VERSION 5.8 ;
BUSBITCHARS "[]" ;
DIVIDERCHAR "/" ;
UNITS
    DATABASE MICRONS 1000 ;
END UNITS

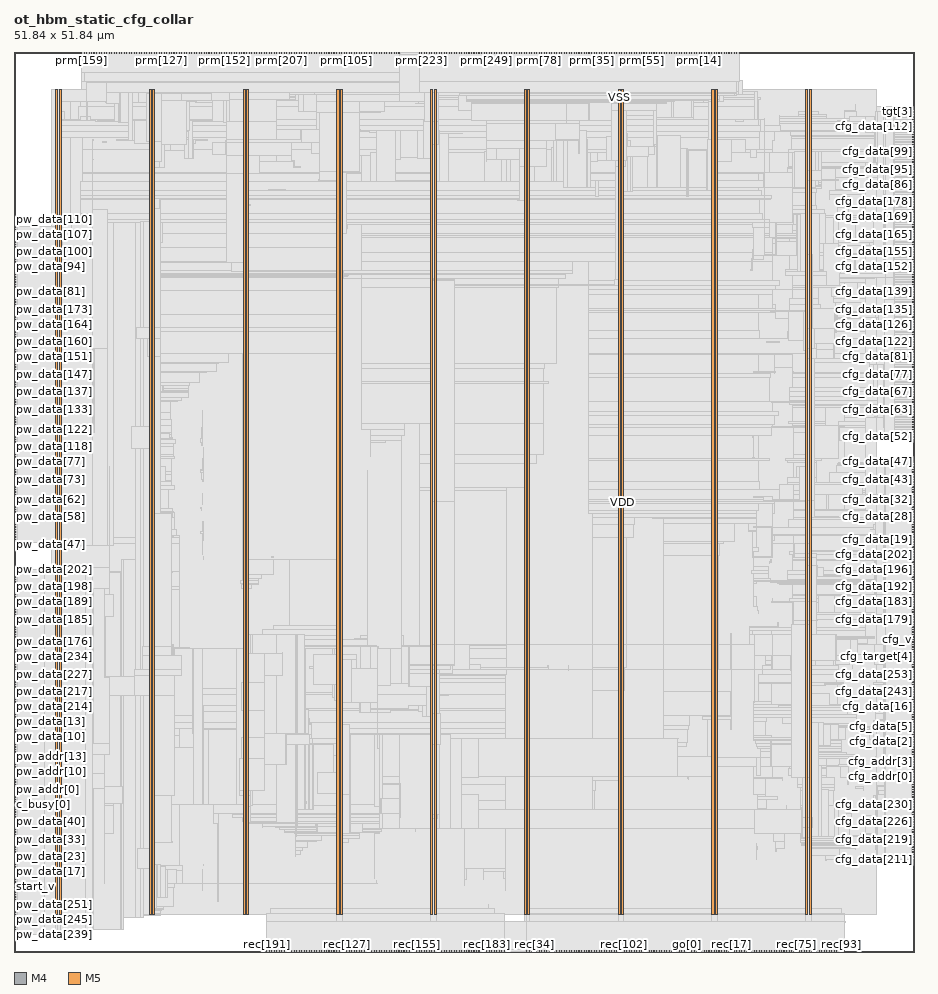
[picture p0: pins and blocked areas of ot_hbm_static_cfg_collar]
MACRO ot_hbm_static_cfg_collar
  FOREIGN ot_hbm_static_cfg_collar 0 0 ;
  CLASS BLOCK ;
  SIZE 51.84 BY 51.84 ;
  PIN active
    DIRECTION OUTPUT ;
    USE SIGNAL ;
    PORT
      LAYER M4 ;
        RECT  51.756 9.936 51.84 9.96 ;
    END
  END active
  PIN c_busy[0]
    DIRECTION INPUT ;
    USE SIGNAL ;
    PORT
      LAYER M4 ;
        RECT  0 8.496 0.084 8.52 ;
    END
  END c_busy[0]
  PIN c_busy[1]
    DIRECTION INPUT ;
    USE SIGNAL ;
    PORT
      LAYER M4 ;
        RECT  0 8.64 0.084 8.664 ;
    END
  END c_busy[1]
  PIN c_done
    DIRECTION INPUT ;
    USE SIGNAL ;
    PORT
      LAYER M4 ;
        RECT  0 8.784 0.084 8.808 ;
    END
  END c_done
  PIN c_fault[0]
    DIRECTION INPUT ;
    USE SIGNAL ;
    PORT
      LAYER M5 ;
        RECT  37.296 51.756 37.32 51.84 ;
    END
  END c_fault[0]
  PIN cfg_addr[0]
    DIRECTION INPUT ;
    USE SIGNAL ;
    PORT
      LAYER M4 ;
        RECT  51.756 10.08 51.84 10.104 ;
    END
  END cfg_addr[0]
  PIN cfg_addr[10]
    DIRECTION INPUT ;
    USE SIGNAL ;
    PORT
      LAYER M4 ;
        RECT  51.756 11.52 51.84 11.544 ;
    END
  END cfg_addr[10]
  PIN cfg_addr[11]
    DIRECTION INPUT ;
    USE SIGNAL ;
    PORT
      LAYER M4 ;
        RECT  51.756 11.664 51.84 11.688 ;
    END
  END cfg_addr[11]
  PIN cfg_addr[1]
    DIRECTION INPUT ;
    USE SIGNAL ;
    PORT
      LAYER M4 ;
        RECT  51.756 10.224 51.84 10.248 ;
    END
  END cfg_addr[1]
  PIN cfg_addr[2]
    DIRECTION INPUT ;
    USE SIGNAL ;
    PORT
      LAYER M4 ;
        RECT  51.756 10.368 51.84 10.392 ;
    END
  END cfg_addr[2]
  PIN cfg_addr[3]
    DIRECTION INPUT ;
    USE SIGNAL ;
    PORT
      LAYER M4 ;
        RECT  51.756 10.512 51.84 10.536 ;
    END
  END cfg_addr[3]
  PIN cfg_addr[4]
    DIRECTION INPUT ;
    USE SIGNAL ;
    PORT
      LAYER M4 ;
        RECT  51.756 10.656 51.84 10.68 ;
    END
  END cfg_addr[4]
  PIN cfg_addr[5]
    DIRECTION INPUT ;
    USE SIGNAL ;
    PORT
      LAYER M4 ;
        RECT  51.756 10.8 51.84 10.824 ;
    END
  END cfg_addr[5]
  PIN cfg_addr[6]
    DIRECTION INPUT ;
    USE SIGNAL ;
    PORT
      LAYER M4 ;
        RECT  51.756 10.944 51.84 10.968 ;
    END
  END cfg_addr[6]
  PIN cfg_addr[7]
    DIRECTION INPUT ;
    USE SIGNAL ;
    PORT
      LAYER M4 ;
        RECT  51.756 11.088 51.84 11.112 ;
    END
  END cfg_addr[7]
  PIN cfg_addr[8]
    DIRECTION INPUT ;
    USE SIGNAL ;
    PORT
      LAYER M4 ;
        RECT  51.756 11.232 51.84 11.256 ;
    END
  END cfg_addr[8]
  PIN cfg_addr[9]
    DIRECTION INPUT ;
    USE SIGNAL ;
    PORT
      LAYER M4 ;
        RECT  51.756 11.376 51.84 11.4 ;
    END
  END cfg_addr[9]
  PIN cfg_data[0]
    DIRECTION INPUT ;
    USE SIGNAL ;
    PORT
      LAYER M4 ;
        RECT  51.756 11.808 51.84 11.832 ;
    END
  END cfg_data[0]
  PIN cfg_data[100]
    DIRECTION INPUT ;
    USE SIGNAL ;
    PORT
      LAYER M4 ;
        RECT  51.756 45.792 51.84 45.816 ;
    END
  END cfg_data[100]
  PIN cfg_data[101]
    DIRECTION INPUT ;
    USE SIGNAL ;
    PORT
      LAYER M4 ;
        RECT  51.756 45.936 51.84 45.96 ;
    END
  END cfg_data[101]
  PIN cfg_data[102]
    DIRECTION INPUT ;
    USE SIGNAL ;
    PORT
      LAYER M4 ;
        RECT  51.756 46.08 51.84 46.104 ;
    END
  END cfg_data[102]
  PIN cfg_data[103]
    DIRECTION INPUT ;
    USE SIGNAL ;
    PORT
      LAYER M4 ;
        RECT  51.756 46.224 51.84 46.248 ;
    END
  END cfg_data[103]
  PIN cfg_data[104]
    DIRECTION INPUT ;
    USE SIGNAL ;
    PORT
      LAYER M4 ;
        RECT  51.756 46.368 51.84 46.392 ;
    END
  END cfg_data[104]
  PIN cfg_data[105]
    DIRECTION INPUT ;
    USE SIGNAL ;
    PORT
      LAYER M4 ;
        RECT  51.756 46.512 51.84 46.536 ;
    END
  END cfg_data[105]
  PIN cfg_data[106]
    DIRECTION INPUT ;
    USE SIGNAL ;
    PORT
      LAYER M4 ;
        RECT  51.756 46.656 51.84 46.68 ;
    END
  END cfg_data[106]
  PIN cfg_data[107]
    DIRECTION INPUT ;
    USE SIGNAL ;
    PORT
      LAYER M4 ;
        RECT  51.756 46.8 51.84 46.824 ;
    END
  END cfg_data[107]
  PIN cfg_data[108]
    DIRECTION INPUT ;
    USE SIGNAL ;
    PORT
      LAYER M4 ;
        RECT  51.756 46.944 51.84 46.968 ;
    END
  END cfg_data[108]
  PIN cfg_data[109]
    DIRECTION INPUT ;
    USE SIGNAL ;
    PORT
      LAYER M4 ;
        RECT  51.756 47.088 51.84 47.112 ;
    END
  END cfg_data[109]
  PIN cfg_data[10]
    DIRECTION INPUT ;
    USE SIGNAL ;
    PORT
      LAYER M4 ;
        RECT  51.756 13.248 51.84 13.272 ;
    END
  END cfg_data[10]
  PIN cfg_data[110]
    DIRECTION INPUT ;
    USE SIGNAL ;
    PORT
      LAYER M4 ;
        RECT  51.756 47.232 51.84 47.256 ;
    END
  END cfg_data[110]
  PIN cfg_data[111]
    DIRECTION INPUT ;
    USE SIGNAL ;
    PORT
      LAYER M4 ;
        RECT  51.756 47.376 51.84 47.4 ;
    END
  END cfg_data[111]
  PIN cfg_data[112]
    DIRECTION INPUT ;
    USE SIGNAL ;
    PORT
      LAYER M4 ;
        RECT  51.756 47.52 51.84 47.544 ;
    END
  END cfg_data[112]
  PIN cfg_data[113]
    DIRECTION INPUT ;
    USE SIGNAL ;
    PORT
      LAYER M4 ;
        RECT  51.756 47.664 51.84 47.688 ;
    END
  END cfg_data[113]
  PIN cfg_data[114]
    DIRECTION INPUT ;
    USE SIGNAL ;
    PORT
      LAYER M4 ;
        RECT  51.756 47.808 51.84 47.832 ;
    END
  END cfg_data[114]
  PIN cfg_data[115]
    DIRECTION INPUT ;
    USE SIGNAL ;
    PORT
      LAYER M4 ;
        RECT  51.756 34.128 51.84 34.152 ;
    END
  END cfg_data[115]
  PIN cfg_data[116]
    DIRECTION INPUT ;
    USE SIGNAL ;
    PORT
      LAYER M4 ;
        RECT  51.756 34.272 51.84 34.296 ;
    END
  END cfg_data[116]
  PIN cfg_data[117]
    DIRECTION INPUT ;
    USE SIGNAL ;
    PORT
      LAYER M4 ;
        RECT  51.756 34.416 51.84 34.44 ;
    END
  END cfg_data[117]
  PIN cfg_data[118]
    DIRECTION INPUT ;
    USE SIGNAL ;
    PORT
      LAYER M4 ;
        RECT  51.756 34.56 51.84 34.584 ;
    END
  END cfg_data[118]
  PIN cfg_data[119]
    DIRECTION INPUT ;
    USE SIGNAL ;
    PORT
      LAYER M4 ;
        RECT  51.756 34.704 51.84 34.728 ;
    END
  END cfg_data[119]
  PIN cfg_data[11]
    DIRECTION INPUT ;
    USE SIGNAL ;
    PORT
      LAYER M4 ;
        RECT  51.756 13.392 51.84 13.416 ;
    END
  END cfg_data[11]
  PIN cfg_data[120]
    DIRECTION INPUT ;
    USE SIGNAL ;
    PORT
      LAYER M4 ;
        RECT  51.756 34.848 51.84 34.872 ;
    END
  END cfg_data[120]
  PIN cfg_data[121]
    DIRECTION INPUT ;
    USE SIGNAL ;
    PORT
      LAYER M4 ;
        RECT  51.756 34.992 51.84 35.016 ;
    END
  END cfg_data[121]
  PIN cfg_data[122]
    DIRECTION INPUT ;
    USE SIGNAL ;
    PORT
      LAYER M4 ;
        RECT  51.756 35.136 51.84 35.16 ;
    END
  END cfg_data[122]
  PIN cfg_data[123]
    DIRECTION INPUT ;
    USE SIGNAL ;
    PORT
      LAYER M4 ;
        RECT  51.756 35.28 51.84 35.304 ;
    END
  END cfg_data[123]
  PIN cfg_data[124]
    DIRECTION INPUT ;
    USE SIGNAL ;
    PORT
      LAYER M4 ;
        RECT  51.756 35.424 51.84 35.448 ;
    END
  END cfg_data[124]
  PIN cfg_data[125]
    DIRECTION INPUT ;
    USE SIGNAL ;
    PORT
      LAYER M4 ;
        RECT  51.756 35.568 51.84 35.592 ;
    END
  END cfg_data[125]
  PIN cfg_data[126]
    DIRECTION INPUT ;
    USE SIGNAL ;
    PORT
      LAYER M4 ;
        RECT  51.756 35.712 51.84 35.736 ;
    END
  END cfg_data[126]
  PIN cfg_data[127]
    DIRECTION INPUT ;
    USE SIGNAL ;
    PORT
      LAYER M4 ;
        RECT  51.756 35.856 51.84 35.88 ;
    END
  END cfg_data[127]
  PIN cfg_data[128]
    DIRECTION INPUT ;
    USE SIGNAL ;
    PORT
      LAYER M4 ;
        RECT  51.756 36 51.84 36.024 ;
    END
  END cfg_data[128]
  PIN cfg_data[129]
    DIRECTION INPUT ;
    USE SIGNAL ;
    PORT
      LAYER M4 ;
        RECT  51.756 36.144 51.84 36.168 ;
    END
  END cfg_data[129]
  PIN cfg_data[12]
    DIRECTION INPUT ;
    USE SIGNAL ;
    PORT
      LAYER M4 ;
        RECT  51.756 13.536 51.84 13.56 ;
    END
  END cfg_data[12]
  PIN cfg_data[130]
    DIRECTION INPUT ;
    USE SIGNAL ;
    PORT
      LAYER M4 ;
        RECT  51.756 36.288 51.84 36.312 ;
    END
  END cfg_data[130]
  PIN cfg_data[131]
    DIRECTION INPUT ;
    USE SIGNAL ;
    PORT
      LAYER M4 ;
        RECT  51.756 36.432 51.84 36.456 ;
    END
  END cfg_data[131]
  PIN cfg_data[132]
    DIRECTION INPUT ;
    USE SIGNAL ;
    PORT
      LAYER M4 ;
        RECT  51.756 36.576 51.84 36.6 ;
    END
  END cfg_data[132]
  PIN cfg_data[133]
    DIRECTION INPUT ;
    USE SIGNAL ;
    PORT
      LAYER M4 ;
        RECT  51.756 36.72 51.84 36.744 ;
    END
  END cfg_data[133]
  PIN cfg_data[134]
    DIRECTION INPUT ;
    USE SIGNAL ;
    PORT
      LAYER M4 ;
        RECT  51.756 36.864 51.84 36.888 ;
    END
  END cfg_data[134]
  PIN cfg_data[135]
    DIRECTION INPUT ;
    USE SIGNAL ;
    PORT
      LAYER M4 ;
        RECT  51.756 37.008 51.84 37.032 ;
    END
  END cfg_data[135]
  PIN cfg_data[136]
    DIRECTION INPUT ;
    USE SIGNAL ;
    PORT
      LAYER M4 ;
        RECT  51.756 37.152 51.84 37.176 ;
    END
  END cfg_data[136]
  PIN cfg_data[137]
    DIRECTION INPUT ;
    USE SIGNAL ;
    PORT
      LAYER M4 ;
        RECT  51.756 37.296 51.84 37.32 ;
    END
  END cfg_data[137]
  PIN cfg_data[138]
    DIRECTION INPUT ;
    USE SIGNAL ;
    PORT
      LAYER M4 ;
        RECT  51.756 37.44 51.84 37.464 ;
    END
  END cfg_data[138]
  PIN cfg_data[139]
    DIRECTION INPUT ;
    USE SIGNAL ;
    PORT
      LAYER M4 ;
        RECT  51.756 37.584 51.84 37.608 ;
    END
  END cfg_data[139]
  PIN cfg_data[13]
    DIRECTION INPUT ;
    USE SIGNAL ;
    PORT
      LAYER M4 ;
        RECT  51.756 13.68 51.84 13.704 ;
    END
  END cfg_data[13]
  PIN cfg_data[140]
    DIRECTION INPUT ;
    USE SIGNAL ;
    PORT
      LAYER M4 ;
        RECT  51.756 37.728 51.84 37.752 ;
    END
  END cfg_data[140]
  PIN cfg_data[141]
    DIRECTION INPUT ;
    USE SIGNAL ;
    PORT
      LAYER M4 ;
        RECT  51.756 37.872 51.84 37.896 ;
    END
  END cfg_data[141]
  PIN cfg_data[142]
    DIRECTION INPUT ;
    USE SIGNAL ;
    PORT
      LAYER M4 ;
        RECT  51.756 38.016 51.84 38.04 ;
    END
  END cfg_data[142]
  PIN cfg_data[143]
    DIRECTION INPUT ;
    USE SIGNAL ;
    PORT
      LAYER M4 ;
        RECT  51.756 38.16 51.84 38.184 ;
    END
  END cfg_data[143]
  PIN cfg_data[144]
    DIRECTION INPUT ;
    USE SIGNAL ;
    PORT
      LAYER M4 ;
        RECT  51.756 38.304 51.84 38.328 ;
    END
  END cfg_data[144]
  PIN cfg_data[145]
    DIRECTION INPUT ;
    USE SIGNAL ;
    PORT
      LAYER M4 ;
        RECT  51.756 38.448 51.84 38.472 ;
    END
  END cfg_data[145]
  PIN cfg_data[146]
    DIRECTION INPUT ;
    USE SIGNAL ;
    PORT
      LAYER M4 ;
        RECT  51.756 38.592 51.84 38.616 ;
    END
  END cfg_data[146]
  PIN cfg_data[147]
    DIRECTION INPUT ;
    USE SIGNAL ;
    PORT
      LAYER M4 ;
        RECT  51.756 38.736 51.84 38.76 ;
    END
  END cfg_data[147]
  PIN cfg_data[148]
    DIRECTION INPUT ;
    USE SIGNAL ;
    PORT
      LAYER M4 ;
        RECT  51.756 38.88 51.84 38.904 ;
    END
  END cfg_data[148]
  PIN cfg_data[149]
    DIRECTION INPUT ;
    USE SIGNAL ;
    PORT
      LAYER M4 ;
        RECT  51.756 39.024 51.84 39.048 ;
    END
  END cfg_data[149]
  PIN cfg_data[14]
    DIRECTION INPUT ;
    USE SIGNAL ;
    PORT
      LAYER M4 ;
        RECT  51.756 13.824 51.84 13.848 ;
    END
  END cfg_data[14]
  PIN cfg_data[150]
    DIRECTION INPUT ;
    USE SIGNAL ;
    PORT
      LAYER M4 ;
        RECT  51.756 39.168 51.84 39.192 ;
    END
  END cfg_data[150]
  PIN cfg_data[151]
    DIRECTION INPUT ;
    USE SIGNAL ;
    PORT
      LAYER M4 ;
        RECT  51.756 39.312 51.84 39.336 ;
    END
  END cfg_data[151]
  PIN cfg_data[152]
    DIRECTION INPUT ;
    USE SIGNAL ;
    PORT
      LAYER M4 ;
        RECT  51.756 39.456 51.84 39.48 ;
    END
  END cfg_data[152]
  PIN cfg_data[153]
    DIRECTION INPUT ;
    USE SIGNAL ;
    PORT
      LAYER M4 ;
        RECT  51.756 39.6 51.84 39.624 ;
    END
  END cfg_data[153]
  PIN cfg_data[154]
    DIRECTION INPUT ;
    USE SIGNAL ;
    PORT
      LAYER M4 ;
        RECT  51.756 39.744 51.84 39.768 ;
    END
  END cfg_data[154]
  PIN cfg_data[155]
    DIRECTION INPUT ;
    USE SIGNAL ;
    PORT
      LAYER M4 ;
        RECT  51.756 39.888 51.84 39.912 ;
    END
  END cfg_data[155]
  PIN cfg_data[156]
    DIRECTION INPUT ;
    USE SIGNAL ;
    PORT
      LAYER M4 ;
        RECT  51.756 40.032 51.84 40.056 ;
    END
  END cfg_data[156]
  PIN cfg_data[157]
    DIRECTION INPUT ;
    USE SIGNAL ;
    PORT
      LAYER M4 ;
        RECT  51.756 40.176 51.84 40.2 ;
    END
  END cfg_data[157]
  PIN cfg_data[158]
    DIRECTION INPUT ;
    USE SIGNAL ;
    PORT
      LAYER M4 ;
        RECT  51.756 40.32 51.84 40.344 ;
    END
  END cfg_data[158]
  PIN cfg_data[159]
    DIRECTION INPUT ;
    USE SIGNAL ;
    PORT
      LAYER M4 ;
        RECT  51.756 40.464 51.84 40.488 ;
    END
  END cfg_data[159]
  PIN cfg_data[15]
    DIRECTION INPUT ;
    USE SIGNAL ;
    PORT
      LAYER M4 ;
        RECT  51.756 13.968 51.84 13.992 ;
    END
  END cfg_data[15]
  PIN cfg_data[160]
    DIRECTION INPUT ;
    USE SIGNAL ;
    PORT
      LAYER M4 ;
        RECT  51.756 40.608 51.84 40.632 ;
    END
  END cfg_data[160]
  PIN cfg_data[161]
    DIRECTION INPUT ;
    USE SIGNAL ;
    PORT
      LAYER M4 ;
        RECT  51.756 40.752 51.84 40.776 ;
    END
  END cfg_data[161]
  PIN cfg_data[162]
    DIRECTION INPUT ;
    USE SIGNAL ;
    PORT
      LAYER M4 ;
        RECT  51.756 40.896 51.84 40.92 ;
    END
  END cfg_data[162]
  PIN cfg_data[163]
    DIRECTION INPUT ;
    USE SIGNAL ;
    PORT
      LAYER M4 ;
        RECT  51.756 41.04 51.84 41.064 ;
    END
  END cfg_data[163]
  PIN cfg_data[164]
    DIRECTION INPUT ;
    USE SIGNAL ;
    PORT
      LAYER M4 ;
        RECT  51.756 41.184 51.84 41.208 ;
    END
  END cfg_data[164]
  PIN cfg_data[165]
    DIRECTION INPUT ;
    USE SIGNAL ;
    PORT
      LAYER M4 ;
        RECT  51.756 41.328 51.84 41.352 ;
    END
  END cfg_data[165]
  PIN cfg_data[166]
    DIRECTION INPUT ;
    USE SIGNAL ;
    PORT
      LAYER M4 ;
        RECT  51.756 41.472 51.84 41.496 ;
    END
  END cfg_data[166]
  PIN cfg_data[167]
    DIRECTION INPUT ;
    USE SIGNAL ;
    PORT
      LAYER M4 ;
        RECT  51.756 41.616 51.84 41.64 ;
    END
  END cfg_data[167]
  PIN cfg_data[168]
    DIRECTION INPUT ;
    USE SIGNAL ;
    PORT
      LAYER M4 ;
        RECT  51.756 41.76 51.84 41.784 ;
    END
  END cfg_data[168]
  PIN cfg_data[169]
    DIRECTION INPUT ;
    USE SIGNAL ;
    PORT
      LAYER M4 ;
        RECT  51.756 41.904 51.84 41.928 ;
    END
  END cfg_data[169]
  PIN cfg_data[16]
    DIRECTION INPUT ;
    USE SIGNAL ;
    PORT
      LAYER M4 ;
        RECT  51.756 14.112 51.84 14.136 ;
    END
  END cfg_data[16]
  PIN cfg_data[170]
    DIRECTION INPUT ;
    USE SIGNAL ;
    PORT
      LAYER M4 ;
        RECT  51.756 42.048 51.84 42.072 ;
    END
  END cfg_data[170]
  PIN cfg_data[171]
    DIRECTION INPUT ;
    USE SIGNAL ;
    PORT
      LAYER M4 ;
        RECT  51.756 42.192 51.84 42.216 ;
    END
  END cfg_data[171]
  PIN cfg_data[172]
    DIRECTION INPUT ;
    USE SIGNAL ;
    PORT
      LAYER M4 ;
        RECT  51.756 42.336 51.84 42.36 ;
    END
  END cfg_data[172]
  PIN cfg_data[173]
    DIRECTION INPUT ;
    USE SIGNAL ;
    PORT
      LAYER M4 ;
        RECT  51.756 42.48 51.84 42.504 ;
    END
  END cfg_data[173]
  PIN cfg_data[174]
    DIRECTION INPUT ;
    USE SIGNAL ;
    PORT
      LAYER M4 ;
        RECT  51.756 42.624 51.84 42.648 ;
    END
  END cfg_data[174]
  PIN cfg_data[175]
    DIRECTION INPUT ;
    USE SIGNAL ;
    PORT
      LAYER M4 ;
        RECT  51.756 42.768 51.84 42.792 ;
    END
  END cfg_data[175]
  PIN cfg_data[176]
    DIRECTION INPUT ;
    USE SIGNAL ;
    PORT
      LAYER M4 ;
        RECT  51.756 42.912 51.84 42.936 ;
    END
  END cfg_data[176]
  PIN cfg_data[177]
    DIRECTION INPUT ;
    USE SIGNAL ;
    PORT
      LAYER M4 ;
        RECT  51.756 43.056 51.84 43.08 ;
    END
  END cfg_data[177]
  PIN cfg_data[178]
    DIRECTION INPUT ;
    USE SIGNAL ;
    PORT
      LAYER M4 ;
        RECT  51.756 43.2 51.84 43.224 ;
    END
  END cfg_data[178]
  PIN cfg_data[179]
    DIRECTION INPUT ;
    USE SIGNAL ;
    PORT
      LAYER M4 ;
        RECT  51.756 19.152 51.84 19.176 ;
    END
  END cfg_data[179]
  PIN cfg_data[17]
    DIRECTION INPUT ;
    USE SIGNAL ;
    PORT
      LAYER M4 ;
        RECT  51.756 14.256 51.84 14.28 ;
    END
  END cfg_data[17]
  PIN cfg_data[180]
    DIRECTION INPUT ;
    USE SIGNAL ;
    PORT
      LAYER M4 ;
        RECT  51.756 19.296 51.84 19.32 ;
    END
  END cfg_data[180]
  PIN cfg_data[181]
    DIRECTION INPUT ;
    USE SIGNAL ;
    PORT
      LAYER M4 ;
        RECT  51.756 19.44 51.84 19.464 ;
    END
  END cfg_data[181]
  PIN cfg_data[182]
    DIRECTION INPUT ;
    USE SIGNAL ;
    PORT
      LAYER M4 ;
        RECT  51.756 19.584 51.84 19.608 ;
    END
  END cfg_data[182]
  PIN cfg_data[183]
    DIRECTION INPUT ;
    USE SIGNAL ;
    PORT
      LAYER M4 ;
        RECT  51.756 19.728 51.84 19.752 ;
    END
  END cfg_data[183]
  PIN cfg_data[184]
    DIRECTION INPUT ;
    USE SIGNAL ;
    PORT
      LAYER M4 ;
        RECT  51.756 19.872 51.84 19.896 ;
    END
  END cfg_data[184]
  PIN cfg_data[185]
    DIRECTION INPUT ;
    USE SIGNAL ;
    PORT
      LAYER M4 ;
        RECT  51.756 20.016 51.84 20.04 ;
    END
  END cfg_data[185]
  PIN cfg_data[186]
    DIRECTION INPUT ;
    USE SIGNAL ;
    PORT
      LAYER M4 ;
        RECT  51.756 20.16 51.84 20.184 ;
    END
  END cfg_data[186]
  PIN cfg_data[187]
    DIRECTION INPUT ;
    USE SIGNAL ;
    PORT
      LAYER M4 ;
        RECT  51.756 20.304 51.84 20.328 ;
    END
  END cfg_data[187]
  PIN cfg_data[188]
    DIRECTION INPUT ;
    USE SIGNAL ;
    PORT
      LAYER M4 ;
        RECT  51.756 20.448 51.84 20.472 ;
    END
  END cfg_data[188]
  PIN cfg_data[189]
    DIRECTION INPUT ;
    USE SIGNAL ;
    PORT
      LAYER M4 ;
        RECT  51.756 20.592 51.84 20.616 ;
    END
  END cfg_data[189]
  PIN cfg_data[18]
    DIRECTION INPUT ;
    USE SIGNAL ;
    PORT
      LAYER M4 ;
        RECT  51.756 14.4 51.84 14.424 ;
    END
  END cfg_data[18]
  PIN cfg_data[190]
    DIRECTION INPUT ;
    USE SIGNAL ;
    PORT
      LAYER M4 ;
        RECT  51.756 20.736 51.84 20.76 ;
    END
  END cfg_data[190]
  PIN cfg_data[191]
    DIRECTION INPUT ;
    USE SIGNAL ;
    PORT
      LAYER M4 ;
        RECT  51.756 20.88 51.84 20.904 ;
    END
  END cfg_data[191]
  PIN cfg_data[192]
    DIRECTION INPUT ;
    USE SIGNAL ;
    PORT
      LAYER M4 ;
        RECT  51.756 21.024 51.84 21.048 ;
    END
  END cfg_data[192]
  PIN cfg_data[193]
    DIRECTION INPUT ;
    USE SIGNAL ;
    PORT
      LAYER M4 ;
        RECT  51.756 21.168 51.84 21.192 ;
    END
  END cfg_data[193]
  PIN cfg_data[194]
    DIRECTION INPUT ;
    USE SIGNAL ;
    PORT
      LAYER M4 ;
        RECT  51.756 21.312 51.84 21.336 ;
    END
  END cfg_data[194]
  PIN cfg_data[195]
    DIRECTION INPUT ;
    USE SIGNAL ;
    PORT
      LAYER M4 ;
        RECT  51.756 21.456 51.84 21.48 ;
    END
  END cfg_data[195]
  PIN cfg_data[196]
    DIRECTION INPUT ;
    USE SIGNAL ;
    PORT
      LAYER M4 ;
        RECT  51.756 21.6 51.84 21.624 ;
    END
  END cfg_data[196]
  PIN cfg_data[197]
    DIRECTION INPUT ;
    USE SIGNAL ;
    PORT
      LAYER M4 ;
        RECT  51.756 21.744 51.84 21.768 ;
    END
  END cfg_data[197]
  PIN cfg_data[198]
    DIRECTION INPUT ;
    USE SIGNAL ;
    PORT
      LAYER M4 ;
        RECT  51.756 21.888 51.84 21.912 ;
    END
  END cfg_data[198]
  PIN cfg_data[199]
    DIRECTION INPUT ;
    USE SIGNAL ;
    PORT
      LAYER M4 ;
        RECT  51.756 22.032 51.84 22.056 ;
    END
  END cfg_data[199]
  PIN cfg_data[19]
    DIRECTION INPUT ;
    USE SIGNAL ;
    PORT
      LAYER M4 ;
        RECT  51.756 23.76 51.84 23.784 ;
    END
  END cfg_data[19]
  PIN cfg_data[1]
    DIRECTION INPUT ;
    USE SIGNAL ;
    PORT
      LAYER M4 ;
        RECT  51.756 11.952 51.84 11.976 ;
    END
  END cfg_data[1]
  PIN cfg_data[200]
    DIRECTION INPUT ;
    USE SIGNAL ;
    PORT
      LAYER M4 ;
        RECT  51.756 22.176 51.84 22.2 ;
    END
  END cfg_data[200]
  PIN cfg_data[201]
    DIRECTION INPUT ;
    USE SIGNAL ;
    PORT
      LAYER M4 ;
        RECT  51.756 22.32 51.84 22.344 ;
    END
  END cfg_data[201]
  PIN cfg_data[202]
    DIRECTION INPUT ;
    USE SIGNAL ;
    PORT
      LAYER M4 ;
        RECT  51.756 22.464 51.84 22.488 ;
    END
  END cfg_data[202]
  PIN cfg_data[203]
    DIRECTION INPUT ;
    USE SIGNAL ;
    PORT
      LAYER M4 ;
        RECT  51.756 22.608 51.84 22.632 ;
    END
  END cfg_data[203]
  PIN cfg_data[204]
    DIRECTION INPUT ;
    USE SIGNAL ;
    PORT
      LAYER M4 ;
        RECT  51.756 22.752 51.84 22.776 ;
    END
  END cfg_data[204]
  PIN cfg_data[205]
    DIRECTION INPUT ;
    USE SIGNAL ;
    PORT
      LAYER M4 ;
        RECT  51.756 22.896 51.84 22.92 ;
    END
  END cfg_data[205]
  PIN cfg_data[206]
    DIRECTION INPUT ;
    USE SIGNAL ;
    PORT
      LAYER M4 ;
        RECT  51.756 23.04 51.84 23.064 ;
    END
  END cfg_data[206]
  PIN cfg_data[207]
    DIRECTION INPUT ;
    USE SIGNAL ;
    PORT
      LAYER M4 ;
        RECT  51.756 23.184 51.84 23.208 ;
    END
  END cfg_data[207]
  PIN cfg_data[208]
    DIRECTION INPUT ;
    USE SIGNAL ;
    PORT
      LAYER M4 ;
        RECT  51.756 23.328 51.84 23.352 ;
    END
  END cfg_data[208]
  PIN cfg_data[209]
    DIRECTION INPUT ;
    USE SIGNAL ;
    PORT
      LAYER M4 ;
        RECT  51.756 23.472 51.84 23.496 ;
    END
  END cfg_data[209]
  PIN cfg_data[20]
    DIRECTION INPUT ;
    USE SIGNAL ;
    PORT
      LAYER M4 ;
        RECT  51.756 23.904 51.84 23.928 ;
    END
  END cfg_data[20]
  PIN cfg_data[210]
    DIRECTION INPUT ;
    USE SIGNAL ;
    PORT
      LAYER M4 ;
        RECT  51.756 23.616 51.84 23.64 ;
    END
  END cfg_data[210]
  PIN cfg_data[211]
    DIRECTION INPUT ;
    USE SIGNAL ;
    PORT
      LAYER M4 ;
        RECT  51.756 5.328 51.84 5.352 ;
    END
  END cfg_data[211]
  PIN cfg_data[212]
    DIRECTION INPUT ;
    USE SIGNAL ;
    PORT
      LAYER M4 ;
        RECT  51.756 5.472 51.84 5.496 ;
    END
  END cfg_data[212]
  PIN cfg_data[213]
    DIRECTION INPUT ;
    USE SIGNAL ;
    PORT
      LAYER M4 ;
        RECT  51.756 5.616 51.84 5.64 ;
    END
  END cfg_data[213]
  PIN cfg_data[214]
    DIRECTION INPUT ;
    USE SIGNAL ;
    PORT
      LAYER M4 ;
        RECT  51.756 5.76 51.84 5.784 ;
    END
  END cfg_data[214]
  PIN cfg_data[215]
    DIRECTION INPUT ;
    USE SIGNAL ;
    PORT
      LAYER M4 ;
        RECT  51.756 5.904 51.84 5.928 ;
    END
  END cfg_data[215]
  PIN cfg_data[216]
    DIRECTION INPUT ;
    USE SIGNAL ;
    PORT
      LAYER M4 ;
        RECT  51.756 6.048 51.84 6.072 ;
    END
  END cfg_data[216]
  PIN cfg_data[217]
    DIRECTION INPUT ;
    USE SIGNAL ;
    PORT
      LAYER M4 ;
        RECT  51.756 6.192 51.84 6.216 ;
    END
  END cfg_data[217]
  PIN cfg_data[218]
    DIRECTION INPUT ;
    USE SIGNAL ;
    PORT
      LAYER M4 ;
        RECT  51.756 6.336 51.84 6.36 ;
    END
  END cfg_data[218]
  PIN cfg_data[219]
    DIRECTION INPUT ;
    USE SIGNAL ;
    PORT
      LAYER M4 ;
        RECT  51.756 6.48 51.84 6.504 ;
    END
  END cfg_data[219]
  PIN cfg_data[21]
    DIRECTION INPUT ;
    USE SIGNAL ;
    PORT
      LAYER M4 ;
        RECT  51.756 24.048 51.84 24.072 ;
    END
  END cfg_data[21]
  PIN cfg_data[220]
    DIRECTION INPUT ;
    USE SIGNAL ;
    PORT
      LAYER M4 ;
        RECT  51.756 6.624 51.84 6.648 ;
    END
  END cfg_data[220]
  PIN cfg_data[221]
    DIRECTION INPUT ;
    USE SIGNAL ;
    PORT
      LAYER M4 ;
        RECT  51.756 6.768 51.84 6.792 ;
    END
  END cfg_data[221]
  PIN cfg_data[222]
    DIRECTION INPUT ;
    USE SIGNAL ;
    PORT
      LAYER M4 ;
        RECT  51.756 6.912 51.84 6.936 ;
    END
  END cfg_data[222]
  PIN cfg_data[223]
    DIRECTION INPUT ;
    USE SIGNAL ;
    PORT
      LAYER M4 ;
        RECT  51.756 7.056 51.84 7.08 ;
    END
  END cfg_data[223]
  PIN cfg_data[224]
    DIRECTION INPUT ;
    USE SIGNAL ;
    PORT
      LAYER M4 ;
        RECT  51.756 7.2 51.84 7.224 ;
    END
  END cfg_data[224]
  PIN cfg_data[225]
    DIRECTION INPUT ;
    USE SIGNAL ;
    PORT
      LAYER M4 ;
        RECT  51.756 7.344 51.84 7.368 ;
    END
  END cfg_data[225]
  PIN cfg_data[226]
    DIRECTION INPUT ;
    USE SIGNAL ;
    PORT
      LAYER M4 ;
        RECT  51.756 7.488 51.84 7.512 ;
    END
  END cfg_data[226]
  PIN cfg_data[227]
    DIRECTION INPUT ;
    USE SIGNAL ;
    PORT
      LAYER M4 ;
        RECT  51.756 7.632 51.84 7.656 ;
    END
  END cfg_data[227]
  PIN cfg_data[228]
    DIRECTION INPUT ;
    USE SIGNAL ;
    PORT
      LAYER M4 ;
        RECT  51.756 7.776 51.84 7.8 ;
    END
  END cfg_data[228]
  PIN cfg_data[229]
    DIRECTION INPUT ;
    USE SIGNAL ;
    PORT
      LAYER M4 ;
        RECT  51.756 7.92 51.84 7.944 ;
    END
  END cfg_data[229]
  PIN cfg_data[22]
    DIRECTION INPUT ;
    USE SIGNAL ;
    PORT
      LAYER M4 ;
        RECT  51.756 24.192 51.84 24.216 ;
    END
  END cfg_data[22]
  PIN cfg_data[230]
    DIRECTION INPUT ;
    USE SIGNAL ;
    PORT
      LAYER M4 ;
        RECT  51.756 8.064 51.84 8.088 ;
    END
  END cfg_data[230]
  PIN cfg_data[231]
    DIRECTION INPUT ;
    USE SIGNAL ;
    PORT
      LAYER M4 ;
        RECT  51.756 8.208 51.84 8.232 ;
    END
  END cfg_data[231]
  PIN cfg_data[232]
    DIRECTION INPUT ;
    USE SIGNAL ;
    PORT
      LAYER M4 ;
        RECT  51.756 8.352 51.84 8.376 ;
    END
  END cfg_data[232]
  PIN cfg_data[233]
    DIRECTION INPUT ;
    USE SIGNAL ;
    PORT
      LAYER M4 ;
        RECT  51.756 8.496 51.84 8.52 ;
    END
  END cfg_data[233]
  PIN cfg_data[234]
    DIRECTION INPUT ;
    USE SIGNAL ;
    PORT
      LAYER M4 ;
        RECT  51.756 8.64 51.84 8.664 ;
    END
  END cfg_data[234]
  PIN cfg_data[235]
    DIRECTION INPUT ;
    USE SIGNAL ;
    PORT
      LAYER M4 ;
        RECT  51.756 8.784 51.84 8.808 ;
    END
  END cfg_data[235]
  PIN cfg_data[236]
    DIRECTION INPUT ;
    USE SIGNAL ;
    PORT
      LAYER M4 ;
        RECT  51.756 8.928 51.84 8.952 ;
    END
  END cfg_data[236]
  PIN cfg_data[237]
    DIRECTION INPUT ;
    USE SIGNAL ;
    PORT
      LAYER M4 ;
        RECT  51.756 9.072 51.84 9.096 ;
    END
  END cfg_data[237]
  PIN cfg_data[238]
    DIRECTION INPUT ;
    USE SIGNAL ;
    PORT
      LAYER M4 ;
        RECT  51.756 9.216 51.84 9.24 ;
    END
  END cfg_data[238]
  PIN cfg_data[239]
    DIRECTION INPUT ;
    USE SIGNAL ;
    PORT
      LAYER M4 ;
        RECT  51.756 9.36 51.84 9.384 ;
    END
  END cfg_data[239]
  PIN cfg_data[23]
    DIRECTION INPUT ;
    USE SIGNAL ;
    PORT
      LAYER M4 ;
        RECT  51.756 24.336 51.84 24.36 ;
    END
  END cfg_data[23]
  PIN cfg_data[240]
    DIRECTION INPUT ;
    USE SIGNAL ;
    PORT
      LAYER M4 ;
        RECT  51.756 9.504 51.84 9.528 ;
    END
  END cfg_data[240]
  PIN cfg_data[241]
    DIRECTION INPUT ;
    USE SIGNAL ;
    PORT
      LAYER M4 ;
        RECT  51.756 9.648 51.84 9.672 ;
    END
  END cfg_data[241]
  PIN cfg_data[242]
    DIRECTION INPUT ;
    USE SIGNAL ;
    PORT
      LAYER M4 ;
        RECT  51.756 9.792 51.84 9.816 ;
    END
  END cfg_data[242]
  PIN cfg_data[243]
    DIRECTION INPUT ;
    USE SIGNAL ;
    PORT
      LAYER M4 ;
        RECT  51.756 14.544 51.84 14.568 ;
    END
  END cfg_data[243]
  PIN cfg_data[244]
    DIRECTION INPUT ;
    USE SIGNAL ;
    PORT
      LAYER M4 ;
        RECT  51.756 14.688 51.84 14.712 ;
    END
  END cfg_data[244]
  PIN cfg_data[245]
    DIRECTION INPUT ;
    USE SIGNAL ;
    PORT
      LAYER M4 ;
        RECT  51.756 14.832 51.84 14.856 ;
    END
  END cfg_data[245]
  PIN cfg_data[246]
    DIRECTION INPUT ;
    USE SIGNAL ;
    PORT
      LAYER M4 ;
        RECT  51.756 14.976 51.84 15 ;
    END
  END cfg_data[246]
  PIN cfg_data[247]
    DIRECTION INPUT ;
    USE SIGNAL ;
    PORT
      LAYER M4 ;
        RECT  51.756 15.12 51.84 15.144 ;
    END
  END cfg_data[247]
  PIN cfg_data[248]
    DIRECTION INPUT ;
    USE SIGNAL ;
    PORT
      LAYER M4 ;
        RECT  51.756 15.264 51.84 15.288 ;
    END
  END cfg_data[248]
  PIN cfg_data[249]
    DIRECTION INPUT ;
    USE SIGNAL ;
    PORT
      LAYER M4 ;
        RECT  51.756 15.408 51.84 15.432 ;
    END
  END cfg_data[249]
  PIN cfg_data[24]
    DIRECTION INPUT ;
    USE SIGNAL ;
    PORT
      LAYER M4 ;
        RECT  51.756 24.48 51.84 24.504 ;
    END
  END cfg_data[24]
  PIN cfg_data[250]
    DIRECTION INPUT ;
    USE SIGNAL ;
    PORT
      LAYER M4 ;
        RECT  51.756 15.552 51.84 15.576 ;
    END
  END cfg_data[250]
  PIN cfg_data[251]
    DIRECTION INPUT ;
    USE SIGNAL ;
    PORT
      LAYER M4 ;
        RECT  51.756 15.696 51.84 15.72 ;
    END
  END cfg_data[251]
  PIN cfg_data[252]
    DIRECTION INPUT ;
    USE SIGNAL ;
    PORT
      LAYER M4 ;
        RECT  51.756 15.84 51.84 15.864 ;
    END
  END cfg_data[252]
  PIN cfg_data[253]
    DIRECTION INPUT ;
    USE SIGNAL ;
    PORT
      LAYER M4 ;
        RECT  51.756 15.984 51.84 16.008 ;
    END
  END cfg_data[253]
  PIN cfg_data[254]
    DIRECTION INPUT ;
    USE SIGNAL ;
    PORT
      LAYER M4 ;
        RECT  51.756 16.128 51.84 16.152 ;
    END
  END cfg_data[254]
  PIN cfg_data[255]
    DIRECTION INPUT ;
    USE SIGNAL ;
    PORT
      LAYER M4 ;
        RECT  51.756 16.272 51.84 16.296 ;
    END
  END cfg_data[255]
  PIN cfg_data[25]
    DIRECTION INPUT ;
    USE SIGNAL ;
    PORT
      LAYER M4 ;
        RECT  51.756 24.624 51.84 24.648 ;
    END
  END cfg_data[25]
  PIN cfg_data[26]
    DIRECTION INPUT ;
    USE SIGNAL ;
    PORT
      LAYER M4 ;
        RECT  51.756 24.768 51.84 24.792 ;
    END
  END cfg_data[26]
  PIN cfg_data[27]
    DIRECTION INPUT ;
    USE SIGNAL ;
    PORT
      LAYER M4 ;
        RECT  51.756 24.912 51.84 24.936 ;
    END
  END cfg_data[27]
  PIN cfg_data[28]
    DIRECTION INPUT ;
    USE SIGNAL ;
    PORT
      LAYER M4 ;
        RECT  51.756 25.056 51.84 25.08 ;
    END
  END cfg_data[28]
  PIN cfg_data[29]
    DIRECTION INPUT ;
    USE SIGNAL ;
    PORT
      LAYER M4 ;
        RECT  51.756 25.2 51.84 25.224 ;
    END
  END cfg_data[29]
  PIN cfg_data[2]
    DIRECTION INPUT ;
    USE SIGNAL ;
    PORT
      LAYER M4 ;
        RECT  51.756 12.096 51.84 12.12 ;
    END
  END cfg_data[2]
  PIN cfg_data[30]
    DIRECTION INPUT ;
    USE SIGNAL ;
    PORT
      LAYER M4 ;
        RECT  51.756 25.344 51.84 25.368 ;
    END
  END cfg_data[30]
  PIN cfg_data[31]
    DIRECTION INPUT ;
    USE SIGNAL ;
    PORT
      LAYER M4 ;
        RECT  51.756 25.488 51.84 25.512 ;
    END
  END cfg_data[31]
  PIN cfg_data[32]
    DIRECTION INPUT ;
    USE SIGNAL ;
    PORT
      LAYER M4 ;
        RECT  51.756 25.632 51.84 25.656 ;
    END
  END cfg_data[32]
  PIN cfg_data[33]
    DIRECTION INPUT ;
    USE SIGNAL ;
    PORT
      LAYER M4 ;
        RECT  51.756 25.776 51.84 25.8 ;
    END
  END cfg_data[33]
  PIN cfg_data[34]
    DIRECTION INPUT ;
    USE SIGNAL ;
    PORT
      LAYER M4 ;
        RECT  51.756 25.92 51.84 25.944 ;
    END
  END cfg_data[34]
  PIN cfg_data[35]
    DIRECTION INPUT ;
    USE SIGNAL ;
    PORT
      LAYER M4 ;
        RECT  51.756 26.064 51.84 26.088 ;
    END
  END cfg_data[35]
  PIN cfg_data[36]
    DIRECTION INPUT ;
    USE SIGNAL ;
    PORT
      LAYER M4 ;
        RECT  51.756 26.208 51.84 26.232 ;
    END
  END cfg_data[36]
  PIN cfg_data[37]
    DIRECTION INPUT ;
    USE SIGNAL ;
    PORT
      LAYER M4 ;
        RECT  51.756 26.352 51.84 26.376 ;
    END
  END cfg_data[37]
  PIN cfg_data[38]
    DIRECTION INPUT ;
    USE SIGNAL ;
    PORT
      LAYER M4 ;
        RECT  51.756 26.496 51.84 26.52 ;
    END
  END cfg_data[38]
  PIN cfg_data[39]
    DIRECTION INPUT ;
    USE SIGNAL ;
    PORT
      LAYER M4 ;
        RECT  51.756 26.64 51.84 26.664 ;
    END
  END cfg_data[39]
  PIN cfg_data[3]
    DIRECTION INPUT ;
    USE SIGNAL ;
    PORT
      LAYER M4 ;
        RECT  51.756 12.24 51.84 12.264 ;
    END
  END cfg_data[3]
  PIN cfg_data[40]
    DIRECTION INPUT ;
    USE SIGNAL ;
    PORT
      LAYER M4 ;
        RECT  51.756 26.784 51.84 26.808 ;
    END
  END cfg_data[40]
  PIN cfg_data[41]
    DIRECTION INPUT ;
    USE SIGNAL ;
    PORT
      LAYER M4 ;
        RECT  51.756 26.928 51.84 26.952 ;
    END
  END cfg_data[41]
  PIN cfg_data[42]
    DIRECTION INPUT ;
    USE SIGNAL ;
    PORT
      LAYER M4 ;
        RECT  51.756 27.072 51.84 27.096 ;
    END
  END cfg_data[42]
  PIN cfg_data[43]
    DIRECTION INPUT ;
    USE SIGNAL ;
    PORT
      LAYER M4 ;
        RECT  51.756 27.216 51.84 27.24 ;
    END
  END cfg_data[43]
  PIN cfg_data[44]
    DIRECTION INPUT ;
    USE SIGNAL ;
    PORT
      LAYER M4 ;
        RECT  51.756 27.36 51.84 27.384 ;
    END
  END cfg_data[44]
  PIN cfg_data[45]
    DIRECTION INPUT ;
    USE SIGNAL ;
    PORT
      LAYER M4 ;
        RECT  51.756 27.504 51.84 27.528 ;
    END
  END cfg_data[45]
  PIN cfg_data[46]
    DIRECTION INPUT ;
    USE SIGNAL ;
    PORT
      LAYER M4 ;
        RECT  51.756 27.648 51.84 27.672 ;
    END
  END cfg_data[46]
  PIN cfg_data[47]
    DIRECTION INPUT ;
    USE SIGNAL ;
    PORT
      LAYER M4 ;
        RECT  51.756 27.792 51.84 27.816 ;
    END
  END cfg_data[47]
  PIN cfg_data[48]
    DIRECTION INPUT ;
    USE SIGNAL ;
    PORT
      LAYER M4 ;
        RECT  51.756 27.936 51.84 27.96 ;
    END
  END cfg_data[48]
  PIN cfg_data[49]
    DIRECTION INPUT ;
    USE SIGNAL ;
    PORT
      LAYER M4 ;
        RECT  51.756 28.08 51.84 28.104 ;
    END
  END cfg_data[49]
  PIN cfg_data[4]
    DIRECTION INPUT ;
    USE SIGNAL ;
    PORT
      LAYER M4 ;
        RECT  51.756 12.384 51.84 12.408 ;
    END
  END cfg_data[4]
  PIN cfg_data[50]
    DIRECTION INPUT ;
    USE SIGNAL ;
    PORT
      LAYER M4 ;
        RECT  51.756 28.224 51.84 28.248 ;
    END
  END cfg_data[50]
  PIN cfg_data[51]
    DIRECTION INPUT ;
    USE SIGNAL ;
    PORT
      LAYER M4 ;
        RECT  51.756 29.52 51.84 29.544 ;
    END
  END cfg_data[51]
  PIN cfg_data[52]
    DIRECTION INPUT ;
    USE SIGNAL ;
    PORT
      LAYER M4 ;
        RECT  51.756 29.664 51.84 29.688 ;
    END
  END cfg_data[52]
  PIN cfg_data[53]
    DIRECTION INPUT ;
    USE SIGNAL ;
    PORT
      LAYER M4 ;
        RECT  51.756 29.808 51.84 29.832 ;
    END
  END cfg_data[53]
  PIN cfg_data[54]
    DIRECTION INPUT ;
    USE SIGNAL ;
    PORT
      LAYER M4 ;
        RECT  51.756 29.952 51.84 29.976 ;
    END
  END cfg_data[54]
  PIN cfg_data[55]
    DIRECTION INPUT ;
    USE SIGNAL ;
    PORT
      LAYER M4 ;
        RECT  51.756 30.096 51.84 30.12 ;
    END
  END cfg_data[55]
  PIN cfg_data[56]
    DIRECTION INPUT ;
    USE SIGNAL ;
    PORT
      LAYER M4 ;
        RECT  51.756 30.24 51.84 30.264 ;
    END
  END cfg_data[56]
  PIN cfg_data[57]
    DIRECTION INPUT ;
    USE SIGNAL ;
    PORT
      LAYER M4 ;
        RECT  51.756 30.384 51.84 30.408 ;
    END
  END cfg_data[57]
  PIN cfg_data[58]
    DIRECTION INPUT ;
    USE SIGNAL ;
    PORT
      LAYER M4 ;
        RECT  51.756 30.528 51.84 30.552 ;
    END
  END cfg_data[58]
  PIN cfg_data[59]
    DIRECTION INPUT ;
    USE SIGNAL ;
    PORT
      LAYER M4 ;
        RECT  51.756 30.672 51.84 30.696 ;
    END
  END cfg_data[59]
  PIN cfg_data[5]
    DIRECTION INPUT ;
    USE SIGNAL ;
    PORT
      LAYER M4 ;
        RECT  51.756 12.528 51.84 12.552 ;
    END
  END cfg_data[5]
  PIN cfg_data[60]
    DIRECTION INPUT ;
    USE SIGNAL ;
    PORT
      LAYER M4 ;
        RECT  51.756 30.816 51.84 30.84 ;
    END
  END cfg_data[60]
  PIN cfg_data[61]
    DIRECTION INPUT ;
    USE SIGNAL ;
    PORT
      LAYER M4 ;
        RECT  51.756 30.96 51.84 30.984 ;
    END
  END cfg_data[61]
  PIN cfg_data[62]
    DIRECTION INPUT ;
    USE SIGNAL ;
    PORT
      LAYER M4 ;
        RECT  51.756 31.104 51.84 31.128 ;
    END
  END cfg_data[62]
  PIN cfg_data[63]
    DIRECTION INPUT ;
    USE SIGNAL ;
    PORT
      LAYER M4 ;
        RECT  51.756 31.248 51.84 31.272 ;
    END
  END cfg_data[63]
  PIN cfg_data[64]
    DIRECTION INPUT ;
    USE SIGNAL ;
    PORT
      LAYER M4 ;
        RECT  51.756 31.392 51.84 31.416 ;
    END
  END cfg_data[64]
  PIN cfg_data[65]
    DIRECTION INPUT ;
    USE SIGNAL ;
    PORT
      LAYER M4 ;
        RECT  51.756 31.536 51.84 31.56 ;
    END
  END cfg_data[65]
  PIN cfg_data[66]
    DIRECTION INPUT ;
    USE SIGNAL ;
    PORT
      LAYER M4 ;
        RECT  51.756 31.68 51.84 31.704 ;
    END
  END cfg_data[66]
  PIN cfg_data[67]
    DIRECTION INPUT ;
    USE SIGNAL ;
    PORT
      LAYER M4 ;
        RECT  51.756 31.824 51.84 31.848 ;
    END
  END cfg_data[67]
  PIN cfg_data[68]
    DIRECTION INPUT ;
    USE SIGNAL ;
    PORT
      LAYER M4 ;
        RECT  51.756 31.968 51.84 31.992 ;
    END
  END cfg_data[68]
  PIN cfg_data[69]
    DIRECTION INPUT ;
    USE SIGNAL ;
    PORT
      LAYER M4 ;
        RECT  51.756 32.112 51.84 32.136 ;
    END
  END cfg_data[69]
  PIN cfg_data[6]
    DIRECTION INPUT ;
    USE SIGNAL ;
    PORT
      LAYER M4 ;
        RECT  51.756 12.672 51.84 12.696 ;
    END
  END cfg_data[6]
  PIN cfg_data[70]
    DIRECTION INPUT ;
    USE SIGNAL ;
    PORT
      LAYER M4 ;
        RECT  51.756 32.256 51.84 32.28 ;
    END
  END cfg_data[70]
  PIN cfg_data[71]
    DIRECTION INPUT ;
    USE SIGNAL ;
    PORT
      LAYER M4 ;
        RECT  51.756 32.4 51.84 32.424 ;
    END
  END cfg_data[71]
  PIN cfg_data[72]
    DIRECTION INPUT ;
    USE SIGNAL ;
    PORT
      LAYER M4 ;
        RECT  51.756 32.544 51.84 32.568 ;
    END
  END cfg_data[72]
  PIN cfg_data[73]
    DIRECTION INPUT ;
    USE SIGNAL ;
    PORT
      LAYER M4 ;
        RECT  51.756 32.688 51.84 32.712 ;
    END
  END cfg_data[73]
  PIN cfg_data[74]
    DIRECTION INPUT ;
    USE SIGNAL ;
    PORT
      LAYER M4 ;
        RECT  51.756 32.832 51.84 32.856 ;
    END
  END cfg_data[74]
  PIN cfg_data[75]
    DIRECTION INPUT ;
    USE SIGNAL ;
    PORT
      LAYER M4 ;
        RECT  51.756 32.976 51.84 33 ;
    END
  END cfg_data[75]
  PIN cfg_data[76]
    DIRECTION INPUT ;
    USE SIGNAL ;
    PORT
      LAYER M4 ;
        RECT  51.756 33.12 51.84 33.144 ;
    END
  END cfg_data[76]
  PIN cfg_data[77]
    DIRECTION INPUT ;
    USE SIGNAL ;
    PORT
      LAYER M4 ;
        RECT  51.756 33.264 51.84 33.288 ;
    END
  END cfg_data[77]
  PIN cfg_data[78]
    DIRECTION INPUT ;
    USE SIGNAL ;
    PORT
      LAYER M4 ;
        RECT  51.756 33.408 51.84 33.432 ;
    END
  END cfg_data[78]
  PIN cfg_data[79]
    DIRECTION INPUT ;
    USE SIGNAL ;
    PORT
      LAYER M4 ;
        RECT  51.756 33.552 51.84 33.576 ;
    END
  END cfg_data[79]
  PIN cfg_data[7]
    DIRECTION INPUT ;
    USE SIGNAL ;
    PORT
      LAYER M4 ;
        RECT  51.756 12.816 51.84 12.84 ;
    END
  END cfg_data[7]
  PIN cfg_data[80]
    DIRECTION INPUT ;
    USE SIGNAL ;
    PORT
      LAYER M4 ;
        RECT  51.756 33.696 51.84 33.72 ;
    END
  END cfg_data[80]
  PIN cfg_data[81]
    DIRECTION INPUT ;
    USE SIGNAL ;
    PORT
      LAYER M4 ;
        RECT  51.756 33.84 51.84 33.864 ;
    END
  END cfg_data[81]
  PIN cfg_data[82]
    DIRECTION INPUT ;
    USE SIGNAL ;
    PORT
      LAYER M4 ;
        RECT  51.756 33.984 51.84 34.008 ;
    END
  END cfg_data[82]
  PIN cfg_data[83]
    DIRECTION INPUT ;
    USE SIGNAL ;
    PORT
      LAYER M4 ;
        RECT  51.756 43.344 51.84 43.368 ;
    END
  END cfg_data[83]
  PIN cfg_data[84]
    DIRECTION INPUT ;
    USE SIGNAL ;
    PORT
      LAYER M4 ;
        RECT  51.756 43.488 51.84 43.512 ;
    END
  END cfg_data[84]
  PIN cfg_data[85]
    DIRECTION INPUT ;
    USE SIGNAL ;
    PORT
      LAYER M4 ;
        RECT  51.756 43.632 51.84 43.656 ;
    END
  END cfg_data[85]
  PIN cfg_data[86]
    DIRECTION INPUT ;
    USE SIGNAL ;
    PORT
      LAYER M4 ;
        RECT  51.756 43.776 51.84 43.8 ;
    END
  END cfg_data[86]
  PIN cfg_data[87]
    DIRECTION INPUT ;
    USE SIGNAL ;
    PORT
      LAYER M4 ;
        RECT  51.756 43.92 51.84 43.944 ;
    END
  END cfg_data[87]
  PIN cfg_data[88]
    DIRECTION INPUT ;
    USE SIGNAL ;
    PORT
      LAYER M4 ;
        RECT  51.756 44.064 51.84 44.088 ;
    END
  END cfg_data[88]
  PIN cfg_data[89]
    DIRECTION INPUT ;
    USE SIGNAL ;
    PORT
      LAYER M4 ;
        RECT  51.756 44.208 51.84 44.232 ;
    END
  END cfg_data[89]
  PIN cfg_data[8]
    DIRECTION INPUT ;
    USE SIGNAL ;
    PORT
      LAYER M4 ;
        RECT  51.756 12.96 51.84 12.984 ;
    END
  END cfg_data[8]
  PIN cfg_data[90]
    DIRECTION INPUT ;
    USE SIGNAL ;
    PORT
      LAYER M4 ;
        RECT  51.756 44.352 51.84 44.376 ;
    END
  END cfg_data[90]
  PIN cfg_data[91]
    DIRECTION INPUT ;
    USE SIGNAL ;
    PORT
      LAYER M4 ;
        RECT  51.756 44.496 51.84 44.52 ;
    END
  END cfg_data[91]
  PIN cfg_data[92]
    DIRECTION INPUT ;
    USE SIGNAL ;
    PORT
      LAYER M4 ;
        RECT  51.756 44.64 51.84 44.664 ;
    END
  END cfg_data[92]
  PIN cfg_data[93]
    DIRECTION INPUT ;
    USE SIGNAL ;
    PORT
      LAYER M4 ;
        RECT  51.756 44.784 51.84 44.808 ;
    END
  END cfg_data[93]
  PIN cfg_data[94]
    DIRECTION INPUT ;
    USE SIGNAL ;
    PORT
      LAYER M4 ;
        RECT  51.756 44.928 51.84 44.952 ;
    END
  END cfg_data[94]
  PIN cfg_data[95]
    DIRECTION INPUT ;
    USE SIGNAL ;
    PORT
      LAYER M4 ;
        RECT  51.756 45.072 51.84 45.096 ;
    END
  END cfg_data[95]
  PIN cfg_data[96]
    DIRECTION INPUT ;
    USE SIGNAL ;
    PORT
      LAYER M4 ;
        RECT  51.756 45.216 51.84 45.24 ;
    END
  END cfg_data[96]
  PIN cfg_data[97]
    DIRECTION INPUT ;
    USE SIGNAL ;
    PORT
      LAYER M4 ;
        RECT  51.756 45.36 51.84 45.384 ;
    END
  END cfg_data[97]
  PIN cfg_data[98]
    DIRECTION INPUT ;
    USE SIGNAL ;
    PORT
      LAYER M4 ;
        RECT  51.756 45.504 51.84 45.528 ;
    END
  END cfg_data[98]
  PIN cfg_data[99]
    DIRECTION INPUT ;
    USE SIGNAL ;
    PORT
      LAYER M4 ;
        RECT  51.756 45.648 51.84 45.672 ;
    END
  END cfg_data[99]
  PIN cfg_data[9]
    DIRECTION INPUT ;
    USE SIGNAL ;
    PORT
      LAYER M4 ;
        RECT  51.756 13.104 51.84 13.128 ;
    END
  END cfg_data[9]
  PIN cfg_target[0]
    DIRECTION INPUT ;
    USE SIGNAL ;
    PORT
      LAYER M4 ;
        RECT  51.756 16.416 51.84 16.44 ;
    END
  END cfg_target[0]
  PIN cfg_target[1]
    DIRECTION INPUT ;
    USE SIGNAL ;
    PORT
      LAYER M4 ;
        RECT  51.756 16.56 51.84 16.584 ;
    END
  END cfg_target[1]
  PIN cfg_target[2]
    DIRECTION INPUT ;
    USE SIGNAL ;
    PORT
      LAYER M4 ;
        RECT  51.756 16.704 51.84 16.728 ;
    END
  END cfg_target[2]
  PIN cfg_target[3]
    DIRECTION INPUT ;
    USE SIGNAL ;
    PORT
      LAYER M4 ;
        RECT  51.756 16.848 51.84 16.872 ;
    END
  END cfg_target[3]
  PIN cfg_target[4]
    DIRECTION INPUT ;
    USE SIGNAL ;
    PORT
      LAYER M4 ;
        RECT  51.756 16.992 51.84 17.016 ;
    END
  END cfg_target[4]
  PIN cfg_target[5]
    DIRECTION INPUT ;
    USE SIGNAL ;
    PORT
      LAYER M4 ;
        RECT  51.756 17.136 51.84 17.16 ;
    END
  END cfg_target[5]
  PIN cfg_target[6]
    DIRECTION INPUT ;
    USE SIGNAL ;
    PORT
      LAYER M4 ;
        RECT  51.756 17.28 51.84 17.304 ;
    END
  END cfg_target[6]
  PIN cfg_target[7]
    DIRECTION INPUT ;
    USE SIGNAL ;
    PORT
      LAYER M4 ;
        RECT  51.756 17.424 51.84 17.448 ;
    END
  END cfg_target[7]
  PIN cfg_v
    DIRECTION INPUT ;
    USE SIGNAL ;
    PORT
      LAYER M4 ;
        RECT  51.756 17.568 51.84 17.592 ;
    END
  END cfg_v
  PIN clk
    DIRECTION INPUT ;
    USE SIGNAL ;
    PORT
      LAYER M4 ;
        RECT  51.756 17.712 51.84 17.736 ;
    END
  END clk
  PIN clk_in
    DIRECTION INPUT ;
    USE SIGNAL ;
    PORT
      LAYER M4 ;
        RECT  51.756 17.856 51.84 17.88 ;
    END
  END clk_in
  PIN desc_v
    DIRECTION INPUT ;
    USE SIGNAL ;
    PORT
      LAYER M4 ;
        RECT  51.756 18 51.84 18.024 ;
    END
  END desc_v
  PIN fault
    DIRECTION OUTPUT ;
    USE SIGNAL ;
    PORT
      LAYER M4 ;
        RECT  51.756 18.144 51.84 18.168 ;
    END
  END fault
  PIN go[0]
    DIRECTION OUTPUT ;
    USE SIGNAL ;
    PORT
      LAYER M5 ;
        RECT  38.736 0 38.76 0.084 ;
    END
  END go[0]
  PIN launch_v
    DIRECTION INPUT ;
    USE SIGNAL ;
    PORT
      LAYER M4 ;
        RECT  51.756 18.288 51.84 18.312 ;
    END
  END launch_v
  PIN prm[0]
    DIRECTION OUTPUT ;
    USE SIGNAL ;
    PORT
      LAYER M5 ;
        RECT  37.44 51.756 37.464 51.84 ;
    END
  END prm[0]
  PIN prm[100]
    DIRECTION OUTPUT ;
    USE SIGNAL ;
    PORT
      LAYER M5 ;
        RECT  18.432 51.756 18.456 51.84 ;
    END
  END prm[100]
  PIN prm[101]
    DIRECTION OUTPUT ;
    USE SIGNAL ;
    PORT
      LAYER M5 ;
        RECT  18.576 51.756 18.6 51.84 ;
    END
  END prm[101]
  PIN prm[102]
    DIRECTION OUTPUT ;
    USE SIGNAL ;
    PORT
      LAYER M5 ;
        RECT  18.72 51.756 18.744 51.84 ;
    END
  END prm[102]
  PIN prm[103]
    DIRECTION OUTPUT ;
    USE SIGNAL ;
    PORT
      LAYER M5 ;
        RECT  18.864 51.756 18.888 51.84 ;
    END
  END prm[103]
  PIN prm[104]
    DIRECTION OUTPUT ;
    USE SIGNAL ;
    PORT
      LAYER M5 ;
        RECT  19.008 51.756 19.032 51.84 ;
    END
  END prm[104]
  PIN prm[105]
    DIRECTION OUTPUT ;
    USE SIGNAL ;
    PORT
      LAYER M5 ;
        RECT  19.152 51.756 19.176 51.84 ;
    END
  END prm[105]
  PIN prm[106]
    DIRECTION OUTPUT ;
    USE SIGNAL ;
    PORT
      LAYER M5 ;
        RECT  19.296 51.756 19.32 51.84 ;
    END
  END prm[106]
  PIN prm[107]
    DIRECTION OUTPUT ;
    USE SIGNAL ;
    PORT
      LAYER M5 ;
        RECT  19.44 51.756 19.464 51.84 ;
    END
  END prm[107]
  PIN prm[108]
    DIRECTION OUTPUT ;
    USE SIGNAL ;
    PORT
      LAYER M5 ;
        RECT  19.584 51.756 19.608 51.84 ;
    END
  END prm[108]
  PIN prm[109]
    DIRECTION OUTPUT ;
    USE SIGNAL ;
    PORT
      LAYER M5 ;
        RECT  19.728 51.756 19.752 51.84 ;
    END
  END prm[109]
  PIN prm[10]
    DIRECTION OUTPUT ;
    USE SIGNAL ;
    PORT
      LAYER M5 ;
        RECT  38.88 51.756 38.904 51.84 ;
    END
  END prm[10]
  PIN prm[110]
    DIRECTION OUTPUT ;
    USE SIGNAL ;
    PORT
      LAYER M5 ;
        RECT  19.872 51.756 19.896 51.84 ;
    END
  END prm[110]
  PIN prm[111]
    DIRECTION OUTPUT ;
    USE SIGNAL ;
    PORT
      LAYER M5 ;
        RECT  20.016 51.756 20.04 51.84 ;
    END
  END prm[111]
  PIN prm[112]
    DIRECTION OUTPUT ;
    USE SIGNAL ;
    PORT
      LAYER M5 ;
        RECT  20.16 51.756 20.184 51.84 ;
    END
  END prm[112]
  PIN prm[113]
    DIRECTION OUTPUT ;
    USE SIGNAL ;
    PORT
      LAYER M5 ;
        RECT  20.304 51.756 20.328 51.84 ;
    END
  END prm[113]
  PIN prm[114]
    DIRECTION OUTPUT ;
    USE SIGNAL ;
    PORT
      LAYER M5 ;
        RECT  20.448 51.756 20.472 51.84 ;
    END
  END prm[114]
  PIN prm[115]
    DIRECTION OUTPUT ;
    USE SIGNAL ;
    PORT
      LAYER M5 ;
        RECT  20.592 51.756 20.616 51.84 ;
    END
  END prm[115]
  PIN prm[116]
    DIRECTION OUTPUT ;
    USE SIGNAL ;
    PORT
      LAYER M5 ;
        RECT  20.736 51.756 20.76 51.84 ;
    END
  END prm[116]
  PIN prm[117]
    DIRECTION OUTPUT ;
    USE SIGNAL ;
    PORT
      LAYER M5 ;
        RECT  20.88 51.756 20.904 51.84 ;
    END
  END prm[117]
  PIN prm[118]
    DIRECTION OUTPUT ;
    USE SIGNAL ;
    PORT
      LAYER M5 ;
        RECT  21.024 51.756 21.048 51.84 ;
    END
  END prm[118]
  PIN prm[119]
    DIRECTION OUTPUT ;
    USE SIGNAL ;
    PORT
      LAYER M5 ;
        RECT  21.168 51.756 21.192 51.84 ;
    END
  END prm[119]
  PIN prm[11]
    DIRECTION OUTPUT ;
    USE SIGNAL ;
    PORT
      LAYER M5 ;
        RECT  39.024 51.756 39.048 51.84 ;
    END
  END prm[11]
  PIN prm[120]
    DIRECTION OUTPUT ;
    USE SIGNAL ;
    PORT
      LAYER M5 ;
        RECT  21.312 51.756 21.336 51.84 ;
    END
  END prm[120]
  PIN prm[121]
    DIRECTION OUTPUT ;
    USE SIGNAL ;
    PORT
      LAYER M5 ;
        RECT  21.456 51.756 21.48 51.84 ;
    END
  END prm[121]
  PIN prm[122]
    DIRECTION OUTPUT ;
    USE SIGNAL ;
    PORT
      LAYER M5 ;
        RECT  21.6 51.756 21.624 51.84 ;
    END
  END prm[122]
  PIN prm[123]
    DIRECTION OUTPUT ;
    USE SIGNAL ;
    PORT
      LAYER M5 ;
        RECT  21.744 51.756 21.768 51.84 ;
    END
  END prm[123]
  PIN prm[124]
    DIRECTION OUTPUT ;
    USE SIGNAL ;
    PORT
      LAYER M5 ;
        RECT  21.888 51.756 21.912 51.84 ;
    END
  END prm[124]
  PIN prm[125]
    DIRECTION OUTPUT ;
    USE SIGNAL ;
    PORT
      LAYER M5 ;
        RECT  22.032 51.756 22.056 51.84 ;
    END
  END prm[125]
  PIN prm[126]
    DIRECTION OUTPUT ;
    USE SIGNAL ;
    PORT
      LAYER M5 ;
        RECT  22.176 51.756 22.2 51.84 ;
    END
  END prm[126]
  PIN prm[127]
    DIRECTION OUTPUT ;
    USE SIGNAL ;
    PORT
      LAYER M5 ;
        RECT  8.496 51.756 8.52 51.84 ;
    END
  END prm[127]
  PIN prm[128]
    DIRECTION OUTPUT ;
    USE SIGNAL ;
    PORT
      LAYER M5 ;
        RECT  8.64 51.756 8.664 51.84 ;
    END
  END prm[128]
  PIN prm[129]
    DIRECTION OUTPUT ;
    USE SIGNAL ;
    PORT
      LAYER M5 ;
        RECT  8.784 51.756 8.808 51.84 ;
    END
  END prm[129]
  PIN prm[12]
    DIRECTION OUTPUT ;
    USE SIGNAL ;
    PORT
      LAYER M5 ;
        RECT  39.168 51.756 39.192 51.84 ;
    END
  END prm[12]
  PIN prm[130]
    DIRECTION OUTPUT ;
    USE SIGNAL ;
    PORT
      LAYER M5 ;
        RECT  8.928 51.756 8.952 51.84 ;
    END
  END prm[130]
  PIN prm[131]
    DIRECTION OUTPUT ;
    USE SIGNAL ;
    PORT
      LAYER M5 ;
        RECT  9.072 51.756 9.096 51.84 ;
    END
  END prm[131]
  PIN prm[132]
    DIRECTION OUTPUT ;
    USE SIGNAL ;
    PORT
      LAYER M5 ;
        RECT  9.216 51.756 9.24 51.84 ;
    END
  END prm[132]
  PIN prm[133]
    DIRECTION OUTPUT ;
    USE SIGNAL ;
    PORT
      LAYER M5 ;
        RECT  9.36 51.756 9.384 51.84 ;
    END
  END prm[133]
  PIN prm[134]
    DIRECTION OUTPUT ;
    USE SIGNAL ;
    PORT
      LAYER M5 ;
        RECT  9.504 51.756 9.528 51.84 ;
    END
  END prm[134]
  PIN prm[135]
    DIRECTION OUTPUT ;
    USE SIGNAL ;
    PORT
      LAYER M5 ;
        RECT  9.648 51.756 9.672 51.84 ;
    END
  END prm[135]
  PIN prm[136]
    DIRECTION OUTPUT ;
    USE SIGNAL ;
    PORT
      LAYER M5 ;
        RECT  9.792 51.756 9.816 51.84 ;
    END
  END prm[136]
  PIN prm[137]
    DIRECTION OUTPUT ;
    USE SIGNAL ;
    PORT
      LAYER M5 ;
        RECT  9.936 51.756 9.96 51.84 ;
    END
  END prm[137]
  PIN prm[138]
    DIRECTION OUTPUT ;
    USE SIGNAL ;
    PORT
      LAYER M5 ;
        RECT  10.08 51.756 10.104 51.84 ;
    END
  END prm[138]
  PIN prm[139]
    DIRECTION OUTPUT ;
    USE SIGNAL ;
    PORT
      LAYER M5 ;
        RECT  10.224 51.756 10.248 51.84 ;
    END
  END prm[139]
  PIN prm[13]
    DIRECTION OUTPUT ;
    USE SIGNAL ;
    PORT
      LAYER M5 ;
        RECT  39.312 51.756 39.336 51.84 ;
    END
  END prm[13]
  PIN prm[140]
    DIRECTION OUTPUT ;
    USE SIGNAL ;
    PORT
      LAYER M5 ;
        RECT  10.368 51.756 10.392 51.84 ;
    END
  END prm[140]
  PIN prm[141]
    DIRECTION OUTPUT ;
    USE SIGNAL ;
    PORT
      LAYER M5 ;
        RECT  10.512 51.756 10.536 51.84 ;
    END
  END prm[141]
  PIN prm[142]
    DIRECTION OUTPUT ;
    USE SIGNAL ;
    PORT
      LAYER M5 ;
        RECT  10.656 51.756 10.68 51.84 ;
    END
  END prm[142]
  PIN prm[143]
    DIRECTION OUTPUT ;
    USE SIGNAL ;
    PORT
      LAYER M5 ;
        RECT  10.8 51.756 10.824 51.84 ;
    END
  END prm[143]
  PIN prm[144]
    DIRECTION OUTPUT ;
    USE SIGNAL ;
    PORT
      LAYER M5 ;
        RECT  10.944 51.756 10.968 51.84 ;
    END
  END prm[144]
  PIN prm[145]
    DIRECTION OUTPUT ;
    USE SIGNAL ;
    PORT
      LAYER M5 ;
        RECT  11.088 51.756 11.112 51.84 ;
    END
  END prm[145]
  PIN prm[146]
    DIRECTION OUTPUT ;
    USE SIGNAL ;
    PORT
      LAYER M5 ;
        RECT  11.232 51.756 11.256 51.84 ;
    END
  END prm[146]
  PIN prm[147]
    DIRECTION OUTPUT ;
    USE SIGNAL ;
    PORT
      LAYER M5 ;
        RECT  11.376 51.756 11.4 51.84 ;
    END
  END prm[147]
  PIN prm[148]
    DIRECTION OUTPUT ;
    USE SIGNAL ;
    PORT
      LAYER M5 ;
        RECT  11.52 51.756 11.544 51.84 ;
    END
  END prm[148]
  PIN prm[149]
    DIRECTION OUTPUT ;
    USE SIGNAL ;
    PORT
      LAYER M5 ;
        RECT  11.664 51.756 11.688 51.84 ;
    END
  END prm[149]
  PIN prm[14]
    DIRECTION OUTPUT ;
    USE SIGNAL ;
    PORT
      LAYER M5 ;
        RECT  39.456 51.756 39.48 51.84 ;
    END
  END prm[14]
  PIN prm[150]
    DIRECTION OUTPUT ;
    USE SIGNAL ;
    PORT
      LAYER M5 ;
        RECT  11.808 51.756 11.832 51.84 ;
    END
  END prm[150]
  PIN prm[151]
    DIRECTION OUTPUT ;
    USE SIGNAL ;
    PORT
      LAYER M5 ;
        RECT  11.952 51.756 11.976 51.84 ;
    END
  END prm[151]
  PIN prm[152]
    DIRECTION OUTPUT ;
    USE SIGNAL ;
    PORT
      LAYER M5 ;
        RECT  12.096 51.756 12.12 51.84 ;
    END
  END prm[152]
  PIN prm[153]
    DIRECTION OUTPUT ;
    USE SIGNAL ;
    PORT
      LAYER M5 ;
        RECT  12.24 51.756 12.264 51.84 ;
    END
  END prm[153]
  PIN prm[154]
    DIRECTION OUTPUT ;
    USE SIGNAL ;
    PORT
      LAYER M5 ;
        RECT  12.384 51.756 12.408 51.84 ;
    END
  END prm[154]
  PIN prm[155]
    DIRECTION OUTPUT ;
    USE SIGNAL ;
    PORT
      LAYER M5 ;
        RECT  12.528 51.756 12.552 51.84 ;
    END
  END prm[155]
  PIN prm[156]
    DIRECTION OUTPUT ;
    USE SIGNAL ;
    PORT
      LAYER M5 ;
        RECT  12.672 51.756 12.696 51.84 ;
    END
  END prm[156]
  PIN prm[157]
    DIRECTION OUTPUT ;
    USE SIGNAL ;
    PORT
      LAYER M5 ;
        RECT  12.816 51.756 12.84 51.84 ;
    END
  END prm[157]
  PIN prm[158]
    DIRECTION OUTPUT ;
    USE SIGNAL ;
    PORT
      LAYER M5 ;
        RECT  12.96 51.756 12.984 51.84 ;
    END
  END prm[158]
  PIN prm[159]
    DIRECTION OUTPUT ;
    USE SIGNAL ;
    PORT
      LAYER M5 ;
        RECT  3.888 51.756 3.912 51.84 ;
    END
  END prm[159]
  PIN prm[15]
    DIRECTION OUTPUT ;
    USE SIGNAL ;
    PORT
      LAYER M5 ;
        RECT  39.6 51.756 39.624 51.84 ;
    END
  END prm[15]
  PIN prm[160]
    DIRECTION OUTPUT ;
    USE SIGNAL ;
    PORT
      LAYER M5 ;
        RECT  4.032 51.756 4.056 51.84 ;
    END
  END prm[160]
  PIN prm[161]
    DIRECTION OUTPUT ;
    USE SIGNAL ;
    PORT
      LAYER M5 ;
        RECT  4.176 51.756 4.2 51.84 ;
    END
  END prm[161]
  PIN prm[162]
    DIRECTION OUTPUT ;
    USE SIGNAL ;
    PORT
      LAYER M5 ;
        RECT  4.32 51.756 4.344 51.84 ;
    END
  END prm[162]
  PIN prm[163]
    DIRECTION OUTPUT ;
    USE SIGNAL ;
    PORT
      LAYER M5 ;
        RECT  4.464 51.756 4.488 51.84 ;
    END
  END prm[163]
  PIN prm[164]
    DIRECTION OUTPUT ;
    USE SIGNAL ;
    PORT
      LAYER M5 ;
        RECT  4.608 51.756 4.632 51.84 ;
    END
  END prm[164]
  PIN prm[165]
    DIRECTION OUTPUT ;
    USE SIGNAL ;
    PORT
      LAYER M5 ;
        RECT  4.752 51.756 4.776 51.84 ;
    END
  END prm[165]
  PIN prm[166]
    DIRECTION OUTPUT ;
    USE SIGNAL ;
    PORT
      LAYER M5 ;
        RECT  4.896 51.756 4.92 51.84 ;
    END
  END prm[166]
  PIN prm[167]
    DIRECTION OUTPUT ;
    USE SIGNAL ;
    PORT
      LAYER M5 ;
        RECT  5.04 51.756 5.064 51.84 ;
    END
  END prm[167]
  PIN prm[168]
    DIRECTION OUTPUT ;
    USE SIGNAL ;
    PORT
      LAYER M5 ;
        RECT  5.184 51.756 5.208 51.84 ;
    END
  END prm[168]
  PIN prm[169]
    DIRECTION OUTPUT ;
    USE SIGNAL ;
    PORT
      LAYER M5 ;
        RECT  5.328 51.756 5.352 51.84 ;
    END
  END prm[169]
  PIN prm[16]
    DIRECTION OUTPUT ;
    USE SIGNAL ;
    PORT
      LAYER M5 ;
        RECT  39.744 51.756 39.768 51.84 ;
    END
  END prm[16]
  PIN prm[170]
    DIRECTION OUTPUT ;
    USE SIGNAL ;
    PORT
      LAYER M5 ;
        RECT  5.472 51.756 5.496 51.84 ;
    END
  END prm[170]
  PIN prm[171]
    DIRECTION OUTPUT ;
    USE SIGNAL ;
    PORT
      LAYER M5 ;
        RECT  5.616 51.756 5.64 51.84 ;
    END
  END prm[171]
  PIN prm[172]
    DIRECTION OUTPUT ;
    USE SIGNAL ;
    PORT
      LAYER M5 ;
        RECT  5.76 51.756 5.784 51.84 ;
    END
  END prm[172]
  PIN prm[173]
    DIRECTION OUTPUT ;
    USE SIGNAL ;
    PORT
      LAYER M5 ;
        RECT  5.904 51.756 5.928 51.84 ;
    END
  END prm[173]
  PIN prm[174]
    DIRECTION OUTPUT ;
    USE SIGNAL ;
    PORT
      LAYER M5 ;
        RECT  6.048 51.756 6.072 51.84 ;
    END
  END prm[174]
  PIN prm[175]
    DIRECTION OUTPUT ;
    USE SIGNAL ;
    PORT
      LAYER M5 ;
        RECT  6.192 51.756 6.216 51.84 ;
    END
  END prm[175]
  PIN prm[176]
    DIRECTION OUTPUT ;
    USE SIGNAL ;
    PORT
      LAYER M5 ;
        RECT  6.336 51.756 6.36 51.84 ;
    END
  END prm[176]
  PIN prm[177]
    DIRECTION OUTPUT ;
    USE SIGNAL ;
    PORT
      LAYER M5 ;
        RECT  6.48 51.756 6.504 51.84 ;
    END
  END prm[177]
  PIN prm[178]
    DIRECTION OUTPUT ;
    USE SIGNAL ;
    PORT
      LAYER M5 ;
        RECT  6.624 51.756 6.648 51.84 ;
    END
  END prm[178]
  PIN prm[179]
    DIRECTION OUTPUT ;
    USE SIGNAL ;
    PORT
      LAYER M5 ;
        RECT  6.768 51.756 6.792 51.84 ;
    END
  END prm[179]
  PIN prm[17]
    DIRECTION OUTPUT ;
    USE SIGNAL ;
    PORT
      LAYER M5 ;
        RECT  39.888 51.756 39.912 51.84 ;
    END
  END prm[17]
  PIN prm[180]
    DIRECTION OUTPUT ;
    USE SIGNAL ;
    PORT
      LAYER M5 ;
        RECT  6.912 51.756 6.936 51.84 ;
    END
  END prm[180]
  PIN prm[181]
    DIRECTION OUTPUT ;
    USE SIGNAL ;
    PORT
      LAYER M5 ;
        RECT  7.056 51.756 7.08 51.84 ;
    END
  END prm[181]
  PIN prm[182]
    DIRECTION OUTPUT ;
    USE SIGNAL ;
    PORT
      LAYER M5 ;
        RECT  7.2 51.756 7.224 51.84 ;
    END
  END prm[182]
  PIN prm[183]
    DIRECTION OUTPUT ;
    USE SIGNAL ;
    PORT
      LAYER M5 ;
        RECT  7.344 51.756 7.368 51.84 ;
    END
  END prm[183]
  PIN prm[184]
    DIRECTION OUTPUT ;
    USE SIGNAL ;
    PORT
      LAYER M5 ;
        RECT  7.488 51.756 7.512 51.84 ;
    END
  END prm[184]
  PIN prm[185]
    DIRECTION OUTPUT ;
    USE SIGNAL ;
    PORT
      LAYER M5 ;
        RECT  7.632 51.756 7.656 51.84 ;
    END
  END prm[185]
  PIN prm[186]
    DIRECTION OUTPUT ;
    USE SIGNAL ;
    PORT
      LAYER M5 ;
        RECT  7.776 51.756 7.8 51.84 ;
    END
  END prm[186]
  PIN prm[187]
    DIRECTION OUTPUT ;
    USE SIGNAL ;
    PORT
      LAYER M5 ;
        RECT  7.92 51.756 7.944 51.84 ;
    END
  END prm[187]
  PIN prm[188]
    DIRECTION OUTPUT ;
    USE SIGNAL ;
    PORT
      LAYER M5 ;
        RECT  8.064 51.756 8.088 51.84 ;
    END
  END prm[188]
  PIN prm[189]
    DIRECTION OUTPUT ;
    USE SIGNAL ;
    PORT
      LAYER M5 ;
        RECT  8.208 51.756 8.232 51.84 ;
    END
  END prm[189]
  PIN prm[18]
    DIRECTION OUTPUT ;
    USE SIGNAL ;
    PORT
      LAYER M5 ;
        RECT  40.032 51.756 40.056 51.84 ;
    END
  END prm[18]
  PIN prm[190]
    DIRECTION OUTPUT ;
    USE SIGNAL ;
    PORT
      LAYER M5 ;
        RECT  8.352 51.756 8.376 51.84 ;
    END
  END prm[190]
  PIN prm[191]
    DIRECTION OUTPUT ;
    USE SIGNAL ;
    PORT
      LAYER M5 ;
        RECT  13.104 51.756 13.128 51.84 ;
    END
  END prm[191]
  PIN prm[192]
    DIRECTION OUTPUT ;
    USE SIGNAL ;
    PORT
      LAYER M5 ;
        RECT  13.248 51.756 13.272 51.84 ;
    END
  END prm[192]
  PIN prm[193]
    DIRECTION OUTPUT ;
    USE SIGNAL ;
    PORT
      LAYER M5 ;
        RECT  13.392 51.756 13.416 51.84 ;
    END
  END prm[193]
  PIN prm[194]
    DIRECTION OUTPUT ;
    USE SIGNAL ;
    PORT
      LAYER M5 ;
        RECT  13.536 51.756 13.56 51.84 ;
    END
  END prm[194]
  PIN prm[195]
    DIRECTION OUTPUT ;
    USE SIGNAL ;
    PORT
      LAYER M5 ;
        RECT  13.68 51.756 13.704 51.84 ;
    END
  END prm[195]
  PIN prm[196]
    DIRECTION OUTPUT ;
    USE SIGNAL ;
    PORT
      LAYER M5 ;
        RECT  13.824 51.756 13.848 51.84 ;
    END
  END prm[196]
  PIN prm[197]
    DIRECTION OUTPUT ;
    USE SIGNAL ;
    PORT
      LAYER M5 ;
        RECT  13.968 51.756 13.992 51.84 ;
    END
  END prm[197]
  PIN prm[198]
    DIRECTION OUTPUT ;
    USE SIGNAL ;
    PORT
      LAYER M5 ;
        RECT  14.112 51.756 14.136 51.84 ;
    END
  END prm[198]
  PIN prm[199]
    DIRECTION OUTPUT ;
    USE SIGNAL ;
    PORT
      LAYER M5 ;
        RECT  14.256 51.756 14.28 51.84 ;
    END
  END prm[199]
  PIN prm[19]
    DIRECTION OUTPUT ;
    USE SIGNAL ;
    PORT
      LAYER M5 ;
        RECT  40.176 51.756 40.2 51.84 ;
    END
  END prm[19]
  PIN prm[1]
    DIRECTION OUTPUT ;
    USE SIGNAL ;
    PORT
      LAYER M5 ;
        RECT  37.584 51.756 37.608 51.84 ;
    END
  END prm[1]
  PIN prm[200]
    DIRECTION OUTPUT ;
    USE SIGNAL ;
    PORT
      LAYER M5 ;
        RECT  14.4 51.756 14.424 51.84 ;
    END
  END prm[200]
  PIN prm[201]
    DIRECTION OUTPUT ;
    USE SIGNAL ;
    PORT
      LAYER M5 ;
        RECT  14.544 51.756 14.568 51.84 ;
    END
  END prm[201]
  PIN prm[202]
    DIRECTION OUTPUT ;
    USE SIGNAL ;
    PORT
      LAYER M5 ;
        RECT  14.688 51.756 14.712 51.84 ;
    END
  END prm[202]
  PIN prm[203]
    DIRECTION OUTPUT ;
    USE SIGNAL ;
    PORT
      LAYER M5 ;
        RECT  14.832 51.756 14.856 51.84 ;
    END
  END prm[203]
  PIN prm[204]
    DIRECTION OUTPUT ;
    USE SIGNAL ;
    PORT
      LAYER M5 ;
        RECT  14.976 51.756 15 51.84 ;
    END
  END prm[204]
  PIN prm[205]
    DIRECTION OUTPUT ;
    USE SIGNAL ;
    PORT
      LAYER M5 ;
        RECT  15.12 51.756 15.144 51.84 ;
    END
  END prm[205]
  PIN prm[206]
    DIRECTION OUTPUT ;
    USE SIGNAL ;
    PORT
      LAYER M5 ;
        RECT  15.264 51.756 15.288 51.84 ;
    END
  END prm[206]
  PIN prm[207]
    DIRECTION OUTPUT ;
    USE SIGNAL ;
    PORT
      LAYER M5 ;
        RECT  15.408 51.756 15.432 51.84 ;
    END
  END prm[207]
  PIN prm[208]
    DIRECTION OUTPUT ;
    USE SIGNAL ;
    PORT
      LAYER M5 ;
        RECT  15.552 51.756 15.576 51.84 ;
    END
  END prm[208]
  PIN prm[209]
    DIRECTION OUTPUT ;
    USE SIGNAL ;
    PORT
      LAYER M5 ;
        RECT  15.696 51.756 15.72 51.84 ;
    END
  END prm[209]
  PIN prm[20]
    DIRECTION OUTPUT ;
    USE SIGNAL ;
    PORT
      LAYER M5 ;
        RECT  40.32 51.756 40.344 51.84 ;
    END
  END prm[20]
  PIN prm[210]
    DIRECTION OUTPUT ;
    USE SIGNAL ;
    PORT
      LAYER M5 ;
        RECT  15.84 51.756 15.864 51.84 ;
    END
  END prm[210]
  PIN prm[211]
    DIRECTION OUTPUT ;
    USE SIGNAL ;
    PORT
      LAYER M5 ;
        RECT  15.984 51.756 16.008 51.84 ;
    END
  END prm[211]
  PIN prm[212]
    DIRECTION OUTPUT ;
    USE SIGNAL ;
    PORT
      LAYER M5 ;
        RECT  16.128 51.756 16.152 51.84 ;
    END
  END prm[212]
  PIN prm[213]
    DIRECTION OUTPUT ;
    USE SIGNAL ;
    PORT
      LAYER M5 ;
        RECT  16.272 51.756 16.296 51.84 ;
    END
  END prm[213]
  PIN prm[214]
    DIRECTION OUTPUT ;
    USE SIGNAL ;
    PORT
      LAYER M5 ;
        RECT  16.416 51.756 16.44 51.84 ;
    END
  END prm[214]
  PIN prm[215]
    DIRECTION OUTPUT ;
    USE SIGNAL ;
    PORT
      LAYER M5 ;
        RECT  16.56 51.756 16.584 51.84 ;
    END
  END prm[215]
  PIN prm[216]
    DIRECTION OUTPUT ;
    USE SIGNAL ;
    PORT
      LAYER M5 ;
        RECT  16.704 51.756 16.728 51.84 ;
    END
  END prm[216]
  PIN prm[217]
    DIRECTION OUTPUT ;
    USE SIGNAL ;
    PORT
      LAYER M5 ;
        RECT  16.848 51.756 16.872 51.84 ;
    END
  END prm[217]
  PIN prm[218]
    DIRECTION OUTPUT ;
    USE SIGNAL ;
    PORT
      LAYER M5 ;
        RECT  16.992 51.756 17.016 51.84 ;
    END
  END prm[218]
  PIN prm[219]
    DIRECTION OUTPUT ;
    USE SIGNAL ;
    PORT
      LAYER M5 ;
        RECT  17.136 51.756 17.16 51.84 ;
    END
  END prm[219]
  PIN prm[21]
    DIRECTION OUTPUT ;
    USE SIGNAL ;
    PORT
      LAYER M5 ;
        RECT  40.464 51.756 40.488 51.84 ;
    END
  END prm[21]
  PIN prm[220]
    DIRECTION OUTPUT ;
    USE SIGNAL ;
    PORT
      LAYER M5 ;
        RECT  17.28 51.756 17.304 51.84 ;
    END
  END prm[220]
  PIN prm[221]
    DIRECTION OUTPUT ;
    USE SIGNAL ;
    PORT
      LAYER M5 ;
        RECT  17.424 51.756 17.448 51.84 ;
    END
  END prm[221]
  PIN prm[222]
    DIRECTION OUTPUT ;
    USE SIGNAL ;
    PORT
      LAYER M5 ;
        RECT  17.568 51.756 17.592 51.84 ;
    END
  END prm[222]
  PIN prm[223]
    DIRECTION OUTPUT ;
    USE SIGNAL ;
    PORT
      LAYER M5 ;
        RECT  23.472 51.756 23.496 51.84 ;
    END
  END prm[223]
  PIN prm[224]
    DIRECTION OUTPUT ;
    USE SIGNAL ;
    PORT
      LAYER M5 ;
        RECT  23.616 51.756 23.64 51.84 ;
    END
  END prm[224]
  PIN prm[225]
    DIRECTION OUTPUT ;
    USE SIGNAL ;
    PORT
      LAYER M5 ;
        RECT  23.76 51.756 23.784 51.84 ;
    END
  END prm[225]
  PIN prm[226]
    DIRECTION OUTPUT ;
    USE SIGNAL ;
    PORT
      LAYER M5 ;
        RECT  23.904 51.756 23.928 51.84 ;
    END
  END prm[226]
  PIN prm[227]
    DIRECTION OUTPUT ;
    USE SIGNAL ;
    PORT
      LAYER M5 ;
        RECT  24.048 51.756 24.072 51.84 ;
    END
  END prm[227]
  PIN prm[228]
    DIRECTION OUTPUT ;
    USE SIGNAL ;
    PORT
      LAYER M5 ;
        RECT  24.192 51.756 24.216 51.84 ;
    END
  END prm[228]
  PIN prm[229]
    DIRECTION OUTPUT ;
    USE SIGNAL ;
    PORT
      LAYER M5 ;
        RECT  24.336 51.756 24.36 51.84 ;
    END
  END prm[229]
  PIN prm[22]
    DIRECTION OUTPUT ;
    USE SIGNAL ;
    PORT
      LAYER M5 ;
        RECT  40.608 51.756 40.632 51.84 ;
    END
  END prm[22]
  PIN prm[230]
    DIRECTION OUTPUT ;
    USE SIGNAL ;
    PORT
      LAYER M5 ;
        RECT  24.48 51.756 24.504 51.84 ;
    END
  END prm[230]
  PIN prm[231]
    DIRECTION OUTPUT ;
    USE SIGNAL ;
    PORT
      LAYER M5 ;
        RECT  24.624 51.756 24.648 51.84 ;
    END
  END prm[231]
  PIN prm[232]
    DIRECTION OUTPUT ;
    USE SIGNAL ;
    PORT
      LAYER M5 ;
        RECT  24.768 51.756 24.792 51.84 ;
    END
  END prm[232]
  PIN prm[233]
    DIRECTION OUTPUT ;
    USE SIGNAL ;
    PORT
      LAYER M5 ;
        RECT  24.912 51.756 24.936 51.84 ;
    END
  END prm[233]
  PIN prm[234]
    DIRECTION OUTPUT ;
    USE SIGNAL ;
    PORT
      LAYER M5 ;
        RECT  25.056 51.756 25.08 51.84 ;
    END
  END prm[234]
  PIN prm[235]
    DIRECTION OUTPUT ;
    USE SIGNAL ;
    PORT
      LAYER M5 ;
        RECT  25.2 51.756 25.224 51.84 ;
    END
  END prm[235]
  PIN prm[236]
    DIRECTION OUTPUT ;
    USE SIGNAL ;
    PORT
      LAYER M5 ;
        RECT  25.344 51.756 25.368 51.84 ;
    END
  END prm[236]
  PIN prm[237]
    DIRECTION OUTPUT ;
    USE SIGNAL ;
    PORT
      LAYER M5 ;
        RECT  25.488 51.756 25.512 51.84 ;
    END
  END prm[237]
  PIN prm[238]
    DIRECTION OUTPUT ;
    USE SIGNAL ;
    PORT
      LAYER M5 ;
        RECT  25.632 51.756 25.656 51.84 ;
    END
  END prm[238]
  PIN prm[239]
    DIRECTION OUTPUT ;
    USE SIGNAL ;
    PORT
      LAYER M5 ;
        RECT  25.776 51.756 25.8 51.84 ;
    END
  END prm[239]
  PIN prm[23]
    DIRECTION OUTPUT ;
    USE SIGNAL ;
    PORT
      LAYER M5 ;
        RECT  40.752 51.756 40.776 51.84 ;
    END
  END prm[23]
  PIN prm[240]
    DIRECTION OUTPUT ;
    USE SIGNAL ;
    PORT
      LAYER M5 ;
        RECT  25.92 51.756 25.944 51.84 ;
    END
  END prm[240]
  PIN prm[241]
    DIRECTION OUTPUT ;
    USE SIGNAL ;
    PORT
      LAYER M5 ;
        RECT  26.064 51.756 26.088 51.84 ;
    END
  END prm[241]
  PIN prm[242]
    DIRECTION OUTPUT ;
    USE SIGNAL ;
    PORT
      LAYER M5 ;
        RECT  26.208 51.756 26.232 51.84 ;
    END
  END prm[242]
  PIN prm[243]
    DIRECTION OUTPUT ;
    USE SIGNAL ;
    PORT
      LAYER M5 ;
        RECT  26.352 51.756 26.376 51.84 ;
    END
  END prm[243]
  PIN prm[244]
    DIRECTION OUTPUT ;
    USE SIGNAL ;
    PORT
      LAYER M5 ;
        RECT  26.496 51.756 26.52 51.84 ;
    END
  END prm[244]
  PIN prm[245]
    DIRECTION OUTPUT ;
    USE SIGNAL ;
    PORT
      LAYER M5 ;
        RECT  26.64 51.756 26.664 51.84 ;
    END
  END prm[245]
  PIN prm[246]
    DIRECTION OUTPUT ;
    USE SIGNAL ;
    PORT
      LAYER M5 ;
        RECT  26.784 51.756 26.808 51.84 ;
    END
  END prm[246]
  PIN prm[247]
    DIRECTION OUTPUT ;
    USE SIGNAL ;
    PORT
      LAYER M5 ;
        RECT  26.928 51.756 26.952 51.84 ;
    END
  END prm[247]
  PIN prm[248]
    DIRECTION OUTPUT ;
    USE SIGNAL ;
    PORT
      LAYER M5 ;
        RECT  27.072 51.756 27.096 51.84 ;
    END
  END prm[248]
  PIN prm[249]
    DIRECTION OUTPUT ;
    USE SIGNAL ;
    PORT
      LAYER M5 ;
        RECT  27.216 51.756 27.24 51.84 ;
    END
  END prm[249]
  PIN prm[24]
    DIRECTION OUTPUT ;
    USE SIGNAL ;
    PORT
      LAYER M5 ;
        RECT  40.896 51.756 40.92 51.84 ;
    END
  END prm[24]
  PIN prm[250]
    DIRECTION OUTPUT ;
    USE SIGNAL ;
    PORT
      LAYER M5 ;
        RECT  27.36 51.756 27.384 51.84 ;
    END
  END prm[250]
  PIN prm[251]
    DIRECTION OUTPUT ;
    USE SIGNAL ;
    PORT
      LAYER M5 ;
        RECT  27.504 51.756 27.528 51.84 ;
    END
  END prm[251]
  PIN prm[252]
    DIRECTION OUTPUT ;
    USE SIGNAL ;
    PORT
      LAYER M5 ;
        RECT  27.648 51.756 27.672 51.84 ;
    END
  END prm[252]
  PIN prm[253]
    DIRECTION OUTPUT ;
    USE SIGNAL ;
    PORT
      LAYER M5 ;
        RECT  27.792 51.756 27.816 51.84 ;
    END
  END prm[253]
  PIN prm[254]
    DIRECTION OUTPUT ;
    USE SIGNAL ;
    PORT
      LAYER M5 ;
        RECT  27.936 51.756 27.96 51.84 ;
    END
  END prm[254]
  PIN prm[255]
    DIRECTION OUTPUT ;
    USE SIGNAL ;
    PORT
      LAYER M5 ;
        RECT  23.328 51.756 23.352 51.84 ;
    END
  END prm[255]
  PIN prm[25]
    DIRECTION OUTPUT ;
    USE SIGNAL ;
    PORT
      LAYER M5 ;
        RECT  41.04 51.756 41.064 51.84 ;
    END
  END prm[25]
  PIN prm[26]
    DIRECTION OUTPUT ;
    USE SIGNAL ;
    PORT
      LAYER M5 ;
        RECT  41.184 51.756 41.208 51.84 ;
    END
  END prm[26]
  PIN prm[27]
    DIRECTION OUTPUT ;
    USE SIGNAL ;
    PORT
      LAYER M5 ;
        RECT  41.328 51.756 41.352 51.84 ;
    END
  END prm[27]
  PIN prm[28]
    DIRECTION OUTPUT ;
    USE SIGNAL ;
    PORT
      LAYER M5 ;
        RECT  41.472 51.756 41.496 51.84 ;
    END
  END prm[28]
  PIN prm[29]
    DIRECTION OUTPUT ;
    USE SIGNAL ;
    PORT
      LAYER M5 ;
        RECT  41.616 51.756 41.64 51.84 ;
    END
  END prm[29]
  PIN prm[2]
    DIRECTION OUTPUT ;
    USE SIGNAL ;
    PORT
      LAYER M5 ;
        RECT  37.728 51.756 37.752 51.84 ;
    END
  END prm[2]
  PIN prm[30]
    DIRECTION OUTPUT ;
    USE SIGNAL ;
    PORT
      LAYER M5 ;
        RECT  41.76 51.756 41.784 51.84 ;
    END
  END prm[30]
  PIN prm[31]
    DIRECTION OUTPUT ;
    USE SIGNAL ;
    PORT
      LAYER M5 ;
        RECT  32.688 51.756 32.712 51.84 ;
    END
  END prm[31]
  PIN prm[32]
    DIRECTION OUTPUT ;
    USE SIGNAL ;
    PORT
      LAYER M5 ;
        RECT  32.832 51.756 32.856 51.84 ;
    END
  END prm[32]
  PIN prm[33]
    DIRECTION OUTPUT ;
    USE SIGNAL ;
    PORT
      LAYER M5 ;
        RECT  32.976 51.756 33 51.84 ;
    END
  END prm[33]
  PIN prm[34]
    DIRECTION OUTPUT ;
    USE SIGNAL ;
    PORT
      LAYER M5 ;
        RECT  33.12 51.756 33.144 51.84 ;
    END
  END prm[34]
  PIN prm[35]
    DIRECTION OUTPUT ;
    USE SIGNAL ;
    PORT
      LAYER M5 ;
        RECT  33.264 51.756 33.288 51.84 ;
    END
  END prm[35]
  PIN prm[36]
    DIRECTION OUTPUT ;
    USE SIGNAL ;
    PORT
      LAYER M5 ;
        RECT  33.408 51.756 33.432 51.84 ;
    END
  END prm[36]
  PIN prm[37]
    DIRECTION OUTPUT ;
    USE SIGNAL ;
    PORT
      LAYER M5 ;
        RECT  33.552 51.756 33.576 51.84 ;
    END
  END prm[37]
  PIN prm[38]
    DIRECTION OUTPUT ;
    USE SIGNAL ;
    PORT
      LAYER M5 ;
        RECT  33.696 51.756 33.72 51.84 ;
    END
  END prm[38]
  PIN prm[39]
    DIRECTION OUTPUT ;
    USE SIGNAL ;
    PORT
      LAYER M5 ;
        RECT  33.84 51.756 33.864 51.84 ;
    END
  END prm[39]
  PIN prm[3]
    DIRECTION OUTPUT ;
    USE SIGNAL ;
    PORT
      LAYER M5 ;
        RECT  37.872 51.756 37.896 51.84 ;
    END
  END prm[3]
  PIN prm[40]
    DIRECTION OUTPUT ;
    USE SIGNAL ;
    PORT
      LAYER M5 ;
        RECT  33.984 51.756 34.008 51.84 ;
    END
  END prm[40]
  PIN prm[41]
    DIRECTION OUTPUT ;
    USE SIGNAL ;
    PORT
      LAYER M5 ;
        RECT  34.128 51.756 34.152 51.84 ;
    END
  END prm[41]
  PIN prm[42]
    DIRECTION OUTPUT ;
    USE SIGNAL ;
    PORT
      LAYER M5 ;
        RECT  34.272 51.756 34.296 51.84 ;
    END
  END prm[42]
  PIN prm[43]
    DIRECTION OUTPUT ;
    USE SIGNAL ;
    PORT
      LAYER M5 ;
        RECT  34.416 51.756 34.44 51.84 ;
    END
  END prm[43]
  PIN prm[44]
    DIRECTION OUTPUT ;
    USE SIGNAL ;
    PORT
      LAYER M5 ;
        RECT  34.56 51.756 34.584 51.84 ;
    END
  END prm[44]
  PIN prm[45]
    DIRECTION OUTPUT ;
    USE SIGNAL ;
    PORT
      LAYER M5 ;
        RECT  34.704 51.756 34.728 51.84 ;
    END
  END prm[45]
  PIN prm[46]
    DIRECTION OUTPUT ;
    USE SIGNAL ;
    PORT
      LAYER M5 ;
        RECT  34.848 51.756 34.872 51.84 ;
    END
  END prm[46]
  PIN prm[47]
    DIRECTION OUTPUT ;
    USE SIGNAL ;
    PORT
      LAYER M5 ;
        RECT  34.992 51.756 35.016 51.84 ;
    END
  END prm[47]
  PIN prm[48]
    DIRECTION OUTPUT ;
    USE SIGNAL ;
    PORT
      LAYER M5 ;
        RECT  35.136 51.756 35.16 51.84 ;
    END
  END prm[48]
  PIN prm[49]
    DIRECTION OUTPUT ;
    USE SIGNAL ;
    PORT
      LAYER M5 ;
        RECT  35.28 51.756 35.304 51.84 ;
    END
  END prm[49]
  PIN prm[4]
    DIRECTION OUTPUT ;
    USE SIGNAL ;
    PORT
      LAYER M5 ;
        RECT  38.016 51.756 38.04 51.84 ;
    END
  END prm[4]
  PIN prm[50]
    DIRECTION OUTPUT ;
    USE SIGNAL ;
    PORT
      LAYER M5 ;
        RECT  35.424 51.756 35.448 51.84 ;
    END
  END prm[50]
  PIN prm[51]
    DIRECTION OUTPUT ;
    USE SIGNAL ;
    PORT
      LAYER M5 ;
        RECT  35.568 51.756 35.592 51.84 ;
    END
  END prm[51]
  PIN prm[52]
    DIRECTION OUTPUT ;
    USE SIGNAL ;
    PORT
      LAYER M5 ;
        RECT  35.712 51.756 35.736 51.84 ;
    END
  END prm[52]
  PIN prm[53]
    DIRECTION OUTPUT ;
    USE SIGNAL ;
    PORT
      LAYER M5 ;
        RECT  35.856 51.756 35.88 51.84 ;
    END
  END prm[53]
  PIN prm[54]
    DIRECTION OUTPUT ;
    USE SIGNAL ;
    PORT
      LAYER M5 ;
        RECT  36 51.756 36.024 51.84 ;
    END
  END prm[54]
  PIN prm[55]
    DIRECTION OUTPUT ;
    USE SIGNAL ;
    PORT
      LAYER M5 ;
        RECT  36.144 51.756 36.168 51.84 ;
    END
  END prm[55]
  PIN prm[56]
    DIRECTION OUTPUT ;
    USE SIGNAL ;
    PORT
      LAYER M5 ;
        RECT  36.288 51.756 36.312 51.84 ;
    END
  END prm[56]
  PIN prm[57]
    DIRECTION OUTPUT ;
    USE SIGNAL ;
    PORT
      LAYER M5 ;
        RECT  36.432 51.756 36.456 51.84 ;
    END
  END prm[57]
  PIN prm[58]
    DIRECTION OUTPUT ;
    USE SIGNAL ;
    PORT
      LAYER M5 ;
        RECT  36.576 51.756 36.6 51.84 ;
    END
  END prm[58]
  PIN prm[59]
    DIRECTION OUTPUT ;
    USE SIGNAL ;
    PORT
      LAYER M5 ;
        RECT  36.72 51.756 36.744 51.84 ;
    END
  END prm[59]
  PIN prm[5]
    DIRECTION OUTPUT ;
    USE SIGNAL ;
    PORT
      LAYER M5 ;
        RECT  38.16 51.756 38.184 51.84 ;
    END
  END prm[5]
  PIN prm[60]
    DIRECTION OUTPUT ;
    USE SIGNAL ;
    PORT
      LAYER M5 ;
        RECT  36.864 51.756 36.888 51.84 ;
    END
  END prm[60]
  PIN prm[61]
    DIRECTION OUTPUT ;
    USE SIGNAL ;
    PORT
      LAYER M5 ;
        RECT  37.008 51.756 37.032 51.84 ;
    END
  END prm[61]
  PIN prm[62]
    DIRECTION OUTPUT ;
    USE SIGNAL ;
    PORT
      LAYER M5 ;
        RECT  37.152 51.756 37.176 51.84 ;
    END
  END prm[62]
  PIN prm[63]
    DIRECTION OUTPUT ;
    USE SIGNAL ;
    PORT
      LAYER M5 ;
        RECT  28.08 51.756 28.104 51.84 ;
    END
  END prm[63]
  PIN prm[64]
    DIRECTION OUTPUT ;
    USE SIGNAL ;
    PORT
      LAYER M5 ;
        RECT  28.224 51.756 28.248 51.84 ;
    END
  END prm[64]
  PIN prm[65]
    DIRECTION OUTPUT ;
    USE SIGNAL ;
    PORT
      LAYER M5 ;
        RECT  28.368 51.756 28.392 51.84 ;
    END
  END prm[65]
  PIN prm[66]
    DIRECTION OUTPUT ;
    USE SIGNAL ;
    PORT
      LAYER M5 ;
        RECT  28.512 51.756 28.536 51.84 ;
    END
  END prm[66]
  PIN prm[67]
    DIRECTION OUTPUT ;
    USE SIGNAL ;
    PORT
      LAYER M5 ;
        RECT  28.656 51.756 28.68 51.84 ;
    END
  END prm[67]
  PIN prm[68]
    DIRECTION OUTPUT ;
    USE SIGNAL ;
    PORT
      LAYER M5 ;
        RECT  28.8 51.756 28.824 51.84 ;
    END
  END prm[68]
  PIN prm[69]
    DIRECTION OUTPUT ;
    USE SIGNAL ;
    PORT
      LAYER M5 ;
        RECT  28.944 51.756 28.968 51.84 ;
    END
  END prm[69]
  PIN prm[6]
    DIRECTION OUTPUT ;
    USE SIGNAL ;
    PORT
      LAYER M5 ;
        RECT  38.304 51.756 38.328 51.84 ;
    END
  END prm[6]
  PIN prm[70]
    DIRECTION OUTPUT ;
    USE SIGNAL ;
    PORT
      LAYER M5 ;
        RECT  29.088 51.756 29.112 51.84 ;
    END
  END prm[70]
  PIN prm[71]
    DIRECTION OUTPUT ;
    USE SIGNAL ;
    PORT
      LAYER M5 ;
        RECT  29.232 51.756 29.256 51.84 ;
    END
  END prm[71]
  PIN prm[72]
    DIRECTION OUTPUT ;
    USE SIGNAL ;
    PORT
      LAYER M5 ;
        RECT  29.376 51.756 29.4 51.84 ;
    END
  END prm[72]
  PIN prm[73]
    DIRECTION OUTPUT ;
    USE SIGNAL ;
    PORT
      LAYER M5 ;
        RECT  29.52 51.756 29.544 51.84 ;
    END
  END prm[73]
  PIN prm[74]
    DIRECTION OUTPUT ;
    USE SIGNAL ;
    PORT
      LAYER M5 ;
        RECT  29.664 51.756 29.688 51.84 ;
    END
  END prm[74]
  PIN prm[75]
    DIRECTION OUTPUT ;
    USE SIGNAL ;
    PORT
      LAYER M5 ;
        RECT  29.808 51.756 29.832 51.84 ;
    END
  END prm[75]
  PIN prm[76]
    DIRECTION OUTPUT ;
    USE SIGNAL ;
    PORT
      LAYER M5 ;
        RECT  29.952 51.756 29.976 51.84 ;
    END
  END prm[76]
  PIN prm[77]
    DIRECTION OUTPUT ;
    USE SIGNAL ;
    PORT
      LAYER M5 ;
        RECT  30.096 51.756 30.12 51.84 ;
    END
  END prm[77]
  PIN prm[78]
    DIRECTION OUTPUT ;
    USE SIGNAL ;
    PORT
      LAYER M5 ;
        RECT  30.24 51.756 30.264 51.84 ;
    END
  END prm[78]
  PIN prm[79]
    DIRECTION OUTPUT ;
    USE SIGNAL ;
    PORT
      LAYER M5 ;
        RECT  30.384 51.756 30.408 51.84 ;
    END
  END prm[79]
  PIN prm[7]
    DIRECTION OUTPUT ;
    USE SIGNAL ;
    PORT
      LAYER M5 ;
        RECT  38.448 51.756 38.472 51.84 ;
    END
  END prm[7]
  PIN prm[80]
    DIRECTION OUTPUT ;
    USE SIGNAL ;
    PORT
      LAYER M5 ;
        RECT  30.528 51.756 30.552 51.84 ;
    END
  END prm[80]
  PIN prm[81]
    DIRECTION OUTPUT ;
    USE SIGNAL ;
    PORT
      LAYER M5 ;
        RECT  30.672 51.756 30.696 51.84 ;
    END
  END prm[81]
  PIN prm[82]
    DIRECTION OUTPUT ;
    USE SIGNAL ;
    PORT
      LAYER M5 ;
        RECT  30.816 51.756 30.84 51.84 ;
    END
  END prm[82]
  PIN prm[83]
    DIRECTION OUTPUT ;
    USE SIGNAL ;
    PORT
      LAYER M5 ;
        RECT  30.96 51.756 30.984 51.84 ;
    END
  END prm[83]
  PIN prm[84]
    DIRECTION OUTPUT ;
    USE SIGNAL ;
    PORT
      LAYER M5 ;
        RECT  31.104 51.756 31.128 51.84 ;
    END
  END prm[84]
  PIN prm[85]
    DIRECTION OUTPUT ;
    USE SIGNAL ;
    PORT
      LAYER M5 ;
        RECT  31.248 51.756 31.272 51.84 ;
    END
  END prm[85]
  PIN prm[86]
    DIRECTION OUTPUT ;
    USE SIGNAL ;
    PORT
      LAYER M5 ;
        RECT  31.392 51.756 31.416 51.84 ;
    END
  END prm[86]
  PIN prm[87]
    DIRECTION OUTPUT ;
    USE SIGNAL ;
    PORT
      LAYER M5 ;
        RECT  31.536 51.756 31.56 51.84 ;
    END
  END prm[87]
  PIN prm[88]
    DIRECTION OUTPUT ;
    USE SIGNAL ;
    PORT
      LAYER M5 ;
        RECT  31.68 51.756 31.704 51.84 ;
    END
  END prm[88]
  PIN prm[89]
    DIRECTION OUTPUT ;
    USE SIGNAL ;
    PORT
      LAYER M5 ;
        RECT  31.824 51.756 31.848 51.84 ;
    END
  END prm[89]
  PIN prm[8]
    DIRECTION OUTPUT ;
    USE SIGNAL ;
    PORT
      LAYER M5 ;
        RECT  38.592 51.756 38.616 51.84 ;
    END
  END prm[8]
  PIN prm[90]
    DIRECTION OUTPUT ;
    USE SIGNAL ;
    PORT
      LAYER M5 ;
        RECT  31.968 51.756 31.992 51.84 ;
    END
  END prm[90]
  PIN prm[91]
    DIRECTION OUTPUT ;
    USE SIGNAL ;
    PORT
      LAYER M5 ;
        RECT  32.112 51.756 32.136 51.84 ;
    END
  END prm[91]
  PIN prm[92]
    DIRECTION OUTPUT ;
    USE SIGNAL ;
    PORT
      LAYER M5 ;
        RECT  32.256 51.756 32.28 51.84 ;
    END
  END prm[92]
  PIN prm[93]
    DIRECTION OUTPUT ;
    USE SIGNAL ;
    PORT
      LAYER M5 ;
        RECT  32.4 51.756 32.424 51.84 ;
    END
  END prm[93]
  PIN prm[94]
    DIRECTION OUTPUT ;
    USE SIGNAL ;
    PORT
      LAYER M5 ;
        RECT  32.544 51.756 32.568 51.84 ;
    END
  END prm[94]
  PIN prm[95]
    DIRECTION OUTPUT ;
    USE SIGNAL ;
    PORT
      LAYER M5 ;
        RECT  17.712 51.756 17.736 51.84 ;
    END
  END prm[95]
  PIN prm[96]
    DIRECTION OUTPUT ;
    USE SIGNAL ;
    PORT
      LAYER M5 ;
        RECT  17.856 51.756 17.88 51.84 ;
    END
  END prm[96]
  PIN prm[97]
    DIRECTION OUTPUT ;
    USE SIGNAL ;
    PORT
      LAYER M5 ;
        RECT  18 51.756 18.024 51.84 ;
    END
  END prm[97]
  PIN prm[98]
    DIRECTION OUTPUT ;
    USE SIGNAL ;
    PORT
      LAYER M5 ;
        RECT  18.144 51.756 18.168 51.84 ;
    END
  END prm[98]
  PIN prm[99]
    DIRECTION OUTPUT ;
    USE SIGNAL ;
    PORT
      LAYER M5 ;
        RECT  18.288 51.756 18.312 51.84 ;
    END
  END prm[99]
  PIN prm[9]
    DIRECTION OUTPUT ;
    USE SIGNAL ;
    PORT
      LAYER M5 ;
        RECT  38.736 51.756 38.76 51.84 ;
    END
  END prm[9]
  PIN pw_addr[0]
    DIRECTION OUTPUT ;
    USE SIGNAL ;
    PORT
      LAYER M4 ;
        RECT  0 8.928 0.084 8.952 ;
    END
  END pw_addr[0]
  PIN pw_addr[10]
    DIRECTION OUTPUT ;
    USE SIGNAL ;
    PORT
      LAYER M4 ;
        RECT  0 10.368 0.084 10.392 ;
    END
  END pw_addr[10]
  PIN pw_addr[11]
    DIRECTION OUTPUT ;
    USE SIGNAL ;
    PORT
      LAYER M4 ;
        RECT  0 10.512 0.084 10.536 ;
    END
  END pw_addr[11]
  PIN pw_addr[12]
    DIRECTION OUTPUT ;
    USE SIGNAL ;
    PORT
      LAYER M4 ;
        RECT  0 10.656 0.084 10.68 ;
    END
  END pw_addr[12]
  PIN pw_addr[13]
    DIRECTION OUTPUT ;
    USE SIGNAL ;
    PORT
      LAYER M4 ;
        RECT  0 10.8 0.084 10.824 ;
    END
  END pw_addr[13]
  PIN pw_addr[1]
    DIRECTION OUTPUT ;
    USE SIGNAL ;
    PORT
      LAYER M4 ;
        RECT  0 9.072 0.084 9.096 ;
    END
  END pw_addr[1]
  PIN pw_addr[2]
    DIRECTION OUTPUT ;
    USE SIGNAL ;
    PORT
      LAYER M4 ;
        RECT  0 9.216 0.084 9.24 ;
    END
  END pw_addr[2]
  PIN pw_addr[3]
    DIRECTION OUTPUT ;
    USE SIGNAL ;
    PORT
      LAYER M4 ;
        RECT  0 9.36 0.084 9.384 ;
    END
  END pw_addr[3]
  PIN pw_addr[4]
    DIRECTION OUTPUT ;
    USE SIGNAL ;
    PORT
      LAYER M4 ;
        RECT  0 9.504 0.084 9.528 ;
    END
  END pw_addr[4]
  PIN pw_addr[5]
    DIRECTION OUTPUT ;
    USE SIGNAL ;
    PORT
      LAYER M4 ;
        RECT  0 9.648 0.084 9.672 ;
    END
  END pw_addr[5]
  PIN pw_addr[6]
    DIRECTION OUTPUT ;
    USE SIGNAL ;
    PORT
      LAYER M4 ;
        RECT  0 9.792 0.084 9.816 ;
    END
  END pw_addr[6]
  PIN pw_addr[7]
    DIRECTION OUTPUT ;
    USE SIGNAL ;
    PORT
      LAYER M4 ;
        RECT  0 9.936 0.084 9.96 ;
    END
  END pw_addr[7]
  PIN pw_addr[8]
    DIRECTION OUTPUT ;
    USE SIGNAL ;
    PORT
      LAYER M4 ;
        RECT  0 10.08 0.084 10.104 ;
    END
  END pw_addr[8]
  PIN pw_addr[9]
    DIRECTION OUTPUT ;
    USE SIGNAL ;
    PORT
      LAYER M4 ;
        RECT  0 10.224 0.084 10.248 ;
    END
  END pw_addr[9]
  PIN pw_data[0]
    DIRECTION OUTPUT ;
    USE SIGNAL ;
    PORT
      LAYER M4 ;
        RECT  0 10.944 0.084 10.968 ;
    END
  END pw_data[0]
  PIN pw_data[100]
    DIRECTION OUTPUT ;
    USE SIGNAL ;
    PORT
      LAYER M4 ;
        RECT  0 40.32 0.084 40.344 ;
    END
  END pw_data[100]
  PIN pw_data[101]
    DIRECTION OUTPUT ;
    USE SIGNAL ;
    PORT
      LAYER M4 ;
        RECT  0 40.464 0.084 40.488 ;
    END
  END pw_data[101]
  PIN pw_data[102]
    DIRECTION OUTPUT ;
    USE SIGNAL ;
    PORT
      LAYER M4 ;
        RECT  0 40.608 0.084 40.632 ;
    END
  END pw_data[102]
  PIN pw_data[103]
    DIRECTION OUTPUT ;
    USE SIGNAL ;
    PORT
      LAYER M4 ;
        RECT  0 40.752 0.084 40.776 ;
    END
  END pw_data[103]
  PIN pw_data[104]
    DIRECTION OUTPUT ;
    USE SIGNAL ;
    PORT
      LAYER M4 ;
        RECT  0 40.896 0.084 40.92 ;
    END
  END pw_data[104]
  PIN pw_data[105]
    DIRECTION OUTPUT ;
    USE SIGNAL ;
    PORT
      LAYER M4 ;
        RECT  0 41.04 0.084 41.064 ;
    END
  END pw_data[105]
  PIN pw_data[106]
    DIRECTION OUTPUT ;
    USE SIGNAL ;
    PORT
      LAYER M4 ;
        RECT  0 41.184 0.084 41.208 ;
    END
  END pw_data[106]
  PIN pw_data[107]
    DIRECTION OUTPUT ;
    USE SIGNAL ;
    PORT
      LAYER M4 ;
        RECT  0 41.328 0.084 41.352 ;
    END
  END pw_data[107]
  PIN pw_data[108]
    DIRECTION OUTPUT ;
    USE SIGNAL ;
    PORT
      LAYER M4 ;
        RECT  0 41.472 0.084 41.496 ;
    END
  END pw_data[108]
  PIN pw_data[109]
    DIRECTION OUTPUT ;
    USE SIGNAL ;
    PORT
      LAYER M4 ;
        RECT  0 41.616 0.084 41.64 ;
    END
  END pw_data[109]
  PIN pw_data[10]
    DIRECTION OUTPUT ;
    USE SIGNAL ;
    PORT
      LAYER M4 ;
        RECT  0 12.384 0.084 12.408 ;
    END
  END pw_data[10]
  PIN pw_data[110]
    DIRECTION OUTPUT ;
    USE SIGNAL ;
    PORT
      LAYER M4 ;
        RECT  0 41.76 0.084 41.784 ;
    END
  END pw_data[110]
  PIN pw_data[111]
    DIRECTION OUTPUT ;
    USE SIGNAL ;
    PORT
      LAYER M4 ;
        RECT  0 28.08 0.084 28.104 ;
    END
  END pw_data[111]
  PIN pw_data[112]
    DIRECTION OUTPUT ;
    USE SIGNAL ;
    PORT
      LAYER M4 ;
        RECT  0 28.224 0.084 28.248 ;
    END
  END pw_data[112]
  PIN pw_data[113]
    DIRECTION OUTPUT ;
    USE SIGNAL ;
    PORT
      LAYER M4 ;
        RECT  0 28.368 0.084 28.392 ;
    END
  END pw_data[113]
  PIN pw_data[114]
    DIRECTION OUTPUT ;
    USE SIGNAL ;
    PORT
      LAYER M4 ;
        RECT  0 28.512 0.084 28.536 ;
    END
  END pw_data[114]
  PIN pw_data[115]
    DIRECTION OUTPUT ;
    USE SIGNAL ;
    PORT
      LAYER M4 ;
        RECT  0 28.656 0.084 28.68 ;
    END
  END pw_data[115]
  PIN pw_data[116]
    DIRECTION OUTPUT ;
    USE SIGNAL ;
    PORT
      LAYER M4 ;
        RECT  0 28.8 0.084 28.824 ;
    END
  END pw_data[116]
  PIN pw_data[117]
    DIRECTION OUTPUT ;
    USE SIGNAL ;
    PORT
      LAYER M4 ;
        RECT  0 28.944 0.084 28.968 ;
    END
  END pw_data[117]
  PIN pw_data[118]
    DIRECTION OUTPUT ;
    USE SIGNAL ;
    PORT
      LAYER M4 ;
        RECT  0 29.088 0.084 29.112 ;
    END
  END pw_data[118]
  PIN pw_data[119]
    DIRECTION OUTPUT ;
    USE SIGNAL ;
    PORT
      LAYER M4 ;
        RECT  0 29.232 0.084 29.256 ;
    END
  END pw_data[119]
  PIN pw_data[11]
    DIRECTION OUTPUT ;
    USE SIGNAL ;
    PORT
      LAYER M4 ;
        RECT  0 12.528 0.084 12.552 ;
    END
  END pw_data[11]
  PIN pw_data[120]
    DIRECTION OUTPUT ;
    USE SIGNAL ;
    PORT
      LAYER M4 ;
        RECT  0 29.376 0.084 29.4 ;
    END
  END pw_data[120]
  PIN pw_data[121]
    DIRECTION OUTPUT ;
    USE SIGNAL ;
    PORT
      LAYER M4 ;
        RECT  0 29.52 0.084 29.544 ;
    END
  END pw_data[121]
  PIN pw_data[122]
    DIRECTION OUTPUT ;
    USE SIGNAL ;
    PORT
      LAYER M4 ;
        RECT  0 29.664 0.084 29.688 ;
    END
  END pw_data[122]
  PIN pw_data[123]
    DIRECTION OUTPUT ;
    USE SIGNAL ;
    PORT
      LAYER M4 ;
        RECT  0 29.808 0.084 29.832 ;
    END
  END pw_data[123]
  PIN pw_data[124]
    DIRECTION OUTPUT ;
    USE SIGNAL ;
    PORT
      LAYER M4 ;
        RECT  0 29.952 0.084 29.976 ;
    END
  END pw_data[124]
  PIN pw_data[125]
    DIRECTION OUTPUT ;
    USE SIGNAL ;
    PORT
      LAYER M4 ;
        RECT  0 30.096 0.084 30.12 ;
    END
  END pw_data[125]
  PIN pw_data[126]
    DIRECTION OUTPUT ;
    USE SIGNAL ;
    PORT
      LAYER M4 ;
        RECT  0 30.24 0.084 30.264 ;
    END
  END pw_data[126]
  PIN pw_data[127]
    DIRECTION OUTPUT ;
    USE SIGNAL ;
    PORT
      LAYER M4 ;
        RECT  0 30.384 0.084 30.408 ;
    END
  END pw_data[127]
  PIN pw_data[128]
    DIRECTION OUTPUT ;
    USE SIGNAL ;
    PORT
      LAYER M4 ;
        RECT  0 30.528 0.084 30.552 ;
    END
  END pw_data[128]
  PIN pw_data[129]
    DIRECTION OUTPUT ;
    USE SIGNAL ;
    PORT
      LAYER M4 ;
        RECT  0 30.672 0.084 30.696 ;
    END
  END pw_data[129]
  PIN pw_data[12]
    DIRECTION OUTPUT ;
    USE SIGNAL ;
    PORT
      LAYER M4 ;
        RECT  0 12.672 0.084 12.696 ;
    END
  END pw_data[12]
  PIN pw_data[130]
    DIRECTION OUTPUT ;
    USE SIGNAL ;
    PORT
      LAYER M4 ;
        RECT  0 30.816 0.084 30.84 ;
    END
  END pw_data[130]
  PIN pw_data[131]
    DIRECTION OUTPUT ;
    USE SIGNAL ;
    PORT
      LAYER M4 ;
        RECT  0 30.96 0.084 30.984 ;
    END
  END pw_data[131]
  PIN pw_data[132]
    DIRECTION OUTPUT ;
    USE SIGNAL ;
    PORT
      LAYER M4 ;
        RECT  0 31.104 0.084 31.128 ;
    END
  END pw_data[132]
  PIN pw_data[133]
    DIRECTION OUTPUT ;
    USE SIGNAL ;
    PORT
      LAYER M4 ;
        RECT  0 31.248 0.084 31.272 ;
    END
  END pw_data[133]
  PIN pw_data[134]
    DIRECTION OUTPUT ;
    USE SIGNAL ;
    PORT
      LAYER M4 ;
        RECT  0 31.392 0.084 31.416 ;
    END
  END pw_data[134]
  PIN pw_data[135]
    DIRECTION OUTPUT ;
    USE SIGNAL ;
    PORT
      LAYER M4 ;
        RECT  0 31.536 0.084 31.56 ;
    END
  END pw_data[135]
  PIN pw_data[136]
    DIRECTION OUTPUT ;
    USE SIGNAL ;
    PORT
      LAYER M4 ;
        RECT  0 31.68 0.084 31.704 ;
    END
  END pw_data[136]
  PIN pw_data[137]
    DIRECTION OUTPUT ;
    USE SIGNAL ;
    PORT
      LAYER M4 ;
        RECT  0 31.824 0.084 31.848 ;
    END
  END pw_data[137]
  PIN pw_data[138]
    DIRECTION OUTPUT ;
    USE SIGNAL ;
    PORT
      LAYER M4 ;
        RECT  0 31.968 0.084 31.992 ;
    END
  END pw_data[138]
  PIN pw_data[139]
    DIRECTION OUTPUT ;
    USE SIGNAL ;
    PORT
      LAYER M4 ;
        RECT  0 32.112 0.084 32.136 ;
    END
  END pw_data[139]
  PIN pw_data[13]
    DIRECTION OUTPUT ;
    USE SIGNAL ;
    PORT
      LAYER M4 ;
        RECT  0 12.816 0.084 12.84 ;
    END
  END pw_data[13]
  PIN pw_data[140]
    DIRECTION OUTPUT ;
    USE SIGNAL ;
    PORT
      LAYER M4 ;
        RECT  0 32.256 0.084 32.28 ;
    END
  END pw_data[140]
  PIN pw_data[141]
    DIRECTION OUTPUT ;
    USE SIGNAL ;
    PORT
      LAYER M4 ;
        RECT  0 32.4 0.084 32.424 ;
    END
  END pw_data[141]
  PIN pw_data[142]
    DIRECTION OUTPUT ;
    USE SIGNAL ;
    PORT
      LAYER M4 ;
        RECT  0 32.544 0.084 32.568 ;
    END
  END pw_data[142]
  PIN pw_data[143]
    DIRECTION OUTPUT ;
    USE SIGNAL ;
    PORT
      LAYER M4 ;
        RECT  0 32.688 0.084 32.712 ;
    END
  END pw_data[143]
  PIN pw_data[144]
    DIRECTION OUTPUT ;
    USE SIGNAL ;
    PORT
      LAYER M4 ;
        RECT  0 32.832 0.084 32.856 ;
    END
  END pw_data[144]
  PIN pw_data[145]
    DIRECTION OUTPUT ;
    USE SIGNAL ;
    PORT
      LAYER M4 ;
        RECT  0 32.976 0.084 33 ;
    END
  END pw_data[145]
  PIN pw_data[146]
    DIRECTION OUTPUT ;
    USE SIGNAL ;
    PORT
      LAYER M4 ;
        RECT  0 33.12 0.084 33.144 ;
    END
  END pw_data[146]
  PIN pw_data[147]
    DIRECTION OUTPUT ;
    USE SIGNAL ;
    PORT
      LAYER M4 ;
        RECT  0 33.264 0.084 33.288 ;
    END
  END pw_data[147]
  PIN pw_data[148]
    DIRECTION OUTPUT ;
    USE SIGNAL ;
    PORT
      LAYER M4 ;
        RECT  0 33.408 0.084 33.432 ;
    END
  END pw_data[148]
  PIN pw_data[149]
    DIRECTION OUTPUT ;
    USE SIGNAL ;
    PORT
      LAYER M4 ;
        RECT  0 33.552 0.084 33.576 ;
    END
  END pw_data[149]
  PIN pw_data[14]
    DIRECTION OUTPUT ;
    USE SIGNAL ;
    PORT
      LAYER M4 ;
        RECT  0 12.96 0.084 12.984 ;
    END
  END pw_data[14]
  PIN pw_data[150]
    DIRECTION OUTPUT ;
    USE SIGNAL ;
    PORT
      LAYER M4 ;
        RECT  0 33.696 0.084 33.72 ;
    END
  END pw_data[150]
  PIN pw_data[151]
    DIRECTION OUTPUT ;
    USE SIGNAL ;
    PORT
      LAYER M4 ;
        RECT  0 33.84 0.084 33.864 ;
    END
  END pw_data[151]
  PIN pw_data[152]
    DIRECTION OUTPUT ;
    USE SIGNAL ;
    PORT
      LAYER M4 ;
        RECT  0 33.984 0.084 34.008 ;
    END
  END pw_data[152]
  PIN pw_data[153]
    DIRECTION OUTPUT ;
    USE SIGNAL ;
    PORT
      LAYER M4 ;
        RECT  0 34.128 0.084 34.152 ;
    END
  END pw_data[153]
  PIN pw_data[154]
    DIRECTION OUTPUT ;
    USE SIGNAL ;
    PORT
      LAYER M4 ;
        RECT  0 34.272 0.084 34.296 ;
    END
  END pw_data[154]
  PIN pw_data[155]
    DIRECTION OUTPUT ;
    USE SIGNAL ;
    PORT
      LAYER M4 ;
        RECT  0 34.416 0.084 34.44 ;
    END
  END pw_data[155]
  PIN pw_data[156]
    DIRECTION OUTPUT ;
    USE SIGNAL ;
    PORT
      LAYER M4 ;
        RECT  0 34.56 0.084 34.584 ;
    END
  END pw_data[156]
  PIN pw_data[157]
    DIRECTION OUTPUT ;
    USE SIGNAL ;
    PORT
      LAYER M4 ;
        RECT  0 34.704 0.084 34.728 ;
    END
  END pw_data[157]
  PIN pw_data[158]
    DIRECTION OUTPUT ;
    USE SIGNAL ;
    PORT
      LAYER M4 ;
        RECT  0 34.848 0.084 34.872 ;
    END
  END pw_data[158]
  PIN pw_data[159]
    DIRECTION OUTPUT ;
    USE SIGNAL ;
    PORT
      LAYER M4 ;
        RECT  0 34.992 0.084 35.016 ;
    END
  END pw_data[159]
  PIN pw_data[15]
    DIRECTION OUTPUT ;
    USE SIGNAL ;
    PORT
      LAYER M4 ;
        RECT  0 3.888 0.084 3.912 ;
    END
  END pw_data[15]
  PIN pw_data[160]
    DIRECTION OUTPUT ;
    USE SIGNAL ;
    PORT
      LAYER M4 ;
        RECT  0 35.136 0.084 35.16 ;
    END
  END pw_data[160]
  PIN pw_data[161]
    DIRECTION OUTPUT ;
    USE SIGNAL ;
    PORT
      LAYER M4 ;
        RECT  0 35.28 0.084 35.304 ;
    END
  END pw_data[161]
  PIN pw_data[162]
    DIRECTION OUTPUT ;
    USE SIGNAL ;
    PORT
      LAYER M4 ;
        RECT  0 35.424 0.084 35.448 ;
    END
  END pw_data[162]
  PIN pw_data[163]
    DIRECTION OUTPUT ;
    USE SIGNAL ;
    PORT
      LAYER M4 ;
        RECT  0 35.568 0.084 35.592 ;
    END
  END pw_data[163]
  PIN pw_data[164]
    DIRECTION OUTPUT ;
    USE SIGNAL ;
    PORT
      LAYER M4 ;
        RECT  0 35.712 0.084 35.736 ;
    END
  END pw_data[164]
  PIN pw_data[165]
    DIRECTION OUTPUT ;
    USE SIGNAL ;
    PORT
      LAYER M4 ;
        RECT  0 35.856 0.084 35.88 ;
    END
  END pw_data[165]
  PIN pw_data[166]
    DIRECTION OUTPUT ;
    USE SIGNAL ;
    PORT
      LAYER M4 ;
        RECT  0 36 0.084 36.024 ;
    END
  END pw_data[166]
  PIN pw_data[167]
    DIRECTION OUTPUT ;
    USE SIGNAL ;
    PORT
      LAYER M4 ;
        RECT  0 36.144 0.084 36.168 ;
    END
  END pw_data[167]
  PIN pw_data[168]
    DIRECTION OUTPUT ;
    USE SIGNAL ;
    PORT
      LAYER M4 ;
        RECT  0 36.288 0.084 36.312 ;
    END
  END pw_data[168]
  PIN pw_data[169]
    DIRECTION OUTPUT ;
    USE SIGNAL ;
    PORT
      LAYER M4 ;
        RECT  0 36.432 0.084 36.456 ;
    END
  END pw_data[169]
  PIN pw_data[16]
    DIRECTION OUTPUT ;
    USE SIGNAL ;
    PORT
      LAYER M4 ;
        RECT  0 4.032 0.084 4.056 ;
    END
  END pw_data[16]
  PIN pw_data[170]
    DIRECTION OUTPUT ;
    USE SIGNAL ;
    PORT
      LAYER M4 ;
        RECT  0 36.576 0.084 36.6 ;
    END
  END pw_data[170]
  PIN pw_data[171]
    DIRECTION OUTPUT ;
    USE SIGNAL ;
    PORT
      LAYER M4 ;
        RECT  0 36.72 0.084 36.744 ;
    END
  END pw_data[171]
  PIN pw_data[172]
    DIRECTION OUTPUT ;
    USE SIGNAL ;
    PORT
      LAYER M4 ;
        RECT  0 36.864 0.084 36.888 ;
    END
  END pw_data[172]
  PIN pw_data[173]
    DIRECTION OUTPUT ;
    USE SIGNAL ;
    PORT
      LAYER M4 ;
        RECT  0 37.008 0.084 37.032 ;
    END
  END pw_data[173]
  PIN pw_data[174]
    DIRECTION OUTPUT ;
    USE SIGNAL ;
    PORT
      LAYER M4 ;
        RECT  0 37.152 0.084 37.176 ;
    END
  END pw_data[174]
  PIN pw_data[175]
    DIRECTION OUTPUT ;
    USE SIGNAL ;
    PORT
      LAYER M4 ;
        RECT  0 17.712 0.084 17.736 ;
    END
  END pw_data[175]
  PIN pw_data[176]
    DIRECTION OUTPUT ;
    USE SIGNAL ;
    PORT
      LAYER M4 ;
        RECT  0 17.856 0.084 17.88 ;
    END
  END pw_data[176]
  PIN pw_data[177]
    DIRECTION OUTPUT ;
    USE SIGNAL ;
    PORT
      LAYER M4 ;
        RECT  0 18 0.084 18.024 ;
    END
  END pw_data[177]
  PIN pw_data[178]
    DIRECTION OUTPUT ;
    USE SIGNAL ;
    PORT
      LAYER M4 ;
        RECT  0 18.144 0.084 18.168 ;
    END
  END pw_data[178]
  PIN pw_data[179]
    DIRECTION OUTPUT ;
    USE SIGNAL ;
    PORT
      LAYER M4 ;
        RECT  0 18.288 0.084 18.312 ;
    END
  END pw_data[179]
  PIN pw_data[17]
    DIRECTION OUTPUT ;
    USE SIGNAL ;
    PORT
      LAYER M4 ;
        RECT  0 4.176 0.084 4.2 ;
    END
  END pw_data[17]
  PIN pw_data[180]
    DIRECTION OUTPUT ;
    USE SIGNAL ;
    PORT
      LAYER M4 ;
        RECT  0 18.432 0.084 18.456 ;
    END
  END pw_data[180]
  PIN pw_data[181]
    DIRECTION OUTPUT ;
    USE SIGNAL ;
    PORT
      LAYER M4 ;
        RECT  0 18.576 0.084 18.6 ;
    END
  END pw_data[181]
  PIN pw_data[182]
    DIRECTION OUTPUT ;
    USE SIGNAL ;
    PORT
      LAYER M4 ;
        RECT  0 18.72 0.084 18.744 ;
    END
  END pw_data[182]
  PIN pw_data[183]
    DIRECTION OUTPUT ;
    USE SIGNAL ;
    PORT
      LAYER M4 ;
        RECT  0 18.864 0.084 18.888 ;
    END
  END pw_data[183]
  PIN pw_data[184]
    DIRECTION OUTPUT ;
    USE SIGNAL ;
    PORT
      LAYER M4 ;
        RECT  0 19.008 0.084 19.032 ;
    END
  END pw_data[184]
  PIN pw_data[185]
    DIRECTION OUTPUT ;
    USE SIGNAL ;
    PORT
      LAYER M4 ;
        RECT  0 19.152 0.084 19.176 ;
    END
  END pw_data[185]
  PIN pw_data[186]
    DIRECTION OUTPUT ;
    USE SIGNAL ;
    PORT
      LAYER M4 ;
        RECT  0 19.296 0.084 19.32 ;
    END
  END pw_data[186]
  PIN pw_data[187]
    DIRECTION OUTPUT ;
    USE SIGNAL ;
    PORT
      LAYER M4 ;
        RECT  0 19.44 0.084 19.464 ;
    END
  END pw_data[187]
  PIN pw_data[188]
    DIRECTION OUTPUT ;
    USE SIGNAL ;
    PORT
      LAYER M4 ;
        RECT  0 19.584 0.084 19.608 ;
    END
  END pw_data[188]
  PIN pw_data[189]
    DIRECTION OUTPUT ;
    USE SIGNAL ;
    PORT
      LAYER M4 ;
        RECT  0 19.728 0.084 19.752 ;
    END
  END pw_data[189]
  PIN pw_data[18]
    DIRECTION OUTPUT ;
    USE SIGNAL ;
    PORT
      LAYER M4 ;
        RECT  0 4.32 0.084 4.344 ;
    END
  END pw_data[18]
  PIN pw_data[190]
    DIRECTION OUTPUT ;
    USE SIGNAL ;
    PORT
      LAYER M4 ;
        RECT  0 19.872 0.084 19.896 ;
    END
  END pw_data[190]
  PIN pw_data[191]
    DIRECTION OUTPUT ;
    USE SIGNAL ;
    PORT
      LAYER M4 ;
        RECT  0 20.016 0.084 20.04 ;
    END
  END pw_data[191]
  PIN pw_data[192]
    DIRECTION OUTPUT ;
    USE SIGNAL ;
    PORT
      LAYER M4 ;
        RECT  0 20.16 0.084 20.184 ;
    END
  END pw_data[192]
  PIN pw_data[193]
    DIRECTION OUTPUT ;
    USE SIGNAL ;
    PORT
      LAYER M4 ;
        RECT  0 20.304 0.084 20.328 ;
    END
  END pw_data[193]
  PIN pw_data[194]
    DIRECTION OUTPUT ;
    USE SIGNAL ;
    PORT
      LAYER M4 ;
        RECT  0 20.448 0.084 20.472 ;
    END
  END pw_data[194]
  PIN pw_data[195]
    DIRECTION OUTPUT ;
    USE SIGNAL ;
    PORT
      LAYER M4 ;
        RECT  0 20.592 0.084 20.616 ;
    END
  END pw_data[195]
  PIN pw_data[196]
    DIRECTION OUTPUT ;
    USE SIGNAL ;
    PORT
      LAYER M4 ;
        RECT  0 20.736 0.084 20.76 ;
    END
  END pw_data[196]
  PIN pw_data[197]
    DIRECTION OUTPUT ;
    USE SIGNAL ;
    PORT
      LAYER M4 ;
        RECT  0 20.88 0.084 20.904 ;
    END
  END pw_data[197]
  PIN pw_data[198]
    DIRECTION OUTPUT ;
    USE SIGNAL ;
    PORT
      LAYER M4 ;
        RECT  0 21.024 0.084 21.048 ;
    END
  END pw_data[198]
  PIN pw_data[199]
    DIRECTION OUTPUT ;
    USE SIGNAL ;
    PORT
      LAYER M4 ;
        RECT  0 21.168 0.084 21.192 ;
    END
  END pw_data[199]
  PIN pw_data[19]
    DIRECTION OUTPUT ;
    USE SIGNAL ;
    PORT
      LAYER M4 ;
        RECT  0 4.464 0.084 4.488 ;
    END
  END pw_data[19]
  PIN pw_data[1]
    DIRECTION OUTPUT ;
    USE SIGNAL ;
    PORT
      LAYER M4 ;
        RECT  0 11.088 0.084 11.112 ;
    END
  END pw_data[1]
  PIN pw_data[200]
    DIRECTION OUTPUT ;
    USE SIGNAL ;
    PORT
      LAYER M4 ;
        RECT  0 21.312 0.084 21.336 ;
    END
  END pw_data[200]
  PIN pw_data[201]
    DIRECTION OUTPUT ;
    USE SIGNAL ;
    PORT
      LAYER M4 ;
        RECT  0 21.456 0.084 21.48 ;
    END
  END pw_data[201]
  PIN pw_data[202]
    DIRECTION OUTPUT ;
    USE SIGNAL ;
    PORT
      LAYER M4 ;
        RECT  0 21.6 0.084 21.624 ;
    END
  END pw_data[202]
  PIN pw_data[203]
    DIRECTION OUTPUT ;
    USE SIGNAL ;
    PORT
      LAYER M4 ;
        RECT  0 21.744 0.084 21.768 ;
    END
  END pw_data[203]
  PIN pw_data[204]
    DIRECTION OUTPUT ;
    USE SIGNAL ;
    PORT
      LAYER M4 ;
        RECT  0 21.888 0.084 21.912 ;
    END
  END pw_data[204]
  PIN pw_data[205]
    DIRECTION OUTPUT ;
    USE SIGNAL ;
    PORT
      LAYER M4 ;
        RECT  0 22.032 0.084 22.056 ;
    END
  END pw_data[205]
  PIN pw_data[206]
    DIRECTION OUTPUT ;
    USE SIGNAL ;
    PORT
      LAYER M4 ;
        RECT  0 22.176 0.084 22.2 ;
    END
  END pw_data[206]
  PIN pw_data[207]
    DIRECTION OUTPUT ;
    USE SIGNAL ;
    PORT
      LAYER M4 ;
        RECT  0 13.104 0.084 13.128 ;
    END
  END pw_data[207]
  PIN pw_data[208]
    DIRECTION OUTPUT ;
    USE SIGNAL ;
    PORT
      LAYER M4 ;
        RECT  0 13.248 0.084 13.272 ;
    END
  END pw_data[208]
  PIN pw_data[209]
    DIRECTION OUTPUT ;
    USE SIGNAL ;
    PORT
      LAYER M4 ;
        RECT  0 13.392 0.084 13.416 ;
    END
  END pw_data[209]
  PIN pw_data[20]
    DIRECTION OUTPUT ;
    USE SIGNAL ;
    PORT
      LAYER M4 ;
        RECT  0 4.608 0.084 4.632 ;
    END
  END pw_data[20]
  PIN pw_data[210]
    DIRECTION OUTPUT ;
    USE SIGNAL ;
    PORT
      LAYER M4 ;
        RECT  0 13.536 0.084 13.56 ;
    END
  END pw_data[210]
  PIN pw_data[211]
    DIRECTION OUTPUT ;
    USE SIGNAL ;
    PORT
      LAYER M4 ;
        RECT  0 13.68 0.084 13.704 ;
    END
  END pw_data[211]
  PIN pw_data[212]
    DIRECTION OUTPUT ;
    USE SIGNAL ;
    PORT
      LAYER M4 ;
        RECT  0 13.824 0.084 13.848 ;
    END
  END pw_data[212]
  PIN pw_data[213]
    DIRECTION OUTPUT ;
    USE SIGNAL ;
    PORT
      LAYER M4 ;
        RECT  0 13.968 0.084 13.992 ;
    END
  END pw_data[213]
  PIN pw_data[214]
    DIRECTION OUTPUT ;
    USE SIGNAL ;
    PORT
      LAYER M4 ;
        RECT  0 14.112 0.084 14.136 ;
    END
  END pw_data[214]
  PIN pw_data[215]
    DIRECTION OUTPUT ;
    USE SIGNAL ;
    PORT
      LAYER M4 ;
        RECT  0 14.256 0.084 14.28 ;
    END
  END pw_data[215]
  PIN pw_data[216]
    DIRECTION OUTPUT ;
    USE SIGNAL ;
    PORT
      LAYER M4 ;
        RECT  0 14.4 0.084 14.424 ;
    END
  END pw_data[216]
  PIN pw_data[217]
    DIRECTION OUTPUT ;
    USE SIGNAL ;
    PORT
      LAYER M4 ;
        RECT  0 14.544 0.084 14.568 ;
    END
  END pw_data[217]
  PIN pw_data[218]
    DIRECTION OUTPUT ;
    USE SIGNAL ;
    PORT
      LAYER M4 ;
        RECT  0 14.688 0.084 14.712 ;
    END
  END pw_data[218]
  PIN pw_data[219]
    DIRECTION OUTPUT ;
    USE SIGNAL ;
    PORT
      LAYER M4 ;
        RECT  0 14.832 0.084 14.856 ;
    END
  END pw_data[219]
  PIN pw_data[21]
    DIRECTION OUTPUT ;
    USE SIGNAL ;
    PORT
      LAYER M4 ;
        RECT  0 4.752 0.084 4.776 ;
    END
  END pw_data[21]
  PIN pw_data[220]
    DIRECTION OUTPUT ;
    USE SIGNAL ;
    PORT
      LAYER M4 ;
        RECT  0 14.976 0.084 15 ;
    END
  END pw_data[220]
  PIN pw_data[221]
    DIRECTION OUTPUT ;
    USE SIGNAL ;
    PORT
      LAYER M4 ;
        RECT  0 15.12 0.084 15.144 ;
    END
  END pw_data[221]
  PIN pw_data[222]
    DIRECTION OUTPUT ;
    USE SIGNAL ;
    PORT
      LAYER M4 ;
        RECT  0 15.264 0.084 15.288 ;
    END
  END pw_data[222]
  PIN pw_data[223]
    DIRECTION OUTPUT ;
    USE SIGNAL ;
    PORT
      LAYER M4 ;
        RECT  0 15.408 0.084 15.432 ;
    END
  END pw_data[223]
  PIN pw_data[224]
    DIRECTION OUTPUT ;
    USE SIGNAL ;
    PORT
      LAYER M4 ;
        RECT  0 15.552 0.084 15.576 ;
    END
  END pw_data[224]
  PIN pw_data[225]
    DIRECTION OUTPUT ;
    USE SIGNAL ;
    PORT
      LAYER M4 ;
        RECT  0 15.696 0.084 15.72 ;
    END
  END pw_data[225]
  PIN pw_data[226]
    DIRECTION OUTPUT ;
    USE SIGNAL ;
    PORT
      LAYER M4 ;
        RECT  0 15.84 0.084 15.864 ;
    END
  END pw_data[226]
  PIN pw_data[227]
    DIRECTION OUTPUT ;
    USE SIGNAL ;
    PORT
      LAYER M4 ;
        RECT  0 15.984 0.084 16.008 ;
    END
  END pw_data[227]
  PIN pw_data[228]
    DIRECTION OUTPUT ;
    USE SIGNAL ;
    PORT
      LAYER M4 ;
        RECT  0 16.128 0.084 16.152 ;
    END
  END pw_data[228]
  PIN pw_data[229]
    DIRECTION OUTPUT ;
    USE SIGNAL ;
    PORT
      LAYER M4 ;
        RECT  0 16.272 0.084 16.296 ;
    END
  END pw_data[229]
  PIN pw_data[22]
    DIRECTION OUTPUT ;
    USE SIGNAL ;
    PORT
      LAYER M4 ;
        RECT  0 4.896 0.084 4.92 ;
    END
  END pw_data[22]
  PIN pw_data[230]
    DIRECTION OUTPUT ;
    USE SIGNAL ;
    PORT
      LAYER M4 ;
        RECT  0 16.416 0.084 16.44 ;
    END
  END pw_data[230]
  PIN pw_data[231]
    DIRECTION OUTPUT ;
    USE SIGNAL ;
    PORT
      LAYER M4 ;
        RECT  0 16.56 0.084 16.584 ;
    END
  END pw_data[231]
  PIN pw_data[232]
    DIRECTION OUTPUT ;
    USE SIGNAL ;
    PORT
      LAYER M4 ;
        RECT  0 16.704 0.084 16.728 ;
    END
  END pw_data[232]
  PIN pw_data[233]
    DIRECTION OUTPUT ;
    USE SIGNAL ;
    PORT
      LAYER M4 ;
        RECT  0 16.848 0.084 16.872 ;
    END
  END pw_data[233]
  PIN pw_data[234]
    DIRECTION OUTPUT ;
    USE SIGNAL ;
    PORT
      LAYER M4 ;
        RECT  0 16.992 0.084 17.016 ;
    END
  END pw_data[234]
  PIN pw_data[235]
    DIRECTION OUTPUT ;
    USE SIGNAL ;
    PORT
      LAYER M4 ;
        RECT  0 17.136 0.084 17.16 ;
    END
  END pw_data[235]
  PIN pw_data[236]
    DIRECTION OUTPUT ;
    USE SIGNAL ;
    PORT
      LAYER M4 ;
        RECT  0 17.28 0.084 17.304 ;
    END
  END pw_data[236]
  PIN pw_data[237]
    DIRECTION OUTPUT ;
    USE SIGNAL ;
    PORT
      LAYER M4 ;
        RECT  0 17.424 0.084 17.448 ;
    END
  END pw_data[237]
  PIN pw_data[238]
    DIRECTION OUTPUT ;
    USE SIGNAL ;
    PORT
      LAYER M4 ;
        RECT  0 17.568 0.084 17.592 ;
    END
  END pw_data[238]
  PIN pw_data[239]
    DIRECTION OUTPUT ;
    USE SIGNAL ;
    PORT
      LAYER M4 ;
        RECT  0 1.008 0.084 1.032 ;
    END
  END pw_data[239]
  PIN pw_data[23]
    DIRECTION OUTPUT ;
    USE SIGNAL ;
    PORT
      LAYER M4 ;
        RECT  0 5.04 0.084 5.064 ;
    END
  END pw_data[23]
  PIN pw_data[240]
    DIRECTION OUTPUT ;
    USE SIGNAL ;
    PORT
      LAYER M4 ;
        RECT  0 1.152 0.084 1.176 ;
    END
  END pw_data[240]
  PIN pw_data[241]
    DIRECTION OUTPUT ;
    USE SIGNAL ;
    PORT
      LAYER M4 ;
        RECT  0 1.296 0.084 1.32 ;
    END
  END pw_data[241]
  PIN pw_data[242]
    DIRECTION OUTPUT ;
    USE SIGNAL ;
    PORT
      LAYER M4 ;
        RECT  0 1.44 0.084 1.464 ;
    END
  END pw_data[242]
  PIN pw_data[243]
    DIRECTION OUTPUT ;
    USE SIGNAL ;
    PORT
      LAYER M4 ;
        RECT  0 1.584 0.084 1.608 ;
    END
  END pw_data[243]
  PIN pw_data[244]
    DIRECTION OUTPUT ;
    USE SIGNAL ;
    PORT
      LAYER M4 ;
        RECT  0 1.728 0.084 1.752 ;
    END
  END pw_data[244]
  PIN pw_data[245]
    DIRECTION OUTPUT ;
    USE SIGNAL ;
    PORT
      LAYER M4 ;
        RECT  0 1.872 0.084 1.896 ;
    END
  END pw_data[245]
  PIN pw_data[246]
    DIRECTION OUTPUT ;
    USE SIGNAL ;
    PORT
      LAYER M4 ;
        RECT  0 2.016 0.084 2.04 ;
    END
  END pw_data[246]
  PIN pw_data[247]
    DIRECTION OUTPUT ;
    USE SIGNAL ;
    PORT
      LAYER M4 ;
        RECT  0 2.16 0.084 2.184 ;
    END
  END pw_data[247]
  PIN pw_data[248]
    DIRECTION OUTPUT ;
    USE SIGNAL ;
    PORT
      LAYER M4 ;
        RECT  0 2.304 0.084 2.328 ;
    END
  END pw_data[248]
  PIN pw_data[249]
    DIRECTION OUTPUT ;
    USE SIGNAL ;
    PORT
      LAYER M4 ;
        RECT  0 2.448 0.084 2.472 ;
    END
  END pw_data[249]
  PIN pw_data[24]
    DIRECTION OUTPUT ;
    USE SIGNAL ;
    PORT
      LAYER M4 ;
        RECT  0 5.184 0.084 5.208 ;
    END
  END pw_data[24]
  PIN pw_data[250]
    DIRECTION OUTPUT ;
    USE SIGNAL ;
    PORT
      LAYER M4 ;
        RECT  0 2.592 0.084 2.616 ;
    END
  END pw_data[250]
  PIN pw_data[251]
    DIRECTION OUTPUT ;
    USE SIGNAL ;
    PORT
      LAYER M4 ;
        RECT  0 2.736 0.084 2.76 ;
    END
  END pw_data[251]
  PIN pw_data[252]
    DIRECTION OUTPUT ;
    USE SIGNAL ;
    PORT
      LAYER M4 ;
        RECT  0 2.88 0.084 2.904 ;
    END
  END pw_data[252]
  PIN pw_data[253]
    DIRECTION OUTPUT ;
    USE SIGNAL ;
    PORT
      LAYER M4 ;
        RECT  0 3.024 0.084 3.048 ;
    END
  END pw_data[253]
  PIN pw_data[254]
    DIRECTION OUTPUT ;
    USE SIGNAL ;
    PORT
      LAYER M4 ;
        RECT  0 3.168 0.084 3.192 ;
    END
  END pw_data[254]
  PIN pw_data[255]
    DIRECTION OUTPUT ;
    USE SIGNAL ;
    PORT
      LAYER M4 ;
        RECT  0 3.312 0.084 3.336 ;
    END
  END pw_data[255]
  PIN pw_data[25]
    DIRECTION OUTPUT ;
    USE SIGNAL ;
    PORT
      LAYER M4 ;
        RECT  0 5.328 0.084 5.352 ;
    END
  END pw_data[25]
  PIN pw_data[26]
    DIRECTION OUTPUT ;
    USE SIGNAL ;
    PORT
      LAYER M4 ;
        RECT  0 5.472 0.084 5.496 ;
    END
  END pw_data[26]
  PIN pw_data[27]
    DIRECTION OUTPUT ;
    USE SIGNAL ;
    PORT
      LAYER M4 ;
        RECT  0 5.616 0.084 5.64 ;
    END
  END pw_data[27]
  PIN pw_data[28]
    DIRECTION OUTPUT ;
    USE SIGNAL ;
    PORT
      LAYER M4 ;
        RECT  0 5.76 0.084 5.784 ;
    END
  END pw_data[28]
  PIN pw_data[29]
    DIRECTION OUTPUT ;
    USE SIGNAL ;
    PORT
      LAYER M4 ;
        RECT  0 5.904 0.084 5.928 ;
    END
  END pw_data[29]
  PIN pw_data[2]
    DIRECTION OUTPUT ;
    USE SIGNAL ;
    PORT
      LAYER M4 ;
        RECT  0 11.232 0.084 11.256 ;
    END
  END pw_data[2]
  PIN pw_data[30]
    DIRECTION OUTPUT ;
    USE SIGNAL ;
    PORT
      LAYER M4 ;
        RECT  0 6.048 0.084 6.072 ;
    END
  END pw_data[30]
  PIN pw_data[31]
    DIRECTION OUTPUT ;
    USE SIGNAL ;
    PORT
      LAYER M4 ;
        RECT  0 6.192 0.084 6.216 ;
    END
  END pw_data[31]
  PIN pw_data[32]
    DIRECTION OUTPUT ;
    USE SIGNAL ;
    PORT
      LAYER M4 ;
        RECT  0 6.336 0.084 6.36 ;
    END
  END pw_data[32]
  PIN pw_data[33]
    DIRECTION OUTPUT ;
    USE SIGNAL ;
    PORT
      LAYER M4 ;
        RECT  0 6.48 0.084 6.504 ;
    END
  END pw_data[33]
  PIN pw_data[34]
    DIRECTION OUTPUT ;
    USE SIGNAL ;
    PORT
      LAYER M4 ;
        RECT  0 6.624 0.084 6.648 ;
    END
  END pw_data[34]
  PIN pw_data[35]
    DIRECTION OUTPUT ;
    USE SIGNAL ;
    PORT
      LAYER M4 ;
        RECT  0 6.768 0.084 6.792 ;
    END
  END pw_data[35]
  PIN pw_data[36]
    DIRECTION OUTPUT ;
    USE SIGNAL ;
    PORT
      LAYER M4 ;
        RECT  0 6.912 0.084 6.936 ;
    END
  END pw_data[36]
  PIN pw_data[37]
    DIRECTION OUTPUT ;
    USE SIGNAL ;
    PORT
      LAYER M4 ;
        RECT  0 7.056 0.084 7.08 ;
    END
  END pw_data[37]
  PIN pw_data[38]
    DIRECTION OUTPUT ;
    USE SIGNAL ;
    PORT
      LAYER M4 ;
        RECT  0 7.2 0.084 7.224 ;
    END
  END pw_data[38]
  PIN pw_data[39]
    DIRECTION OUTPUT ;
    USE SIGNAL ;
    PORT
      LAYER M4 ;
        RECT  0 7.344 0.084 7.368 ;
    END
  END pw_data[39]
  PIN pw_data[3]
    DIRECTION OUTPUT ;
    USE SIGNAL ;
    PORT
      LAYER M4 ;
        RECT  0 11.376 0.084 11.4 ;
    END
  END pw_data[3]
  PIN pw_data[40]
    DIRECTION OUTPUT ;
    USE SIGNAL ;
    PORT
      LAYER M4 ;
        RECT  0 7.488 0.084 7.512 ;
    END
  END pw_data[40]
  PIN pw_data[41]
    DIRECTION OUTPUT ;
    USE SIGNAL ;
    PORT
      LAYER M4 ;
        RECT  0 7.632 0.084 7.656 ;
    END
  END pw_data[41]
  PIN pw_data[42]
    DIRECTION OUTPUT ;
    USE SIGNAL ;
    PORT
      LAYER M4 ;
        RECT  0 7.776 0.084 7.8 ;
    END
  END pw_data[42]
  PIN pw_data[43]
    DIRECTION OUTPUT ;
    USE SIGNAL ;
    PORT
      LAYER M4 ;
        RECT  0 7.92 0.084 7.944 ;
    END
  END pw_data[43]
  PIN pw_data[44]
    DIRECTION OUTPUT ;
    USE SIGNAL ;
    PORT
      LAYER M4 ;
        RECT  0 8.064 0.084 8.088 ;
    END
  END pw_data[44]
  PIN pw_data[45]
    DIRECTION OUTPUT ;
    USE SIGNAL ;
    PORT
      LAYER M4 ;
        RECT  0 8.208 0.084 8.232 ;
    END
  END pw_data[45]
  PIN pw_data[46]
    DIRECTION OUTPUT ;
    USE SIGNAL ;
    PORT
      LAYER M4 ;
        RECT  0 8.352 0.084 8.376 ;
    END
  END pw_data[46]
  PIN pw_data[47]
    DIRECTION OUTPUT ;
    USE SIGNAL ;
    PORT
      LAYER M4 ;
        RECT  0 23.472 0.084 23.496 ;
    END
  END pw_data[47]
  PIN pw_data[48]
    DIRECTION OUTPUT ;
    USE SIGNAL ;
    PORT
      LAYER M4 ;
        RECT  0 23.616 0.084 23.64 ;
    END
  END pw_data[48]
  PIN pw_data[49]
    DIRECTION OUTPUT ;
    USE SIGNAL ;
    PORT
      LAYER M4 ;
        RECT  0 23.76 0.084 23.784 ;
    END
  END pw_data[49]
  PIN pw_data[4]
    DIRECTION OUTPUT ;
    USE SIGNAL ;
    PORT
      LAYER M4 ;
        RECT  0 11.52 0.084 11.544 ;
    END
  END pw_data[4]
  PIN pw_data[50]
    DIRECTION OUTPUT ;
    USE SIGNAL ;
    PORT
      LAYER M4 ;
        RECT  0 23.904 0.084 23.928 ;
    END
  END pw_data[50]
  PIN pw_data[51]
    DIRECTION OUTPUT ;
    USE SIGNAL ;
    PORT
      LAYER M4 ;
        RECT  0 24.048 0.084 24.072 ;
    END
  END pw_data[51]
  PIN pw_data[52]
    DIRECTION OUTPUT ;
    USE SIGNAL ;
    PORT
      LAYER M4 ;
        RECT  0 24.192 0.084 24.216 ;
    END
  END pw_data[52]
  PIN pw_data[53]
    DIRECTION OUTPUT ;
    USE SIGNAL ;
    PORT
      LAYER M4 ;
        RECT  0 24.336 0.084 24.36 ;
    END
  END pw_data[53]
  PIN pw_data[54]
    DIRECTION OUTPUT ;
    USE SIGNAL ;
    PORT
      LAYER M4 ;
        RECT  0 24.48 0.084 24.504 ;
    END
  END pw_data[54]
  PIN pw_data[55]
    DIRECTION OUTPUT ;
    USE SIGNAL ;
    PORT
      LAYER M4 ;
        RECT  0 24.624 0.084 24.648 ;
    END
  END pw_data[55]
  PIN pw_data[56]
    DIRECTION OUTPUT ;
    USE SIGNAL ;
    PORT
      LAYER M4 ;
        RECT  0 24.768 0.084 24.792 ;
    END
  END pw_data[56]
  PIN pw_data[57]
    DIRECTION OUTPUT ;
    USE SIGNAL ;
    PORT
      LAYER M4 ;
        RECT  0 24.912 0.084 24.936 ;
    END
  END pw_data[57]
  PIN pw_data[58]
    DIRECTION OUTPUT ;
    USE SIGNAL ;
    PORT
      LAYER M4 ;
        RECT  0 25.056 0.084 25.08 ;
    END
  END pw_data[58]
  PIN pw_data[59]
    DIRECTION OUTPUT ;
    USE SIGNAL ;
    PORT
      LAYER M4 ;
        RECT  0 25.2 0.084 25.224 ;
    END
  END pw_data[59]
  PIN pw_data[5]
    DIRECTION OUTPUT ;
    USE SIGNAL ;
    PORT
      LAYER M4 ;
        RECT  0 11.664 0.084 11.688 ;
    END
  END pw_data[5]
  PIN pw_data[60]
    DIRECTION OUTPUT ;
    USE SIGNAL ;
    PORT
      LAYER M4 ;
        RECT  0 25.344 0.084 25.368 ;
    END
  END pw_data[60]
  PIN pw_data[61]
    DIRECTION OUTPUT ;
    USE SIGNAL ;
    PORT
      LAYER M4 ;
        RECT  0 25.488 0.084 25.512 ;
    END
  END pw_data[61]
  PIN pw_data[62]
    DIRECTION OUTPUT ;
    USE SIGNAL ;
    PORT
      LAYER M4 ;
        RECT  0 25.632 0.084 25.656 ;
    END
  END pw_data[62]
  PIN pw_data[63]
    DIRECTION OUTPUT ;
    USE SIGNAL ;
    PORT
      LAYER M4 ;
        RECT  0 25.776 0.084 25.8 ;
    END
  END pw_data[63]
  PIN pw_data[64]
    DIRECTION OUTPUT ;
    USE SIGNAL ;
    PORT
      LAYER M4 ;
        RECT  0 25.92 0.084 25.944 ;
    END
  END pw_data[64]
  PIN pw_data[65]
    DIRECTION OUTPUT ;
    USE SIGNAL ;
    PORT
      LAYER M4 ;
        RECT  0 26.064 0.084 26.088 ;
    END
  END pw_data[65]
  PIN pw_data[66]
    DIRECTION OUTPUT ;
    USE SIGNAL ;
    PORT
      LAYER M4 ;
        RECT  0 26.208 0.084 26.232 ;
    END
  END pw_data[66]
  PIN pw_data[67]
    DIRECTION OUTPUT ;
    USE SIGNAL ;
    PORT
      LAYER M4 ;
        RECT  0 26.352 0.084 26.376 ;
    END
  END pw_data[67]
  PIN pw_data[68]
    DIRECTION OUTPUT ;
    USE SIGNAL ;
    PORT
      LAYER M4 ;
        RECT  0 26.496 0.084 26.52 ;
    END
  END pw_data[68]
  PIN pw_data[69]
    DIRECTION OUTPUT ;
    USE SIGNAL ;
    PORT
      LAYER M4 ;
        RECT  0 26.64 0.084 26.664 ;
    END
  END pw_data[69]
  PIN pw_data[6]
    DIRECTION OUTPUT ;
    USE SIGNAL ;
    PORT
      LAYER M4 ;
        RECT  0 11.808 0.084 11.832 ;
    END
  END pw_data[6]
  PIN pw_data[70]
    DIRECTION OUTPUT ;
    USE SIGNAL ;
    PORT
      LAYER M4 ;
        RECT  0 26.784 0.084 26.808 ;
    END
  END pw_data[70]
  PIN pw_data[71]
    DIRECTION OUTPUT ;
    USE SIGNAL ;
    PORT
      LAYER M4 ;
        RECT  0 26.928 0.084 26.952 ;
    END
  END pw_data[71]
  PIN pw_data[72]
    DIRECTION OUTPUT ;
    USE SIGNAL ;
    PORT
      LAYER M4 ;
        RECT  0 27.072 0.084 27.096 ;
    END
  END pw_data[72]
  PIN pw_data[73]
    DIRECTION OUTPUT ;
    USE SIGNAL ;
    PORT
      LAYER M4 ;
        RECT  0 27.216 0.084 27.24 ;
    END
  END pw_data[73]
  PIN pw_data[74]
    DIRECTION OUTPUT ;
    USE SIGNAL ;
    PORT
      LAYER M4 ;
        RECT  0 27.36 0.084 27.384 ;
    END
  END pw_data[74]
  PIN pw_data[75]
    DIRECTION OUTPUT ;
    USE SIGNAL ;
    PORT
      LAYER M4 ;
        RECT  0 27.504 0.084 27.528 ;
    END
  END pw_data[75]
  PIN pw_data[76]
    DIRECTION OUTPUT ;
    USE SIGNAL ;
    PORT
      LAYER M4 ;
        RECT  0 27.648 0.084 27.672 ;
    END
  END pw_data[76]
  PIN pw_data[77]
    DIRECTION OUTPUT ;
    USE SIGNAL ;
    PORT
      LAYER M4 ;
        RECT  0 27.792 0.084 27.816 ;
    END
  END pw_data[77]
  PIN pw_data[78]
    DIRECTION OUTPUT ;
    USE SIGNAL ;
    PORT
      LAYER M4 ;
        RECT  0 27.936 0.084 27.96 ;
    END
  END pw_data[78]
  PIN pw_data[79]
    DIRECTION OUTPUT ;
    USE SIGNAL ;
    PORT
      LAYER M4 ;
        RECT  0 37.296 0.084 37.32 ;
    END
  END pw_data[79]
  PIN pw_data[7]
    DIRECTION OUTPUT ;
    USE SIGNAL ;
    PORT
      LAYER M4 ;
        RECT  0 11.952 0.084 11.976 ;
    END
  END pw_data[7]
  PIN pw_data[80]
    DIRECTION OUTPUT ;
    USE SIGNAL ;
    PORT
      LAYER M4 ;
        RECT  0 37.44 0.084 37.464 ;
    END
  END pw_data[80]
  PIN pw_data[81]
    DIRECTION OUTPUT ;
    USE SIGNAL ;
    PORT
      LAYER M4 ;
        RECT  0 37.584 0.084 37.608 ;
    END
  END pw_data[81]
  PIN pw_data[82]
    DIRECTION OUTPUT ;
    USE SIGNAL ;
    PORT
      LAYER M4 ;
        RECT  0 37.728 0.084 37.752 ;
    END
  END pw_data[82]
  PIN pw_data[83]
    DIRECTION OUTPUT ;
    USE SIGNAL ;
    PORT
      LAYER M4 ;
        RECT  0 37.872 0.084 37.896 ;
    END
  END pw_data[83]
  PIN pw_data[84]
    DIRECTION OUTPUT ;
    USE SIGNAL ;
    PORT
      LAYER M4 ;
        RECT  0 38.016 0.084 38.04 ;
    END
  END pw_data[84]
  PIN pw_data[85]
    DIRECTION OUTPUT ;
    USE SIGNAL ;
    PORT
      LAYER M4 ;
        RECT  0 38.16 0.084 38.184 ;
    END
  END pw_data[85]
  PIN pw_data[86]
    DIRECTION OUTPUT ;
    USE SIGNAL ;
    PORT
      LAYER M4 ;
        RECT  0 38.304 0.084 38.328 ;
    END
  END pw_data[86]
  PIN pw_data[87]
    DIRECTION OUTPUT ;
    USE SIGNAL ;
    PORT
      LAYER M4 ;
        RECT  0 38.448 0.084 38.472 ;
    END
  END pw_data[87]
  PIN pw_data[88]
    DIRECTION OUTPUT ;
    USE SIGNAL ;
    PORT
      LAYER M4 ;
        RECT  0 38.592 0.084 38.616 ;
    END
  END pw_data[88]
  PIN pw_data[89]
    DIRECTION OUTPUT ;
    USE SIGNAL ;
    PORT
      LAYER M4 ;
        RECT  0 38.736 0.084 38.76 ;
    END
  END pw_data[89]
  PIN pw_data[8]
    DIRECTION OUTPUT ;
    USE SIGNAL ;
    PORT
      LAYER M4 ;
        RECT  0 12.096 0.084 12.12 ;
    END
  END pw_data[8]
  PIN pw_data[90]
    DIRECTION OUTPUT ;
    USE SIGNAL ;
    PORT
      LAYER M4 ;
        RECT  0 38.88 0.084 38.904 ;
    END
  END pw_data[90]
  PIN pw_data[91]
    DIRECTION OUTPUT ;
    USE SIGNAL ;
    PORT
      LAYER M4 ;
        RECT  0 39.024 0.084 39.048 ;
    END
  END pw_data[91]
  PIN pw_data[92]
    DIRECTION OUTPUT ;
    USE SIGNAL ;
    PORT
      LAYER M4 ;
        RECT  0 39.168 0.084 39.192 ;
    END
  END pw_data[92]
  PIN pw_data[93]
    DIRECTION OUTPUT ;
    USE SIGNAL ;
    PORT
      LAYER M4 ;
        RECT  0 39.312 0.084 39.336 ;
    END
  END pw_data[93]
  PIN pw_data[94]
    DIRECTION OUTPUT ;
    USE SIGNAL ;
    PORT
      LAYER M4 ;
        RECT  0 39.456 0.084 39.48 ;
    END
  END pw_data[94]
  PIN pw_data[95]
    DIRECTION OUTPUT ;
    USE SIGNAL ;
    PORT
      LAYER M4 ;
        RECT  0 39.6 0.084 39.624 ;
    END
  END pw_data[95]
  PIN pw_data[96]
    DIRECTION OUTPUT ;
    USE SIGNAL ;
    PORT
      LAYER M4 ;
        RECT  0 39.744 0.084 39.768 ;
    END
  END pw_data[96]
  PIN pw_data[97]
    DIRECTION OUTPUT ;
    USE SIGNAL ;
    PORT
      LAYER M4 ;
        RECT  0 39.888 0.084 39.912 ;
    END
  END pw_data[97]
  PIN pw_data[98]
    DIRECTION OUTPUT ;
    USE SIGNAL ;
    PORT
      LAYER M4 ;
        RECT  0 40.032 0.084 40.056 ;
    END
  END pw_data[98]
  PIN pw_data[99]
    DIRECTION OUTPUT ;
    USE SIGNAL ;
    PORT
      LAYER M4 ;
        RECT  0 40.176 0.084 40.2 ;
    END
  END pw_data[99]
  PIN pw_data[9]
    DIRECTION OUTPUT ;
    USE SIGNAL ;
    PORT
      LAYER M4 ;
        RECT  0 12.24 0.084 12.264 ;
    END
  END pw_data[9]
  PIN pw_we[0]
    DIRECTION OUTPUT ;
    USE SIGNAL ;
    PORT
      LAYER M4 ;
        RECT  0 3.456 0.084 3.48 ;
    END
  END pw_we[0]
  PIN pw_we[1]
    DIRECTION OUTPUT ;
    USE SIGNAL ;
    PORT
      LAYER M4 ;
        RECT  0 3.6 0.084 3.624 ;
    END
  END pw_we[1]
  PIN ready
    DIRECTION OUTPUT ;
    USE SIGNAL ;
    PORT
      LAYER M4 ;
        RECT  51.756 18.432 51.84 18.456 ;
    END
  END ready
  PIN rec[0]
    DIRECTION OUTPUT ;
    USE SIGNAL ;
    PORT
      LAYER M5 ;
        RECT  38.88 0 38.904 0.084 ;
    END
  END rec[0]
  PIN rec[100]
    DIRECTION OUTPUT ;
    USE SIGNAL ;
    PORT
      LAYER M5 ;
        RECT  34.848 0 34.872 0.084 ;
    END
  END rec[100]
  PIN rec[101]
    DIRECTION OUTPUT ;
    USE SIGNAL ;
    PORT
      LAYER M5 ;
        RECT  34.992 0 35.016 0.084 ;
    END
  END rec[101]
  PIN rec[102]
    DIRECTION OUTPUT ;
    USE SIGNAL ;
    PORT
      LAYER M5 ;
        RECT  35.136 0 35.16 0.084 ;
    END
  END rec[102]
  PIN rec[103]
    DIRECTION OUTPUT ;
    USE SIGNAL ;
    PORT
      LAYER M5 ;
        RECT  35.28 0 35.304 0.084 ;
    END
  END rec[103]
  PIN rec[104]
    DIRECTION OUTPUT ;
    USE SIGNAL ;
    PORT
      LAYER M5 ;
        RECT  35.424 0 35.448 0.084 ;
    END
  END rec[104]
  PIN rec[105]
    DIRECTION OUTPUT ;
    USE SIGNAL ;
    PORT
      LAYER M5 ;
        RECT  35.568 0 35.592 0.084 ;
    END
  END rec[105]
  PIN rec[106]
    DIRECTION OUTPUT ;
    USE SIGNAL ;
    PORT
      LAYER M5 ;
        RECT  35.712 0 35.736 0.084 ;
    END
  END rec[106]
  PIN rec[107]
    DIRECTION OUTPUT ;
    USE SIGNAL ;
    PORT
      LAYER M5 ;
        RECT  35.856 0 35.88 0.084 ;
    END
  END rec[107]
  PIN rec[108]
    DIRECTION OUTPUT ;
    USE SIGNAL ;
    PORT
      LAYER M5 ;
        RECT  36 0 36.024 0.084 ;
    END
  END rec[108]
  PIN rec[109]
    DIRECTION OUTPUT ;
    USE SIGNAL ;
    PORT
      LAYER M5 ;
        RECT  36.144 0 36.168 0.084 ;
    END
  END rec[109]
  PIN rec[10]
    DIRECTION OUTPUT ;
    USE SIGNAL ;
    PORT
      LAYER M5 ;
        RECT  40.32 0 40.344 0.084 ;
    END
  END rec[10]
  PIN rec[110]
    DIRECTION OUTPUT ;
    USE SIGNAL ;
    PORT
      LAYER M5 ;
        RECT  36.288 0 36.312 0.084 ;
    END
  END rec[110]
  PIN rec[111]
    DIRECTION OUTPUT ;
    USE SIGNAL ;
    PORT
      LAYER M5 ;
        RECT  36.432 0 36.456 0.084 ;
    END
  END rec[111]
  PIN rec[112]
    DIRECTION OUTPUT ;
    USE SIGNAL ;
    PORT
      LAYER M5 ;
        RECT  36.576 0 36.6 0.084 ;
    END
  END rec[112]
  PIN rec[113]
    DIRECTION OUTPUT ;
    USE SIGNAL ;
    PORT
      LAYER M5 ;
        RECT  36.72 0 36.744 0.084 ;
    END
  END rec[113]
  PIN rec[114]
    DIRECTION OUTPUT ;
    USE SIGNAL ;
    PORT
      LAYER M5 ;
        RECT  36.864 0 36.888 0.084 ;
    END
  END rec[114]
  PIN rec[115]
    DIRECTION OUTPUT ;
    USE SIGNAL ;
    PORT
      LAYER M5 ;
        RECT  37.008 0 37.032 0.084 ;
    END
  END rec[115]
  PIN rec[116]
    DIRECTION OUTPUT ;
    USE SIGNAL ;
    PORT
      LAYER M5 ;
        RECT  37.152 0 37.176 0.084 ;
    END
  END rec[116]
  PIN rec[117]
    DIRECTION OUTPUT ;
    USE SIGNAL ;
    PORT
      LAYER M5 ;
        RECT  37.296 0 37.32 0.084 ;
    END
  END rec[117]
  PIN rec[118]
    DIRECTION OUTPUT ;
    USE SIGNAL ;
    PORT
      LAYER M5 ;
        RECT  37.44 0 37.464 0.084 ;
    END
  END rec[118]
  PIN rec[119]
    DIRECTION OUTPUT ;
    USE SIGNAL ;
    PORT
      LAYER M5 ;
        RECT  37.584 0 37.608 0.084 ;
    END
  END rec[119]
  PIN rec[11]
    DIRECTION OUTPUT ;
    USE SIGNAL ;
    PORT
      LAYER M5 ;
        RECT  40.464 0 40.488 0.084 ;
    END
  END rec[11]
  PIN rec[120]
    DIRECTION OUTPUT ;
    USE SIGNAL ;
    PORT
      LAYER M5 ;
        RECT  37.728 0 37.752 0.084 ;
    END
  END rec[120]
  PIN rec[121]
    DIRECTION OUTPUT ;
    USE SIGNAL ;
    PORT
      LAYER M5 ;
        RECT  37.872 0 37.896 0.084 ;
    END
  END rec[121]
  PIN rec[122]
    DIRECTION OUTPUT ;
    USE SIGNAL ;
    PORT
      LAYER M5 ;
        RECT  38.016 0 38.04 0.084 ;
    END
  END rec[122]
  PIN rec[123]
    DIRECTION OUTPUT ;
    USE SIGNAL ;
    PORT
      LAYER M5 ;
        RECT  38.16 0 38.184 0.084 ;
    END
  END rec[123]
  PIN rec[124]
    DIRECTION OUTPUT ;
    USE SIGNAL ;
    PORT
      LAYER M5 ;
        RECT  38.304 0 38.328 0.084 ;
    END
  END rec[124]
  PIN rec[125]
    DIRECTION OUTPUT ;
    USE SIGNAL ;
    PORT
      LAYER M5 ;
        RECT  38.448 0 38.472 0.084 ;
    END
  END rec[125]
  PIN rec[126]
    DIRECTION OUTPUT ;
    USE SIGNAL ;
    PORT
      LAYER M5 ;
        RECT  38.592 0 38.616 0.084 ;
    END
  END rec[126]
  PIN rec[127]
    DIRECTION OUTPUT ;
    USE SIGNAL ;
    PORT
      LAYER M5 ;
        RECT  19.152 0 19.176 0.084 ;
    END
  END rec[127]
  PIN rec[128]
    DIRECTION OUTPUT ;
    USE SIGNAL ;
    PORT
      LAYER M5 ;
        RECT  19.296 0 19.32 0.084 ;
    END
  END rec[128]
  PIN rec[129]
    DIRECTION OUTPUT ;
    USE SIGNAL ;
    PORT
      LAYER M5 ;
        RECT  19.44 0 19.464 0.084 ;
    END
  END rec[129]
  PIN rec[12]
    DIRECTION OUTPUT ;
    USE SIGNAL ;
    PORT
      LAYER M5 ;
        RECT  40.608 0 40.632 0.084 ;
    END
  END rec[12]
  PIN rec[130]
    DIRECTION OUTPUT ;
    USE SIGNAL ;
    PORT
      LAYER M5 ;
        RECT  19.584 0 19.608 0.084 ;
    END
  END rec[130]
  PIN rec[131]
    DIRECTION OUTPUT ;
    USE SIGNAL ;
    PORT
      LAYER M5 ;
        RECT  19.728 0 19.752 0.084 ;
    END
  END rec[131]
  PIN rec[132]
    DIRECTION OUTPUT ;
    USE SIGNAL ;
    PORT
      LAYER M5 ;
        RECT  19.872 0 19.896 0.084 ;
    END
  END rec[132]
  PIN rec[133]
    DIRECTION OUTPUT ;
    USE SIGNAL ;
    PORT
      LAYER M5 ;
        RECT  20.016 0 20.04 0.084 ;
    END
  END rec[133]
  PIN rec[134]
    DIRECTION OUTPUT ;
    USE SIGNAL ;
    PORT
      LAYER M5 ;
        RECT  20.16 0 20.184 0.084 ;
    END
  END rec[134]
  PIN rec[135]
    DIRECTION OUTPUT ;
    USE SIGNAL ;
    PORT
      LAYER M5 ;
        RECT  20.304 0 20.328 0.084 ;
    END
  END rec[135]
  PIN rec[136]
    DIRECTION OUTPUT ;
    USE SIGNAL ;
    PORT
      LAYER M5 ;
        RECT  20.448 0 20.472 0.084 ;
    END
  END rec[136]
  PIN rec[137]
    DIRECTION OUTPUT ;
    USE SIGNAL ;
    PORT
      LAYER M5 ;
        RECT  20.592 0 20.616 0.084 ;
    END
  END rec[137]
  PIN rec[138]
    DIRECTION OUTPUT ;
    USE SIGNAL ;
    PORT
      LAYER M5 ;
        RECT  20.736 0 20.76 0.084 ;
    END
  END rec[138]
  PIN rec[139]
    DIRECTION OUTPUT ;
    USE SIGNAL ;
    PORT
      LAYER M5 ;
        RECT  20.88 0 20.904 0.084 ;
    END
  END rec[139]
  PIN rec[13]
    DIRECTION OUTPUT ;
    USE SIGNAL ;
    PORT
      LAYER M5 ;
        RECT  40.752 0 40.776 0.084 ;
    END
  END rec[13]
  PIN rec[140]
    DIRECTION OUTPUT ;
    USE SIGNAL ;
    PORT
      LAYER M5 ;
        RECT  21.024 0 21.048 0.084 ;
    END
  END rec[140]
  PIN rec[141]
    DIRECTION OUTPUT ;
    USE SIGNAL ;
    PORT
      LAYER M5 ;
        RECT  21.168 0 21.192 0.084 ;
    END
  END rec[141]
  PIN rec[142]
    DIRECTION OUTPUT ;
    USE SIGNAL ;
    PORT
      LAYER M5 ;
        RECT  21.312 0 21.336 0.084 ;
    END
  END rec[142]
  PIN rec[143]
    DIRECTION OUTPUT ;
    USE SIGNAL ;
    PORT
      LAYER M5 ;
        RECT  21.456 0 21.48 0.084 ;
    END
  END rec[143]
  PIN rec[144]
    DIRECTION OUTPUT ;
    USE SIGNAL ;
    PORT
      LAYER M5 ;
        RECT  21.6 0 21.624 0.084 ;
    END
  END rec[144]
  PIN rec[145]
    DIRECTION OUTPUT ;
    USE SIGNAL ;
    PORT
      LAYER M5 ;
        RECT  21.744 0 21.768 0.084 ;
    END
  END rec[145]
  PIN rec[146]
    DIRECTION OUTPUT ;
    USE SIGNAL ;
    PORT
      LAYER M5 ;
        RECT  21.888 0 21.912 0.084 ;
    END
  END rec[146]
  PIN rec[147]
    DIRECTION OUTPUT ;
    USE SIGNAL ;
    PORT
      LAYER M5 ;
        RECT  22.032 0 22.056 0.084 ;
    END
  END rec[147]
  PIN rec[148]
    DIRECTION OUTPUT ;
    USE SIGNAL ;
    PORT
      LAYER M5 ;
        RECT  22.176 0 22.2 0.084 ;
    END
  END rec[148]
  PIN rec[149]
    DIRECTION OUTPUT ;
    USE SIGNAL ;
    PORT
      LAYER M5 ;
        RECT  22.32 0 22.344 0.084 ;
    END
  END rec[149]
  PIN rec[14]
    DIRECTION OUTPUT ;
    USE SIGNAL ;
    PORT
      LAYER M5 ;
        RECT  40.896 0 40.92 0.084 ;
    END
  END rec[14]
  PIN rec[150]
    DIRECTION OUTPUT ;
    USE SIGNAL ;
    PORT
      LAYER M5 ;
        RECT  22.464 0 22.488 0.084 ;
    END
  END rec[150]
  PIN rec[151]
    DIRECTION OUTPUT ;
    USE SIGNAL ;
    PORT
      LAYER M5 ;
        RECT  22.608 0 22.632 0.084 ;
    END
  END rec[151]
  PIN rec[152]
    DIRECTION OUTPUT ;
    USE SIGNAL ;
    PORT
      LAYER M5 ;
        RECT  22.752 0 22.776 0.084 ;
    END
  END rec[152]
  PIN rec[153]
    DIRECTION OUTPUT ;
    USE SIGNAL ;
    PORT
      LAYER M5 ;
        RECT  22.896 0 22.92 0.084 ;
    END
  END rec[153]
  PIN rec[154]
    DIRECTION OUTPUT ;
    USE SIGNAL ;
    PORT
      LAYER M5 ;
        RECT  23.04 0 23.064 0.084 ;
    END
  END rec[154]
  PIN rec[155]
    DIRECTION OUTPUT ;
    USE SIGNAL ;
    PORT
      LAYER M5 ;
        RECT  23.184 0 23.208 0.084 ;
    END
  END rec[155]
  PIN rec[156]
    DIRECTION OUTPUT ;
    USE SIGNAL ;
    PORT
      LAYER M5 ;
        RECT  23.328 0 23.352 0.084 ;
    END
  END rec[156]
  PIN rec[157]
    DIRECTION OUTPUT ;
    USE SIGNAL ;
    PORT
      LAYER M5 ;
        RECT  23.472 0 23.496 0.084 ;
    END
  END rec[157]
  PIN rec[158]
    DIRECTION OUTPUT ;
    USE SIGNAL ;
    PORT
      LAYER M5 ;
        RECT  23.616 0 23.64 0.084 ;
    END
  END rec[158]
  PIN rec[159]
    DIRECTION OUTPUT ;
    USE SIGNAL ;
    PORT
      LAYER M5 ;
        RECT  23.76 0 23.784 0.084 ;
    END
  END rec[159]
  PIN rec[15]
    DIRECTION OUTPUT ;
    USE SIGNAL ;
    PORT
      LAYER M5 ;
        RECT  41.04 0 41.064 0.084 ;
    END
  END rec[15]
  PIN rec[160]
    DIRECTION OUTPUT ;
    USE SIGNAL ;
    PORT
      LAYER M5 ;
        RECT  23.904 0 23.928 0.084 ;
    END
  END rec[160]
  PIN rec[161]
    DIRECTION OUTPUT ;
    USE SIGNAL ;
    PORT
      LAYER M5 ;
        RECT  24.048 0 24.072 0.084 ;
    END
  END rec[161]
  PIN rec[162]
    DIRECTION OUTPUT ;
    USE SIGNAL ;
    PORT
      LAYER M5 ;
        RECT  24.192 0 24.216 0.084 ;
    END
  END rec[162]
  PIN rec[163]
    DIRECTION OUTPUT ;
    USE SIGNAL ;
    PORT
      LAYER M5 ;
        RECT  24.336 0 24.36 0.084 ;
    END
  END rec[163]
  PIN rec[164]
    DIRECTION OUTPUT ;
    USE SIGNAL ;
    PORT
      LAYER M5 ;
        RECT  24.48 0 24.504 0.084 ;
    END
  END rec[164]
  PIN rec[165]
    DIRECTION OUTPUT ;
    USE SIGNAL ;
    PORT
      LAYER M5 ;
        RECT  24.624 0 24.648 0.084 ;
    END
  END rec[165]
  PIN rec[166]
    DIRECTION OUTPUT ;
    USE SIGNAL ;
    PORT
      LAYER M5 ;
        RECT  24.768 0 24.792 0.084 ;
    END
  END rec[166]
  PIN rec[167]
    DIRECTION OUTPUT ;
    USE SIGNAL ;
    PORT
      LAYER M5 ;
        RECT  24.912 0 24.936 0.084 ;
    END
  END rec[167]
  PIN rec[168]
    DIRECTION OUTPUT ;
    USE SIGNAL ;
    PORT
      LAYER M5 ;
        RECT  25.056 0 25.08 0.084 ;
    END
  END rec[168]
  PIN rec[169]
    DIRECTION OUTPUT ;
    USE SIGNAL ;
    PORT
      LAYER M5 ;
        RECT  25.2 0 25.224 0.084 ;
    END
  END rec[169]
  PIN rec[16]
    DIRECTION OUTPUT ;
    USE SIGNAL ;
    PORT
      LAYER M5 ;
        RECT  41.184 0 41.208 0.084 ;
    END
  END rec[16]
  PIN rec[170]
    DIRECTION OUTPUT ;
    USE SIGNAL ;
    PORT
      LAYER M5 ;
        RECT  25.344 0 25.368 0.084 ;
    END
  END rec[170]
  PIN rec[171]
    DIRECTION OUTPUT ;
    USE SIGNAL ;
    PORT
      LAYER M5 ;
        RECT  25.488 0 25.512 0.084 ;
    END
  END rec[171]
  PIN rec[172]
    DIRECTION OUTPUT ;
    USE SIGNAL ;
    PORT
      LAYER M5 ;
        RECT  25.632 0 25.656 0.084 ;
    END
  END rec[172]
  PIN rec[173]
    DIRECTION OUTPUT ;
    USE SIGNAL ;
    PORT
      LAYER M5 ;
        RECT  25.776 0 25.8 0.084 ;
    END
  END rec[173]
  PIN rec[174]
    DIRECTION OUTPUT ;
    USE SIGNAL ;
    PORT
      LAYER M5 ;
        RECT  25.92 0 25.944 0.084 ;
    END
  END rec[174]
  PIN rec[175]
    DIRECTION OUTPUT ;
    USE SIGNAL ;
    PORT
      LAYER M5 ;
        RECT  26.064 0 26.088 0.084 ;
    END
  END rec[175]
  PIN rec[176]
    DIRECTION OUTPUT ;
    USE SIGNAL ;
    PORT
      LAYER M5 ;
        RECT  26.208 0 26.232 0.084 ;
    END
  END rec[176]
  PIN rec[177]
    DIRECTION OUTPUT ;
    USE SIGNAL ;
    PORT
      LAYER M5 ;
        RECT  26.352 0 26.376 0.084 ;
    END
  END rec[177]
  PIN rec[178]
    DIRECTION OUTPUT ;
    USE SIGNAL ;
    PORT
      LAYER M5 ;
        RECT  26.496 0 26.52 0.084 ;
    END
  END rec[178]
  PIN rec[179]
    DIRECTION OUTPUT ;
    USE SIGNAL ;
    PORT
      LAYER M5 ;
        RECT  26.64 0 26.664 0.084 ;
    END
  END rec[179]
  PIN rec[17]
    DIRECTION OUTPUT ;
    USE SIGNAL ;
    PORT
      LAYER M5 ;
        RECT  41.328 0 41.352 0.084 ;
    END
  END rec[17]
  PIN rec[180]
    DIRECTION OUTPUT ;
    USE SIGNAL ;
    PORT
      LAYER M5 ;
        RECT  26.784 0 26.808 0.084 ;
    END
  END rec[180]
  PIN rec[181]
    DIRECTION OUTPUT ;
    USE SIGNAL ;
    PORT
      LAYER M5 ;
        RECT  26.928 0 26.952 0.084 ;
    END
  END rec[181]
  PIN rec[182]
    DIRECTION OUTPUT ;
    USE SIGNAL ;
    PORT
      LAYER M5 ;
        RECT  27.072 0 27.096 0.084 ;
    END
  END rec[182]
  PIN rec[183]
    DIRECTION OUTPUT ;
    USE SIGNAL ;
    PORT
      LAYER M5 ;
        RECT  27.216 0 27.24 0.084 ;
    END
  END rec[183]
  PIN rec[184]
    DIRECTION OUTPUT ;
    USE SIGNAL ;
    PORT
      LAYER M5 ;
        RECT  27.36 0 27.384 0.084 ;
    END
  END rec[184]
  PIN rec[185]
    DIRECTION OUTPUT ;
    USE SIGNAL ;
    PORT
      LAYER M5 ;
        RECT  27.504 0 27.528 0.084 ;
    END
  END rec[185]
  PIN rec[186]
    DIRECTION OUTPUT ;
    USE SIGNAL ;
    PORT
      LAYER M5 ;
        RECT  27.648 0 27.672 0.084 ;
    END
  END rec[186]
  PIN rec[187]
    DIRECTION OUTPUT ;
    USE SIGNAL ;
    PORT
      LAYER M5 ;
        RECT  27.792 0 27.816 0.084 ;
    END
  END rec[187]
  PIN rec[188]
    DIRECTION OUTPUT ;
    USE SIGNAL ;
    PORT
      LAYER M5 ;
        RECT  27.936 0 27.96 0.084 ;
    END
  END rec[188]
  PIN rec[189]
    DIRECTION OUTPUT ;
    USE SIGNAL ;
    PORT
      LAYER M5 ;
        RECT  28.08 0 28.104 0.084 ;
    END
  END rec[189]
  PIN rec[18]
    DIRECTION OUTPUT ;
    USE SIGNAL ;
    PORT
      LAYER M5 ;
        RECT  41.472 0 41.496 0.084 ;
    END
  END rec[18]
  PIN rec[190]
    DIRECTION OUTPUT ;
    USE SIGNAL ;
    PORT
      LAYER M5 ;
        RECT  28.224 0 28.248 0.084 ;
    END
  END rec[190]
  PIN rec[191]
    DIRECTION OUTPUT ;
    USE SIGNAL ;
    PORT
      LAYER M5 ;
        RECT  14.544 0 14.568 0.084 ;
    END
  END rec[191]
  PIN rec[192]
    DIRECTION OUTPUT ;
    USE SIGNAL ;
    PORT
      LAYER M5 ;
        RECT  14.688 0 14.712 0.084 ;
    END
  END rec[192]
  PIN rec[193]
    DIRECTION OUTPUT ;
    USE SIGNAL ;
    PORT
      LAYER M5 ;
        RECT  14.832 0 14.856 0.084 ;
    END
  END rec[193]
  PIN rec[194]
    DIRECTION OUTPUT ;
    USE SIGNAL ;
    PORT
      LAYER M5 ;
        RECT  14.976 0 15 0.084 ;
    END
  END rec[194]
  PIN rec[195]
    DIRECTION OUTPUT ;
    USE SIGNAL ;
    PORT
      LAYER M5 ;
        RECT  15.12 0 15.144 0.084 ;
    END
  END rec[195]
  PIN rec[196]
    DIRECTION OUTPUT ;
    USE SIGNAL ;
    PORT
      LAYER M5 ;
        RECT  15.264 0 15.288 0.084 ;
    END
  END rec[196]
  PIN rec[197]
    DIRECTION OUTPUT ;
    USE SIGNAL ;
    PORT
      LAYER M5 ;
        RECT  15.408 0 15.432 0.084 ;
    END
  END rec[197]
  PIN rec[198]
    DIRECTION OUTPUT ;
    USE SIGNAL ;
    PORT
      LAYER M5 ;
        RECT  15.552 0 15.576 0.084 ;
    END
  END rec[198]
  PIN rec[199]
    DIRECTION OUTPUT ;
    USE SIGNAL ;
    PORT
      LAYER M5 ;
        RECT  15.696 0 15.72 0.084 ;
    END
  END rec[199]
  PIN rec[19]
    DIRECTION OUTPUT ;
    USE SIGNAL ;
    PORT
      LAYER M5 ;
        RECT  41.616 0 41.64 0.084 ;
    END
  END rec[19]
  PIN rec[1]
    DIRECTION OUTPUT ;
    USE SIGNAL ;
    PORT
      LAYER M5 ;
        RECT  39.024 0 39.048 0.084 ;
    END
  END rec[1]
  PIN rec[200]
    DIRECTION OUTPUT ;
    USE SIGNAL ;
    PORT
      LAYER M5 ;
        RECT  15.84 0 15.864 0.084 ;
    END
  END rec[200]
  PIN rec[201]
    DIRECTION OUTPUT ;
    USE SIGNAL ;
    PORT
      LAYER M5 ;
        RECT  15.984 0 16.008 0.084 ;
    END
  END rec[201]
  PIN rec[202]
    DIRECTION OUTPUT ;
    USE SIGNAL ;
    PORT
      LAYER M5 ;
        RECT  16.128 0 16.152 0.084 ;
    END
  END rec[202]
  PIN rec[203]
    DIRECTION OUTPUT ;
    USE SIGNAL ;
    PORT
      LAYER M5 ;
        RECT  16.272 0 16.296 0.084 ;
    END
  END rec[203]
  PIN rec[204]
    DIRECTION OUTPUT ;
    USE SIGNAL ;
    PORT
      LAYER M5 ;
        RECT  16.416 0 16.44 0.084 ;
    END
  END rec[204]
  PIN rec[205]
    DIRECTION OUTPUT ;
    USE SIGNAL ;
    PORT
      LAYER M5 ;
        RECT  16.56 0 16.584 0.084 ;
    END
  END rec[205]
  PIN rec[206]
    DIRECTION OUTPUT ;
    USE SIGNAL ;
    PORT
      LAYER M5 ;
        RECT  16.704 0 16.728 0.084 ;
    END
  END rec[206]
  PIN rec[207]
    DIRECTION OUTPUT ;
    USE SIGNAL ;
    PORT
      LAYER M5 ;
        RECT  16.848 0 16.872 0.084 ;
    END
  END rec[207]
  PIN rec[208]
    DIRECTION OUTPUT ;
    USE SIGNAL ;
    PORT
      LAYER M5 ;
        RECT  16.992 0 17.016 0.084 ;
    END
  END rec[208]
  PIN rec[209]
    DIRECTION OUTPUT ;
    USE SIGNAL ;
    PORT
      LAYER M5 ;
        RECT  17.136 0 17.16 0.084 ;
    END
  END rec[209]
  PIN rec[20]
    DIRECTION OUTPUT ;
    USE SIGNAL ;
    PORT
      LAYER M5 ;
        RECT  41.76 0 41.784 0.084 ;
    END
  END rec[20]
  PIN rec[210]
    DIRECTION OUTPUT ;
    USE SIGNAL ;
    PORT
      LAYER M5 ;
        RECT  17.28 0 17.304 0.084 ;
    END
  END rec[210]
  PIN rec[211]
    DIRECTION OUTPUT ;
    USE SIGNAL ;
    PORT
      LAYER M5 ;
        RECT  17.424 0 17.448 0.084 ;
    END
  END rec[211]
  PIN rec[212]
    DIRECTION OUTPUT ;
    USE SIGNAL ;
    PORT
      LAYER M5 ;
        RECT  17.568 0 17.592 0.084 ;
    END
  END rec[212]
  PIN rec[213]
    DIRECTION OUTPUT ;
    USE SIGNAL ;
    PORT
      LAYER M5 ;
        RECT  17.712 0 17.736 0.084 ;
    END
  END rec[213]
  PIN rec[214]
    DIRECTION OUTPUT ;
    USE SIGNAL ;
    PORT
      LAYER M5 ;
        RECT  17.856 0 17.88 0.084 ;
    END
  END rec[214]
  PIN rec[215]
    DIRECTION OUTPUT ;
    USE SIGNAL ;
    PORT
      LAYER M5 ;
        RECT  18 0 18.024 0.084 ;
    END
  END rec[215]
  PIN rec[216]
    DIRECTION OUTPUT ;
    USE SIGNAL ;
    PORT
      LAYER M5 ;
        RECT  18.144 0 18.168 0.084 ;
    END
  END rec[216]
  PIN rec[217]
    DIRECTION OUTPUT ;
    USE SIGNAL ;
    PORT
      LAYER M5 ;
        RECT  18.288 0 18.312 0.084 ;
    END
  END rec[217]
  PIN rec[218]
    DIRECTION OUTPUT ;
    USE SIGNAL ;
    PORT
      LAYER M5 ;
        RECT  18.432 0 18.456 0.084 ;
    END
  END rec[218]
  PIN rec[219]
    DIRECTION OUTPUT ;
    USE SIGNAL ;
    PORT
      LAYER M5 ;
        RECT  18.576 0 18.6 0.084 ;
    END
  END rec[219]
  PIN rec[21]
    DIRECTION OUTPUT ;
    USE SIGNAL ;
    PORT
      LAYER M5 ;
        RECT  41.904 0 41.928 0.084 ;
    END
  END rec[21]
  PIN rec[220]
    DIRECTION OUTPUT ;
    USE SIGNAL ;
    PORT
      LAYER M5 ;
        RECT  18.72 0 18.744 0.084 ;
    END
  END rec[220]
  PIN rec[22]
    DIRECTION OUTPUT ;
    USE SIGNAL ;
    PORT
      LAYER M5 ;
        RECT  42.048 0 42.072 0.084 ;
    END
  END rec[22]
  PIN rec[23]
    DIRECTION OUTPUT ;
    USE SIGNAL ;
    PORT
      LAYER M5 ;
        RECT  42.192 0 42.216 0.084 ;
    END
  END rec[23]
  PIN rec[24]
    DIRECTION OUTPUT ;
    USE SIGNAL ;
    PORT
      LAYER M5 ;
        RECT  42.336 0 42.36 0.084 ;
    END
  END rec[24]
  PIN rec[25]
    DIRECTION OUTPUT ;
    USE SIGNAL ;
    PORT
      LAYER M5 ;
        RECT  42.48 0 42.504 0.084 ;
    END
  END rec[25]
  PIN rec[26]
    DIRECTION OUTPUT ;
    USE SIGNAL ;
    PORT
      LAYER M5 ;
        RECT  42.624 0 42.648 0.084 ;
    END
  END rec[26]
  PIN rec[27]
    DIRECTION OUTPUT ;
    USE SIGNAL ;
    PORT
      LAYER M5 ;
        RECT  42.768 0 42.792 0.084 ;
    END
  END rec[27]
  PIN rec[28]
    DIRECTION OUTPUT ;
    USE SIGNAL ;
    PORT
      LAYER M5 ;
        RECT  42.912 0 42.936 0.084 ;
    END
  END rec[28]
  PIN rec[29]
    DIRECTION OUTPUT ;
    USE SIGNAL ;
    PORT
      LAYER M5 ;
        RECT  43.056 0 43.08 0.084 ;
    END
  END rec[29]
  PIN rec[2]
    DIRECTION OUTPUT ;
    USE SIGNAL ;
    PORT
      LAYER M5 ;
        RECT  39.168 0 39.192 0.084 ;
    END
  END rec[2]
  PIN rec[30]
    DIRECTION OUTPUT ;
    USE SIGNAL ;
    PORT
      LAYER M5 ;
        RECT  43.2 0 43.224 0.084 ;
    END
  END rec[30]
  PIN rec[31]
    DIRECTION OUTPUT ;
    USE SIGNAL ;
    PORT
      LAYER M5 ;
        RECT  29.52 0 29.544 0.084 ;
    END
  END rec[31]
  PIN rec[32]
    DIRECTION OUTPUT ;
    USE SIGNAL ;
    PORT
      LAYER M5 ;
        RECT  29.664 0 29.688 0.084 ;
    END
  END rec[32]
  PIN rec[33]
    DIRECTION OUTPUT ;
    USE SIGNAL ;
    PORT
      LAYER M5 ;
        RECT  29.808 0 29.832 0.084 ;
    END
  END rec[33]
  PIN rec[34]
    DIRECTION OUTPUT ;
    USE SIGNAL ;
    PORT
      LAYER M5 ;
        RECT  29.952 0 29.976 0.084 ;
    END
  END rec[34]
  PIN rec[35]
    DIRECTION OUTPUT ;
    USE SIGNAL ;
    PORT
      LAYER M5 ;
        RECT  30.096 0 30.12 0.084 ;
    END
  END rec[35]
  PIN rec[36]
    DIRECTION OUTPUT ;
    USE SIGNAL ;
    PORT
      LAYER M5 ;
        RECT  30.24 0 30.264 0.084 ;
    END
  END rec[36]
  PIN rec[37]
    DIRECTION OUTPUT ;
    USE SIGNAL ;
    PORT
      LAYER M5 ;
        RECT  30.384 0 30.408 0.084 ;
    END
  END rec[37]
  PIN rec[38]
    DIRECTION OUTPUT ;
    USE SIGNAL ;
    PORT
      LAYER M5 ;
        RECT  30.528 0 30.552 0.084 ;
    END
  END rec[38]
  PIN rec[39]
    DIRECTION OUTPUT ;
    USE SIGNAL ;
    PORT
      LAYER M5 ;
        RECT  30.672 0 30.696 0.084 ;
    END
  END rec[39]
  PIN rec[3]
    DIRECTION OUTPUT ;
    USE SIGNAL ;
    PORT
      LAYER M5 ;
        RECT  39.312 0 39.336 0.084 ;
    END
  END rec[3]
  PIN rec[40]
    DIRECTION OUTPUT ;
    USE SIGNAL ;
    PORT
      LAYER M5 ;
        RECT  30.816 0 30.84 0.084 ;
    END
  END rec[40]
  PIN rec[41]
    DIRECTION OUTPUT ;
    USE SIGNAL ;
    PORT
      LAYER M5 ;
        RECT  30.96 0 30.984 0.084 ;
    END
  END rec[41]
  PIN rec[42]
    DIRECTION OUTPUT ;
    USE SIGNAL ;
    PORT
      LAYER M5 ;
        RECT  31.104 0 31.128 0.084 ;
    END
  END rec[42]
  PIN rec[43]
    DIRECTION OUTPUT ;
    USE SIGNAL ;
    PORT
      LAYER M5 ;
        RECT  31.248 0 31.272 0.084 ;
    END
  END rec[43]
  PIN rec[44]
    DIRECTION OUTPUT ;
    USE SIGNAL ;
    PORT
      LAYER M5 ;
        RECT  31.392 0 31.416 0.084 ;
    END
  END rec[44]
  PIN rec[45]
    DIRECTION OUTPUT ;
    USE SIGNAL ;
    PORT
      LAYER M5 ;
        RECT  31.536 0 31.56 0.084 ;
    END
  END rec[45]
  PIN rec[46]
    DIRECTION OUTPUT ;
    USE SIGNAL ;
    PORT
      LAYER M5 ;
        RECT  31.68 0 31.704 0.084 ;
    END
  END rec[46]
  PIN rec[47]
    DIRECTION OUTPUT ;
    USE SIGNAL ;
    PORT
      LAYER M5 ;
        RECT  31.824 0 31.848 0.084 ;
    END
  END rec[47]
  PIN rec[48]
    DIRECTION OUTPUT ;
    USE SIGNAL ;
    PORT
      LAYER M5 ;
        RECT  31.968 0 31.992 0.084 ;
    END
  END rec[48]
  PIN rec[49]
    DIRECTION OUTPUT ;
    USE SIGNAL ;
    PORT
      LAYER M5 ;
        RECT  32.112 0 32.136 0.084 ;
    END
  END rec[49]
  PIN rec[4]
    DIRECTION OUTPUT ;
    USE SIGNAL ;
    PORT
      LAYER M5 ;
        RECT  39.456 0 39.48 0.084 ;
    END
  END rec[4]
  PIN rec[50]
    DIRECTION OUTPUT ;
    USE SIGNAL ;
    PORT
      LAYER M5 ;
        RECT  32.256 0 32.28 0.084 ;
    END
  END rec[50]
  PIN rec[51]
    DIRECTION OUTPUT ;
    USE SIGNAL ;
    PORT
      LAYER M5 ;
        RECT  32.4 0 32.424 0.084 ;
    END
  END rec[51]
  PIN rec[52]
    DIRECTION OUTPUT ;
    USE SIGNAL ;
    PORT
      LAYER M5 ;
        RECT  32.544 0 32.568 0.084 ;
    END
  END rec[52]
  PIN rec[53]
    DIRECTION OUTPUT ;
    USE SIGNAL ;
    PORT
      LAYER M5 ;
        RECT  32.688 0 32.712 0.084 ;
    END
  END rec[53]
  PIN rec[54]
    DIRECTION OUTPUT ;
    USE SIGNAL ;
    PORT
      LAYER M5 ;
        RECT  32.832 0 32.856 0.084 ;
    END
  END rec[54]
  PIN rec[55]
    DIRECTION OUTPUT ;
    USE SIGNAL ;
    PORT
      LAYER M5 ;
        RECT  32.976 0 33 0.084 ;
    END
  END rec[55]
  PIN rec[56]
    DIRECTION OUTPUT ;
    USE SIGNAL ;
    PORT
      LAYER M5 ;
        RECT  33.12 0 33.144 0.084 ;
    END
  END rec[56]
  PIN rec[57]
    DIRECTION OUTPUT ;
    USE SIGNAL ;
    PORT
      LAYER M5 ;
        RECT  33.264 0 33.288 0.084 ;
    END
  END rec[57]
  PIN rec[58]
    DIRECTION OUTPUT ;
    USE SIGNAL ;
    PORT
      LAYER M5 ;
        RECT  33.408 0 33.432 0.084 ;
    END
  END rec[58]
  PIN rec[59]
    DIRECTION OUTPUT ;
    USE SIGNAL ;
    PORT
      LAYER M5 ;
        RECT  33.552 0 33.576 0.084 ;
    END
  END rec[59]
  PIN rec[5]
    DIRECTION OUTPUT ;
    USE SIGNAL ;
    PORT
      LAYER M5 ;
        RECT  39.6 0 39.624 0.084 ;
    END
  END rec[5]
  PIN rec[60]
    DIRECTION OUTPUT ;
    USE SIGNAL ;
    PORT
      LAYER M5 ;
        RECT  33.696 0 33.72 0.084 ;
    END
  END rec[60]
  PIN rec[61]
    DIRECTION OUTPUT ;
    USE SIGNAL ;
    PORT
      LAYER M5 ;
        RECT  33.84 0 33.864 0.084 ;
    END
  END rec[61]
  PIN rec[62]
    DIRECTION OUTPUT ;
    USE SIGNAL ;
    PORT
      LAYER M5 ;
        RECT  33.984 0 34.008 0.084 ;
    END
  END rec[62]
  PIN rec[63]
    DIRECTION OUTPUT ;
    USE SIGNAL ;
    PORT
      LAYER M5 ;
        RECT  43.344 0 43.368 0.084 ;
    END
  END rec[63]
  PIN rec[64]
    DIRECTION OUTPUT ;
    USE SIGNAL ;
    PORT
      LAYER M5 ;
        RECT  43.488 0 43.512 0.084 ;
    END
  END rec[64]
  PIN rec[65]
    DIRECTION OUTPUT ;
    USE SIGNAL ;
    PORT
      LAYER M5 ;
        RECT  43.632 0 43.656 0.084 ;
    END
  END rec[65]
  PIN rec[66]
    DIRECTION OUTPUT ;
    USE SIGNAL ;
    PORT
      LAYER M5 ;
        RECT  43.776 0 43.8 0.084 ;
    END
  END rec[66]
  PIN rec[67]
    DIRECTION OUTPUT ;
    USE SIGNAL ;
    PORT
      LAYER M5 ;
        RECT  43.92 0 43.944 0.084 ;
    END
  END rec[67]
  PIN rec[68]
    DIRECTION OUTPUT ;
    USE SIGNAL ;
    PORT
      LAYER M5 ;
        RECT  44.064 0 44.088 0.084 ;
    END
  END rec[68]
  PIN rec[69]
    DIRECTION OUTPUT ;
    USE SIGNAL ;
    PORT
      LAYER M5 ;
        RECT  44.208 0 44.232 0.084 ;
    END
  END rec[69]
  PIN rec[6]
    DIRECTION OUTPUT ;
    USE SIGNAL ;
    PORT
      LAYER M5 ;
        RECT  39.744 0 39.768 0.084 ;
    END
  END rec[6]
  PIN rec[70]
    DIRECTION OUTPUT ;
    USE SIGNAL ;
    PORT
      LAYER M5 ;
        RECT  44.352 0 44.376 0.084 ;
    END
  END rec[70]
  PIN rec[71]
    DIRECTION OUTPUT ;
    USE SIGNAL ;
    PORT
      LAYER M5 ;
        RECT  44.496 0 44.52 0.084 ;
    END
  END rec[71]
  PIN rec[72]
    DIRECTION OUTPUT ;
    USE SIGNAL ;
    PORT
      LAYER M5 ;
        RECT  44.64 0 44.664 0.084 ;
    END
  END rec[72]
  PIN rec[73]
    DIRECTION OUTPUT ;
    USE SIGNAL ;
    PORT
      LAYER M5 ;
        RECT  44.784 0 44.808 0.084 ;
    END
  END rec[73]
  PIN rec[74]
    DIRECTION OUTPUT ;
    USE SIGNAL ;
    PORT
      LAYER M5 ;
        RECT  44.928 0 44.952 0.084 ;
    END
  END rec[74]
  PIN rec[75]
    DIRECTION OUTPUT ;
    USE SIGNAL ;
    PORT
      LAYER M5 ;
        RECT  45.072 0 45.096 0.084 ;
    END
  END rec[75]
  PIN rec[76]
    DIRECTION OUTPUT ;
    USE SIGNAL ;
    PORT
      LAYER M5 ;
        RECT  45.216 0 45.24 0.084 ;
    END
  END rec[76]
  PIN rec[77]
    DIRECTION OUTPUT ;
    USE SIGNAL ;
    PORT
      LAYER M5 ;
        RECT  45.36 0 45.384 0.084 ;
    END
  END rec[77]
  PIN rec[78]
    DIRECTION OUTPUT ;
    USE SIGNAL ;
    PORT
      LAYER M5 ;
        RECT  45.504 0 45.528 0.084 ;
    END
  END rec[78]
  PIN rec[79]
    DIRECTION OUTPUT ;
    USE SIGNAL ;
    PORT
      LAYER M5 ;
        RECT  45.648 0 45.672 0.084 ;
    END
  END rec[79]
  PIN rec[7]
    DIRECTION OUTPUT ;
    USE SIGNAL ;
    PORT
      LAYER M5 ;
        RECT  39.888 0 39.912 0.084 ;
    END
  END rec[7]
  PIN rec[80]
    DIRECTION OUTPUT ;
    USE SIGNAL ;
    PORT
      LAYER M5 ;
        RECT  45.792 0 45.816 0.084 ;
    END
  END rec[80]
  PIN rec[81]
    DIRECTION OUTPUT ;
    USE SIGNAL ;
    PORT
      LAYER M5 ;
        RECT  45.936 0 45.96 0.084 ;
    END
  END rec[81]
  PIN rec[82]
    DIRECTION OUTPUT ;
    USE SIGNAL ;
    PORT
      LAYER M5 ;
        RECT  46.08 0 46.104 0.084 ;
    END
  END rec[82]
  PIN rec[83]
    DIRECTION OUTPUT ;
    USE SIGNAL ;
    PORT
      LAYER M5 ;
        RECT  46.224 0 46.248 0.084 ;
    END
  END rec[83]
  PIN rec[84]
    DIRECTION OUTPUT ;
    USE SIGNAL ;
    PORT
      LAYER M5 ;
        RECT  46.368 0 46.392 0.084 ;
    END
  END rec[84]
  PIN rec[85]
    DIRECTION OUTPUT ;
    USE SIGNAL ;
    PORT
      LAYER M5 ;
        RECT  46.512 0 46.536 0.084 ;
    END
  END rec[85]
  PIN rec[86]
    DIRECTION OUTPUT ;
    USE SIGNAL ;
    PORT
      LAYER M5 ;
        RECT  46.656 0 46.68 0.084 ;
    END
  END rec[86]
  PIN rec[87]
    DIRECTION OUTPUT ;
    USE SIGNAL ;
    PORT
      LAYER M5 ;
        RECT  46.8 0 46.824 0.084 ;
    END
  END rec[87]
  PIN rec[88]
    DIRECTION OUTPUT ;
    USE SIGNAL ;
    PORT
      LAYER M5 ;
        RECT  46.944 0 46.968 0.084 ;
    END
  END rec[88]
  PIN rec[89]
    DIRECTION OUTPUT ;
    USE SIGNAL ;
    PORT
      LAYER M5 ;
        RECT  47.088 0 47.112 0.084 ;
    END
  END rec[89]
  PIN rec[8]
    DIRECTION OUTPUT ;
    USE SIGNAL ;
    PORT
      LAYER M5 ;
        RECT  40.032 0 40.056 0.084 ;
    END
  END rec[8]
  PIN rec[90]
    DIRECTION OUTPUT ;
    USE SIGNAL ;
    PORT
      LAYER M5 ;
        RECT  47.232 0 47.256 0.084 ;
    END
  END rec[90]
  PIN rec[91]
    DIRECTION OUTPUT ;
    USE SIGNAL ;
    PORT
      LAYER M5 ;
        RECT  47.376 0 47.4 0.084 ;
    END
  END rec[91]
  PIN rec[92]
    DIRECTION OUTPUT ;
    USE SIGNAL ;
    PORT
      LAYER M5 ;
        RECT  47.52 0 47.544 0.084 ;
    END
  END rec[92]
  PIN rec[93]
    DIRECTION OUTPUT ;
    USE SIGNAL ;
    PORT
      LAYER M5 ;
        RECT  47.664 0 47.688 0.084 ;
    END
  END rec[93]
  PIN rec[94]
    DIRECTION OUTPUT ;
    USE SIGNAL ;
    PORT
      LAYER M5 ;
        RECT  47.808 0 47.832 0.084 ;
    END
  END rec[94]
  PIN rec[95]
    DIRECTION OUTPUT ;
    USE SIGNAL ;
    PORT
      LAYER M5 ;
        RECT  34.128 0 34.152 0.084 ;
    END
  END rec[95]
  PIN rec[96]
    DIRECTION OUTPUT ;
    USE SIGNAL ;
    PORT
      LAYER M5 ;
        RECT  34.272 0 34.296 0.084 ;
    END
  END rec[96]
  PIN rec[97]
    DIRECTION OUTPUT ;
    USE SIGNAL ;
    PORT
      LAYER M5 ;
        RECT  34.416 0 34.44 0.084 ;
    END
  END rec[97]
  PIN rec[98]
    DIRECTION OUTPUT ;
    USE SIGNAL ;
    PORT
      LAYER M5 ;
        RECT  34.56 0 34.584 0.084 ;
    END
  END rec[98]
  PIN rec[99]
    DIRECTION OUTPUT ;
    USE SIGNAL ;
    PORT
      LAYER M5 ;
        RECT  34.704 0 34.728 0.084 ;
    END
  END rec[99]
  PIN rec[9]
    DIRECTION OUTPUT ;
    USE SIGNAL ;
    PORT
      LAYER M5 ;
        RECT  40.176 0 40.2 0.084 ;
    END
  END rec[9]
  PIN rst_n
    DIRECTION INPUT ;
    USE SIGNAL ;
    PORT
      LAYER M4 ;
        RECT  51.756 18.576 51.84 18.6 ;
    END
  END rst_n
  PIN start_v
    DIRECTION OUTPUT ;
    USE SIGNAL ;
    PORT
      LAYER M4 ;
        RECT  0 3.744 0.084 3.768 ;
    END
  END start_v
  PIN tgt[0]
    DIRECTION INPUT ;
    USE SIGNAL ;
    PORT
      LAYER M4 ;
        RECT  51.756 18.72 51.84 18.744 ;
    END
  END tgt[0]
  PIN tgt[1]
    DIRECTION INPUT ;
    USE SIGNAL ;
    PORT
      LAYER M4 ;
        RECT  51.756 18.864 51.84 18.888 ;
    END
  END tgt[1]
  PIN tgt[2]
    DIRECTION INPUT ;
    USE SIGNAL ;
    PORT
      LAYER M4 ;
        RECT  51.756 19.008 51.84 19.032 ;
    END
  END tgt[2]
  PIN tgt[3]
    DIRECTION INPUT ;
    USE SIGNAL ;
    PORT
      LAYER M4 ;
        RECT  51.756 47.952 51.84 47.976 ;
    END
  END tgt[3]
  PIN tgt[4]
    DIRECTION INPUT ;
    USE SIGNAL ;
    PORT
      LAYER M4 ;
        RECT  51.756 48.096 51.84 48.12 ;
    END
  END tgt[4]
  PIN tgt[5]
    DIRECTION INPUT ;
    USE SIGNAL ;
    PORT
      LAYER M4 ;
        RECT  51.756 48.24 51.84 48.264 ;
    END
  END tgt[5]
  PIN tgt[6]
    DIRECTION INPUT ;
    USE SIGNAL ;
    PORT
      LAYER M4 ;
        RECT  51.756 48.384 51.84 48.408 ;
    END
  END tgt[6]
  PIN tgt[7]
    DIRECTION INPUT ;
    USE SIGNAL ;
    PORT
      LAYER M4 ;
        RECT  51.756 48.528 51.84 48.552 ;
    END
  END tgt[7]
  PIN VDD
    DIRECTION INOUT ;
    USE POWER ;
    PORT
      LAYER M5 ;
        RECT  45.792 2.151 45.912 49.689 ;
        RECT  40.392 2.151 40.512 49.689 ;
        RECT  34.992 2.151 35.112 49.689 ;
        RECT  29.592 2.151 29.712 49.689 ;
        RECT  24.192 2.151 24.312 49.689 ;
        RECT  18.792 2.151 18.912 49.689 ;
        RECT  13.392 2.151 13.512 49.689 ;
        RECT  7.992 2.151 8.112 49.689 ;
        RECT  2.592 2.151 2.712 49.689 ;
    END
  END VDD
  PIN VSS
    DIRECTION INOUT ;
    USE GROUND ;
    PORT
      LAYER M5 ;
        RECT  45.6 2.137 45.72 49.703 ;
        RECT  40.2 2.137 40.32 49.703 ;
        RECT  34.8 2.137 34.92 49.703 ;
        RECT  29.4 2.137 29.52 49.703 ;
        RECT  24 2.137 24.12 49.703 ;
        RECT  18.6 2.137 18.72 49.703 ;
        RECT  13.2 2.137 13.32 49.703 ;
        RECT  7.8 2.137 7.92 49.703 ;
        RECT  2.4 2.137 2.52 49.703 ;
    END
  END VSS
  # OT_OBS_CLOSED layer=M5 d_um=1.536 added=67
  OBS
    LAYER RVTN ;
     RECT  2.16 2.16 49.68 2.295 ;
     RECT  2.16 2.565 49.68 2.835 ;
     RECT  2.16 3.105 49.68 3.375 ;
     RECT  2.16 3.645 49.68 3.915 ;
     RECT  2.16 4.185 49.68 4.455 ;
     RECT  2.16 4.725 49.68 4.995 ;
     RECT  2.16 5.265 49.68 5.535 ;
     RECT  2.16 5.805 49.68 6.075 ;
     RECT  2.16 6.345 49.68 6.615 ;
     RECT  2.16 6.885 49.68 7.155 ;
     RECT  2.16 7.425 49.68 7.695 ;
     RECT  2.16 7.965 49.68 8.235 ;
     RECT  2.16 8.505 49.68 8.775 ;
     RECT  2.16 9.045 49.68 9.315 ;
     RECT  2.16 9.585 49.68 9.855 ;
     RECT  2.16 10.125 49.68 10.395 ;
     RECT  2.16 10.665 49.68 10.935 ;
     RECT  2.16 11.205 49.68 11.475 ;
     RECT  2.16 11.745 49.68 12.015 ;
     RECT  2.16 12.285 49.68 12.555 ;
     RECT  2.16 12.825 49.68 13.095 ;
     RECT  2.16 13.365 49.68 13.635 ;
     RECT  2.16 13.905 49.68 14.175 ;
     RECT  2.16 14.445 49.68 14.715 ;
     RECT  2.16 14.985 49.68 15.255 ;
     RECT  2.16 15.525 49.68 15.795 ;
     RECT  2.16 16.065 49.68 16.335 ;
     RECT  2.16 16.605 49.68 16.875 ;
     RECT  2.16 17.145 49.68 17.415 ;
     RECT  2.16 17.685 49.68 17.955 ;
     RECT  2.16 18.225 49.68 18.495 ;
     RECT  2.16 18.765 49.68 19.035 ;
     RECT  2.16 19.305 49.68 19.575 ;
     RECT  2.16 19.845 49.68 20.115 ;
     RECT  2.16 20.385 49.68 20.655 ;
     RECT  2.16 20.925 49.68 21.195 ;
     RECT  2.16 21.465 49.68 21.735 ;
     RECT  2.16 22.005 49.68 22.275 ;
     RECT  2.16 22.545 49.68 22.815 ;
     RECT  2.16 23.085 49.68 23.355 ;
     RECT  2.16 23.625 49.68 23.895 ;
     RECT  2.16 24.165 49.68 24.435 ;
     RECT  2.16 24.705 49.68 24.975 ;
     RECT  2.16 25.245 49.68 25.515 ;
     RECT  2.16 25.785 49.68 26.055 ;
     RECT  2.16 26.325 49.68 26.595 ;
     RECT  2.16 26.865 49.68 27.135 ;
     RECT  2.16 27.405 49.68 27.675 ;
     RECT  2.16 27.945 49.68 28.215 ;
     RECT  2.16 28.485 49.68 28.755 ;
     RECT  2.16 29.025 49.68 29.295 ;
     RECT  2.16 29.565 49.68 29.835 ;
     RECT  2.16 30.105 49.68 30.375 ;
     RECT  2.16 30.645 49.68 30.915 ;
     RECT  2.16 31.185 49.68 31.455 ;
     RECT  2.16 31.725 49.68 31.995 ;
     RECT  2.16 32.265 49.68 32.535 ;
     RECT  2.16 32.805 49.68 33.075 ;
     RECT  2.16 33.345 49.68 33.615 ;
     RECT  2.16 33.885 49.68 34.155 ;
     RECT  2.16 34.425 49.68 34.695 ;
     RECT  2.16 34.965 49.68 35.235 ;
     RECT  2.16 35.505 49.68 35.775 ;
     RECT  2.16 36.045 49.68 36.315 ;
     RECT  2.16 36.585 49.68 36.855 ;
     RECT  2.16 37.125 49.68 37.395 ;
     RECT  2.16 37.665 49.68 37.935 ;
     RECT  2.16 38.205 49.68 38.475 ;
     RECT  2.16 38.745 49.68 39.015 ;
     RECT  2.16 39.285 49.68 39.555 ;
     RECT  2.16 39.825 49.68 40.095 ;
     RECT  2.16 40.365 49.68 40.635 ;
     RECT  2.16 40.905 49.68 41.175 ;
     RECT  2.16 41.445 49.68 41.715 ;
     RECT  2.16 41.985 49.68 42.255 ;
     RECT  2.16 42.525 49.68 42.795 ;
     RECT  2.16 43.065 49.68 43.335 ;
     RECT  2.16 43.605 49.68 43.875 ;
     RECT  2.16 44.145 49.68 44.415 ;
     RECT  2.16 44.685 49.68 44.955 ;
     RECT  2.16 45.225 49.68 45.495 ;
     RECT  2.16 45.765 49.68 46.035 ;
     RECT  2.16 46.305 49.68 46.575 ;
     RECT  2.16 46.845 49.68 47.115 ;
     RECT  2.16 47.385 49.68 47.655 ;
     RECT  2.16 47.925 49.68 48.195 ;
     RECT  2.16 48.465 49.68 48.735 ;
     RECT  2.16 49.005 49.68 49.275 ;
     RECT  2.16 49.545 49.68 49.68 ;
    LAYER RVTP ;
     RECT  2.16 2.295 49.68 2.565 ;
     RECT  2.16 2.835 49.68 3.105 ;
     RECT  2.16 3.375 49.68 3.645 ;
     RECT  2.16 3.915 49.68 4.185 ;
     RECT  2.16 4.455 49.68 4.725 ;
     RECT  2.16 4.995 49.68 5.265 ;
     RECT  2.16 5.535 49.68 5.805 ;
     RECT  2.16 6.075 49.68 6.345 ;
     RECT  2.16 6.615 49.68 6.885 ;
     RECT  2.16 7.155 49.68 7.425 ;
     RECT  2.16 7.695 49.68 7.965 ;
     RECT  2.16 8.235 49.68 8.505 ;
     RECT  2.16 8.775 49.68 9.045 ;
     RECT  2.16 9.315 49.68 9.585 ;
     RECT  2.16 9.855 49.68 10.125 ;
     RECT  2.16 10.395 49.68 10.665 ;
     RECT  2.16 10.935 49.68 11.205 ;
     RECT  2.16 11.475 49.68 11.745 ;
     RECT  2.16 12.015 49.68 12.285 ;
     RECT  2.16 12.555 49.68 12.825 ;
     RECT  2.16 13.095 49.68 13.365 ;
     RECT  2.16 13.635 49.68 13.905 ;
     RECT  2.16 14.175 49.68 14.445 ;
     RECT  2.16 14.715 49.68 14.985 ;
     RECT  2.16 15.255 49.68 15.525 ;
     RECT  2.16 15.795 49.68 16.065 ;
     RECT  2.16 16.335 49.68 16.605 ;
     RECT  2.16 16.875 49.68 17.145 ;
     RECT  2.16 17.415 49.68 17.685 ;
     RECT  2.16 17.955 49.68 18.225 ;
     RECT  2.16 18.495 49.68 18.765 ;
     RECT  2.16 19.035 49.68 19.305 ;
     RECT  2.16 19.575 49.68 19.845 ;
     RECT  2.16 20.115 49.68 20.385 ;
     RECT  2.16 20.655 49.68 20.925 ;
     RECT  2.16 21.195 49.68 21.465 ;
     RECT  2.16 21.735 49.68 22.005 ;
     RECT  2.16 22.275 49.68 22.545 ;
     RECT  2.16 22.815 49.68 23.085 ;
     RECT  2.16 23.355 49.68 23.625 ;
     RECT  2.16 23.895 49.68 24.165 ;
     RECT  2.16 24.435 49.68 24.705 ;
     RECT  2.16 24.975 49.68 25.245 ;
     RECT  2.16 25.515 49.68 25.785 ;
     RECT  2.16 26.055 49.68 26.325 ;
     RECT  2.16 26.595 49.68 26.865 ;
     RECT  2.16 27.135 49.68 27.405 ;
     RECT  2.16 27.675 49.68 27.945 ;
     RECT  2.16 28.215 49.68 28.485 ;
     RECT  2.16 28.755 49.68 29.025 ;
     RECT  2.16 29.295 49.68 29.565 ;
     RECT  2.16 29.835 49.68 30.105 ;
     RECT  2.16 30.375 49.68 30.645 ;
     RECT  2.16 30.915 49.68 31.185 ;
     RECT  2.16 31.455 49.68 31.725 ;
     RECT  2.16 31.995 49.68 32.265 ;
     RECT  2.16 32.535 49.68 32.805 ;
     RECT  2.16 33.075 49.68 33.345 ;
     RECT  2.16 33.615 49.68 33.885 ;
     RECT  2.16 34.155 49.68 34.425 ;
     RECT  2.16 34.695 49.68 34.965 ;
     RECT  2.16 35.235 49.68 35.505 ;
     RECT  2.16 35.775 49.68 36.045 ;
     RECT  2.16 36.315 49.68 36.585 ;
     RECT  2.16 36.855 49.68 37.125 ;
     RECT  2.16 37.395 49.68 37.665 ;
     RECT  2.16 37.935 49.68 38.205 ;
     RECT  2.16 38.475 49.68 38.745 ;
     RECT  2.16 39.015 49.68 39.285 ;
     RECT  2.16 39.555 49.68 39.825 ;
     RECT  2.16 40.095 49.68 40.365 ;
     RECT  2.16 40.635 49.68 40.905 ;
     RECT  2.16 41.175 49.68 41.445 ;
     RECT  2.16 41.715 49.68 41.985 ;
     RECT  2.16 42.255 49.68 42.525 ;
     RECT  2.16 42.795 49.68 43.065 ;
     RECT  2.16 43.335 49.68 43.605 ;
     RECT  2.16 43.875 49.68 44.145 ;
     RECT  2.16 44.415 49.68 44.685 ;
     RECT  2.16 44.955 49.68 45.225 ;
     RECT  2.16 45.495 49.68 45.765 ;
     RECT  2.16 46.035 49.68 46.305 ;
     RECT  2.16 46.575 49.68 46.845 ;
     RECT  2.16 47.115 49.68 47.385 ;
     RECT  2.16 47.655 49.68 47.925 ;
     RECT  2.16 48.195 49.68 48.465 ;
     RECT  2.16 48.735 49.68 49.005 ;
     RECT  2.16 49.275 49.68 49.545 ;
    LAYER M1 ;
     RECT  2.16 2.151 49.68 49.689 ;
    LAYER M2 ;
     RECT  0.103 8.946 0.535 9.504 ;
     RECT  0.499 12.492 0.535 12.51 ;
     RECT  0.499 16.686 0.535 16.704 ;
     RECT  0.103 2.034 1.723 2.052 ;
     RECT  1.723 2.034 1.759 2.484 ;
     RECT  1.759 1.998 2.16 2.484 ;
     RECT  0.535 6.246 2.16 6.264 ;
     RECT  0.535 8.586 2.16 9.504 ;
     RECT  0.535 12.024 2.16 12.744 ;
     RECT  0.535 13.608 2.16 14.13 ;
     RECT  0.535 16.308 2.16 17.208 ;
     RECT  0.535 19.35 2.16 19.368 ;
     RECT  2.155 20.898 2.16 20.916 ;
     RECT  0.535 27.144 2.16 27.162 ;
     RECT  0.535 32.346 2.16 32.364 ;
     RECT  0.535 33.966 2.16 33.984 ;
     RECT  0.535 40.878 2.16 40.896 ;
     RECT  2.16 1.998 2.399 49.689 ;
     RECT  2.399 2.034 3.263 49.689 ;
     RECT  4.099 50.706 4.235 50.724 ;
     RECT  3.263 2.106 8.447 49.689 ;
     RECT  25.303 50.706 26.087 50.724 ;
     RECT  30.019 50.706 30.119 50.724 ;
     RECT  39.775 50.706 39.911 50.724 ;
     RECT  8.447 2.151 49.68 49.689 ;
     RECT  49.68 5.508 50.171 28.44 ;
     RECT  49.68 29.538 50.171 46.908 ;
     RECT  50.171 29.88 50.207 45.828 ;
     RECT  50.171 46.89 50.207 46.908 ;
     RECT  50.171 5.706 50.711 28.44 ;
     RECT  50.207 34.632 50.711 45.288 ;
     RECT  49.68 47.7 50.711 48.69 ;
     RECT  50.711 8.442 50.747 28.44 ;
     RECT  50.207 29.916 50.747 33.804 ;
     RECT  50.711 34.632 50.747 45.018 ;
     RECT  50.747 8.442 50.783 11.466 ;
     RECT  50.747 17.586 50.783 17.712 ;
     RECT  50.783 8.442 50.819 11.43 ;
     RECT  50.711 5.706 51.719 7.686 ;
     RECT  50.819 8.442 51.719 10.89 ;
     RECT  50.747 14.382 51.719 15.588 ;
     RECT  50.747 23.058 51.719 24.804 ;
     RECT  50.747 34.632 51.719 35.19 ;
     RECT  50.747 44.19 51.719 45.018 ;
     RECT  51.719 5.706 51.755 7.452 ;
     RECT  51.719 8.514 51.755 10.89 ;
     RECT  50.747 12.294 51.755 13.392 ;
     RECT  51.719 14.382 51.755 15.516 ;
     RECT  50.747 16.578 51.755 16.596 ;
     RECT  50.783 17.694 51.755 17.712 ;
     RECT  50.747 18.504 51.755 22.104 ;
     RECT  51.719 23.058 51.755 23.076 ;
     RECT  51.719 23.832 51.755 24.804 ;
     RECT  50.747 25.722 51.755 28.44 ;
     RECT  50.747 30.726 51.755 33.444 ;
     RECT  51.719 34.632 51.755 35.154 ;
     RECT  50.747 36.63 51.755 42.012 ;
     RECT  50.747 43.272 51.755 43.29 ;
     RECT  51.719 44.19 51.755 44.946 ;
    LAYER M3 ;
     RECT  19.404 0.091 23.778 0.523 ;
     RECT  24.624 0.091 27.666 0.523 ;
     RECT  33.264 0.091 34.758 0.523 ;
     RECT  35.532 0.091 47.646 0.523 ;
     RECT  1.728 1.003 1.746 1.579 ;
     RECT  4.068 1.147 4.086 1.723 ;
     RECT  14.796 0.091 18.558 1.723 ;
     RECT  19.404 0.523 27.666 1.723 ;
     RECT  29.808 0.091 32.418 1.723 ;
     RECT  33.264 0.523 47.646 1.723 ;
     RECT  3.6 1.723 4.086 1.867 ;
     RECT  1.728 1.579 1.782 1.993 ;
     RECT  3.6 1.867 4.266 2.029 ;
     RECT  0.108 1.435 0.126 2.057 ;
     RECT  3.24 2.029 4.266 2.101 ;
     RECT  1.728 1.993 2.394 2.143 ;
     RECT  3.168 2.101 4.266 2.143 ;
     RECT  7.452 2.011 7.47 2.143 ;
     RECT  8.424 2.101 8.442 2.143 ;
     RECT  29.556 1.723 47.826 2.143 ;
     RECT  1.728 2.143 4.266 2.191 ;
     RECT  6.264 1.291 6.282 2.191 ;
     RECT  7.452 2.143 8.442 2.191 ;
     RECT  14.544 1.723 28.278 2.219 ;
     RECT  29.415 2.143 47.826 2.219 ;
     RECT  0.144 2.155 0.162 2.285 ;
     RECT  1.728 2.191 4.662 2.371 ;
     RECT  5.58 2.191 8.442 2.371 ;
     RECT  13.215 2.143 13.305 2.413 ;
     RECT  1.728 2.371 8.514 2.461 ;
     RECT  1.728 2.461 8.586 2.489 ;
     RECT  14.796 2.219 27.666 2.525 ;
     RECT  29.415 2.219 47.646 2.525 ;
     RECT  2.304 2.489 8.586 2.641 ;
     RECT  27.324 2.525 27.342 2.759 ;
     RECT  2.304 2.641 9.162 3.721 ;
     RECT  0.144 3.067 0.162 3.965 ;
     RECT  20.88 3.931 20.898 4.109 ;
     RECT  25.92 3.847 25.938 4.153 ;
     RECT  28.296 3.541 28.314 4.261 ;
     RECT  0.324 4.315 0.342 4.493 ;
     RECT  2.304 3.721 9.27 4.651 ;
     RECT  27.036 4.189 27.054 4.657 ;
     RECT  28.188 4.261 28.314 4.657 ;
     RECT  10.836 3.541 10.854 4.757 ;
     RECT  25.92 4.153 26.082 4.801 ;
     RECT  27.036 4.657 28.314 4.801 ;
     RECT  2.304 4.651 9.702 4.955 ;
     RECT  1.152 4.891 1.17 5.021 ;
     RECT  10.908 4.963 10.926 5.063 ;
     RECT  46.764 5.269 46.782 5.341 ;
     RECT  49.68 5.323 49.698 5.467 ;
     RECT  49.68 5.467 50.166 5.531 ;
     RECT  45.615 2.525 45.897 5.575 ;
     RECT  46.764 5.341 47.43 5.575 ;
     RECT  49.68 5.531 49.698 5.603 ;
     RECT  16.2 5.503 16.218 5.611 ;
     RECT  48.744 5.269 48.762 5.639 ;
     RECT  50.688 5.737 50.742 5.789 ;
     RECT  16.2 5.611 16.506 5.845 ;
     RECT  42.768 5.341 42.786 5.881 ;
     RECT  43.884 5.809 43.902 5.971 ;
     RECT  45.615 5.575 47.538 5.971 ;
     RECT  48.456 5.881 48.474 5.971 ;
     RECT  16.2 5.845 16.614 6.007 ;
     RECT  45.615 5.971 48.474 6.035 ;
     RECT  42.768 5.881 42.822 6.071 ;
     RECT  45.615 6.035 48.006 6.115 ;
     RECT  45.36 6.115 48.006 6.179 ;
     RECT  42.768 6.071 42.786 6.269 ;
     RECT  45.36 6.179 47.898 6.269 ;
     RECT  18.615 2.525 18.897 6.313 ;
     RECT  45.36 6.269 47.466 6.313 ;
     RECT  51.732 5.611 51.75 6.331 ;
     RECT  43.884 5.971 44.406 6.349 ;
     RECT  0.54 6.241 0.558 6.365 ;
     RECT  16.2 6.007 16.902 6.385 ;
     RECT  45.324 6.313 47.466 6.413 ;
     RECT  16.2 6.385 17.406 6.421 ;
     RECT  18.615 6.313 19.242 6.511 ;
     RECT  45.324 6.413 47.286 6.539 ;
     RECT  51.696 6.331 51.75 6.667 ;
     RECT  16.2 6.421 17.694 6.691 ;
     RECT  18.615 6.511 19.926 6.691 ;
     RECT  45.324 6.539 47.214 6.691 ;
     RECT  48.78 6.655 48.798 6.781 ;
     RECT  49.608 5.899 49.626 6.781 ;
     RECT  51.66 6.667 51.75 6.797 ;
     RECT  16.2 6.691 19.926 6.817 ;
     RECT  48.78 6.781 49.626 6.845 ;
     RECT  20.772 4.225 20.79 6.853 ;
     RECT  16.164 6.817 19.926 6.889 ;
     RECT  45.288 6.691 47.214 6.889 ;
     RECT  50.688 5.789 50.706 6.889 ;
     RECT  15.552 6.889 19.926 6.907 ;
     RECT  20.772 6.853 21.078 6.907 ;
     RECT  42.66 6.811 42.678 6.925 ;
     RECT  43.74 6.349 44.406 6.925 ;
     RECT  42.624 6.925 42.678 6.953 ;
     RECT  15.552 6.907 21.078 6.961 ;
     RECT  45.216 6.889 47.214 6.989 ;
     RECT  15.552 6.961 21.186 7.051 ;
     RECT  45.216 6.989 47.178 7.051 ;
     RECT  15.264 7.051 21.186 7.159 ;
     RECT  0.144 6.667 0.162 7.181 ;
     RECT  15.192 7.159 21.186 7.195 ;
     RECT  43.668 6.925 44.406 7.195 ;
     RECT  45.144 7.051 47.178 7.223 ;
     RECT  14.292 7.195 14.31 7.231 ;
     RECT  15.084 7.195 21.186 7.231 ;
     RECT  23.112 6.961 23.13 7.231 ;
     RECT  24.015 2.525 24.297 7.231 ;
     RECT  43.632 7.195 44.406 7.349 ;
     RECT  45.288 7.223 47.178 7.349 ;
     RECT  50.688 6.889 50.742 7.373 ;
     RECT  11.736 2.911 11.754 7.429 ;
     RECT  13.215 2.413 13.497 7.429 ;
     RECT  14.292 7.231 21.474 7.429 ;
     RECT  47.952 7.231 47.97 7.435 ;
     RECT  13.215 7.429 21.474 7.501 ;
     RECT  23.112 7.231 24.297 7.591 ;
     RECT  47.952 7.435 48.114 7.627 ;
     RECT  49.032 6.845 49.626 7.627 ;
     RECT  50.688 7.373 50.706 7.627 ;
     RECT  42.624 6.953 42.642 7.655 ;
     RECT  23.004 7.591 24.297 7.675 ;
     RECT  33.444 7.465 33.462 7.699 ;
     RECT  49.032 7.627 50.706 7.727 ;
     RECT  13.176 7.501 21.474 7.735 ;
     RECT  25.92 4.801 28.314 7.735 ;
     RECT  50.688 7.727 50.706 7.763 ;
     RECT  43.704 7.349 43.722 7.799 ;
     RECT  49.032 7.727 49.662 7.889 ;
     RECT  12.564 7.735 21.474 7.897 ;
     RECT  22.536 7.675 24.462 7.897 ;
     RECT  12.564 7.897 24.462 7.933 ;
     RECT  25.236 7.735 28.314 7.933 ;
     RECT  49.608 7.889 49.662 7.949 ;
     RECT  47.952 7.627 48.258 7.961 ;
     RECT  11.484 7.429 11.754 7.969 ;
     RECT  12.564 7.933 28.314 7.969 ;
     RECT  33.372 7.699 33.462 8.041 ;
     RECT  45.288 7.349 47.034 8.131 ;
     RECT  48.456 8.041 48.474 8.159 ;
     RECT  42.768 8.041 42.786 8.231 ;
     RECT  45.288 8.131 47.214 8.275 ;
     RECT  45.288 8.275 47.502 8.333 ;
     RECT  44.496 8.275 44.514 8.429 ;
     RECT  45.288 8.333 47.25 8.429 ;
     RECT  51.696 6.797 51.75 8.491 ;
     RECT  51.66 8.491 51.75 8.609 ;
     RECT  11.484 7.969 28.314 8.699 ;
     RECT  42.84 8.275 43.362 8.779 ;
     RECT  49.608 7.949 49.626 8.779 ;
     RECT  0.54 8.581 0.558 8.923 ;
     RECT  0.144 8.923 0.558 8.941 ;
     RECT  42.84 8.779 43.974 8.969 ;
     RECT  49.5 8.779 49.626 9.041 ;
     RECT  42.84 8.969 43.29 9.085 ;
     RECT  11.484 8.699 21.87 9.115 ;
     RECT  2.304 4.955 9.522 9.121 ;
     RECT  11.376 9.115 21.87 9.211 ;
     RECT  10.908 9.211 21.87 9.247 ;
     RECT  2.304 9.121 9.558 9.319 ;
     RECT  10.332 9.247 21.87 9.319 ;
     RECT  33.336 8.041 33.462 9.319 ;
     RECT  45.288 8.429 47.214 9.319 ;
     RECT  49.752 9.067 49.77 9.319 ;
     RECT  48.924 9.283 48.942 9.391 ;
     RECT  45.288 9.319 47.25 9.481 ;
     RECT  48.492 9.391 48.942 9.509 ;
     RECT  49.752 9.319 50.238 9.533 ;
     RECT  49.752 9.533 50.202 9.617 ;
     RECT  45.108 9.481 47.25 9.625 ;
     RECT  2.304 9.319 21.87 9.661 ;
     RECT  22.716 8.699 28.314 9.661 ;
     RECT  51.732 8.609 51.75 9.787 ;
     RECT  0.108 8.941 0.558 9.821 ;
     RECT  51.696 9.787 51.75 9.851 ;
     RECT  33.336 9.319 33.498 9.859 ;
     RECT  34.815 2.525 35.097 9.859 ;
     RECT  38.844 9.931 38.862 10.021 ;
     RECT  42.588 9.085 43.29 10.021 ;
     RECT  44.244 9.895 44.262 10.021 ;
     RECT  38.772 10.021 38.862 10.049 ;
     RECT  42.588 10.021 44.262 10.049 ;
     RECT  45.108 9.625 47.286 10.049 ;
     RECT  48.024 9.625 48.042 10.057 ;
     RECT  0.54 9.821 0.558 10.109 ;
     RECT  38.772 10.049 38.826 10.121 ;
     RECT  40.215 2.525 40.497 10.123 ;
     RECT  45.108 10.049 46.782 10.165 ;
     RECT  50.148 9.617 50.202 10.498 ;
     RECT  44.604 10.165 46.782 10.589 ;
     RECT  38.808 10.121 38.826 10.625 ;
     RECT  48.996 10.696 49.014 10.733 ;
     RECT  47.592 10.057 48.042 10.795 ;
     RECT  42.588 10.049 43.686 10.829 ;
     RECT  50.148 10.498 50.238 10.867 ;
     RECT  51.732 9.851 51.75 10.895 ;
     RECT  50.148 10.867 50.67 10.903 ;
     RECT  50.148 10.903 50.742 11.083 ;
     RECT  44.64 10.589 46.782 11.137 ;
     RECT  47.52 10.795 48.042 11.137 ;
     RECT  40.14 10.123 40.497 11.227 ;
     RECT  44.64 11.137 48.042 11.245 ;
     RECT  49.608 11.083 50.742 11.273 ;
     RECT  49.716 11.273 50.742 11.371 ;
     RECT  44.64 11.245 48.474 11.399 ;
     RECT  49.716 11.371 50.778 11.407 ;
     RECT  44.64 11.399 47.97 11.507 ;
     RECT  49.716 11.407 50.814 11.549 ;
     RECT  43.02 10.829 43.686 11.551 ;
     RECT  44.64 11.507 47.682 11.551 ;
     RECT  2.304 9.661 28.314 11.669 ;
     RECT  38.16 11.443 38.178 11.707 ;
     RECT  37.656 11.707 38.178 11.713 ;
     RECT  37.62 11.713 38.178 11.749 ;
     RECT  43.02 11.551 47.682 11.749 ;
     RECT  37.404 11.749 38.178 11.821 ;
     RECT  42.84 11.749 47.682 11.821 ;
     RECT  1.152 11.707 1.17 11.837 ;
     RECT  49.716 11.549 50.742 11.837 ;
     RECT  0.144 10.699 0.162 11.981 ;
     RECT  42.768 11.821 47.682 12.019 ;
     RECT  37.404 11.821 38.754 12.091 ;
     RECT  42.732 12.019 47.682 12.187 ;
     RECT  42.588 12.187 47.682 12.235 ;
     RECT  42.588 12.235 47.862 12.353 ;
     RECT  2.304 11.669 9.522 12.479 ;
     RECT  42.588 12.353 43.614 12.479 ;
     RECT  50.724 11.837 50.742 12.557 ;
     RECT  10.332 11.669 28.314 12.559 ;
     RECT  0.504 12.019 0.558 12.701 ;
     RECT  49.284 12.235 49.626 12.793 ;
     RECT  48.636 12.793 49.626 12.811 ;
     RECT  37.404 12.091 38.79 12.829 ;
     RECT  0.54 12.701 0.558 12.859 ;
     RECT  2.415 12.479 9.522 12.865 ;
     RECT  10.26 12.559 28.314 12.865 ;
     RECT  44.892 12.353 47.862 12.901 ;
     RECT  44.892 12.901 47.898 12.907 ;
     RECT  48.636 12.811 50.094 12.907 ;
     RECT  0.54 12.859 1.17 12.989 ;
     RECT  44.892 12.907 50.094 12.989 ;
     RECT  44.892 12.989 48.654 13.019 ;
     RECT  37.404 12.829 38.826 13.063 ;
     RECT  44.892 13.019 48.51 13.171 ;
     RECT  2.415 12.865 28.314 13.243 ;
     RECT  42.588 12.479 43.29 13.261 ;
     RECT  49.5 12.989 50.094 13.361 ;
     RECT  39.924 11.227 40.497 13.369 ;
     RECT  41.292 12.793 41.31 13.369 ;
     RECT  51.732 12.091 51.75 13.397 ;
     RECT  49.608 13.361 50.094 13.405 ;
     RECT  42.588 13.261 43.362 13.531 ;
     RECT  44.28 13.171 48.51 13.531 ;
     RECT  39.672 13.369 41.31 13.567 ;
     RECT  37.404 13.063 38.898 13.603 ;
     RECT  39.636 13.567 41.31 13.603 ;
     RECT  37.404 13.603 41.31 13.631 ;
     RECT  42.588 13.531 48.51 13.703 ;
     RECT  49.608 13.405 50.202 13.711 ;
     RECT  49.608 13.711 50.742 13.853 ;
     RECT  42.588 13.703 48.006 13.901 ;
     RECT  2.304 13.243 28.314 13.909 ;
     RECT  2.268 13.909 28.314 13.997 ;
     RECT  42.588 13.901 47.79 14.099 ;
     RECT  49.608 13.853 50.67 14.141 ;
     RECT  42.588 14.099 44.046 14.243 ;
     RECT  44.892 14.099 47.79 14.243 ;
     RECT  0.54 12.989 0.558 14.285 ;
     RECT  51.732 14.251 51.75 14.395 ;
     RECT  42.588 14.243 43.65 14.429 ;
     RECT  51.696 14.395 51.75 14.477 ;
     RECT  50.076 14.141 50.67 14.513 ;
     RECT  2.304 13.997 28.314 14.813 ;
     RECT  37.404 13.631 40.497 14.989 ;
     RECT  41.292 13.631 41.31 14.989 ;
     RECT  33.336 9.859 35.097 15.061 ;
     RECT  49.284 15.115 49.302 15.323 ;
     RECT  50.076 14.513 50.202 15.403 ;
     RECT  44.892 14.243 47.43 15.421 ;
     RECT  49.5 15.403 50.202 15.421 ;
     RECT  42.876 14.429 43.65 15.457 ;
     RECT  44.856 15.421 47.79 15.457 ;
     RECT  42.876 15.457 47.79 15.521 ;
     RECT  49.5 15.421 50.706 15.521 ;
     RECT  51.732 14.477 51.75 15.521 ;
     RECT  0.144 14.827 0.162 15.533 ;
     RECT  2.415 14.813 28.314 15.547 ;
     RECT  51.696 15.547 51.714 15.593 ;
     RECT  2.304 15.547 28.314 15.773 ;
     RECT  5.832 15.773 28.314 15.917 ;
     RECT  22.428 15.917 28.314 15.961 ;
     RECT  5.832 15.917 21.69 15.989 ;
     RECT  42.876 15.521 47.358 15.989 ;
     RECT  50.076 15.521 50.706 16.061 ;
     RECT  50.652 16.061 50.706 16.105 ;
     RECT  37.404 14.989 41.31 16.259 ;
     RECT  43.092 15.989 47.358 16.267 ;
     RECT  33.336 15.061 35.154 16.411 ;
     RECT  30.744 16.363 30.762 16.529 ;
     RECT  31.932 16.231 31.95 16.529 ;
     RECT  43.092 16.267 47.466 16.529 ;
     RECT  48.276 16.339 48.294 16.529 ;
     RECT  43.272 16.529 47.466 16.573 ;
     RECT  2.304 15.773 5.094 16.6 ;
     RECT  5.832 15.989 21.654 16.6 ;
     RECT  49.572 16.555 49.59 16.601 ;
     RECT  51.732 16.411 51.75 16.601 ;
     RECT  0.54 16.303 0.558 16.681 ;
     RECT  2.304 16.6 21.654 16.799 ;
     RECT  43.272 16.573 48.15 16.799 ;
     RECT  2.304 16.799 21.582 16.871 ;
     RECT  22.428 15.961 28.35 16.915 ;
     RECT  0.504 16.681 0.558 16.987 ;
     RECT  2.304 16.871 21.51 17.105 ;
     RECT  49.176 16.951 49.194 17.105 ;
     RECT  0.504 16.987 1.134 17.117 ;
     RECT  12.924 17.105 21.51 17.117 ;
     RECT  43.272 16.799 43.686 17.117 ;
     RECT  2.304 17.105 11.934 17.177 ;
     RECT  2.304 17.177 10.818 17.249 ;
     RECT  51.66 17.179 51.678 17.309 ;
     RECT  2.304 17.249 10.782 17.339 ;
     RECT  11.916 17.177 11.934 17.339 ;
     RECT  13.215 17.117 21.51 17.339 ;
     RECT  2.304 17.339 10.566 17.375 ;
     RECT  13.215 17.339 21.006 17.375 ;
     RECT  49.104 17.221 49.158 17.383 ;
     RECT  14.256 17.375 21.006 17.411 ;
     RECT  43.272 17.117 43.65 17.411 ;
     RECT  44.532 16.799 48.15 17.419 ;
     RECT  22.392 16.915 28.35 17.455 ;
     RECT  0.504 17.117 0.558 17.467 ;
     RECT  2.304 17.375 10.098 17.519 ;
     RECT  50.652 16.105 50.742 17.581 ;
     RECT  0.144 17.467 0.558 17.597 ;
     RECT  14.688 17.411 21.006 17.609 ;
     RECT  14.688 17.609 20.898 17.645 ;
     RECT  22.32 17.455 28.35 17.645 ;
     RECT  14.688 17.645 20.538 17.681 ;
     RECT  44.532 17.419 48.186 17.689 ;
     RECT  0.54 17.597 0.558 17.741 ;
     RECT  44.532 17.689 48.258 17.761 ;
     RECT  49.032 17.383 49.158 17.761 ;
     RECT  14.688 17.681 20.358 18.023 ;
     RECT  44.532 17.761 49.158 18.031 ;
     RECT  19.62 18.023 20.358 18.059 ;
     RECT  43.632 17.411 43.65 18.121 ;
     RECT  44.532 18.031 49.554 18.121 ;
     RECT  43.632 18.121 49.554 18.185 ;
     RECT  50.652 17.581 50.778 18.193 ;
     RECT  19.944 18.059 20.358 18.221 ;
     RECT  22.32 17.645 22.446 18.221 ;
     RECT  14.688 18.023 18.897 18.235 ;
     RECT  42.516 18.229 42.534 18.235 ;
     RECT  41.292 16.259 41.31 18.329 ;
     RECT  42.372 18.235 42.534 18.499 ;
     RECT  43.632 18.185 49.05 18.499 ;
     RECT  14.292 18.235 18.897 18.563 ;
     RECT  0.144 18.475 0.162 18.605 ;
     RECT  50.184 18.193 50.778 18.605 ;
     RECT  42.372 18.499 49.05 18.689 ;
     RECT  42.372 18.689 44.01 18.725 ;
     RECT  42.768 18.725 44.01 18.761 ;
     RECT  14.94 18.563 18.897 18.797 ;
     RECT  50.544 18.605 50.778 18.797 ;
     RECT  15.192 18.797 18.897 18.833 ;
     RECT  50.688 18.797 50.778 18.893 ;
     RECT  43.992 18.761 44.01 18.959 ;
     RECT  0.18 18.859 0.198 18.989 ;
     RECT  50.688 18.893 50.742 19.037 ;
     RECT  44.82 18.689 49.05 19.147 ;
     RECT  44.82 19.147 49.41 19.435 ;
     RECT  0.54 19.345 0.558 19.469 ;
     RECT  44.82 19.435 49.554 19.571 ;
     RECT  42.876 19.507 42.894 19.651 ;
     RECT  42.804 19.651 42.894 19.679 ;
     RECT  51.732 17.563 51.75 19.723 ;
     RECT  42.804 19.679 42.822 19.885 ;
     RECT  0.144 19.771 0.162 19.901 ;
     RECT  42.588 19.885 42.822 19.913 ;
     RECT  50.688 19.037 50.706 20.083 ;
     RECT  50.616 20.083 50.706 20.147 ;
     RECT  44.82 19.571 46.35 20.155 ;
     RECT  51.696 19.723 51.75 20.155 ;
     RECT  50.616 20.147 50.634 20.219 ;
     RECT  43.668 20.155 43.686 20.345 ;
     RECT  44.64 20.155 46.35 20.345 ;
     RECT  50.076 20.299 50.094 20.381 ;
     RECT  42.588 19.913 42.786 20.453 ;
     RECT  51.66 20.155 51.75 20.453 ;
     RECT  44.82 20.345 46.35 20.551 ;
     RECT  47.232 19.571 49.05 20.551 ;
     RECT  44.82 20.551 49.05 20.587 ;
     RECT  2.304 17.519 9.522 20.893 ;
     RECT  13.215 17.375 13.497 20.929 ;
     RECT  13.104 20.929 13.497 20.965 ;
     RECT  2.16 20.893 9.522 21.053 ;
     RECT  13.104 20.965 13.698 21.163 ;
     RECT  44.82 20.587 49.59 21.163 ;
     RECT  42.588 20.453 42.606 21.199 ;
     RECT  44.1 21.163 49.734 21.199 ;
     RECT  13.104 21.163 14.094 21.235 ;
     RECT  43.956 21.199 49.734 21.271 ;
     RECT  42.588 21.199 42.75 21.361 ;
     RECT  43.56 21.271 49.734 21.361 ;
     RECT  13.032 21.235 14.094 21.389 ;
     RECT  42.588 21.361 49.734 21.425 ;
     RECT  51.696 20.453 51.75 21.425 ;
     RECT  44.532 21.425 49.734 21.451 ;
     RECT  42.588 21.425 43.578 21.497 ;
     RECT  13.14 21.389 14.094 21.541 ;
     RECT  44.532 21.451 50.094 21.731 ;
     RECT  13.14 21.541 14.238 21.739 ;
     RECT  42.588 21.497 43.434 21.811 ;
     RECT  2.304 21.053 9.522 21.929 ;
     RECT  42.48 21.811 43.434 21.965 ;
     RECT  44.532 21.731 49.59 21.965 ;
     RECT  51.732 21.425 51.75 22.109 ;
     RECT  42.588 21.965 43.434 22.199 ;
     RECT  0.144 21.499 0.162 22.205 ;
     RECT  43.524 22.351 43.542 22.441 ;
     RECT  43.524 22.441 43.614 22.469 ;
     RECT  50.688 21.901 50.742 22.493 ;
     RECT  44.82 21.965 49.59 22.549 ;
     RECT  13.14 21.739 14.958 22.585 ;
     RECT  15.876 18.833 18.897 22.585 ;
     RECT  44.82 22.549 49.662 22.603 ;
     RECT  43.596 22.469 43.614 22.613 ;
     RECT  42.588 22.199 42.606 22.711 ;
     RECT  10.908 22.621 10.926 22.775 ;
     RECT  37.404 16.259 40.554 22.855 ;
     RECT  44.82 22.603 50.166 22.891 ;
     RECT  44.64 22.891 50.166 23.045 ;
     RECT  42.516 22.711 42.606 23.089 ;
     RECT  44.892 23.045 50.166 23.153 ;
     RECT  50.076 23.153 50.166 23.251 ;
     RECT  42.516 23.089 42.858 23.279 ;
     RECT  50.076 23.251 50.742 23.357 ;
     RECT  2.415 21.929 9.522 23.521 ;
     RECT  37.404 22.855 40.626 23.557 ;
     RECT  51.732 23.035 51.75 23.611 ;
     RECT  50.076 23.357 50.094 23.621 ;
     RECT  37.404 23.557 40.842 23.665 ;
     RECT  10.836 22.891 10.854 23.701 ;
     RECT  43.668 22.747 43.686 23.701 ;
     RECT  51.696 23.611 51.75 23.729 ;
     RECT  1.152 23.755 1.17 23.885 ;
     RECT  2.304 23.521 9.522 23.891 ;
     RECT  33.336 16.411 35.262 23.899 ;
     RECT  5.328 23.891 9.522 23.963 ;
     RECT  43.668 23.701 43.83 23.971 ;
     RECT  44.892 23.153 49.05 23.971 ;
     RECT  43.668 23.971 49.05 24.043 ;
     RECT  10.836 23.701 10.89 24.133 ;
     RECT  10.764 24.133 10.89 24.205 ;
     RECT  42.516 23.279 42.786 24.205 ;
     RECT  50.724 24.133 50.742 24.221 ;
     RECT  10.764 24.205 10.926 24.233 ;
     RECT  42.3 24.205 42.786 24.269 ;
     RECT  5.328 23.963 9.378 24.359 ;
     RECT  43.668 24.043 49.626 24.431 ;
     RECT  33.336 23.899 35.658 24.637 ;
     RECT  37.404 23.665 41.49 24.709 ;
     RECT  42.3 24.269 42.75 24.709 ;
     RECT  10.836 24.233 10.926 24.809 ;
     RECT  51.732 23.729 51.75 24.809 ;
     RECT  2.304 23.891 4.554 24.871 ;
     RECT  44.604 24.431 49.626 24.899 ;
     RECT  37.404 24.709 42.75 24.943 ;
     RECT  44.892 24.899 49.626 25.043 ;
     RECT  2.304 24.871 4.59 25.051 ;
     RECT  5.328 24.359 9.27 25.051 ;
     RECT  33.336 24.637 35.73 25.051 ;
     RECT  36.756 24.943 42.75 25.051 ;
     RECT  50.652 24.673 50.67 25.051 ;
     RECT  0.144 23.467 0.162 25.085 ;
     RECT  43.668 24.431 43.686 25.249 ;
     RECT  33.336 25.051 42.75 25.285 ;
     RECT  2.304 25.051 9.27 25.313 ;
     RECT  50.148 25.051 50.67 25.321 ;
     RECT  2.304 25.313 9.198 25.349 ;
     RECT  50.148 25.321 50.742 25.373 ;
     RECT  44.892 25.043 49.302 25.439 ;
     RECT  33.12 25.285 42.75 25.447 ;
     RECT  44.892 25.439 49.05 25.475 ;
     RECT  44.892 25.475 46.89 25.511 ;
     RECT  10.8 25.447 10.818 25.519 ;
     RECT  50.148 25.373 50.202 25.52 ;
     RECT  2.304 25.349 9.126 25.547 ;
     RECT  50.184 25.52 50.202 25.583 ;
     RECT  10.728 25.519 10.818 25.619 ;
     RECT  51.732 25.627 51.75 25.771 ;
     RECT  33.12 25.447 42.894 25.825 ;
     RECT  43.668 25.249 43.83 25.825 ;
     RECT  51.696 25.771 51.75 25.915 ;
     RECT  33.12 25.825 43.83 25.951 ;
     RECT  44.892 25.511 45.897 25.951 ;
     RECT  51.66 25.915 51.75 26.015 ;
     RECT  33.084 25.951 45.897 26.051 ;
     RECT  51.696 26.015 51.75 26.285 ;
     RECT  44.892 26.051 45.897 26.365 ;
     RECT  46.8 25.511 46.89 26.365 ;
     RECT  10.836 25.753 10.854 26.393 ;
     RECT  47.844 25.475 49.05 26.491 ;
     RECT  44.892 26.365 46.89 26.563 ;
     RECT  47.736 26.491 49.05 26.563 ;
     RECT  23.328 17.645 28.35 26.599 ;
     RECT  33.084 26.051 44.118 26.627 ;
     RECT  2.304 25.547 8.91 26.635 ;
     RECT  23.328 26.599 28.386 26.761 ;
     RECT  29.415 2.525 29.697 26.761 ;
     RECT  50.688 26.257 50.706 26.779 ;
     RECT  50.184 26.779 50.706 26.869 ;
     RECT  2.304 26.635 9.27 26.897 ;
     RECT  44.1 26.627 44.118 26.905 ;
     RECT  44.892 26.563 49.05 26.905 ;
     RECT  44.1 26.905 49.05 26.933 ;
     RECT  50.184 26.869 50.814 26.957 ;
     RECT  44.568 26.933 49.05 27.059 ;
     RECT  33.084 26.627 42.93 27.095 ;
     RECT  10.872 27.103 10.89 27.211 ;
     RECT  50.184 26.957 50.778 27.211 ;
     RECT  44.568 27.059 46.206 27.341 ;
     RECT  0.54 27.139 0.558 27.355 ;
     RECT  50.148 27.211 50.778 27.365 ;
     RECT  50.688 27.365 50.778 27.389 ;
     RECT  2.304 26.897 9.09 27.509 ;
     RECT  46.944 27.059 49.05 27.635 ;
     RECT  10.8 27.211 10.89 27.643 ;
     RECT  2.304 27.509 9.054 27.677 ;
     RECT  50.688 27.389 50.742 27.677 ;
     RECT  20.34 18.221 20.358 27.707 ;
     RECT  10.764 27.643 10.89 27.715 ;
     RECT  50.688 27.677 50.706 27.743 ;
     RECT  10.764 27.715 10.926 27.779 ;
     RECT  51.732 26.285 51.75 27.931 ;
     RECT  0.144 27.355 0.558 27.965 ;
     RECT  51.696 27.931 51.75 28.013 ;
     RECT  47.376 27.635 49.05 28.022 ;
     RECT  47.412 28.022 49.05 28.075 ;
     RECT  0.144 27.965 0.162 28.109 ;
     RECT  47.412 28.075 49.518 28.139 ;
     RECT  23.328 26.761 29.697 28.147 ;
     RECT  47.484 28.139 49.518 28.175 ;
     RECT  47.844 28.175 49.518 28.211 ;
     RECT  44.892 27.341 46.206 28.219 ;
     RECT  33.084 27.095 42.894 28.291 ;
     RECT  44.532 28.219 46.206 28.291 ;
     RECT  10.836 27.779 10.926 28.409 ;
     RECT  33.084 28.291 43.542 28.409 ;
     RECT  2.376 27.677 9.054 28.417 ;
     RECT  44.424 28.291 46.494 28.445 ;
     RECT  51.732 28.013 51.75 28.445 ;
     RECT  2.376 28.417 9.234 28.517 ;
     RECT  2.376 28.517 9.198 28.651 ;
     RECT  23.328 28.147 30.078 28.651 ;
     RECT  44.892 28.445 46.206 28.679 ;
     RECT  10.908 28.409 10.926 29.057 ;
     RECT  2.304 28.651 9.198 29.129 ;
     RECT  2.412 29.129 9.198 29.299 ;
     RECT  10.8 29.191 10.854 29.371 ;
     RECT  20.52 28.561 20.538 29.371 ;
     RECT  21.384 29.335 21.402 29.371 ;
     RECT  20.52 29.371 21.402 29.461 ;
     RECT  22.32 18.221 22.338 29.461 ;
     RECT  47.844 28.211 49.05 29.467 ;
     RECT  2.412 29.299 9.306 29.525 ;
     RECT  10.728 29.371 10.854 29.597 ;
     RECT  2.412 29.525 9.126 29.633 ;
     RECT  50.148 29.515 50.166 29.659 ;
     RECT  20.52 29.461 22.338 29.767 ;
     RECT  33.084 28.409 42.894 29.767 ;
     RECT  2.412 29.633 9.09 29.831 ;
     RECT  0.144 29.659 0.162 29.885 ;
     RECT  44.892 28.679 45.897 29.911 ;
     RECT  50.148 29.659 50.202 29.911 ;
     RECT  2.412 29.831 9.054 29.947 ;
     RECT  20.52 29.767 22.518 30.073 ;
     RECT  10.8 29.597 10.854 30.209 ;
     RECT  33.084 29.767 43.614 30.235 ;
     RECT  47.484 29.467 49.05 30.235 ;
     RECT  50.148 29.911 50.742 30.235 ;
     RECT  44.892 29.911 46.314 30.271 ;
     RECT  2.304 29.947 9.054 30.299 ;
     RECT  47.412 30.235 49.05 30.299 ;
     RECT  44.82 30.271 46.314 30.343 ;
     RECT  33.084 30.235 43.686 30.379 ;
     RECT  20.016 30.073 22.518 30.451 ;
     RECT  23.328 28.651 30.474 30.451 ;
     RECT  44.82 30.343 46.746 30.451 ;
     RECT  44.604 30.451 46.746 30.569 ;
     RECT  47.484 30.299 49.05 30.569 ;
     RECT  2.415 30.299 9.054 30.677 ;
     RECT  47.844 30.569 49.05 30.811 ;
     RECT  50.076 30.235 50.742 30.811 ;
     RECT  33.084 30.379 43.83 30.883 ;
     RECT  1.152 30.811 1.17 30.941 ;
     RECT  47.844 30.811 50.742 30.983 ;
     RECT  2.415 30.677 9.018 31.081 ;
     RECT  33.084 30.883 44.01 31.109 ;
     RECT  33.084 31.109 43.902 31.145 ;
     RECT  10.836 30.209 10.854 31.217 ;
     RECT  44.82 30.569 46.746 31.387 ;
     RECT  47.844 30.983 50.706 31.387 ;
     RECT  44.82 31.387 50.706 31.451 ;
     RECT  44.82 31.451 50.202 31.531 ;
     RECT  51.732 30.523 51.75 31.675 ;
     RECT  2.304 31.081 9.018 31.693 ;
     RECT  33.084 31.145 43.686 31.709 ;
     RECT  2.304 31.693 9.054 31.729 ;
     RECT  44.64 31.531 50.202 31.757 ;
     RECT  2.304 31.729 9.414 31.765 ;
     RECT  51.696 31.675 51.75 31.829 ;
     RECT  2.304 31.765 9.666 31.963 ;
     RECT  44.676 31.757 50.202 31.997 ;
     RECT  2.304 31.963 10.062 32.251 ;
     RECT  44.676 31.997 49.554 32.261 ;
     RECT  50.724 32.341 50.742 32.429 ;
     RECT  2.268 32.251 10.062 32.459 ;
     RECT  44.676 32.261 49.518 32.495 ;
     RECT  2.304 32.459 10.062 32.611 ;
     RECT  0.54 32.341 0.558 32.717 ;
     RECT  20.016 30.451 30.474 32.737 ;
     RECT  2.304 32.611 10.134 32.809 ;
     RECT  20.016 32.737 30.798 32.837 ;
     RECT  1.152 32.779 1.17 33.005 ;
     RECT  33.084 31.709 43.542 33.115 ;
     RECT  44.82 32.495 49.518 33.115 ;
     RECT  33.084 33.115 43.578 33.305 ;
     RECT  44.82 33.115 50.202 33.341 ;
     RECT  44.82 33.341 49.302 33.377 ;
     RECT  2.304 32.809 10.71 33.385 ;
     RECT  44.82 33.377 44.874 33.413 ;
     RECT  2.304 33.385 11.106 33.421 ;
     RECT  51.732 31.829 51.75 33.449 ;
     RECT  20.016 32.837 30.474 33.583 ;
     RECT  43.812 33.349 43.83 33.691 ;
     RECT  44.82 33.413 44.838 33.691 ;
     RECT  50.148 33.341 50.202 33.781 ;
     RECT  20.016 33.583 30.546 33.889 ;
     RECT  2.304 33.421 11.682 33.925 ;
     RECT  45.615 33.377 49.302 33.953 ;
     RECT  2.304 33.925 11.79 33.961 ;
     RECT  33.084 33.305 42.894 34.429 ;
     RECT  43.812 33.691 44.838 34.429 ;
     RECT  0.54 33.961 0.558 34.445 ;
     RECT  2.304 33.961 12.366 34.501 ;
     RECT  13.14 22.585 18.897 34.501 ;
     RECT  33.084 34.429 44.838 34.501 ;
     RECT  45.615 33.953 49.05 34.501 ;
     RECT  51.732 34.411 51.75 35.131 ;
     RECT  51.696 35.131 51.75 35.159 ;
     RECT  51.696 35.159 51.714 35.195 ;
     RECT  33.084 34.501 49.05 35.339 ;
     RECT  44.568 35.339 49.05 35.735 ;
     RECT  2.304 34.501 18.897 35.741 ;
     RECT  33.084 35.339 42.93 35.771 ;
     RECT  50.148 33.781 50.742 35.851 ;
     RECT  2.412 35.741 18.897 35.969 ;
     RECT  49.824 35.851 50.742 36.113 ;
     RECT  0.144 35.419 0.162 36.269 ;
     RECT  50.724 36.113 50.742 36.317 ;
     RECT  49.824 36.113 49.842 36.383 ;
     RECT  44.64 35.735 49.05 36.509 ;
     RECT  47.304 36.509 49.05 36.571 ;
     RECT  2.415 35.969 18.897 36.715 ;
     RECT  43.848 36.475 43.866 36.823 ;
     RECT  44.64 36.509 46.458 36.823 ;
     RECT  33.084 35.771 42.894 36.859 ;
     RECT  43.848 36.823 46.458 36.859 ;
     RECT  47.304 36.571 49.626 36.887 ;
     RECT  33.084 36.859 46.458 36.959 ;
     RECT  33.084 36.959 43.866 37.085 ;
     RECT  51.732 36.427 51.75 37.291 ;
     RECT  43.668 37.085 43.866 37.319 ;
     RECT  44.64 36.959 46.458 37.319 ;
     RECT  47.304 36.887 49.05 37.399 ;
     RECT  0.144 37.051 0.162 37.421 ;
     RECT  44.64 37.319 46.314 37.625 ;
     RECT  47.196 37.399 49.05 37.625 ;
     RECT  50.148 37.165 50.202 37.625 ;
     RECT  47.196 37.625 47.862 37.741 ;
     RECT  33.084 37.085 42.894 37.867 ;
     RECT  43.668 37.319 43.686 37.867 ;
     RECT  51.696 37.291 51.75 37.931 ;
     RECT  2.304 36.715 18.897 38.129 ;
     RECT  33.084 37.867 43.686 38.155 ;
     RECT  20.016 33.889 31.266 38.281 ;
     RECT  44.82 37.625 46.314 38.281 ;
     RECT  47.088 37.741 47.862 38.281 ;
     RECT  33.084 38.155 43.866 38.371 ;
     RECT  44.82 38.281 47.862 38.399 ;
     RECT  50.724 38.005 50.742 38.407 ;
     RECT  0.144 38.299 0.162 38.429 ;
     RECT  47.556 38.399 47.862 38.551 ;
     RECT  48.6 37.625 49.05 38.551 ;
     RECT  33.084 38.371 44.082 38.669 ;
     RECT  20.016 38.281 31.338 38.785 ;
     RECT  47.556 38.551 49.05 38.821 ;
     RECT  2.412 38.129 18.897 38.875 ;
     RECT  47.556 38.821 49.554 38.875 ;
     RECT  50.652 38.407 50.742 38.875 ;
     RECT  2.304 38.875 18.897 38.911 ;
     RECT  2.304 38.911 19.206 38.947 ;
     RECT  44.82 38.399 46.818 38.947 ;
     RECT  2.304 38.947 19.278 39.019 ;
     RECT  20.016 38.785 31.77 39.019 ;
     RECT  2.304 39.019 31.77 39.055 ;
     RECT  47.556 38.875 50.742 39.092 ;
     RECT  47.592 39.092 50.742 39.197 ;
     RECT  44.424 38.947 46.818 39.209 ;
     RECT  47.592 39.197 50.202 39.209 ;
     RECT  47.664 39.209 49.05 39.245 ;
     RECT  2.304 39.055 32.166 39.281 ;
     RECT  44.424 39.209 46.638 39.317 ;
     RECT  20.016 39.281 32.166 39.793 ;
     RECT  33.084 38.669 43.686 39.793 ;
     RECT  51.732 37.931 51.75 39.883 ;
     RECT  51.66 39.883 51.75 40.013 ;
     RECT  50.076 39.209 50.202 40.027 ;
     RECT  50.076 40.027 50.706 40.091 ;
     RECT  44.64 39.317 46.638 40.135 ;
     RECT  50.076 40.091 50.202 40.163 ;
     RECT  47.844 39.245 49.05 40.171 ;
     RECT  47.844 40.171 49.842 40.261 ;
     RECT  20.016 39.793 43.686 40.289 ;
     RECT  44.604 40.135 46.638 40.289 ;
     RECT  0.144 39.883 0.162 40.397 ;
     RECT  2.304 39.281 18.897 40.559 ;
     RECT  47.484 40.261 49.842 40.703 ;
     RECT  43.668 40.289 43.686 40.795 ;
     RECT  0.54 40.873 0.558 41.069 ;
     RECT  43.668 40.795 43.866 41.071 ;
     RECT  43.668 41.071 43.902 41.107 ;
     RECT  44.676 40.289 46.638 41.107 ;
     RECT  20.016 40.289 42.894 41.131 ;
     RECT  43.668 41.107 46.638 41.131 ;
     RECT  20.016 41.131 46.638 41.143 ;
     RECT  47.484 40.703 49.302 41.243 ;
     RECT  20.016 41.143 46.71 41.251 ;
     RECT  47.484 41.243 49.05 41.251 ;
     RECT  20.016 41.251 49.05 41.405 ;
     RECT  2.415 40.559 18.897 41.413 ;
     RECT  2.415 41.413 18.954 41.467 ;
     RECT  44.82 41.405 49.05 41.549 ;
     RECT  50.184 41.179 50.202 41.611 ;
     RECT  2.304 41.467 18.954 41.639 ;
     RECT  2.415 41.639 18.954 41.683 ;
     RECT  0.144 41.611 0.162 41.741 ;
     RECT  49.824 41.611 50.202 41.783 ;
     RECT  2.415 41.683 19.206 41.909 ;
     RECT  3.492 41.909 19.206 41.989 ;
     RECT  20.016 41.405 43.542 41.989 ;
     RECT  51.732 40.013 51.75 42.017 ;
     RECT  3.492 41.989 43.542 42.179 ;
     RECT  3.492 42.179 43.11 42.215 ;
     RECT  50.148 41.783 50.202 42.251 ;
     RECT  50.184 42.251 50.202 42.295 ;
     RECT  44.82 41.549 46.386 42.331 ;
     RECT  47.16 41.549 49.05 42.331 ;
     RECT  50.184 42.295 50.274 42.331 ;
     RECT  44.82 42.331 49.05 42.449 ;
     RECT  3.816 42.215 43.11 42.521 ;
     RECT  44.82 42.449 46.71 42.557 ;
     RECT  50.184 42.331 50.742 42.653 ;
     RECT  44.82 42.557 46.674 42.755 ;
     RECT  47.448 42.449 49.05 42.899 ;
     RECT  44.82 42.755 46.242 42.989 ;
     RECT  51.732 43.195 51.75 43.295 ;
     RECT  3.816 42.521 42.966 43.339 ;
     RECT  3.816 43.339 43.578 43.375 ;
     RECT  50.184 42.653 50.706 43.411 ;
     RECT  3.816 43.375 43.614 43.601 ;
     RECT  50.184 43.411 50.742 43.627 ;
     RECT  46.98 43.339 46.998 43.645 ;
     RECT  47.844 42.899 49.05 43.645 ;
     RECT  44.82 42.989 46.17 43.771 ;
     RECT  50.076 43.627 50.742 43.805 ;
     RECT  3.816 43.601 43.038 43.871 ;
     RECT  46.98 43.645 49.05 43.871 ;
     RECT  47.304 43.871 49.05 43.915 ;
     RECT  50.076 43.805 50.094 43.915 ;
     RECT  44.82 43.771 46.242 43.951 ;
     RECT  44.82 43.951 46.494 44.113 ;
     RECT  44.784 44.113 46.494 44.149 ;
     RECT  44.604 44.149 46.494 44.221 ;
     RECT  43.884 44.221 46.494 44.347 ;
     RECT  3.816 43.871 42.894 44.375 ;
     RECT  43.668 44.347 46.494 44.411 ;
     RECT  47.304 43.915 50.094 44.635 ;
     RECT  3.924 44.375 42.894 44.851 ;
     RECT  43.668 44.411 43.722 44.851 ;
     RECT  3.924 44.851 43.722 44.915 ;
     RECT  51.732 44.059 51.75 44.923 ;
     RECT  51.696 44.923 51.75 44.951 ;
     RECT  51.696 44.951 51.714 45.023 ;
     RECT  44.532 44.411 46.494 45.121 ;
     RECT  47.304 44.635 50.202 45.121 ;
     RECT  44.532 45.121 50.202 45.185 ;
     RECT  44.604 45.185 50.202 45.257 ;
     RECT  50.112 45.257 50.202 45.265 ;
     RECT  50.112 45.265 50.706 45.389 ;
     RECT  50.112 45.389 50.202 45.833 ;
     RECT  3.924 44.915 43.542 46.219 ;
     RECT  44.604 45.257 49.05 46.219 ;
     RECT  50.112 45.833 50.166 46.219 ;
     RECT  3.924 46.219 43.686 46.229 ;
     RECT  44.604 46.219 50.166 46.229 ;
     RECT  43.668 46.229 43.686 46.741 ;
     RECT  43.668 46.741 43.83 46.769 ;
     RECT  44.784 46.229 50.166 46.885 ;
     RECT  2.415 41.909 2.697 46.921 ;
     RECT  3.924 46.229 42.93 46.921 ;
     RECT  44.784 46.885 50.202 46.973 ;
     RECT  44.784 46.973 50.166 47.011 ;
     RECT  2.415 46.921 42.93 47.275 ;
     RECT  43.812 46.769 43.83 47.275 ;
     RECT  44.712 47.011 50.166 47.275 ;
     RECT  43.812 47.275 50.166 47.309 ;
     RECT  2.415 47.275 43.038 47.597 ;
     RECT  44.1 47.309 50.166 47.695 ;
     RECT  44.1 47.695 50.706 47.849 ;
     RECT  2.415 47.597 42.894 47.933 ;
     RECT  44.1 47.849 48.546 48.029 ;
     RECT  44.1 48.029 46.782 48.119 ;
     RECT  44.1 48.119 44.118 48.155 ;
     RECT  45.18 48.119 46.782 48.227 ;
     RECT  49.608 47.849 50.706 48.272 ;
     RECT  2.415 47.933 2.898 48.389 ;
     RECT  45.18 48.227 46.35 48.389 ;
     RECT  47.844 48.029 48.546 48.389 ;
     RECT  49.608 48.272 49.626 48.413 ;
     RECT  2.415 48.389 2.754 48.425 ;
     RECT  45.18 48.389 45.897 48.425 ;
     RECT  47.844 48.389 48.474 48.461 ;
     RECT  3.708 47.933 42.894 48.695 ;
     RECT  50.688 48.272 50.706 48.695 ;
     RECT  48.456 48.461 48.474 48.839 ;
     RECT  3.852 48.695 42.894 49.081 ;
     RECT  3.852 49.081 43.002 49.199 ;
     RECT  3.852 49.199 42.858 49.235 ;
     RECT  3.888 49.235 22.482 49.271 ;
     RECT  2.415 48.425 2.697 49.427 ;
     RECT  45.615 48.425 45.897 49.427 ;
     RECT  3.888 49.271 22.41 49.505 ;
     RECT  23.328 49.235 42.822 49.517 ;
     RECT  3.924 49.505 22.338 49.541 ;
     RECT  3.924 49.541 22.266 49.565 ;
     RECT  23.328 49.517 32.454 49.565 ;
     RECT  33.372 49.517 42.822 49.565 ;
     RECT  3.924 49.565 21.006 49.577 ;
     RECT  22.176 49.565 22.266 49.577 ;
     RECT  23.328 49.565 32.202 49.577 ;
     RECT  41.328 49.565 42.534 49.577 ;
     RECT  22.176 49.577 22.23 49.649 ;
     RECT  2.415 49.427 2.505 49.697 ;
     RECT  45.615 49.427 45.705 49.697 ;
     RECT  23.652 49.577 32.202 49.805 ;
     RECT  3.924 49.577 19.458 49.853 ;
     RECT  23.652 49.805 23.886 49.853 ;
     RECT  33.372 49.565 40.482 49.853 ;
     RECT  8.316 49.853 19.458 50.141 ;
     RECT  20.268 49.577 20.826 50.141 ;
     RECT  24.732 49.805 32.202 50.141 ;
     RECT  33.372 49.853 40.374 50.141 ;
     RECT  3.924 49.853 7.506 50.189 ;
     RECT  14.328 50.141 18.45 50.189 ;
     RECT  20.808 50.141 20.826 50.189 ;
     RECT  24.732 50.141 28.962 50.189 ;
     RECT  35.568 50.141 36.774 50.189 ;
     RECT  39.672 50.141 40.374 50.189 ;
     RECT  41.328 49.577 41.922 50.189 ;
     RECT  30.024 50.141 32.202 50.237 ;
     RECT  3.924 50.189 7.362 50.669 ;
     RECT  3.924 50.669 7.074 50.717 ;
     RECT  8.316 50.141 11.97 50.717 ;
     RECT  12.924 50.141 12.942 50.717 ;
     RECT  14.328 50.189 17.982 50.717 ;
     RECT  19.44 50.141 19.458 50.717 ;
     RECT  22.176 49.649 22.194 50.717 ;
     RECT  24.732 50.189 27.09 50.717 ;
     RECT  28.368 50.189 28.962 50.717 ;
     RECT  30.024 50.237 31.626 50.717 ;
     RECT  33.372 50.141 34.398 50.717 ;
     RECT  35.568 50.189 35.586 50.717 ;
     RECT  36.396 50.189 36.414 50.717 ;
     RECT  38.484 50.141 38.502 50.717 ;
     RECT  39.672 50.189 39.906 50.717 ;
     RECT  41.328 50.189 41.346 50.717 ;
     RECT  4.104 50.717 4.23 50.729 ;
     RECT  30.024 50.717 30.114 50.729 ;
     RECT  39.78 50.717 39.906 50.729 ;
     RECT  4.212 50.729 4.23 50.765 ;
     RECT  5.688 50.717 6.534 50.765 ;
     RECT  8.784 50.717 9.522 50.765 ;
     RECT  10.8 50.717 11.646 50.765 ;
     RECT  15.804 50.717 17.046 50.765 ;
     RECT  17.928 50.717 17.982 50.765 ;
     RECT  24.876 50.717 26.73 50.765 ;
     RECT  30.096 50.729 30.114 50.765 ;
     RECT  33.912 50.717 33.93 50.765 ;
     RECT  16.128 50.765 16.146 50.813 ;
     RECT  6.408 50.765 6.534 51.677 ;
     RECT  6.408 51.677 6.426 51.725 ;
     RECT  8.784 50.765 9.414 51.725 ;
     RECT  11.628 50.765 11.646 51.725 ;
     RECT  13.572 51.547 13.59 51.725 ;
     RECT  17.028 50.765 17.046 51.725 ;
     RECT  17.964 50.765 17.982 51.725 ;
     RECT  23.652 49.853 23.67 51.725 ;
     RECT  25.488 50.765 26.73 51.725 ;
     RECT  31.14 50.717 31.626 51.725 ;
     RECT  39.78 50.729 39.798 51.725 ;
    LAYER M4 ;
     RECT  0.084 1.008 0.173 1.032 ;
     RECT  0.06 1.032 0.173 1.152 ;
     RECT  0.084 1.152 0.173 1.176 ;
     RECT  0.06 1.176 0.173 1.296 ;
     RECT  0.084 1.296 0.173 1.32 ;
     RECT  0.06 1.32 0.173 1.44 ;
     RECT  0.084 1.44 0.173 1.464 ;
     RECT  0.06 1.464 0.173 1.584 ;
     RECT  0.084 1.584 0.173 1.608 ;
     RECT  0.06 1.608 0.173 1.728 ;
     RECT  0.084 1.728 0.173 1.752 ;
     RECT  0.06 1.752 0.173 1.872 ;
     RECT  0.084 1.872 0.173 1.896 ;
     RECT  0.06 1.896 0.173 2.016 ;
     RECT  0.084 2.016 0.173 2.04 ;
     RECT  0.06 2.04 0.173 2.16 ;
     RECT  0.084 2.16 0.173 2.184 ;
     RECT  0.06 2.184 0.173 2.304 ;
     RECT  0.084 2.304 0.173 2.328 ;
     RECT  0.06 2.328 0.173 2.448 ;
     RECT  0.084 2.448 0.173 2.472 ;
     RECT  0.06 2.472 0.173 2.592 ;
     RECT  0.084 2.592 0.173 2.616 ;
     RECT  0.06 2.616 0.173 2.736 ;
     RECT  0.084 2.736 0.173 2.76 ;
     RECT  0.06 2.76 0.173 2.88 ;
     RECT  0.084 2.88 0.173 2.904 ;
     RECT  0.06 2.904 0.173 3.024 ;
     RECT  0.084 3.024 0.173 3.048 ;
     RECT  0.06 3.048 0.173 3.168 ;
     RECT  0.084 3.168 0.173 3.192 ;
     RECT  0.06 3.192 0.173 3.312 ;
     RECT  0.084 3.312 0.173 3.336 ;
     RECT  0.06 3.336 0.173 3.456 ;
     RECT  0.084 3.456 0.173 3.48 ;
     RECT  0.06 3.48 0.173 3.6 ;
     RECT  0.084 3.6 0.173 3.624 ;
     RECT  0.06 3.624 0.173 3.744 ;
     RECT  0.084 3.744 0.173 3.768 ;
     RECT  0.06 3.768 0.173 3.888 ;
     RECT  0.084 3.888 0.173 3.912 ;
     RECT  0.06 3.912 0.173 4.032 ;
     RECT  0.084 4.032 0.173 4.056 ;
     RECT  0.06 4.056 0.173 4.176 ;
     RECT  0.084 4.176 0.173 4.2 ;
     RECT  0.06 4.2 0.173 4.32 ;
     RECT  0.084 4.32 0.173 4.344 ;
     RECT  0.06 4.344 0.173 4.464 ;
     RECT  0.084 4.464 0.173 4.488 ;
     RECT  0.06 4.488 0.173 4.608 ;
     RECT  0.084 4.608 0.173 4.632 ;
     RECT  0.06 4.632 0.173 4.752 ;
     RECT  0.084 4.752 0.173 4.776 ;
     RECT  0.06 4.776 0.173 4.896 ;
     RECT  0.084 4.896 0.173 4.92 ;
     RECT  0.06 4.92 0.173 5.04 ;
     RECT  0.084 5.04 0.173 5.064 ;
     RECT  0.06 5.064 0.173 5.184 ;
     RECT  0.084 5.184 0.173 5.208 ;
     RECT  0.06 5.208 0.173 5.328 ;
     RECT  0.084 5.328 0.173 5.352 ;
     RECT  0.06 5.352 0.173 5.472 ;
     RECT  0.084 5.472 0.173 5.496 ;
     RECT  0.06 5.496 0.173 5.616 ;
     RECT  0.084 5.616 0.173 5.64 ;
     RECT  0.06 5.64 0.173 5.76 ;
     RECT  0.084 5.76 0.173 5.784 ;
     RECT  0.06 5.784 0.173 5.904 ;
     RECT  0.084 5.904 0.173 5.928 ;
     RECT  0.06 5.928 0.173 6.048 ;
     RECT  0.084 6.048 0.173 6.072 ;
     RECT  0.06 6.072 0.173 6.192 ;
     RECT  0.084 6.192 0.173 6.216 ;
     RECT  0.06 6.216 0.173 6.336 ;
     RECT  0.084 6.336 0.173 6.36 ;
     RECT  0.06 6.36 0.173 6.48 ;
     RECT  0.084 6.48 0.173 6.504 ;
     RECT  0.06 6.504 0.173 6.624 ;
     RECT  0.084 6.624 0.173 6.648 ;
     RECT  0.06 6.648 0.173 6.768 ;
     RECT  0.084 6.768 0.173 6.792 ;
     RECT  0.06 6.792 0.173 6.912 ;
     RECT  0.084 6.912 0.173 6.936 ;
     RECT  0.06 6.936 0.173 7.056 ;
     RECT  0.084 7.056 0.173 7.08 ;
     RECT  0.06 7.08 0.173 7.2 ;
     RECT  0.084 7.2 0.173 7.224 ;
     RECT  0.06 7.224 0.173 7.344 ;
     RECT  0.084 7.344 0.173 7.368 ;
     RECT  0.06 7.368 0.173 7.488 ;
     RECT  0.084 7.488 0.173 7.512 ;
     RECT  0.06 7.512 0.173 7.632 ;
     RECT  0.084 7.632 0.173 7.656 ;
     RECT  0.06 7.656 0.173 7.776 ;
     RECT  0.084 7.776 0.173 7.8 ;
     RECT  0.06 7.8 0.173 7.92 ;
     RECT  0.084 7.92 0.173 7.944 ;
     RECT  0.06 7.944 0.173 8.064 ;
     RECT  0.084 8.064 0.173 8.088 ;
     RECT  0.06 8.088 0.173 8.208 ;
     RECT  0.084 8.208 0.173 8.232 ;
     RECT  0.06 8.232 0.173 8.352 ;
     RECT  0.084 8.352 0.173 8.376 ;
     RECT  0.06 8.376 0.173 8.496 ;
     RECT  0.084 8.496 0.173 8.52 ;
     RECT  0.06 8.52 0.173 8.64 ;
     RECT  0.084 8.64 0.173 8.664 ;
     RECT  0.06 8.664 0.173 8.784 ;
     RECT  0.084 8.784 0.173 8.808 ;
     RECT  0.06 8.808 0.173 8.928 ;
     RECT  0.084 8.928 0.173 8.952 ;
     RECT  0.06 8.952 0.173 9.072 ;
     RECT  0.084 9.072 0.173 9.096 ;
     RECT  0.06 9.096 0.173 9.216 ;
     RECT  0.084 9.216 0.173 9.24 ;
     RECT  0.06 9.24 0.173 9.36 ;
     RECT  0.084 9.36 0.173 9.384 ;
     RECT  0.06 9.384 0.173 9.504 ;
     RECT  0.084 9.504 0.173 9.528 ;
     RECT  0.06 9.528 0.173 9.648 ;
     RECT  0.084 9.648 0.173 9.672 ;
     RECT  0.06 9.672 0.173 9.792 ;
     RECT  0.084 9.792 0.173 9.816 ;
     RECT  0.06 9.816 0.173 9.936 ;
     RECT  0.084 9.936 0.173 9.96 ;
     RECT  0.06 9.96 0.173 10.08 ;
     RECT  0.084 10.08 0.173 10.104 ;
     RECT  0.06 10.104 0.173 10.224 ;
     RECT  0.084 10.224 0.173 10.248 ;
     RECT  0.06 10.248 0.173 10.368 ;
     RECT  0.084 10.368 0.173 10.392 ;
     RECT  0.06 10.392 0.173 10.512 ;
     RECT  0.084 10.512 0.173 10.536 ;
     RECT  0.06 10.536 0.173 10.656 ;
     RECT  0.084 10.656 0.173 10.68 ;
     RECT  0.06 10.68 0.173 10.8 ;
     RECT  0.084 10.8 0.173 10.824 ;
     RECT  0.06 10.824 0.173 10.944 ;
     RECT  0.084 10.944 0.173 10.968 ;
     RECT  0.06 10.968 0.173 11.088 ;
     RECT  0.084 11.088 0.173 11.112 ;
     RECT  0.06 11.112 0.173 11.232 ;
     RECT  0.084 11.232 0.173 11.256 ;
     RECT  0.06 11.256 0.173 11.376 ;
     RECT  0.084 11.376 0.173 11.4 ;
     RECT  0.06 11.4 0.173 11.52 ;
     RECT  0.084 11.52 0.173 11.544 ;
     RECT  0.06 11.544 0.173 11.664 ;
     RECT  0.084 11.664 0.173 11.688 ;
     RECT  0.06 11.688 0.173 11.808 ;
     RECT  0.084 11.808 0.173 11.832 ;
     RECT  0.06 11.832 0.173 11.952 ;
     RECT  0.084 11.952 0.173 11.976 ;
     RECT  0.06 11.976 0.173 12.096 ;
     RECT  0.084 12.096 0.173 12.12 ;
     RECT  0.06 12.12 0.173 12.24 ;
     RECT  0.084 12.24 0.173 12.264 ;
     RECT  0.06 12.264 0.173 12.384 ;
     RECT  0.084 12.384 0.173 12.408 ;
     RECT  0.06 12.408 0.173 12.528 ;
     RECT  0.084 12.528 0.173 12.552 ;
     RECT  0.06 12.552 0.173 12.672 ;
     RECT  0.084 12.672 0.173 12.696 ;
     RECT  0.06 12.696 0.173 12.816 ;
     RECT  0.084 12.816 0.173 12.84 ;
     RECT  0.06 12.84 0.173 12.96 ;
     RECT  0.084 12.96 0.173 12.984 ;
     RECT  0.06 12.984 0.173 13.104 ;
     RECT  0.084 13.104 0.173 13.128 ;
     RECT  0.06 13.128 0.173 13.248 ;
     RECT  0.084 13.248 0.173 13.272 ;
     RECT  0.06 13.272 0.173 13.392 ;
     RECT  0.084 13.392 0.173 13.416 ;
     RECT  0.06 13.416 0.173 13.536 ;
     RECT  0.084 13.536 0.173 13.56 ;
     RECT  0.06 13.56 0.173 13.68 ;
     RECT  0.084 13.68 0.173 13.704 ;
     RECT  0.06 13.704 0.173 13.824 ;
     RECT  0.084 13.824 0.173 13.848 ;
     RECT  0.06 13.848 0.173 13.968 ;
     RECT  0.084 13.968 0.173 13.992 ;
     RECT  0.06 13.992 0.173 14.112 ;
     RECT  0.084 14.112 0.173 14.136 ;
     RECT  0.06 14.136 0.173 14.256 ;
     RECT  0.084 14.256 0.173 14.28 ;
     RECT  0.06 14.28 0.173 14.4 ;
     RECT  0.084 14.4 0.173 14.424 ;
     RECT  0.06 14.424 0.173 14.544 ;
     RECT  0.084 14.544 0.173 14.568 ;
     RECT  0.06 14.568 0.173 14.688 ;
     RECT  0.084 14.688 0.173 14.712 ;
     RECT  0.06 14.712 0.173 14.832 ;
     RECT  0.084 14.832 0.173 14.856 ;
     RECT  0.06 14.856 0.173 14.976 ;
     RECT  0.084 14.976 0.173 15 ;
     RECT  0.06 15 0.173 15.12 ;
     RECT  0.084 15.12 0.173 15.144 ;
     RECT  0.06 15.144 0.173 15.264 ;
     RECT  0.084 15.264 0.173 15.288 ;
     RECT  0.06 15.288 0.173 15.408 ;
     RECT  0.084 15.408 0.173 15.432 ;
     RECT  0.06 15.432 0.173 15.552 ;
     RECT  0.084 15.552 0.173 15.576 ;
     RECT  0.06 15.576 0.173 15.696 ;
     RECT  0.084 15.696 0.173 15.72 ;
     RECT  0.06 15.72 0.173 15.84 ;
     RECT  0.084 15.84 0.173 15.864 ;
     RECT  0.06 15.864 0.173 15.984 ;
     RECT  0.084 15.984 0.173 16.008 ;
     RECT  0.06 16.008 0.173 16.128 ;
     RECT  0.084 16.128 0.173 16.152 ;
     RECT  0.06 16.152 0.173 16.272 ;
     RECT  0.084 16.272 0.173 16.296 ;
     RECT  0.06 16.296 0.173 16.416 ;
     RECT  0.084 16.416 0.173 16.44 ;
     RECT  0.06 16.44 0.173 16.56 ;
     RECT  0.084 16.56 0.173 16.584 ;
     RECT  0.06 16.584 0.173 16.704 ;
     RECT  0.084 16.704 0.173 16.728 ;
     RECT  0.06 16.728 0.173 16.848 ;
     RECT  0.084 16.848 0.173 16.872 ;
     RECT  0.06 16.872 0.173 16.992 ;
     RECT  0.084 16.992 0.173 17.016 ;
     RECT  0.06 17.016 0.173 17.136 ;
     RECT  0.084 17.136 0.173 17.16 ;
     RECT  0.06 17.16 0.173 17.28 ;
     RECT  0.084 17.28 0.173 17.304 ;
     RECT  0.06 17.304 0.173 17.424 ;
     RECT  0.084 17.424 0.173 17.448 ;
     RECT  0.06 17.448 0.173 17.568 ;
     RECT  0.084 17.568 0.173 17.592 ;
     RECT  0.06 17.592 0.173 17.712 ;
     RECT  0.084 17.712 0.173 17.736 ;
     RECT  0.06 17.736 0.173 17.856 ;
     RECT  0.084 17.856 0.173 17.88 ;
     RECT  0.06 17.88 0.173 18 ;
     RECT  0.084 18 0.173 18.024 ;
     RECT  0.06 18.024 0.173 18.144 ;
     RECT  0.084 18.144 0.173 18.168 ;
     RECT  0.06 18.168 0.173 18.288 ;
     RECT  0.084 18.288 0.173 18.312 ;
     RECT  0.06 18.312 0.173 18.432 ;
     RECT  0.084 18.432 0.173 18.456 ;
     RECT  0.06 18.456 0.173 18.576 ;
     RECT  0.084 18.576 0.173 18.6 ;
     RECT  0.06 18.6 0.173 18.72 ;
     RECT  0.084 18.72 0.173 18.744 ;
     RECT  0.06 18.744 0.173 18.864 ;
     RECT  0.084 18.864 0.173 18.888 ;
     RECT  0.06 18.888 0.173 19.008 ;
     RECT  0.084 19.008 0.173 19.032 ;
     RECT  0.06 19.032 0.173 19.152 ;
     RECT  0.084 19.152 0.173 19.176 ;
     RECT  0.06 19.176 0.173 19.296 ;
     RECT  0.084 19.296 0.173 19.32 ;
     RECT  0.06 19.32 0.173 19.44 ;
     RECT  0.084 19.44 0.173 19.464 ;
     RECT  0.06 19.464 0.173 19.584 ;
     RECT  0.084 19.584 0.173 19.608 ;
     RECT  0.06 19.608 0.173 19.728 ;
     RECT  0.084 19.728 0.173 19.752 ;
     RECT  0.06 19.752 0.173 19.872 ;
     RECT  0.084 19.872 0.173 19.896 ;
     RECT  0.06 19.896 0.173 20.016 ;
     RECT  0.084 20.016 0.173 20.04 ;
     RECT  0.06 20.04 0.173 20.16 ;
     RECT  0.084 20.16 0.173 20.184 ;
     RECT  0.06 20.184 0.173 20.304 ;
     RECT  0.084 20.304 0.173 20.328 ;
     RECT  0.06 20.328 0.173 20.448 ;
     RECT  0.084 20.448 0.173 20.472 ;
     RECT  0.06 20.472 0.173 20.592 ;
     RECT  0.084 20.592 0.173 20.616 ;
     RECT  0.06 20.616 0.173 20.736 ;
     RECT  0.084 20.736 0.173 20.76 ;
     RECT  0.06 20.76 0.173 20.88 ;
     RECT  0.084 20.88 0.173 20.904 ;
     RECT  0.06 20.904 0.173 21.024 ;
     RECT  0.084 21.024 0.173 21.048 ;
     RECT  0.06 21.048 0.173 21.168 ;
     RECT  0.084 21.168 0.173 21.192 ;
     RECT  0.06 21.192 0.173 21.312 ;
     RECT  0.084 21.312 0.173 21.336 ;
     RECT  0.06 21.336 0.173 21.456 ;
     RECT  0.084 21.456 0.173 21.48 ;
     RECT  0.06 21.48 0.173 21.6 ;
     RECT  0.084 21.6 0.173 21.624 ;
     RECT  0.06 21.624 0.173 21.744 ;
     RECT  0.084 21.744 0.173 21.768 ;
     RECT  0.06 21.768 0.173 21.888 ;
     RECT  0.084 21.888 0.173 21.912 ;
     RECT  0.06 21.912 0.173 22.032 ;
     RECT  0.084 22.032 0.173 22.056 ;
     RECT  0.06 22.056 0.173 22.176 ;
     RECT  0.084 22.176 0.173 22.2 ;
     RECT  0.084 23.472 0.173 23.496 ;
     RECT  0.06 23.496 0.173 23.616 ;
     RECT  0.084 23.616 0.173 23.64 ;
     RECT  0.06 23.64 0.173 23.76 ;
     RECT  0.084 23.76 0.173 23.784 ;
     RECT  0.06 23.784 0.173 23.904 ;
     RECT  0.084 23.904 0.173 23.928 ;
     RECT  0.06 23.928 0.173 24.048 ;
     RECT  0.084 24.048 0.173 24.072 ;
     RECT  0.06 24.072 0.173 24.192 ;
     RECT  0.084 24.192 0.173 24.216 ;
     RECT  0.06 24.216 0.173 24.336 ;
     RECT  0.084 24.336 0.173 24.36 ;
     RECT  0.06 24.36 0.173 24.48 ;
     RECT  0.084 24.48 0.173 24.504 ;
     RECT  0.06 24.504 0.173 24.624 ;
     RECT  0.084 24.624 0.173 24.648 ;
     RECT  0.06 24.648 0.173 24.768 ;
     RECT  0.084 24.768 0.173 24.792 ;
     RECT  0.06 24.792 0.173 24.912 ;
     RECT  0.084 24.912 0.173 24.936 ;
     RECT  0.06 24.936 0.173 25.056 ;
     RECT  0.084 25.056 0.173 25.08 ;
     RECT  0.06 25.08 0.173 25.2 ;
     RECT  0.084 25.2 0.173 25.224 ;
     RECT  0.06 25.224 0.173 25.344 ;
     RECT  0.084 25.344 0.173 25.368 ;
     RECT  0.06 25.368 0.173 25.488 ;
     RECT  0.084 25.488 0.173 25.512 ;
     RECT  0.06 25.512 0.173 25.632 ;
     RECT  0.084 25.632 0.173 25.656 ;
     RECT  0.06 25.656 0.173 25.776 ;
     RECT  0.084 25.776 0.173 25.8 ;
     RECT  0.06 25.8 0.173 25.92 ;
     RECT  0.084 25.92 0.173 25.944 ;
     RECT  0.06 25.944 0.173 26.064 ;
     RECT  0.084 26.064 0.173 26.088 ;
     RECT  0.06 26.088 0.173 26.208 ;
     RECT  0.084 26.208 0.173 26.232 ;
     RECT  0.06 26.232 0.173 26.352 ;
     RECT  0.084 26.352 0.173 26.376 ;
     RECT  0.06 26.376 0.173 26.496 ;
     RECT  0.084 26.496 0.173 26.52 ;
     RECT  0.06 26.52 0.173 26.64 ;
     RECT  0.084 26.64 0.173 26.664 ;
     RECT  0.06 26.664 0.173 26.784 ;
     RECT  0.084 26.784 0.173 26.808 ;
     RECT  0.06 26.808 0.173 26.928 ;
     RECT  0.084 26.928 0.173 26.952 ;
     RECT  0.06 26.952 0.173 27.072 ;
     RECT  0.084 27.072 0.173 27.096 ;
     RECT  0.06 27.096 0.173 27.216 ;
     RECT  0.084 27.216 0.173 27.24 ;
     RECT  0.06 27.24 0.173 27.36 ;
     RECT  0.084 27.36 0.173 27.384 ;
     RECT  0.06 27.384 0.173 27.504 ;
     RECT  0.084 27.504 0.173 27.528 ;
     RECT  0.06 27.528 0.173 27.648 ;
     RECT  0.084 27.648 0.173 27.672 ;
     RECT  0.06 27.672 0.173 27.792 ;
     RECT  0.084 27.792 0.173 27.816 ;
     RECT  0.06 27.816 0.173 27.936 ;
     RECT  0.084 27.936 0.173 27.96 ;
     RECT  0.06 27.96 0.173 28.08 ;
     RECT  0.084 28.08 0.173 28.104 ;
     RECT  0.06 28.104 0.173 28.224 ;
     RECT  0.084 28.224 0.173 28.248 ;
     RECT  0.06 28.248 0.173 28.368 ;
     RECT  0.084 28.368 0.173 28.392 ;
     RECT  0.06 28.392 0.173 28.512 ;
     RECT  0.084 28.512 0.173 28.536 ;
     RECT  0.06 28.536 0.173 28.656 ;
     RECT  0.084 28.656 0.173 28.68 ;
     RECT  0.06 28.68 0.173 28.8 ;
     RECT  0.084 28.8 0.173 28.824 ;
     RECT  0.06 28.824 0.173 28.944 ;
     RECT  0.084 28.944 0.173 28.968 ;
     RECT  0.06 28.968 0.173 29.088 ;
     RECT  0.084 29.088 0.173 29.112 ;
     RECT  0.06 29.112 0.173 29.232 ;
     RECT  0.084 29.232 0.173 29.256 ;
     RECT  0.06 29.256 0.173 29.376 ;
     RECT  0.084 29.376 0.173 29.4 ;
     RECT  0.06 29.4 0.173 29.52 ;
     RECT  0.084 29.52 0.173 29.544 ;
     RECT  0.06 29.544 0.173 29.664 ;
     RECT  0.084 29.664 0.173 29.688 ;
     RECT  0.06 29.688 0.173 29.808 ;
     RECT  0.084 29.808 0.173 29.832 ;
     RECT  0.06 29.832 0.173 29.952 ;
     RECT  0.084 29.952 0.173 29.976 ;
     RECT  0.06 29.976 0.173 30.096 ;
     RECT  0.084 30.096 0.173 30.12 ;
     RECT  0.06 30.12 0.173 30.24 ;
     RECT  0.084 30.24 0.173 30.264 ;
     RECT  0.06 30.264 0.173 30.384 ;
     RECT  0.084 30.384 0.173 30.408 ;
     RECT  0.06 30.408 0.173 30.528 ;
     RECT  0.084 30.528 0.173 30.552 ;
     RECT  0.06 30.552 0.173 30.672 ;
     RECT  0.084 30.672 0.173 30.696 ;
     RECT  0.06 30.696 0.173 30.816 ;
     RECT  0.084 30.816 0.173 30.84 ;
     RECT  0.06 30.84 0.173 30.96 ;
     RECT  0.084 30.96 0.173 30.984 ;
     RECT  0.06 30.984 0.173 31.104 ;
     RECT  0.084 31.104 0.173 31.128 ;
     RECT  0.06 31.128 0.173 31.248 ;
     RECT  0.084 31.248 0.173 31.272 ;
     RECT  0.06 31.272 0.173 31.392 ;
     RECT  0.084 31.392 0.173 31.416 ;
     RECT  0.06 31.416 0.173 31.536 ;
     RECT  0.084 31.536 0.173 31.56 ;
     RECT  0.06 31.56 0.173 31.68 ;
     RECT  0.084 31.68 0.173 31.704 ;
     RECT  0.06 31.704 0.173 31.824 ;
     RECT  0.084 31.824 0.173 31.848 ;
     RECT  0.06 31.848 0.173 31.968 ;
     RECT  0.084 31.968 0.173 31.992 ;
     RECT  0.06 31.992 0.173 32.112 ;
     RECT  0.084 32.112 0.173 32.136 ;
     RECT  0.06 32.136 0.173 32.256 ;
     RECT  0.084 32.256 0.173 32.28 ;
     RECT  0.06 32.28 0.173 32.4 ;
     RECT  0.084 32.4 0.173 32.424 ;
     RECT  0.06 32.424 0.173 32.544 ;
     RECT  0.084 32.544 0.173 32.568 ;
     RECT  0.06 32.568 0.173 32.688 ;
     RECT  0.084 32.688 0.173 32.712 ;
     RECT  0.06 32.712 0.173 32.832 ;
     RECT  0.084 32.832 0.173 32.856 ;
     RECT  0.06 32.856 0.173 32.976 ;
     RECT  0.084 32.976 0.173 33 ;
     RECT  0.06 33 0.173 33.12 ;
     RECT  0.084 33.12 0.173 33.144 ;
     RECT  0.06 33.144 0.173 33.264 ;
     RECT  0.084 33.264 0.173 33.288 ;
     RECT  0.06 33.288 0.173 33.408 ;
     RECT  0.084 33.408 0.173 33.432 ;
     RECT  0.06 33.432 0.173 33.552 ;
     RECT  0.084 33.552 0.173 33.576 ;
     RECT  0.06 33.576 0.173 33.696 ;
     RECT  0.084 33.696 0.173 33.72 ;
     RECT  0.06 33.72 0.173 33.84 ;
     RECT  0.084 33.84 0.173 33.864 ;
     RECT  0.06 33.864 0.173 33.984 ;
     RECT  0.084 33.984 0.173 34.008 ;
     RECT  0.06 34.008 0.173 34.128 ;
     RECT  0.084 34.128 0.173 34.152 ;
     RECT  0.06 34.152 0.173 34.272 ;
     RECT  0.084 34.272 0.173 34.296 ;
     RECT  0.06 34.296 0.173 34.416 ;
     RECT  0.084 34.416 0.173 34.44 ;
     RECT  0.06 34.44 0.173 34.56 ;
     RECT  0.084 34.56 0.173 34.584 ;
     RECT  0.06 34.584 0.173 34.704 ;
     RECT  0.084 34.704 0.173 34.728 ;
     RECT  0.06 34.728 0.173 34.848 ;
     RECT  0.084 34.848 0.173 34.872 ;
     RECT  0.06 34.872 0.173 34.992 ;
     RECT  0.084 34.992 0.173 35.016 ;
     RECT  0.06 35.016 0.173 35.136 ;
     RECT  0.084 35.136 0.173 35.16 ;
     RECT  0.06 35.16 0.173 35.28 ;
     RECT  0.084 35.28 0.173 35.304 ;
     RECT  0.06 35.304 0.173 35.424 ;
     RECT  0.084 35.424 0.173 35.448 ;
     RECT  0.06 35.448 0.173 35.568 ;
     RECT  0.084 35.568 0.173 35.592 ;
     RECT  0.06 35.592 0.173 35.712 ;
     RECT  0.084 35.712 0.173 35.736 ;
     RECT  0.06 35.736 0.173 35.856 ;
     RECT  0.084 35.856 0.173 35.88 ;
     RECT  0.06 35.88 0.173 36 ;
     RECT  0.084 36 0.173 36.024 ;
     RECT  0.06 36.024 0.173 36.144 ;
     RECT  0.084 36.144 0.173 36.168 ;
     RECT  0.06 36.168 0.173 36.288 ;
     RECT  0.084 36.288 0.173 36.312 ;
     RECT  0.06 36.312 0.173 36.432 ;
     RECT  0.084 36.432 0.173 36.456 ;
     RECT  0.06 36.456 0.173 36.576 ;
     RECT  0.084 36.576 0.173 36.6 ;
     RECT  0.06 36.6 0.173 36.72 ;
     RECT  0.084 36.72 0.173 36.744 ;
     RECT  0.06 36.744 0.173 36.864 ;
     RECT  0.084 36.864 0.173 36.888 ;
     RECT  0.06 36.888 0.173 37.008 ;
     RECT  0.084 37.008 0.173 37.032 ;
     RECT  0.06 37.032 0.173 37.152 ;
     RECT  0.084 37.152 0.173 37.176 ;
     RECT  0.06 37.176 0.173 37.296 ;
     RECT  0.084 37.296 0.173 37.32 ;
     RECT  0.06 37.32 0.173 37.44 ;
     RECT  0.084 37.44 0.173 37.464 ;
     RECT  0.06 37.464 0.173 37.584 ;
     RECT  0.084 37.584 0.173 37.608 ;
     RECT  0.06 37.608 0.173 37.728 ;
     RECT  0.084 37.728 0.173 37.752 ;
     RECT  0.06 37.752 0.173 37.872 ;
     RECT  0.084 37.872 0.173 37.896 ;
     RECT  0.06 37.896 0.173 38.016 ;
     RECT  0.084 38.016 0.173 38.04 ;
     RECT  0.06 38.04 0.173 38.16 ;
     RECT  0.084 38.16 0.173 38.184 ;
     RECT  0.06 38.184 0.173 38.304 ;
     RECT  0.084 38.304 0.173 38.328 ;
     RECT  0.06 38.328 0.173 38.448 ;
     RECT  0.084 38.448 0.173 38.472 ;
     RECT  0.06 38.472 0.173 38.592 ;
     RECT  0.084 38.592 0.173 38.616 ;
     RECT  0.06 38.616 0.173 38.736 ;
     RECT  0.084 38.736 0.173 38.76 ;
     RECT  0.06 38.76 0.173 38.88 ;
     RECT  0.084 38.88 0.173 38.904 ;
     RECT  0.06 38.904 0.173 39.024 ;
     RECT  0.084 39.024 0.173 39.048 ;
     RECT  0.06 39.048 0.173 39.168 ;
     RECT  0.084 39.168 0.173 39.192 ;
     RECT  0.06 39.192 0.173 39.312 ;
     RECT  0.084 39.312 0.173 39.336 ;
     RECT  0.06 39.336 0.173 39.456 ;
     RECT  0.084 39.456 0.173 39.48 ;
     RECT  0.06 39.48 0.173 39.6 ;
     RECT  0.084 39.6 0.173 39.624 ;
     RECT  0.06 39.624 0.173 39.744 ;
     RECT  0.084 39.744 0.173 39.768 ;
     RECT  0.06 39.768 0.173 39.888 ;
     RECT  0.084 39.888 0.173 39.912 ;
     RECT  0.06 39.912 0.173 40.032 ;
     RECT  0.084 40.032 0.173 40.056 ;
     RECT  0.06 40.056 0.173 40.176 ;
     RECT  0.084 40.176 0.173 40.2 ;
     RECT  0.06 40.2 0.173 40.32 ;
     RECT  0.084 40.32 0.173 40.344 ;
     RECT  0.06 40.344 0.173 40.464 ;
     RECT  0.084 40.464 0.173 40.488 ;
     RECT  0.06 40.488 0.173 40.608 ;
     RECT  0.084 40.608 0.173 40.632 ;
     RECT  0.06 40.632 0.173 40.752 ;
     RECT  0.084 40.752 0.173 40.776 ;
     RECT  0.06 40.776 0.173 40.896 ;
     RECT  0.084 40.896 0.173 40.92 ;
     RECT  0.06 40.92 0.173 41.04 ;
     RECT  0.084 41.04 0.173 41.064 ;
     RECT  0.06 41.064 0.173 41.184 ;
     RECT  0.084 41.184 0.173 41.208 ;
     RECT  0.06 41.208 0.173 41.328 ;
     RECT  0.084 41.328 0.173 41.352 ;
     RECT  0.06 41.352 0.173 41.472 ;
     RECT  0.084 41.472 0.173 41.496 ;
     RECT  0.06 41.496 0.173 41.616 ;
     RECT  0.084 41.616 0.173 41.64 ;
     RECT  0.06 41.64 0.173 41.76 ;
     RECT  0.084 41.76 0.173 41.784 ;
     RECT  0.173 1.008 1.757 22.056 ;
     RECT  1.757 1.152 2.408 22.056 ;
     RECT  0.173 23.568 2.408 41.784 ;
     RECT  2.408 1.152 2.512 49.692 ;
     RECT  2.512 1.152 2.704 49.422 ;
     RECT  2.704 47.904 3.805 47.928 ;
     RECT  3.869 50.688 4.021 50.712 ;
     RECT  2.704 1.152 4.097 22.056 ;
     RECT  3.805 47.904 4.165 48.12 ;
     RECT  4.021 50.16 4.201 50.712 ;
     RECT  4.165 47.904 4.252 49.032 ;
     RECT  4.201 50.16 4.355 50.76 ;
     RECT  4.252 47.904 4.421 48.12 ;
     RECT  4.097 1.296 4.501 22.056 ;
     RECT  2.704 23.424 4.501 42.456 ;
     RECT  4.501 1.296 4.588 22.152 ;
     RECT  4.501 45.648 4.588 45.672 ;
     RECT  4.501 46.752 4.601 46.776 ;
     RECT  4.421 47.904 4.669 47.928 ;
     RECT  4.669 47.856 4.781 47.928 ;
     RECT  4.355 50.16 4.877 50.712 ;
     RECT  5.101 46.656 5.321 46.68 ;
     RECT  4.501 23.424 5.357 42.744 ;
     RECT  5.276 48.912 5.42 48.936 ;
     RECT  4.877 50.112 5.65 50.712 ;
     RECT  5.357 23.424 5.717 42.024 ;
     RECT  4.781 47.856 5.785 47.88 ;
     RECT  5.42 48.912 5.785 49.08 ;
     RECT  5.65 50.112 5.939 50.76 ;
     RECT  5.785 47.856 6.037 49.08 ;
     RECT  4.588 1.296 6.109 21.864 ;
     RECT  6.037 47.808 6.145 49.08 ;
     RECT  6.109 1.296 6.181 21.912 ;
     RECT  6.181 1.296 6.217 21.96 ;
     RECT  6.217 1.296 6.293 22.584 ;
     RECT  5.939 50.736 6.325 50.76 ;
     RECT  6.325 50.736 6.437 51.72 ;
     RECT  6.437 50.736 6.545 51.672 ;
     RECT  5.929 46.752 6.577 46.776 ;
     RECT  6.145 47.808 6.577 49.56 ;
     RECT  6.545 50.736 6.659 50.76 ;
     RECT  6.577 46.752 6.797 49.56 ;
     RECT  6.797 46.752 6.937 47.88 ;
     RECT  6.293 2.016 6.973 22.584 ;
     RECT  5.717 23.904 6.973 42.024 ;
     RECT  6.901 50.688 7.045 50.712 ;
     RECT  7.045 50.64 7.085 50.712 ;
     RECT  6.797 48.96 7.148 49.56 ;
     RECT  7.085 50.64 7.148 50.664 ;
     RECT  6.973 2.016 7.261 42.024 ;
     RECT  7.261 2.016 7.481 42.072 ;
     RECT  7.481 2.148 7.808 42.072 ;
     RECT  6.937 46.56 7.808 47.88 ;
     RECT  7.148 48.96 7.808 50.664 ;
     RECT  7.669 51.648 7.811 51.672 ;
     RECT  7.808 2.148 7.912 50.664 ;
     RECT  7.912 2.418 8.053 50.664 ;
     RECT  8.053 2.418 8.104 50.712 ;
     RECT  8.104 34.128 8.165 34.68 ;
     RECT  8.104 2.496 8.201 5.064 ;
     RECT  8.104 6.336 8.201 7.464 ;
     RECT  8.104 19.248 8.201 20.616 ;
     RECT  8.104 29.472 8.237 30.408 ;
     RECT  8.104 32.208 8.237 33.144 ;
     RECT  8.104 39.744 8.237 43.368 ;
     RECT  8.201 3.12 8.273 5.064 ;
     RECT  8.201 7.392 8.273 7.464 ;
     RECT  8.104 48.864 8.291 50.712 ;
     RECT  8.104 8.496 8.309 14.136 ;
     RECT  8.104 23.904 8.309 26.088 ;
     RECT  8.237 29.472 8.309 29.88 ;
     RECT  8.104 37.056 8.309 38.52 ;
     RECT  8.201 19.344 8.345 20.616 ;
     RECT  8.237 32.208 8.345 32.616 ;
     RECT  8.165 34.128 8.345 34.392 ;
     RECT  8.345 19.968 8.381 20.616 ;
     RECT  8.345 34.128 8.381 34.2 ;
     RECT  8.309 37.056 8.381 37.944 ;
     RECT  8.237 40.848 8.381 43.368 ;
     RECT  8.381 40.896 8.425 43.368 ;
     RECT  8.273 3.12 8.453 5.016 ;
     RECT  8.104 21.84 8.453 22.296 ;
     RECT  8.381 34.128 8.453 34.152 ;
     RECT  8.425 40.896 8.461 42.792 ;
     RECT  8.381 19.968 8.489 20.568 ;
     RECT  8.345 32.304 8.525 32.616 ;
     RECT  8.461 40.896 8.525 42.024 ;
     RECT  8.489 19.968 8.561 19.992 ;
     RECT  8.309 23.904 8.597 25.32 ;
     RECT  8.525 32.304 8.597 32.568 ;
     RECT  8.104 16.848 8.63 17.736 ;
     RECT  8.273 7.44 8.633 7.464 ;
     RECT  8.104 45.216 8.669 47.88 ;
     RECT  8.453 3.12 8.705 4.92 ;
     RECT  8.104 27.12 8.705 27.96 ;
     RECT  8.705 3.12 8.813 4.776 ;
     RECT  8.309 29.568 8.957 29.88 ;
     RECT  8.291 49.056 8.963 50.712 ;
     RECT  8.669 46.176 9.029 47.88 ;
     RECT  8.705 27.12 9.065 27.144 ;
     RECT  8.201 6.336 9.107 6.36 ;
     RECT  8.104 15.168 9.133 15.816 ;
     RECT  8.63 16.848 9.133 17.688 ;
     RECT  8.453 21.84 9.137 21.864 ;
     RECT  8.597 25.056 9.137 25.32 ;
     RECT  8.957 29.568 9.137 29.592 ;
     RECT  9.133 15.168 9.164 17.688 ;
     RECT  9.164 15.12 9.173 17.688 ;
     RECT  8.597 23.904 9.173 23.928 ;
     RECT  8.309 13.104 9.205 14.136 ;
     RECT  9.173 15.12 9.205 17.496 ;
     RECT  9.137 25.296 9.209 25.32 ;
     RECT  9.205 13.104 9.251 17.496 ;
     RECT  8.963 49.056 9.281 49.464 ;
     RECT  8.963 50.688 9.308 50.712 ;
     RECT  8.629 51.696 9.308 51.72 ;
     RECT  8.813 3.936 9.353 4.776 ;
     RECT  9.308 50.688 9.425 51.72 ;
     RECT  9.425 50.688 9.539 50.76 ;
     RECT  9.353 3.936 9.713 4.68 ;
     RECT  9.029 46.176 9.817 46.776 ;
     RECT  8.597 32.304 10.037 32.328 ;
     RECT  9.817 45.696 10.069 46.776 ;
     RECT  9.029 47.856 10.069 47.88 ;
     RECT  10.069 45.696 10.253 47.88 ;
     RECT  9.251 13.632 10.285 17.496 ;
     RECT  8.309 8.496 10.321 11.784 ;
     RECT  10.285 12.816 10.321 17.496 ;
     RECT  10.253 45.696 10.325 46.776 ;
     RECT  9.281 49.056 10.357 49.08 ;
     RECT  10.357 49.056 10.429 49.416 ;
     RECT  10.325 46.56 10.469 46.776 ;
     RECT  10.429 48.912 10.501 49.416 ;
     RECT  9.539 50.688 10.721 50.712 ;
     RECT  10.321 8.496 10.829 17.496 ;
     RECT  10.829 8.496 10.901 14.184 ;
     RECT  10.789 50.736 11.123 50.76 ;
     RECT  10.469 46.752 11.153 46.776 ;
     RECT  10.901 8.496 11.225 12.84 ;
     RECT  10.253 47.856 11.437 47.88 ;
     RECT  10.501 48.912 11.437 49.608 ;
     RECT  11.509 51.696 11.657 51.72 ;
     RECT  11.437 47.856 12.049 49.608 ;
     RECT  12.049 47.808 12.085 49.608 ;
     RECT  11.941 50.688 12.085 50.712 ;
     RECT  11.437 45.936 12.193 46.632 ;
     RECT  12.193 45.936 12.229 46.728 ;
     RECT  12.085 47.808 12.229 50.712 ;
     RECT  12.229 45.936 12.373 50.712 ;
     RECT  8.237 39.744 12.517 39.768 ;
     RECT  11.225 8.496 12.805 12.792 ;
     RECT  10.901 13.872 12.805 14.184 ;
     RECT  10.829 15.168 12.805 17.496 ;
     RECT  12.373 45.552 12.953 50.712 ;
     RECT  9.713 3.936 13.208 3.96 ;
     RECT  12.805 8.496 13.208 17.496 ;
     RECT  12.517 39.216 13.208 39.768 ;
     RECT  8.525 41.376 13.208 42.024 ;
     RECT  12.953 45.552 13.208 50.136 ;
     RECT  13.208 2.148 13.312 50.136 ;
     RECT  13.312 2.418 13.504 50.136 ;
     RECT  13.381 51.552 13.517 51.672 ;
     RECT  13.517 51.552 13.601 51.72 ;
     RECT  13.504 43.008 13.637 43.032 ;
     RECT  13.504 7.44 13.645 18.264 ;
     RECT  13.504 44.88 13.667 46.872 ;
     RECT  13.601 51.552 13.667 51.672 ;
     RECT  13.504 48.912 13.681 50.136 ;
     RECT  13.645 8.448 13.745 18.264 ;
     RECT  13.681 48.96 13.817 50.136 ;
     RECT  13.817 49.056 14.105 50.136 ;
     RECT  13.504 47.904 14.321 47.928 ;
     RECT  13.667 44.88 14.393 44.904 ;
     RECT  13.667 46.176 14.525 46.872 ;
     RECT  14.525 46.176 14.609 47.304 ;
     RECT  14.609 46.176 14.773 46.872 ;
     RECT  14.821 22.752 14.933 22.776 ;
     RECT  14.105 49.056 15.011 49.608 ;
     RECT  14.773 45.888 15.109 46.872 ;
     RECT  13.645 7.44 15.145 7.464 ;
     RECT  13.745 8.496 15.145 18.264 ;
     RECT  14.245 50.688 15.212 50.712 ;
     RECT  15.109 45.552 15.617 46.872 ;
     RECT  14.641 43.872 15.653 43.896 ;
     RECT  15.212 50.112 15.793 50.712 ;
     RECT  15.617 45.552 16.081 45.576 ;
     RECT  15.793 50.112 16.117 50.76 ;
     RECT  16.081 45.216 16.157 45.576 ;
     RECT  15.011 49.056 16.189 49.128 ;
     RECT  16.117 50.112 16.189 50.808 ;
     RECT  15.145 7.44 16.213 18.264 ;
     RECT  16.213 6.672 16.3 18.264 ;
     RECT  16.3 7.152 16.301 18.264 ;
     RECT  16.189 49.056 16.405 50.808 ;
     RECT  16.157 45.216 16.481 45.24 ;
     RECT  15.617 46.656 16.501 46.872 ;
     RECT  16.405 48.432 16.661 50.808 ;
     RECT  16.301 8.208 16.733 18.264 ;
     RECT  16.733 8.208 16.769 17.496 ;
     RECT  16.501 46.656 16.769 47.352 ;
     RECT  16.661 50.688 16.837 50.808 ;
     RECT  16.769 8.208 16.985 13.944 ;
     RECT  16.985 8.208 17.021 13.464 ;
     RECT  16.769 46.656 17.125 46.872 ;
     RECT  17.021 8.208 17.201 13.224 ;
     RECT  17.201 8.208 17.273 12.888 ;
     RECT  16.301 7.152 17.341 7.224 ;
     RECT  17.341 7.152 17.413 7.32 ;
     RECT  16.661 48.432 17.413 49.56 ;
     RECT  17.413 6.912 17.453 7.32 ;
     RECT  17.413 48.384 17.525 49.56 ;
     RECT  17.525 48.432 17.597 49.56 ;
     RECT  17.597 49.008 17.881 49.56 ;
     RECT  16.837 50.688 17.881 51.72 ;
     RECT  17.125 45.984 17.917 46.872 ;
     RECT  17.557 44.448 17.989 44.472 ;
     RECT  17.881 49.008 17.993 51.72 ;
     RECT  17.989 44.448 18.169 45 ;
     RECT  17.917 45.984 18.169 47.352 ;
     RECT  17.993 49.008 18.323 50.76 ;
     RECT  16.769 14.976 18.349 17.496 ;
     RECT  18.349 14.64 18.457 17.496 ;
     RECT  18.323 49.008 18.467 50.184 ;
     RECT  14.533 1.728 18.608 1.752 ;
     RECT  13.504 3.936 18.608 3.96 ;
     RECT  17.453 6.912 18.608 7.224 ;
     RECT  17.273 8.448 18.608 12.888 ;
     RECT  18.457 14.496 18.608 17.496 ;
     RECT  13.504 39.216 18.608 39.24 ;
     RECT  13.504 41.376 18.608 42.024 ;
     RECT  18.169 44.448 18.608 47.352 ;
     RECT  18.467 49.008 18.608 50.136 ;
     RECT  18.608 1.728 18.904 50.136 ;
     RECT  18.904 38.784 18.965 39.24 ;
     RECT  18.904 48.624 19.073 50.136 ;
     RECT  18.904 41.376 19.139 42.024 ;
     RECT  18.904 6.816 19.325 13.128 ;
     RECT  19.325 6.816 19.331 12.552 ;
     RECT  19.331 6.912 19.397 12.552 ;
     RECT  18.904 44.88 19.427 47.352 ;
     RECT  19.427 44.88 19.469 46.248 ;
     RECT  19.429 50.688 19.513 50.712 ;
     RECT  18.904 14.4 19.897 14.424 ;
     RECT  19.073 48.624 19.897 49.56 ;
     RECT  19.427 47.28 19.937 47.352 ;
     RECT  19.897 13.824 19.969 14.424 ;
     RECT  18.904 15.456 19.969 17.592 ;
     RECT  19.469 44.88 20.005 45.864 ;
     RECT  19.397 6.912 20.081 7.416 ;
     RECT  19.897 48.384 20.257 49.56 ;
     RECT  19.937 47.28 20.473 47.304 ;
     RECT  20.005 44.4 20.545 45.864 ;
     RECT  19.969 13.824 20.549 17.592 ;
     RECT  20.257 48.384 20.581 50.136 ;
     RECT  19.397 8.496 20.761 12.552 ;
     RECT  20.581 48.384 20.837 50.184 ;
     RECT  20.545 44.4 20.869 46.056 ;
     RECT  20.473 47.232 20.869 47.304 ;
     RECT  18.904 3.936 20.909 3.96 ;
     RECT  20.549 15.36 20.945 17.592 ;
     RECT  20.081 7.104 21.071 7.416 ;
     RECT  20.761 8.4 21.071 12.552 ;
     RECT  20.837 48.384 21.125 49.56 ;
     RECT  21.071 7.104 21.251 12.552 ;
     RECT  21.125 48.432 21.349 49.56 ;
     RECT  20.549 13.824 21.701 13.992 ;
     RECT  20.945 15.36 21.701 17.496 ;
     RECT  20.869 44.4 21.989 47.304 ;
     RECT  21.877 50.688 22.205 50.712 ;
     RECT  21.251 7.104 22.213 9.096 ;
     RECT  21.251 10.128 22.213 12.552 ;
     RECT  21.349 49.008 22.241 49.56 ;
     RECT  21.989 45.648 22.277 47.304 ;
     RECT  21.701 15.456 22.345 17.496 ;
     RECT  22.241 49.008 22.349 49.032 ;
     RECT  21.701 13.968 22.705 13.992 ;
     RECT  22.345 15.456 22.741 17.592 ;
     RECT  22.741 15.312 22.787 17.592 ;
     RECT  22.277 45.744 23.245 47.304 ;
     RECT  22.705 13.968 23.317 14.184 ;
     RECT  23.101 48.864 23.317 48.888 ;
     RECT  23.317 13.872 23.533 14.184 ;
     RECT  23.245 45.696 23.605 47.304 ;
     RECT  23.461 51.696 23.681 51.72 ;
     RECT  23.533 13.584 23.785 14.184 ;
     RECT  22.787 15.312 23.785 17.496 ;
     RECT  23.317 48.864 23.857 49.56 ;
     RECT  18.904 1.728 24.008 1.752 ;
     RECT  22.213 7.104 24.008 12.552 ;
     RECT  23.785 13.584 24.008 17.496 ;
     RECT  18.965 38.784 24.008 38.808 ;
     RECT  19.139 41.904 24.008 42.024 ;
     RECT  21.989 44.4 24.008 44.424 ;
     RECT  23.605 45.696 24.008 47.88 ;
     RECT  23.857 48.864 24.008 49.848 ;
     RECT  14.76 0.096 24.181 0.12 ;
     RECT  24.008 1.728 24.304 49.848 ;
     RECT  24.181 0.096 24.365 0.552 ;
     RECT  24.304 14.784 24.419 17.736 ;
     RECT  24.304 44.4 24.481 47.304 ;
     RECT  24.304 7.104 24.509 13.704 ;
     RECT  24.304 49.536 24.509 49.848 ;
     RECT  24.509 13.68 24.563 13.704 ;
     RECT  24.419 14.784 24.581 14.856 ;
     RECT  24.325 51.648 24.613 51.672 ;
     RECT  24.481 44.4 25.013 47.16 ;
     RECT  24.581 14.784 25.049 14.808 ;
     RECT  24.613 50.64 25.049 51.672 ;
     RECT  24.304 25.92 25.091 25.944 ;
     RECT  24.304 38.688 25.139 38.808 ;
     RECT  24.509 7.104 25.157 12.552 ;
     RECT  24.419 16.032 25.229 17.736 ;
     RECT  25.139 38.688 25.333 38.712 ;
     RECT  25.049 50.736 25.333 51.672 ;
     RECT  25.292 25.968 25.379 25.992 ;
     RECT  25.333 38.4 25.379 38.712 ;
     RECT  25.333 50.736 25.523 51.72 ;
     RECT  24.509 49.536 25.58 49.608 ;
     RECT  25.58 49.344 25.585 49.608 ;
     RECT  25.157 7.104 25.769 12.312 ;
     RECT  25.013 47.136 25.841 47.16 ;
     RECT  25.523 51.648 26.129 51.72 ;
     RECT  25.229 16.272 26.237 17.736 ;
     RECT  25.585 48.48 26.341 49.608 ;
     RECT  26.341 47.904 26.381 49.608 ;
     RECT  25.769 7.104 26.741 9.096 ;
     RECT  26.381 47.904 26.741 49.032 ;
     RECT  26.129 51.696 26.741 51.72 ;
     RECT  25.769 10.08 26.777 12.312 ;
     RECT  26.237 16.272 26.849 16.536 ;
     RECT  25.013 44.4 27.097 46.056 ;
     RECT  26.773 50.688 27.241 50.712 ;
     RECT  24.365 0.096 27.349 0.12 ;
     RECT  26.741 48.48 27.353 49.032 ;
     RECT  27.349 0.096 27.433 0.6 ;
     RECT  27.353 48.672 27.493 49.032 ;
     RECT  27.241 50.16 27.493 50.712 ;
     RECT  27.433 0.096 27.721 0.12 ;
     RECT  27.097 44.4 28.105 46.104 ;
     RECT  24.304 1.728 28.289 1.752 ;
     RECT  27.493 48.672 28.357 50.712 ;
     RECT  28.105 44.4 28.393 46.152 ;
     RECT  28.393 44.4 28.573 46.92 ;
     RECT  28.357 48.672 28.973 51.672 ;
     RECT  26.741 7.104 29.408 8.184 ;
     RECT  26.777 10.128 29.408 12.312 ;
     RECT  26.849 16.272 29.408 16.392 ;
     RECT  26.237 17.712 29.408 17.736 ;
     RECT  25.379 38.4 29.408 38.424 ;
     RECT  24.304 41.904 29.408 42.024 ;
     RECT  29.005 43.296 29.408 43.32 ;
     RECT  28.573 44.4 29.408 47.352 ;
     RECT  28.973 48.672 29.408 50.136 ;
     RECT  28.973 51.504 29.411 51.672 ;
     RECT  29.408 2.148 29.501 50.136 ;
     RECT  29.501 1.728 29.704 50.136 ;
     RECT  29.411 51.504 29.939 51.624 ;
     RECT  29.704 47.904 29.953 50.136 ;
     RECT  29.704 44.4 29.981 46.92 ;
     RECT  29.939 51.504 30.044 51.528 ;
     RECT  29.953 47.904 30.125 49.56 ;
     RECT  30.044 50.688 30.131 51.528 ;
     RECT  29.704 16.272 30.773 16.392 ;
     RECT  30.131 50.688 30.889 50.712 ;
     RECT  29.981 44.4 30.949 46.248 ;
     RECT  30.125 48.672 31.021 49.56 ;
     RECT  30.949 44.4 31.1 46.344 ;
     RECT  31.1 44.4 31.273 46.776 ;
     RECT  31.021 48.672 31.381 49.608 ;
     RECT  30.949 51.696 31.637 51.72 ;
     RECT  31.273 44.4 31.669 47.112 ;
     RECT  31.381 48.672 31.669 50.136 ;
     RECT  31.669 44.064 31.859 50.136 ;
     RECT  31.859 48.672 32.06 50.136 ;
     RECT  32.06 48.672 32.146 50.184 ;
     RECT  32.146 48.672 32.291 50.232 ;
     RECT  32.291 48.672 32.465 49.56 ;
     RECT  31.859 44.064 32.969 47.304 ;
     RECT  32.969 44.064 33.041 46.824 ;
     RECT  32.465 48.672 33.109 49.512 ;
     RECT  33.109 47.904 33.196 49.512 ;
     RECT  33.041 44.064 33.221 46.056 ;
     RECT  33.221 44.064 33.505 44.424 ;
     RECT  33.221 45.552 33.581 46.056 ;
     RECT  33.196 48.672 33.613 49.512 ;
     RECT  33.253 50.688 33.613 50.712 ;
     RECT  33.505 43.536 33.653 44.424 ;
     RECT  33.613 48.672 33.731 50.712 ;
     RECT  33.731 50.688 33.901 50.712 ;
     RECT  33.901 50.688 34.019 50.76 ;
     RECT  33.581 45.6 34.153 46.056 ;
     RECT  34.019 50.688 34.409 50.712 ;
     RECT  33.731 48.672 34.604 49.56 ;
     RECT  29.704 38.4 34.613 38.424 ;
     RECT  34.153 45.6 34.621 46.968 ;
     RECT  34.604 48.624 34.645 49.56 ;
     RECT  33.653 44.064 34.765 44.424 ;
     RECT  34.621 45.504 34.765 46.968 ;
     RECT  34.645 48.192 34.765 49.56 ;
     RECT  29.704 1.728 34.808 1.752 ;
     RECT  29.704 7.104 34.808 8.184 ;
     RECT  29.704 10.128 34.808 12.312 ;
     RECT  30.773 16.272 34.808 16.296 ;
     RECT  29.704 17.712 34.808 17.736 ;
     RECT  34.613 38.4 34.808 38.76 ;
     RECT  29.704 41.904 34.808 42.024 ;
     RECT  34.765 44.064 34.808 46.968 ;
     RECT  34.765 48.192 34.808 50.136 ;
     RECT  29.797 0.096 34.981 0.12 ;
     RECT  34.808 1.728 35.104 50.136 ;
     RECT  34.981 0.096 35.165 0.552 ;
     RECT  35.125 51.648 35.267 51.672 ;
     RECT  35.104 43.824 35.315 47.16 ;
     RECT  35.104 50.112 35.413 50.136 ;
     RECT  35.315 43.824 35.489 46.728 ;
     RECT  35.489 43.824 35.597 46.056 ;
     RECT  35.413 50.112 36.425 50.712 ;
     RECT  35.597 44.064 36.517 46.056 ;
     RECT  36.425 50.112 36.796 50.184 ;
     RECT  35.104 48.192 36.925 49.08 ;
     RECT  36.517 44.064 36.997 46.392 ;
     RECT  36.997 44.064 37.069 46.536 ;
     RECT  36.925 48.096 37.861 49.08 ;
     RECT  36.796 50.112 37.861 50.136 ;
     RECT  37.861 48.096 37.973 50.136 ;
     RECT  35.104 10.128 38.189 12.312 ;
     RECT  38.189 12.24 38.225 12.312 ;
     RECT  38.225 12.288 38.297 12.312 ;
     RECT  37.069 44.064 38.405 47.016 ;
     RECT  38.405 44.064 38.725 46.296 ;
     RECT  38.725 43.536 38.801 46.296 ;
     RECT  38.801 43.536 38.837 46.152 ;
     RECT  37.973 48.096 39.005 49.608 ;
     RECT  38.293 50.688 39.005 50.712 ;
     RECT  39.005 48.096 39.121 50.712 ;
     RECT  39.121 47.952 39.161 50.712 ;
     RECT  39.161 48.96 39.701 50.712 ;
     RECT  39.725 51.696 39.809 51.72 ;
     RECT  35.165 0.096 39.869 0.12 ;
     RECT  38.837 44.016 39.877 46.152 ;
     RECT  39.869 0.096 39.953 0.6 ;
     RECT  39.877 43.872 39.973 46.152 ;
     RECT  39.877 51.504 40.019 51.672 ;
     RECT  35.104 1.728 40.208 1.752 ;
     RECT  35.104 7.104 40.208 8.184 ;
     RECT  38.189 10.128 40.208 11.256 ;
     RECT  35.104 16.272 40.208 16.296 ;
     RECT  35.104 17.712 40.208 17.736 ;
     RECT  35.104 41.904 40.208 42.024 ;
     RECT  39.973 43.872 40.208 46.824 ;
     RECT  39.161 47.952 40.208 47.976 ;
     RECT  39.701 48.96 40.208 50.184 ;
     RECT  40.208 1.728 40.493 50.184 ;
     RECT  40.493 1.728 40.504 49.56 ;
     RECT  40.019 51.504 40.739 51.624 ;
     RECT  40.504 49.008 40.853 49.56 ;
     RECT  40.504 45.552 41.321 46.776 ;
     RECT  41.029 50.688 41.357 50.712 ;
     RECT  40.504 47.952 41.569 47.976 ;
     RECT  40.853 49.344 41.609 49.56 ;
     RECT  41.609 49.392 41.749 49.56 ;
     RECT  41.749 49.392 41.933 50.184 ;
     RECT  41.569 47.856 42.041 47.976 ;
     RECT  41.321 46.032 42.149 46.776 ;
     RECT  40.504 17.712 42.361 17.736 ;
     RECT  42.149 46.032 42.433 46.248 ;
     RECT  42.428 39.264 42.469 39.288 ;
     RECT  42.469 39.264 42.515 39.912 ;
     RECT  42.515 39.888 42.533 39.912 ;
     RECT  40.504 41.904 42.565 42.024 ;
     RECT  42.533 29.664 42.617 29.688 ;
     RECT  42.533 39.888 42.617 40.44 ;
     RECT  40.504 7.104 42.649 8.184 ;
     RECT  42.041 47.952 42.649 47.976 ;
     RECT  41.933 49.392 42.649 49.56 ;
     RECT  42.565 28.464 42.652 28.488 ;
     RECT  42.572 14.4 42.659 14.424 ;
     RECT  42.361 17.712 42.659 18.264 ;
     RECT  42.433 45.744 42.761 46.248 ;
     RECT  40.504 10.704 42.793 11.208 ;
     RECT  42.649 47.952 42.833 49.56 ;
     RECT  42.833 47.952 42.869 48.936 ;
     RECT  42.793 10.176 42.977 11.208 ;
     RECT  42.869 47.952 43.009 47.976 ;
     RECT  42.577 26.208 43.153 26.232 ;
     RECT  40.504 44.064 43.189 44.424 ;
     RECT  42.617 39.888 43.193 40.152 ;
     RECT  43.009 47.28 43.235 47.976 ;
     RECT  39.953 0.096 43.333 0.12 ;
     RECT  43.333 0.096 43.417 0.6 ;
     RECT  42.565 41.712 43.513 42.024 ;
     RECT  42.977 10.704 43.585 11.208 ;
     RECT  42.577 12.192 43.585 12.216 ;
     RECT  43.585 10.704 43.625 12.216 ;
     RECT  40.504 16.272 43.657 16.296 ;
     RECT  42.659 17.712 43.657 17.736 ;
     RECT  42.577 22.752 43.657 22.776 ;
     RECT  42.577 24.48 43.657 24.504 ;
     RECT  43.657 16.272 43.669 17.736 ;
     RECT  43.657 22.752 43.697 24.504 ;
     RECT  43.153 26.016 43.697 26.232 ;
     RECT  42.761 46.032 43.697 46.248 ;
     RECT  43.585 36.864 43.837 36.888 ;
     RECT  43.193 40.128 43.837 40.152 ;
     RECT  43.513 41.136 43.837 42.024 ;
     RECT  42.577 33.408 43.841 33.432 ;
     RECT  43.837 40.128 43.913 42.024 ;
     RECT  43.333 35.136 44.093 35.16 ;
     RECT  43.235 47.28 44.129 47.592 ;
     RECT  43.837 36.48 44.629 36.888 ;
     RECT  43.669 16.272 44.701 18.264 ;
     RECT  44.701 16.272 44.732 18.312 ;
     RECT  43.625 10.704 44.773 11.976 ;
     RECT  44.732 16.224 44.773 18.312 ;
     RECT  44.773 16.224 44.845 18.84 ;
     RECT  43.189 44.064 44.845 44.904 ;
     RECT  43.697 46.032 44.845 46.056 ;
     RECT  44.845 15.504 44.869 18.84 ;
     RECT  43.657 20.16 44.869 20.184 ;
     RECT  43.697 23.52 44.881 23.544 ;
     RECT  44.773 10.08 44.917 11.976 ;
     RECT  43.913 41.904 44.917 42.024 ;
     RECT  44.845 44.064 44.953 46.056 ;
     RECT  44.557 27.312 45.097 27.336 ;
     RECT  43.913 40.128 45.097 40.92 ;
     RECT  44.917 41.904 45.097 42.504 ;
     RECT  45.097 40.128 45.133 42.504 ;
     RECT  43.697 26.016 45.241 26.04 ;
     RECT  45.097 27.312 45.241 27.96 ;
     RECT  45.133 39.216 45.277 42.504 ;
     RECT  42.649 6.816 45.385 8.184 ;
     RECT  44.869 15.504 45.457 20.184 ;
     RECT  44.629 35.232 45.457 36.888 ;
     RECT  44.917 10.08 45.529 12.552 ;
     RECT  40.504 1.728 45.608 1.752 ;
     RECT  45.385 6.624 45.608 8.184 ;
     RECT  45.529 9.312 45.608 12.552 ;
     RECT  44.017 14.208 45.608 14.232 ;
     RECT  45.457 15.456 45.608 20.184 ;
     RECT  45.565 21.504 45.608 21.528 ;
     RECT  44.881 22.752 45.608 23.544 ;
     RECT  45.241 26.016 45.608 27.96 ;
     RECT  43.657 30.24 45.608 30.264 ;
     RECT  43.657 31.68 45.608 31.704 ;
     RECT  45.457 34.656 45.608 36.888 ;
     RECT  43.837 38.16 45.608 38.184 ;
     RECT  45.277 39.216 45.608 42.552 ;
     RECT  44.953 44.064 45.608 46.104 ;
     RECT  45.608 1.728 45.712 49.692 ;
     RECT  43.417 0.096 45.781 0.12 ;
     RECT  45.712 1.728 45.904 49.422 ;
     RECT  45.781 0.096 45.965 0.552 ;
     RECT  45.904 27.936 46.001 28.44 ;
     RECT  45.904 25.056 46.115 26.904 ;
     RECT  45.904 32.304 46.115 32.328 ;
     RECT  45.904 16.512 46.145 19.128 ;
     RECT  45.904 44.064 46.145 46.104 ;
     RECT  45.904 21.504 46.211 22.968 ;
     RECT  46.145 18.816 46.217 19.128 ;
     RECT  46.211 21.504 46.217 22.248 ;
     RECT  45.904 34.176 46.217 37.032 ;
     RECT  46.217 19.104 46.259 19.128 ;
     RECT  46.217 21.648 46.289 22.248 ;
     RECT  45.904 6.672 46.361 13.224 ;
     RECT  46.145 44.16 46.361 46.104 ;
     RECT  45.904 39.216 46.397 42.552 ;
     RECT  46.361 44.448 46.499 46.104 ;
     RECT  46.361 6.672 46.505 10.728 ;
     RECT  46.361 11.904 46.613 13.224 ;
     RECT  46.289 21.648 46.649 22.152 ;
     RECT  46.397 39.216 46.649 39.24 ;
     RECT  45.904 15.36 46.685 15.528 ;
     RECT  46.685 15.36 46.721 15.384 ;
     RECT  46.397 40.8 46.721 42.552 ;
     RECT  46.505 10.656 46.793 10.728 ;
     RECT  46.505 6.672 46.901 9.336 ;
     RECT  46.892 14.88 46.933 14.904 ;
     RECT  46.933 14.208 46.979 14.904 ;
     RECT  46.613 11.904 47.045 13.128 ;
     RECT  46.217 34.176 47.18 34.68 ;
     RECT  46.217 35.664 47.18 37.032 ;
     RECT  46.145 16.512 47.185 17.832 ;
     RECT  46.721 40.8 47.225 42.312 ;
     RECT  46.901 6.672 47.261 8.424 ;
     RECT  47.18 34.176 47.267 37.032 ;
     RECT  47.185 16.512 47.333 18.264 ;
     RECT  47.267 35.664 47.333 37.032 ;
     RECT  47.333 16.8 47.363 18.264 ;
     RECT  47.333 35.664 47.369 36.888 ;
     RECT  47.369 35.952 47.441 36.888 ;
     RECT  47.401 30.24 47.461 30.264 ;
     RECT  46.001 28.416 47.507 28.44 ;
     RECT  46.793 10.704 47.509 10.728 ;
     RECT  47.261 6.672 47.513 8.328 ;
     RECT  47.045 12.24 47.513 13.128 ;
     RECT  46.115 25.056 47.513 25.08 ;
     RECT  47.225 40.8 47.513 42.168 ;
     RECT  46.499 44.448 47.513 44.472 ;
     RECT  47.461 29.472 47.548 30.312 ;
     RECT  47.267 34.176 47.549 34.2 ;
     RECT  46.649 21.648 47.621 21.672 ;
     RECT  45.965 0.096 47.701 0.12 ;
     RECT  46.979 14.208 47.801 14.232 ;
     RECT  47.548 30.24 47.837 30.264 ;
     RECT  47.513 12.24 47.873 12.936 ;
     RECT  45.904 1.728 47.881 1.752 ;
     RECT  47.873 12.912 47.981 12.936 ;
     RECT  47.509 10.704 48.053 10.824 ;
     RECT  47.437 47.856 48.121 47.88 ;
     RECT  48.037 43.488 48.124 43.512 ;
     RECT  47.513 6.672 48.125 7.464 ;
     RECT  47.363 17.088 48.161 18.024 ;
     RECT  48.013 39.888 48.421 39.912 ;
     RECT  48.421 39.312 48.467 39.912 ;
     RECT  47.513 40.896 48.485 42.168 ;
     RECT  48.161 17.136 48.557 18.024 ;
     RECT  48.467 39.312 48.593 39.336 ;
     RECT  46.115 26.352 48.845 26.904 ;
     RECT  48.053 10.704 49.025 10.728 ;
     RECT  48.121 47.856 49.057 48.12 ;
     RECT  49.273 12.24 49.489 12.984 ;
     RECT  49.273 15.12 49.489 15.144 ;
     RECT  49.345 24.336 49.489 24.36 ;
     RECT  49.273 33.84 49.489 33.864 ;
     RECT  48.485 40.896 49.489 42.072 ;
     RECT  46.499 45.504 49.489 46.104 ;
     RECT  49.381 19.152 49.525 19.176 ;
     RECT  49.489 32.688 49.525 33.864 ;
     RECT  48.557 17.136 49.561 17.736 ;
     RECT  49.489 21.744 49.561 21.768 ;
     RECT  49.489 43.92 49.561 43.944 ;
     RECT  49.489 45.504 49.561 46.248 ;
     RECT  49.057 47.232 49.561 48.12 ;
     RECT  48.125 6.672 49.597 6.696 ;
     RECT  49.489 8.784 49.597 8.808 ;
     RECT  49.489 24.336 49.597 24.648 ;
     RECT  47.441 36.864 49.597 36.888 ;
     RECT  49.561 45.504 49.597 48.12 ;
     RECT  49.561 20.592 49.633 22.344 ;
     RECT  49.597 5.904 49.669 8.808 ;
     RECT  49.597 11.088 49.705 11.112 ;
     RECT  49.489 12.24 49.705 13.128 ;
     RECT  49.633 20.592 49.705 22.776 ;
     RECT  49.669 5.328 49.741 8.808 ;
     RECT  49.561 30.816 49.741 30.84 ;
     RECT  49.525 32.112 49.741 33.864 ;
     RECT  49.561 43.92 49.741 44.232 ;
     RECT  49.597 45.504 49.741 48.408 ;
     RECT  49.597 36.576 49.813 36.888 ;
     RECT  49.705 11.088 50.065 13.128 ;
     RECT  49.597 14.112 50.065 14.136 ;
     RECT  49.489 15.12 50.065 15.432 ;
     RECT  49.561 16.56 50.065 17.736 ;
     RECT  49.525 19.152 50.065 19.464 ;
     RECT  49.705 20.592 50.065 22.92 ;
     RECT  49.597 24.048 50.065 24.936 ;
     RECT  49.741 30.816 50.065 33.864 ;
     RECT  49.489 40.176 50.065 42.072 ;
     RECT  49.741 43.92 50.065 48.408 ;
     RECT  49.741 5.328 50.137 9.096 ;
     RECT  50.065 11.088 50.137 17.736 ;
     RECT  50.065 19.152 50.137 24.936 ;
     RECT  48.845 26.352 50.137 26.376 ;
     RECT  49.489 28.08 50.137 28.104 ;
     RECT  50.065 30.24 50.137 33.864 ;
     RECT  49.813 35.856 50.137 36.888 ;
     RECT  50.065 39.312 50.137 42.072 ;
     RECT  50.137 5.328 50.173 17.736 ;
     RECT  50.137 19.152 50.173 28.104 ;
     RECT  50.137 39.312 50.173 42.216 ;
     RECT  50.065 43.632 50.173 48.408 ;
     RECT  50.173 38.88 50.677 48.408 ;
     RECT  50.137 29.52 50.713 37.608 ;
     RECT  50.677 38.736 50.713 48.552 ;
     RECT  50.173 5.328 51.721 28.104 ;
     RECT  51.721 5.328 51.756 5.352 ;
     RECT  51.721 5.352 51.804 5.472 ;
     RECT  51.721 5.472 51.756 5.496 ;
     RECT  51.721 5.496 51.804 5.616 ;
     RECT  51.721 5.616 51.756 5.64 ;
     RECT  51.721 5.64 51.804 5.76 ;
     RECT  51.721 5.76 51.756 5.784 ;
     RECT  51.721 5.784 51.804 5.904 ;
     RECT  51.721 5.904 51.756 5.928 ;
     RECT  51.721 5.928 51.804 6.048 ;
     RECT  51.721 6.048 51.756 6.072 ;
     RECT  51.721 6.072 51.804 6.192 ;
     RECT  51.721 6.192 51.756 6.216 ;
     RECT  51.721 6.216 51.804 6.336 ;
     RECT  51.721 6.336 51.756 6.36 ;
     RECT  51.721 6.36 51.804 6.48 ;
     RECT  51.721 6.48 51.756 6.504 ;
     RECT  51.721 6.504 51.804 6.624 ;
     RECT  51.721 6.624 51.756 6.648 ;
     RECT  51.721 6.648 51.804 6.768 ;
     RECT  51.721 6.768 51.756 6.792 ;
     RECT  51.721 6.792 51.804 6.912 ;
     RECT  51.721 6.912 51.756 6.936 ;
     RECT  51.721 6.936 51.804 7.056 ;
     RECT  51.721 7.056 51.756 7.08 ;
     RECT  51.721 7.08 51.804 7.2 ;
     RECT  51.721 7.2 51.756 7.224 ;
     RECT  51.721 7.224 51.804 7.344 ;
     RECT  51.721 7.344 51.756 7.368 ;
     RECT  51.721 7.368 51.804 7.488 ;
     RECT  51.721 7.488 51.756 7.512 ;
     RECT  51.721 7.512 51.804 7.632 ;
     RECT  51.721 7.632 51.756 7.656 ;
     RECT  51.721 7.656 51.804 7.776 ;
     RECT  51.721 7.776 51.756 7.8 ;
     RECT  51.721 7.8 51.804 7.92 ;
     RECT  51.721 7.92 51.756 7.944 ;
     RECT  51.721 7.944 51.804 8.064 ;
     RECT  51.721 8.064 51.756 8.088 ;
     RECT  51.721 8.088 51.804 8.208 ;
     RECT  51.721 8.208 51.756 8.232 ;
     RECT  51.721 8.232 51.804 8.352 ;
     RECT  51.721 8.352 51.756 8.376 ;
     RECT  51.721 8.376 51.804 8.496 ;
     RECT  51.721 8.496 51.756 8.52 ;
     RECT  51.721 8.52 51.804 8.64 ;
     RECT  51.721 8.64 51.756 8.664 ;
     RECT  51.721 8.664 51.804 8.784 ;
     RECT  51.721 8.784 51.756 8.808 ;
     RECT  51.721 8.808 51.804 8.928 ;
     RECT  51.721 8.928 51.756 8.952 ;
     RECT  51.721 8.952 51.804 9.072 ;
     RECT  51.721 9.072 51.756 9.096 ;
     RECT  51.721 9.096 51.804 9.216 ;
     RECT  51.721 9.216 51.756 9.24 ;
     RECT  51.721 9.24 51.804 9.36 ;
     RECT  51.721 9.36 51.756 9.384 ;
     RECT  51.721 9.384 51.804 9.504 ;
     RECT  51.721 9.504 51.756 9.528 ;
     RECT  51.721 9.528 51.804 9.648 ;
     RECT  51.721 9.648 51.756 9.672 ;
     RECT  51.721 9.672 51.804 9.792 ;
     RECT  51.721 9.792 51.756 9.816 ;
     RECT  51.721 9.816 51.804 9.936 ;
     RECT  51.721 9.936 51.756 9.96 ;
     RECT  51.721 9.96 51.804 10.08 ;
     RECT  51.721 10.08 51.756 10.104 ;
     RECT  51.721 10.104 51.804 10.224 ;
     RECT  51.721 10.224 51.756 10.248 ;
     RECT  51.721 10.248 51.804 10.368 ;
     RECT  51.721 10.368 51.756 10.392 ;
     RECT  51.721 10.392 51.804 10.512 ;
     RECT  51.721 10.512 51.756 10.536 ;
     RECT  51.721 10.536 51.804 10.656 ;
     RECT  51.721 10.656 51.756 10.68 ;
     RECT  51.721 10.68 51.804 10.8 ;
     RECT  51.721 10.8 51.756 10.824 ;
     RECT  51.721 10.824 51.804 10.944 ;
     RECT  51.721 10.944 51.756 10.968 ;
     RECT  51.721 10.968 51.804 11.088 ;
     RECT  51.721 11.088 51.756 11.112 ;
     RECT  51.721 11.112 51.804 11.232 ;
     RECT  51.721 11.232 51.756 11.256 ;
     RECT  51.721 11.256 51.804 11.376 ;
     RECT  51.721 11.376 51.756 11.4 ;
     RECT  51.721 11.4 51.804 11.52 ;
     RECT  51.721 11.52 51.756 11.544 ;
     RECT  51.721 11.544 51.804 11.664 ;
     RECT  51.721 11.664 51.756 11.688 ;
     RECT  51.721 11.688 51.804 11.808 ;
     RECT  51.721 11.808 51.756 11.832 ;
     RECT  51.721 11.832 51.804 11.952 ;
     RECT  51.721 11.952 51.756 11.976 ;
     RECT  51.721 11.976 51.804 12.096 ;
     RECT  51.721 12.096 51.756 12.12 ;
     RECT  51.721 12.12 51.804 12.24 ;
     RECT  51.721 12.24 51.756 12.264 ;
     RECT  51.721 12.264 51.804 12.384 ;
     RECT  51.721 12.384 51.756 12.408 ;
     RECT  51.721 12.408 51.804 12.528 ;
     RECT  51.721 12.528 51.756 12.552 ;
     RECT  51.721 12.552 51.804 12.672 ;
     RECT  51.721 12.672 51.756 12.696 ;
     RECT  51.721 12.696 51.804 12.816 ;
     RECT  51.721 12.816 51.756 12.84 ;
     RECT  51.721 12.84 51.804 12.96 ;
     RECT  51.721 12.96 51.756 12.984 ;
     RECT  51.721 12.984 51.804 13.104 ;
     RECT  51.721 13.104 51.756 13.128 ;
     RECT  51.721 13.128 51.804 13.248 ;
     RECT  51.721 13.248 51.756 13.272 ;
     RECT  51.721 13.272 51.804 13.392 ;
     RECT  51.721 13.392 51.756 13.416 ;
     RECT  51.721 13.416 51.804 13.536 ;
     RECT  51.721 13.536 51.756 13.56 ;
     RECT  51.721 13.56 51.804 13.68 ;
     RECT  51.721 13.68 51.756 13.704 ;
     RECT  51.721 13.704 51.804 13.824 ;
     RECT  51.721 13.824 51.756 13.848 ;
     RECT  51.721 13.848 51.804 13.968 ;
     RECT  51.721 13.968 51.756 13.992 ;
     RECT  51.721 13.992 51.804 14.112 ;
     RECT  51.721 14.112 51.756 14.136 ;
     RECT  51.721 14.136 51.804 14.256 ;
     RECT  51.721 14.256 51.756 14.28 ;
     RECT  51.721 14.28 51.804 14.4 ;
     RECT  51.721 14.4 51.756 14.424 ;
     RECT  51.721 14.424 51.804 14.544 ;
     RECT  51.721 14.544 51.756 14.568 ;
     RECT  51.721 14.568 51.804 14.688 ;
     RECT  51.721 14.688 51.756 14.712 ;
     RECT  51.721 14.712 51.804 14.832 ;
     RECT  51.721 14.832 51.756 14.856 ;
     RECT  51.721 14.856 51.804 14.976 ;
     RECT  51.721 14.976 51.756 15 ;
     RECT  51.721 15 51.804 15.12 ;
     RECT  51.721 15.12 51.756 15.144 ;
     RECT  51.721 15.144 51.804 15.264 ;
     RECT  51.721 15.264 51.756 15.288 ;
     RECT  51.721 15.288 51.804 15.408 ;
     RECT  51.721 15.408 51.756 15.432 ;
     RECT  51.721 15.432 51.804 15.552 ;
     RECT  51.721 15.552 51.756 15.576 ;
     RECT  51.721 15.576 51.804 15.696 ;
     RECT  51.721 15.696 51.756 15.72 ;
     RECT  51.721 15.72 51.804 15.84 ;
     RECT  51.721 15.84 51.756 15.864 ;
     RECT  51.721 15.864 51.804 15.984 ;
     RECT  51.721 15.984 51.756 16.008 ;
     RECT  51.721 16.008 51.804 16.128 ;
     RECT  51.721 16.128 51.756 16.152 ;
     RECT  51.721 16.152 51.804 16.272 ;
     RECT  51.721 16.272 51.756 16.296 ;
     RECT  51.721 16.296 51.804 16.416 ;
     RECT  51.721 16.416 51.756 16.44 ;
     RECT  51.721 16.44 51.804 16.56 ;
     RECT  51.721 16.56 51.756 16.584 ;
     RECT  51.721 16.584 51.804 16.704 ;
     RECT  51.721 16.704 51.756 16.728 ;
     RECT  51.721 16.728 51.804 16.848 ;
     RECT  51.721 16.848 51.756 16.872 ;
     RECT  51.721 16.872 51.804 16.992 ;
     RECT  51.721 16.992 51.756 17.016 ;
     RECT  51.721 17.016 51.804 17.136 ;
     RECT  51.721 17.136 51.756 17.16 ;
     RECT  51.721 17.16 51.804 17.28 ;
     RECT  51.721 17.28 51.756 17.304 ;
     RECT  51.721 17.304 51.804 17.424 ;
     RECT  51.721 17.424 51.756 17.448 ;
     RECT  51.721 17.448 51.804 17.568 ;
     RECT  51.721 17.568 51.756 17.592 ;
     RECT  51.721 17.592 51.804 17.712 ;
     RECT  51.721 17.712 51.756 17.736 ;
     RECT  51.721 17.736 51.804 17.856 ;
     RECT  51.721 17.856 51.756 17.88 ;
     RECT  51.721 17.88 51.804 18 ;
     RECT  51.721 18 51.756 18.024 ;
     RECT  51.721 18.024 51.804 18.144 ;
     RECT  51.721 18.144 51.756 18.168 ;
     RECT  51.721 18.168 51.804 18.288 ;
     RECT  51.721 18.288 51.756 18.312 ;
     RECT  51.721 18.312 51.804 18.432 ;
     RECT  51.721 18.432 51.756 18.456 ;
     RECT  51.721 18.456 51.804 18.576 ;
     RECT  51.721 18.576 51.756 18.6 ;
     RECT  51.721 18.6 51.804 18.72 ;
     RECT  51.721 18.72 51.756 18.744 ;
     RECT  51.721 18.744 51.804 18.864 ;
     RECT  51.721 18.864 51.756 18.888 ;
     RECT  51.721 18.888 51.804 19.008 ;
     RECT  51.721 19.008 51.756 19.032 ;
     RECT  51.721 19.032 51.804 19.152 ;
     RECT  51.721 19.152 51.756 19.176 ;
     RECT  51.721 19.176 51.804 19.296 ;
     RECT  51.721 19.296 51.756 19.32 ;
     RECT  51.721 19.32 51.804 19.44 ;
     RECT  51.721 19.44 51.756 19.464 ;
     RECT  51.721 19.464 51.804 19.584 ;
     RECT  51.721 19.584 51.756 19.608 ;
     RECT  51.721 19.608 51.804 19.728 ;
     RECT  51.721 19.728 51.756 19.752 ;
     RECT  51.721 19.752 51.804 19.872 ;
     RECT  51.721 19.872 51.756 19.896 ;
     RECT  51.721 19.896 51.804 20.016 ;
     RECT  51.721 20.016 51.756 20.04 ;
     RECT  51.721 20.04 51.804 20.16 ;
     RECT  51.721 20.16 51.756 20.184 ;
     RECT  51.721 20.184 51.804 20.304 ;
     RECT  51.721 20.304 51.756 20.328 ;
     RECT  51.721 20.328 51.804 20.448 ;
     RECT  51.721 20.448 51.756 20.472 ;
     RECT  51.721 20.472 51.804 20.592 ;
     RECT  51.721 20.592 51.756 20.616 ;
     RECT  51.721 20.616 51.804 20.736 ;
     RECT  51.721 20.736 51.756 20.76 ;
     RECT  51.721 20.76 51.804 20.88 ;
     RECT  51.721 20.88 51.756 20.904 ;
     RECT  51.721 20.904 51.804 21.024 ;
     RECT  51.721 21.024 51.756 21.048 ;
     RECT  51.721 21.048 51.804 21.168 ;
     RECT  51.721 21.168 51.756 21.192 ;
     RECT  51.721 21.192 51.804 21.312 ;
     RECT  51.721 21.312 51.756 21.336 ;
     RECT  51.721 21.336 51.804 21.456 ;
     RECT  51.721 21.456 51.756 21.48 ;
     RECT  51.721 21.48 51.804 21.6 ;
     RECT  51.721 21.6 51.756 21.624 ;
     RECT  51.721 21.624 51.804 21.744 ;
     RECT  51.721 21.744 51.756 21.768 ;
     RECT  51.721 21.768 51.804 21.888 ;
     RECT  51.721 21.888 51.756 21.912 ;
     RECT  51.721 21.912 51.804 22.032 ;
     RECT  51.721 22.032 51.756 22.056 ;
     RECT  51.721 22.056 51.804 22.176 ;
     RECT  51.721 22.176 51.756 22.2 ;
     RECT  51.721 22.2 51.804 22.32 ;
     RECT  51.721 22.32 51.756 22.344 ;
     RECT  51.721 22.344 51.804 22.464 ;
     RECT  51.721 22.464 51.756 22.488 ;
     RECT  51.721 22.488 51.804 22.608 ;
     RECT  51.721 22.608 51.756 22.632 ;
     RECT  51.721 22.632 51.804 22.752 ;
     RECT  51.721 22.752 51.756 22.776 ;
     RECT  51.721 22.776 51.804 22.896 ;
     RECT  51.721 22.896 51.756 22.92 ;
     RECT  51.721 22.92 51.804 23.04 ;
     RECT  51.721 23.04 51.756 23.064 ;
     RECT  51.721 23.064 51.804 23.184 ;
     RECT  51.721 23.184 51.756 23.208 ;
     RECT  51.721 23.208 51.804 23.328 ;
     RECT  51.721 23.328 51.756 23.352 ;
     RECT  51.721 23.352 51.804 23.472 ;
     RECT  51.721 23.472 51.756 23.496 ;
     RECT  51.721 23.496 51.804 23.616 ;
     RECT  51.721 23.616 51.756 23.64 ;
     RECT  51.721 23.64 51.804 23.76 ;
     RECT  51.721 23.76 51.756 23.784 ;
     RECT  51.721 23.784 51.804 23.904 ;
     RECT  51.721 23.904 51.756 23.928 ;
     RECT  51.721 23.928 51.804 24.048 ;
     RECT  51.721 24.048 51.756 24.072 ;
     RECT  51.721 24.072 51.804 24.192 ;
     RECT  51.721 24.192 51.756 24.216 ;
     RECT  51.721 24.216 51.804 24.336 ;
     RECT  51.721 24.336 51.756 24.36 ;
     RECT  51.721 24.36 51.804 24.48 ;
     RECT  51.721 24.48 51.756 24.504 ;
     RECT  51.721 24.504 51.804 24.624 ;
     RECT  51.721 24.624 51.756 24.648 ;
     RECT  51.721 24.648 51.804 24.768 ;
     RECT  51.721 24.768 51.756 24.792 ;
     RECT  51.721 24.792 51.804 24.912 ;
     RECT  51.721 24.912 51.756 24.936 ;
     RECT  51.721 24.936 51.804 25.056 ;
     RECT  51.721 25.056 51.756 25.08 ;
     RECT  51.721 25.08 51.804 25.2 ;
     RECT  51.721 25.2 51.756 25.224 ;
     RECT  51.721 25.224 51.804 25.344 ;
     RECT  51.721 25.344 51.756 25.368 ;
     RECT  51.721 25.368 51.804 25.488 ;
     RECT  51.721 25.488 51.756 25.512 ;
     RECT  51.721 25.512 51.804 25.632 ;
     RECT  51.721 25.632 51.756 25.656 ;
     RECT  51.721 25.656 51.804 25.776 ;
     RECT  51.721 25.776 51.756 25.8 ;
     RECT  51.721 25.8 51.804 25.92 ;
     RECT  51.721 25.92 51.756 25.944 ;
     RECT  51.721 25.944 51.804 26.064 ;
     RECT  51.721 26.064 51.756 26.088 ;
     RECT  51.721 26.088 51.804 26.208 ;
     RECT  51.721 26.208 51.756 26.232 ;
     RECT  51.721 26.232 51.804 26.352 ;
     RECT  51.721 26.352 51.756 26.376 ;
     RECT  51.721 26.376 51.804 26.496 ;
     RECT  51.721 26.496 51.756 26.52 ;
     RECT  51.721 26.52 51.804 26.64 ;
     RECT  51.721 26.64 51.756 26.664 ;
     RECT  51.721 26.664 51.804 26.784 ;
     RECT  51.721 26.784 51.756 26.808 ;
     RECT  51.721 26.808 51.804 26.928 ;
     RECT  51.721 26.928 51.756 26.952 ;
     RECT  51.721 26.952 51.804 27.072 ;
     RECT  51.721 27.072 51.756 27.096 ;
     RECT  51.721 27.096 51.804 27.216 ;
     RECT  51.721 27.216 51.756 27.24 ;
     RECT  51.721 27.24 51.804 27.36 ;
     RECT  51.721 27.36 51.756 27.384 ;
     RECT  51.721 27.384 51.804 27.504 ;
     RECT  51.721 27.504 51.756 27.528 ;
     RECT  51.721 27.528 51.804 27.648 ;
     RECT  51.721 27.648 51.756 27.672 ;
     RECT  51.721 27.672 51.804 27.792 ;
     RECT  51.721 27.792 51.756 27.816 ;
     RECT  51.721 27.816 51.804 27.936 ;
     RECT  51.721 27.936 51.756 27.96 ;
     RECT  51.721 27.96 51.804 28.08 ;
     RECT  51.721 28.08 51.756 28.104 ;
     RECT  51.721 28.104 51.804 28.224 ;
     RECT  51.721 28.224 51.756 28.248 ;
     RECT  50.713 29.52 51.756 29.544 ;
     RECT  50.713 29.544 51.804 29.664 ;
     RECT  50.713 29.664 51.756 29.688 ;
     RECT  50.713 29.688 51.804 29.808 ;
     RECT  50.713 29.808 51.756 29.832 ;
     RECT  50.713 29.832 51.804 29.952 ;
     RECT  50.713 29.952 51.756 29.976 ;
     RECT  50.713 29.976 51.804 30.096 ;
     RECT  50.713 30.096 51.756 30.12 ;
     RECT  50.713 30.12 51.804 30.24 ;
     RECT  50.713 30.24 51.756 30.264 ;
     RECT  50.713 30.264 51.804 30.384 ;
     RECT  50.713 30.384 51.756 30.408 ;
     RECT  50.713 30.408 51.804 30.528 ;
     RECT  50.713 30.528 51.756 30.552 ;
     RECT  50.713 30.552 51.804 30.672 ;
     RECT  50.713 30.672 51.756 30.696 ;
     RECT  50.713 30.696 51.804 30.816 ;
     RECT  50.713 30.816 51.756 30.84 ;
     RECT  50.713 30.84 51.804 30.96 ;
     RECT  50.713 30.96 51.756 30.984 ;
     RECT  50.713 30.984 51.804 31.104 ;
     RECT  50.713 31.104 51.756 31.128 ;
     RECT  50.713 31.128 51.804 31.248 ;
     RECT  50.713 31.248 51.756 31.272 ;
     RECT  50.713 31.272 51.804 31.392 ;
     RECT  50.713 31.392 51.756 31.416 ;
     RECT  50.713 31.416 51.804 31.536 ;
     RECT  50.713 31.536 51.756 31.56 ;
     RECT  50.713 31.56 51.804 31.68 ;
     RECT  50.713 31.68 51.756 31.704 ;
     RECT  50.713 31.704 51.804 31.824 ;
     RECT  50.713 31.824 51.756 31.848 ;
     RECT  50.713 31.848 51.804 31.968 ;
     RECT  50.713 31.968 51.756 31.992 ;
     RECT  50.713 31.992 51.804 32.112 ;
     RECT  50.713 32.112 51.756 32.136 ;
     RECT  50.713 32.136 51.804 32.256 ;
     RECT  50.713 32.256 51.756 32.28 ;
     RECT  50.713 32.28 51.804 32.4 ;
     RECT  50.713 32.4 51.756 32.424 ;
     RECT  50.713 32.424 51.804 32.544 ;
     RECT  50.713 32.544 51.756 32.568 ;
     RECT  50.713 32.568 51.804 32.688 ;
     RECT  50.713 32.688 51.756 32.712 ;
     RECT  50.713 32.712 51.804 32.832 ;
     RECT  50.713 32.832 51.756 32.856 ;
     RECT  50.713 32.856 51.804 32.976 ;
     RECT  50.713 32.976 51.756 33 ;
     RECT  50.713 33 51.804 33.12 ;
     RECT  50.713 33.12 51.756 33.144 ;
     RECT  50.713 33.144 51.804 33.264 ;
     RECT  50.713 33.264 51.756 33.288 ;
     RECT  50.713 33.288 51.804 33.408 ;
     RECT  50.713 33.408 51.756 33.432 ;
     RECT  50.713 33.432 51.804 33.552 ;
     RECT  50.713 33.552 51.756 33.576 ;
     RECT  50.713 33.576 51.804 33.696 ;
     RECT  50.713 33.696 51.756 33.72 ;
     RECT  50.713 33.72 51.804 33.84 ;
     RECT  50.713 33.84 51.756 33.864 ;
     RECT  50.713 33.864 51.804 33.984 ;
     RECT  50.713 33.984 51.756 34.008 ;
     RECT  50.713 34.008 51.804 34.128 ;
     RECT  50.713 34.128 51.756 34.152 ;
     RECT  50.713 34.152 51.804 34.272 ;
     RECT  50.713 34.272 51.756 34.296 ;
     RECT  50.713 34.296 51.804 34.416 ;
     RECT  50.713 34.416 51.756 34.44 ;
     RECT  50.713 34.44 51.804 34.56 ;
     RECT  50.713 34.56 51.756 34.584 ;
     RECT  50.713 34.584 51.804 34.704 ;
     RECT  50.713 34.704 51.756 34.728 ;
     RECT  50.713 34.728 51.804 34.848 ;
     RECT  50.713 34.848 51.756 34.872 ;
     RECT  50.713 34.872 51.804 34.992 ;
     RECT  50.713 34.992 51.756 35.016 ;
     RECT  50.713 35.016 51.804 35.136 ;
     RECT  50.713 35.136 51.756 35.16 ;
     RECT  50.713 35.16 51.804 35.28 ;
     RECT  50.713 35.28 51.756 35.304 ;
     RECT  50.713 35.304 51.804 35.424 ;
     RECT  50.713 35.424 51.756 35.448 ;
     RECT  50.713 35.448 51.804 35.568 ;
     RECT  50.713 35.568 51.756 35.592 ;
     RECT  50.713 35.592 51.804 35.712 ;
     RECT  50.713 35.712 51.756 35.736 ;
     RECT  50.713 35.736 51.804 35.856 ;
     RECT  50.713 35.856 51.756 35.88 ;
     RECT  50.713 35.88 51.804 36 ;
     RECT  50.713 36 51.756 36.024 ;
     RECT  50.713 36.024 51.804 36.144 ;
     RECT  50.713 36.144 51.756 36.168 ;
     RECT  50.713 36.168 51.804 36.288 ;
     RECT  50.713 36.288 51.756 36.312 ;
     RECT  50.713 36.312 51.804 36.432 ;
     RECT  50.713 36.432 51.756 36.456 ;
     RECT  50.713 36.456 51.804 36.576 ;
     RECT  50.713 36.576 51.756 36.6 ;
     RECT  50.713 36.6 51.804 36.72 ;
     RECT  50.713 36.72 51.756 36.744 ;
     RECT  50.713 36.744 51.804 36.864 ;
     RECT  50.713 36.864 51.756 36.888 ;
     RECT  50.713 36.888 51.804 37.008 ;
     RECT  50.713 37.008 51.756 37.032 ;
     RECT  50.713 37.032 51.804 37.152 ;
     RECT  50.713 37.152 51.756 37.176 ;
     RECT  50.713 37.176 51.804 37.296 ;
     RECT  50.713 37.296 51.756 37.32 ;
     RECT  50.713 37.32 51.804 37.44 ;
     RECT  50.713 37.44 51.756 37.464 ;
     RECT  50.713 37.464 51.804 37.584 ;
     RECT  50.713 37.584 51.756 37.608 ;
     RECT  50.713 37.608 51.804 37.728 ;
     RECT  50.713 37.728 51.756 37.752 ;
     RECT  50.713 37.752 51.804 37.872 ;
     RECT  50.713 37.872 51.756 37.896 ;
     RECT  50.713 37.896 51.804 38.016 ;
     RECT  50.713 38.016 51.756 38.04 ;
     RECT  50.713 38.04 51.804 38.16 ;
     RECT  50.713 38.16 51.756 38.184 ;
     RECT  50.713 38.184 51.804 38.304 ;
     RECT  50.713 38.304 51.756 38.328 ;
     RECT  50.713 38.328 51.804 38.448 ;
     RECT  50.713 38.448 51.756 38.472 ;
     RECT  50.713 38.472 51.804 38.592 ;
     RECT  50.713 38.592 51.756 38.616 ;
     RECT  50.713 38.616 51.804 38.736 ;
     RECT  50.713 38.736 51.756 38.76 ;
     RECT  50.713 38.76 51.804 38.88 ;
     RECT  50.713 38.88 51.756 38.904 ;
     RECT  50.713 38.904 51.804 39.024 ;
     RECT  50.713 39.024 51.756 39.048 ;
     RECT  50.713 39.048 51.804 39.168 ;
     RECT  50.713 39.168 51.756 39.192 ;
     RECT  50.713 39.192 51.804 39.312 ;
     RECT  50.713 39.312 51.756 39.336 ;
     RECT  50.713 39.336 51.804 39.456 ;
     RECT  50.713 39.456 51.756 39.48 ;
     RECT  50.713 39.48 51.804 39.6 ;
     RECT  50.713 39.6 51.756 39.624 ;
     RECT  50.713 39.624 51.804 39.744 ;
     RECT  50.713 39.744 51.756 39.768 ;
     RECT  50.713 39.768 51.804 39.888 ;
     RECT  50.713 39.888 51.756 39.912 ;
     RECT  50.713 39.912 51.804 40.032 ;
     RECT  50.713 40.032 51.756 40.056 ;
     RECT  50.713 40.056 51.804 40.176 ;
     RECT  50.713 40.176 51.756 40.2 ;
     RECT  50.713 40.2 51.804 40.32 ;
     RECT  50.713 40.32 51.756 40.344 ;
     RECT  50.713 40.344 51.804 40.464 ;
     RECT  50.713 40.464 51.756 40.488 ;
     RECT  50.713 40.488 51.804 40.608 ;
     RECT  50.713 40.608 51.756 40.632 ;
     RECT  50.713 40.632 51.804 40.752 ;
     RECT  50.713 40.752 51.756 40.776 ;
     RECT  50.713 40.776 51.804 40.896 ;
     RECT  50.713 40.896 51.756 40.92 ;
     RECT  50.713 40.92 51.804 41.04 ;
     RECT  50.713 41.04 51.756 41.064 ;
     RECT  50.713 41.064 51.804 41.184 ;
     RECT  50.713 41.184 51.756 41.208 ;
     RECT  50.713 41.208 51.804 41.328 ;
     RECT  50.713 41.328 51.756 41.352 ;
     RECT  50.713 41.352 51.804 41.472 ;
     RECT  50.713 41.472 51.756 41.496 ;
     RECT  50.713 41.496 51.804 41.616 ;
     RECT  50.713 41.616 51.756 41.64 ;
     RECT  50.713 41.64 51.804 41.76 ;
     RECT  50.713 41.76 51.756 41.784 ;
     RECT  50.713 41.784 51.804 41.904 ;
     RECT  50.713 41.904 51.756 41.928 ;
     RECT  50.713 41.928 51.804 42.048 ;
     RECT  50.713 42.048 51.756 42.072 ;
     RECT  50.713 42.072 51.804 42.192 ;
     RECT  50.713 42.192 51.756 42.216 ;
     RECT  50.713 42.216 51.804 42.336 ;
     RECT  50.713 42.336 51.756 42.36 ;
     RECT  50.713 42.36 51.804 42.48 ;
     RECT  50.713 42.48 51.756 42.504 ;
     RECT  50.713 42.504 51.804 42.624 ;
     RECT  50.713 42.624 51.756 42.648 ;
     RECT  50.713 42.648 51.804 42.768 ;
     RECT  50.713 42.768 51.756 42.792 ;
     RECT  50.713 42.792 51.804 42.912 ;
     RECT  50.713 42.912 51.756 42.936 ;
     RECT  50.713 42.936 51.804 43.056 ;
     RECT  50.713 43.056 51.756 43.08 ;
     RECT  50.713 43.08 51.804 43.2 ;
     RECT  50.713 43.2 51.756 43.224 ;
     RECT  50.713 43.224 51.804 43.344 ;
     RECT  50.713 43.344 51.756 43.368 ;
     RECT  50.713 43.368 51.804 43.488 ;
     RECT  50.713 43.488 51.756 43.512 ;
     RECT  50.713 43.512 51.804 43.632 ;
     RECT  50.713 43.632 51.756 43.656 ;
     RECT  50.713 43.656 51.804 43.776 ;
     RECT  50.713 43.776 51.756 43.8 ;
     RECT  50.713 43.8 51.804 43.92 ;
     RECT  50.713 43.92 51.756 43.944 ;
     RECT  50.713 43.944 51.804 44.064 ;
     RECT  50.713 44.064 51.756 44.088 ;
     RECT  50.713 44.088 51.804 44.208 ;
     RECT  50.713 44.208 51.756 44.232 ;
     RECT  50.713 44.232 51.804 44.352 ;
     RECT  50.713 44.352 51.756 44.376 ;
     RECT  50.713 44.376 51.804 44.496 ;
     RECT  50.713 44.496 51.756 44.52 ;
     RECT  50.713 44.52 51.804 44.64 ;
     RECT  50.713 44.64 51.756 44.664 ;
     RECT  50.713 44.664 51.804 44.784 ;
     RECT  50.713 44.784 51.756 44.808 ;
     RECT  50.713 44.808 51.804 44.928 ;
     RECT  50.713 44.928 51.756 44.952 ;
     RECT  50.713 44.952 51.804 45.072 ;
     RECT  50.713 45.072 51.756 45.096 ;
     RECT  50.713 45.096 51.804 45.216 ;
     RECT  50.713 45.216 51.756 45.24 ;
     RECT  50.713 45.24 51.804 45.36 ;
     RECT  50.713 45.36 51.756 45.384 ;
     RECT  50.713 45.384 51.804 45.504 ;
     RECT  50.713 45.504 51.756 45.528 ;
     RECT  50.713 45.528 51.804 45.648 ;
     RECT  50.713 45.648 51.756 45.672 ;
     RECT  50.713 45.672 51.804 45.792 ;
     RECT  50.713 45.792 51.756 45.816 ;
     RECT  50.713 45.816 51.804 45.936 ;
     RECT  50.713 45.936 51.756 45.96 ;
     RECT  50.713 45.96 51.804 46.08 ;
     RECT  50.713 46.08 51.756 46.104 ;
     RECT  50.713 46.104 51.804 46.224 ;
     RECT  50.713 46.224 51.756 46.248 ;
     RECT  50.713 46.248 51.804 46.368 ;
     RECT  50.713 46.368 51.756 46.392 ;
     RECT  50.713 46.392 51.804 46.512 ;
     RECT  50.713 46.512 51.756 46.536 ;
     RECT  50.713 46.536 51.804 46.656 ;
     RECT  50.713 46.656 51.756 46.68 ;
     RECT  50.713 46.68 51.804 46.8 ;
     RECT  50.713 46.8 51.756 46.824 ;
     RECT  50.713 46.824 51.804 46.944 ;
     RECT  50.713 46.944 51.756 46.968 ;
     RECT  50.713 46.968 51.804 47.088 ;
     RECT  50.713 47.088 51.756 47.112 ;
     RECT  50.713 47.112 51.804 47.232 ;
     RECT  50.713 47.232 51.756 47.256 ;
     RECT  50.713 47.256 51.804 47.376 ;
     RECT  50.713 47.376 51.756 47.4 ;
     RECT  50.713 47.4 51.804 47.52 ;
     RECT  50.713 47.52 51.756 47.544 ;
     RECT  50.713 47.544 51.804 47.664 ;
     RECT  50.713 47.664 51.756 47.688 ;
     RECT  50.713 47.688 51.804 47.808 ;
     RECT  50.713 47.808 51.756 47.832 ;
     RECT  50.713 47.832 51.804 47.952 ;
     RECT  50.713 47.952 51.756 47.976 ;
     RECT  50.713 47.976 51.804 48.096 ;
     RECT  50.713 48.096 51.756 48.12 ;
     RECT  50.713 48.12 51.804 48.24 ;
     RECT  50.713 48.24 51.756 48.264 ;
     RECT  50.713 48.264 51.804 48.384 ;
     RECT  50.713 48.384 51.756 48.408 ;
     RECT  50.713 48.408 51.804 48.528 ;
     RECT  50.713 48.528 51.756 48.552 ;
    LAYER M5 ;
     RECT  14.568 0.016 14.688 0.084 ;
     RECT  14.712 0.016 14.832 0.084 ;
     RECT  14.856 0.016 14.976 0.084 ;
     RECT  15 0.016 15.12 0.084 ;
     RECT  15.144 0.016 15.264 0.084 ;
     RECT  15.288 0.016 15.408 0.084 ;
     RECT  15.432 0.016 15.552 0.084 ;
     RECT  15.576 0.016 15.696 0.084 ;
     RECT  15.72 0.016 15.84 0.084 ;
     RECT  15.864 0.016 15.984 0.084 ;
     RECT  16.008 0.016 16.128 0.084 ;
     RECT  16.152 0.016 16.272 0.084 ;
     RECT  16.296 0.016 16.416 0.084 ;
     RECT  16.44 0.016 16.56 0.084 ;
     RECT  16.584 0.016 16.704 0.084 ;
     RECT  16.728 0.016 16.848 0.084 ;
     RECT  16.872 0.016 16.992 0.084 ;
     RECT  17.016 0.016 17.136 0.084 ;
     RECT  17.16 0.016 17.28 0.084 ;
     RECT  17.304 0.016 17.424 0.084 ;
     RECT  17.448 0.016 17.568 0.084 ;
     RECT  17.592 0.016 17.712 0.084 ;
     RECT  17.736 0.016 17.856 0.084 ;
     RECT  17.88 0.016 18 0.084 ;
     RECT  18.024 0.016 18.144 0.084 ;
     RECT  18.168 0.016 18.288 0.084 ;
     RECT  18.312 0.016 18.432 0.084 ;
     RECT  18.456 0.016 18.576 0.084 ;
     RECT  18.6 0.016 18.72 0.084 ;
     RECT  18.744 0.016 19.152 0.084 ;
     RECT  19.176 0.016 19.296 0.084 ;
     RECT  19.32 0.016 19.44 0.084 ;
     RECT  19.464 0.016 19.584 0.084 ;
     RECT  19.608 0.016 19.728 0.084 ;
     RECT  19.752 0.016 19.872 0.084 ;
     RECT  19.896 0.016 20.016 0.084 ;
     RECT  20.04 0.016 20.16 0.084 ;
     RECT  20.184 0.016 20.304 0.084 ;
     RECT  20.328 0.016 20.448 0.084 ;
     RECT  20.472 0.016 20.592 0.084 ;
     RECT  20.616 0.016 20.736 0.084 ;
     RECT  20.76 0.016 20.88 0.084 ;
     RECT  20.904 0.016 21.024 0.084 ;
     RECT  21.048 0.016 21.168 0.084 ;
     RECT  21.192 0.016 21.312 0.084 ;
     RECT  21.336 0.016 21.456 0.084 ;
     RECT  21.48 0.016 21.6 0.084 ;
     RECT  21.624 0.016 21.744 0.084 ;
     RECT  21.768 0.016 21.888 0.084 ;
     RECT  21.912 0.016 22.032 0.084 ;
     RECT  22.056 0.016 22.176 0.084 ;
     RECT  22.2 0.016 22.32 0.084 ;
     RECT  22.344 0.016 22.464 0.084 ;
     RECT  22.488 0.016 22.608 0.084 ;
     RECT  22.632 0.016 22.752 0.084 ;
     RECT  22.776 0.016 22.896 0.084 ;
     RECT  22.92 0.016 23.04 0.084 ;
     RECT  23.064 0.016 23.184 0.084 ;
     RECT  23.208 0.016 23.328 0.084 ;
     RECT  23.352 0.016 23.472 0.084 ;
     RECT  23.496 0.016 23.616 0.084 ;
     RECT  23.64 0.016 23.76 0.084 ;
     RECT  23.784 0.016 23.904 0.084 ;
     RECT  23.928 0.016 24.048 0.084 ;
     RECT  24.072 0.016 24.192 0.084 ;
     RECT  24.216 0.016 24.336 0.084 ;
     RECT  24.36 0.016 24.48 0.084 ;
     RECT  24.504 0.016 24.624 0.084 ;
     RECT  24.648 0.016 24.768 0.084 ;
     RECT  24.792 0.016 24.912 0.084 ;
     RECT  24.936 0.016 25.056 0.084 ;
     RECT  25.08 0.016 25.2 0.084 ;
     RECT  25.224 0.016 25.344 0.084 ;
     RECT  25.368 0.016 25.488 0.084 ;
     RECT  25.512 0.016 25.632 0.084 ;
     RECT  25.656 0.016 25.776 0.084 ;
     RECT  25.8 0.016 25.92 0.084 ;
     RECT  25.944 0.016 26.064 0.084 ;
     RECT  26.088 0.016 26.208 0.084 ;
     RECT  26.232 0.016 26.352 0.084 ;
     RECT  26.376 0.016 26.496 0.084 ;
     RECT  26.52 0.016 26.64 0.084 ;
     RECT  26.664 0.016 26.784 0.084 ;
     RECT  26.808 0.016 26.928 0.084 ;
     RECT  26.952 0.016 27.072 0.084 ;
     RECT  27.096 0.016 27.216 0.084 ;
     RECT  27.24 0.016 27.36 0.084 ;
     RECT  27.384 0.016 27.504 0.084 ;
     RECT  27.528 0.016 27.648 0.084 ;
     RECT  27.672 0.016 27.792 0.084 ;
     RECT  27.816 0.016 27.936 0.084 ;
     RECT  27.96 0.016 28.08 0.084 ;
     RECT  28.104 0.016 28.224 0.084 ;
     RECT  14.544 0.084 28.248 1.763 ;
     RECT  29.544 0.016 29.664 0.084 ;
     RECT  29.688 0.016 29.808 0.084 ;
     RECT  29.832 0.016 29.952 0.084 ;
     RECT  29.976 0.016 30.096 0.084 ;
     RECT  30.12 0.016 30.24 0.084 ;
     RECT  30.264 0.016 30.384 0.084 ;
     RECT  30.408 0.016 30.528 0.084 ;
     RECT  30.552 0.016 30.672 0.084 ;
     RECT  30.696 0.016 30.816 0.084 ;
     RECT  30.84 0.016 30.96 0.084 ;
     RECT  30.984 0.016 31.104 0.084 ;
     RECT  31.128 0.016 31.248 0.084 ;
     RECT  31.272 0.016 31.392 0.084 ;
     RECT  31.416 0.016 31.536 0.084 ;
     RECT  31.56 0.016 31.68 0.084 ;
     RECT  31.704 0.016 31.824 0.084 ;
     RECT  31.848 0.016 31.968 0.084 ;
     RECT  31.992 0.016 32.112 0.084 ;
     RECT  32.136 0.016 32.256 0.084 ;
     RECT  32.28 0.016 32.4 0.084 ;
     RECT  32.424 0.016 32.544 0.084 ;
     RECT  32.568 0.016 32.688 0.084 ;
     RECT  32.712 0.016 32.832 0.084 ;
     RECT  32.856 0.016 32.976 0.084 ;
     RECT  33 0.016 33.12 0.084 ;
     RECT  33.144 0.016 33.264 0.084 ;
     RECT  33.288 0.016 33.408 0.084 ;
     RECT  33.432 0.016 33.552 0.084 ;
     RECT  33.576 0.016 33.696 0.084 ;
     RECT  33.72 0.016 33.84 0.084 ;
     RECT  33.864 0.016 33.984 0.084 ;
     RECT  34.008 0.016 34.128 0.084 ;
     RECT  34.152 0.016 34.272 0.084 ;
     RECT  34.296 0.016 34.416 0.084 ;
     RECT  34.44 0.016 34.56 0.084 ;
     RECT  34.584 0.016 34.704 0.084 ;
     RECT  34.728 0.016 34.848 0.084 ;
     RECT  34.872 0.016 34.992 0.084 ;
     RECT  35.016 0.016 35.136 0.084 ;
     RECT  35.16 0.016 35.28 0.084 ;
     RECT  35.304 0.016 35.424 0.084 ;
     RECT  35.448 0.016 35.568 0.084 ;
     RECT  35.592 0.016 35.712 0.084 ;
     RECT  35.736 0.016 35.856 0.084 ;
     RECT  35.88 0.016 36 0.084 ;
     RECT  36.024 0.016 36.144 0.084 ;
     RECT  36.168 0.016 36.288 0.084 ;
     RECT  36.312 0.016 36.432 0.084 ;
     RECT  36.456 0.016 36.576 0.084 ;
     RECT  36.6 0.016 36.72 0.084 ;
     RECT  36.744 0.016 36.864 0.084 ;
     RECT  36.888 0.016 37.008 0.084 ;
     RECT  37.032 0.016 37.152 0.084 ;
     RECT  37.176 0.016 37.296 0.084 ;
     RECT  37.32 0.016 37.44 0.084 ;
     RECT  37.464 0.016 37.584 0.084 ;
     RECT  37.608 0.016 37.728 0.084 ;
     RECT  37.752 0.016 37.872 0.084 ;
     RECT  37.896 0.016 38.016 0.084 ;
     RECT  38.04 0.016 38.16 0.084 ;
     RECT  38.184 0.016 38.304 0.084 ;
     RECT  38.328 0.016 38.448 0.084 ;
     RECT  38.472 0.016 38.592 0.084 ;
     RECT  38.616 0.016 38.736 0.084 ;
     RECT  38.76 0.016 38.88 0.084 ;
     RECT  38.904 0.016 39.024 0.084 ;
     RECT  39.048 0.016 39.168 0.084 ;
     RECT  39.192 0.016 39.312 0.084 ;
     RECT  39.336 0.016 39.456 0.084 ;
     RECT  39.48 0.016 39.6 0.084 ;
     RECT  39.624 0.016 39.744 0.084 ;
     RECT  39.768 0.016 39.888 0.084 ;
     RECT  39.912 0.016 40.032 0.084 ;
     RECT  40.056 0.016 40.176 0.084 ;
     RECT  40.2 0.016 40.32 0.084 ;
     RECT  40.344 0.016 40.464 0.084 ;
     RECT  40.488 0.016 40.608 0.084 ;
     RECT  40.632 0.016 40.752 0.084 ;
     RECT  40.776 0.016 40.896 0.084 ;
     RECT  40.92 0.016 41.04 0.084 ;
     RECT  41.064 0.016 41.184 0.084 ;
     RECT  41.208 0.016 41.328 0.084 ;
     RECT  41.352 0.016 41.472 0.084 ;
     RECT  41.496 0.016 41.616 0.084 ;
     RECT  41.64 0.016 41.76 0.084 ;
     RECT  41.784 0.016 41.904 0.084 ;
     RECT  41.928 0.016 42.048 0.084 ;
     RECT  42.072 0.016 42.192 0.084 ;
     RECT  42.216 0.016 42.336 0.084 ;
     RECT  42.36 0.016 42.48 0.084 ;
     RECT  42.504 0.016 42.624 0.084 ;
     RECT  42.648 0.016 42.768 0.084 ;
     RECT  42.792 0.016 42.912 0.084 ;
     RECT  42.936 0.016 43.056 0.084 ;
     RECT  43.08 0.016 43.2 0.084 ;
     RECT  43.224 0.016 43.344 0.084 ;
     RECT  43.368 0.016 43.488 0.084 ;
     RECT  43.512 0.016 43.632 0.084 ;
     RECT  43.656 0.016 43.776 0.084 ;
     RECT  43.8 0.016 43.92 0.084 ;
     RECT  43.944 0.016 44.064 0.084 ;
     RECT  44.088 0.016 44.208 0.084 ;
     RECT  44.232 0.016 44.352 0.084 ;
     RECT  44.376 0.016 44.496 0.084 ;
     RECT  44.52 0.016 44.64 0.084 ;
     RECT  44.664 0.016 44.784 0.084 ;
     RECT  44.808 0.016 44.928 0.084 ;
     RECT  44.952 0.016 45.072 0.084 ;
     RECT  45.096 0.016 45.216 0.084 ;
     RECT  45.24 0.016 45.36 0.084 ;
     RECT  45.384 0.016 45.504 0.084 ;
     RECT  45.528 0.016 45.648 0.084 ;
     RECT  45.672 0.016 45.792 0.084 ;
     RECT  45.816 0.016 45.936 0.084 ;
     RECT  45.96 0.016 46.08 0.084 ;
     RECT  46.104 0.016 46.224 0.084 ;
     RECT  46.248 0.016 46.368 0.084 ;
     RECT  46.392 0.016 46.512 0.084 ;
     RECT  46.536 0.016 46.656 0.084 ;
     RECT  46.68 0.016 46.8 0.084 ;
     RECT  46.824 0.016 46.944 0.084 ;
     RECT  46.968 0.016 47.088 0.084 ;
     RECT  47.112 0.016 47.232 0.084 ;
     RECT  47.256 0.016 47.376 0.084 ;
     RECT  47.4 0.016 47.52 0.084 ;
     RECT  47.544 0.016 47.664 0.084 ;
     RECT  47.688 0.016 47.808 0.084 ;
     RECT  29.52 0.084 47.832 1.763 ;
     RECT  29.52 1.763 29.712 2.137 ;
     RECT  2.4 2.137 2.52 2.151 ;
     RECT  7.8 2.137 7.92 2.151 ;
     RECT  13.2 2.137 13.32 2.151 ;
     RECT  4.512 2.341 4.536 2.531 ;
     RECT  0.144 4.213 0.168 4.499 ;
     RECT  7.8 2.151 8.112 4.837 ;
     RECT  7.104 4.837 8.112 5.987 ;
     RECT  7.8 5.987 8.112 6.325 ;
     RECT  45.6 1.763 45.912 6.613 ;
     RECT  5.184 3.925 5.208 6.805 ;
     RECT  18.6 1.763 18.912 6.805 ;
     RECT  45.408 6.613 45.912 7.189 ;
     RECT  24 1.763 24.312 7.669 ;
     RECT  45.408 7.189 46.008 7.763 ;
     RECT  24 7.669 24.408 7.909 ;
     RECT  16.224 6.661 16.248 8.195 ;
     RECT  13.2 2.151 13.512 8.389 ;
     RECT  5.184 6.805 5.736 8.435 ;
     RECT  16.848 8.533 16.872 8.675 ;
     RECT  21.12 7.957 21.144 8.819 ;
     RECT  7.8 6.325 9.096 9.013 ;
     RECT  13.2 8.389 13.608 9.013 ;
     RECT  18.6 6.805 19.32 9.059 ;
     RECT  12.96 9.013 13.608 9.301 ;
     RECT  5.184 8.435 5.208 9.397 ;
     RECT  6.24 8.581 6.264 9.539 ;
     RECT  22.224 7.765 22.248 9.731 ;
     RECT  45.408 7.763 45.912 10.069 ;
     RECT  4.512 9.397 5.208 10.307 ;
     RECT  17.472 9.109 17.496 10.355 ;
     RECT  12.96 9.301 14.424 11.123 ;
     RECT  18.6 9.059 18.912 11.317 ;
     RECT  21.216 9.637 21.24 11.363 ;
     RECT  4.512 10.307 4.536 11.365 ;
     RECT  21.024 11.557 21.048 11.701 ;
     RECT  20.928 11.701 21.048 11.747 ;
     RECT  24 7.909 24.504 11.941 ;
     RECT  4.512 11.365 5.496 12.035 ;
     RECT  18.432 11.317 18.912 12.035 ;
     RECT  17.04 11.941 17.064 12.037 ;
     RECT  17.04 12.037 17.208 12.323 ;
     RECT  13.104 11.123 14.424 12.371 ;
     RECT  17.04 12.323 17.112 12.517 ;
     RECT  15.648 10.789 15.672 12.563 ;
     RECT  16.944 12.517 17.112 13.091 ;
     RECT  17.088 13.091 17.112 13.235 ;
     RECT  24 11.941 24.552 13.715 ;
     RECT  13.2 12.371 14.424 13.909 ;
     RECT  18.6 12.035 18.912 14.389 ;
     RECT  2.4 2.151 2.712 14.629 ;
     RECT  7.8 9.013 9.24 14.773 ;
     RECT  2.304 14.629 2.712 14.819 ;
     RECT  46.944 14.197 46.968 14.915 ;
     RECT  13.104 13.909 14.424 15.539 ;
     RECT  5.472 12.035 5.496 15.829 ;
     RECT  5.232 15.829 5.496 15.875 ;
     RECT  6.912 14.773 9.24 15.925 ;
     RECT  22.752 15.301 22.776 16.021 ;
     RECT  24 13.715 24.504 16.021 ;
     RECT  6.912 15.925 9.672 16.259 ;
     RECT  22.752 16.021 24.504 16.261 ;
     RECT  20.928 11.747 20.952 16.307 ;
     RECT  17.232 15.397 17.256 16.309 ;
     RECT  17.04 16.309 17.256 16.451 ;
     RECT  22.752 16.261 25.128 16.501 ;
     RECT  22.752 16.501 25.368 16.547 ;
     RECT  2.4 14.819 2.712 16.789 ;
     RECT  18.6 14.389 19.416 16.837 ;
     RECT  2.304 16.789 2.712 16.979 ;
     RECT  7.392 16.259 9.672 17.075 ;
     RECT  17.232 16.451 17.256 17.123 ;
     RECT  18.6 16.837 19.752 17.123 ;
     RECT  13.2 15.539 14.424 17.171 ;
     RECT  15.456 15.925 15.48 17.267 ;
     RECT  7.392 17.075 9.096 17.603 ;
     RECT  22.752 16.547 22.776 17.603 ;
     RECT  24 16.547 24.312 17.701 ;
     RECT  25.344 16.547 25.368 17.701 ;
     RECT  42.624 14.389 42.648 18.275 ;
     RECT  43.68 17.077 43.704 18.275 ;
     RECT  47.328 16.789 47.352 18.275 ;
     RECT  44.784 10.069 45.912 18.851 ;
     RECT  44.88 18.851 45.912 19.093 ;
     RECT  5.232 15.875 5.256 19.333 ;
     RECT  44.88 19.093 46.248 20.195 ;
     RECT  5.232 19.333 5.736 20.579 ;
     RECT  5.232 20.579 5.496 20.917 ;
     RECT  4.512 20.917 5.496 22.163 ;
     RECT  45.6 20.195 46.248 22.259 ;
     RECT  45.6 22.259 46.2 22.741 ;
     RECT  44.976 22.741 46.2 22.979 ;
     RECT  44.976 22.979 45.912 23.555 ;
     RECT  7.8 17.603 9.096 25.283 ;
     RECT  24 17.701 25.368 25.955 ;
     RECT  45.6 23.555 45.912 26.005 ;
     RECT  5.472 22.163 5.496 27.971 ;
     RECT  42.576 28.453 42.6 29.699 ;
     RECT  6.768 29.029 6.792 30.275 ;
     RECT  47.472 28.405 47.496 30.323 ;
     RECT  45.6 26.005 46.104 34.165 ;
     RECT  7.8 25.283 8.424 34.309 ;
     RECT  45.6 34.165 46.2 34.739 ;
     RECT  4.608 29.941 4.632 34.741 ;
     RECT  4.608 34.741 5.4 34.787 ;
     RECT  7.68 34.309 8.424 35.317 ;
     RECT  45.6 34.739 46.104 35.939 ;
     RECT  7.056 35.317 8.424 35.987 ;
     RECT  47.232 35.029 47.256 37.043 ;
     RECT  24 25.955 24.312 38.677 ;
     RECT  25.344 25.955 25.368 38.677 ;
     RECT  24 38.677 25.368 38.723 ;
     RECT  34.8 1.763 35.112 38.725 ;
     RECT  24 38.723 25.128 38.819 ;
     RECT  13.2 17.171 13.512 39.205 ;
     RECT  12.528 39.205 13.512 39.733 ;
     RECT  5.376 34.787 5.4 39.779 ;
     RECT  42.48 39.253 42.504 39.923 ;
     RECT  48.432 39.301 48.456 39.923 ;
     RECT  45.6 35.939 46.008 40.163 ;
     RECT  2.4 16.979 2.712 40.261 ;
     RECT  2.4 40.261 2.808 40.403 ;
     RECT  18.6 17.123 18.912 41.365 ;
     RECT  2.4 40.403 2.712 41.557 ;
     RECT  42.576 40.117 43.224 41.747 ;
     RECT  2.4 41.557 3.288 42.467 ;
     RECT  7.8 35.987 8.424 42.803 ;
     RECT  29.4 2.137 29.712 43.285 ;
     RECT  7.8 42.803 8.376 43.379 ;
     RECT  48.048 42.133 48.072 43.523 ;
     RECT  45.6 40.163 45.912 44.437 ;
     RECT  12.24 39.733 13.512 44.869 ;
     RECT  18.6 41.365 19.128 44.917 ;
     RECT  17.568 44.437 17.592 44.965 ;
     RECT  18.6 44.917 19.896 44.965 ;
     RECT  45.6 44.437 46.488 45.011 ;
     RECT  7.8 43.379 8.112 45.205 ;
     RECT  29.088 43.285 29.712 45.253 ;
     RECT  34.656 38.725 35.112 45.253 ;
     RECT  7.8 45.205 8.376 45.541 ;
     RECT  34.656 45.253 35.208 45.589 ;
     RECT  27.216 45.541 27.24 45.637 ;
     RECT  12.24 44.869 14.136 45.877 ;
     RECT  15.12 45.541 16.008 45.877 ;
     RECT  36.528 45.829 36.552 45.925 ;
     RECT  27.216 45.637 27.816 46.309 ;
     RECT  29.088 45.253 30.696 46.309 ;
     RECT  36.528 45.925 36.888 46.403 ;
     RECT  24 38.819 24.312 46.501 ;
     RECT  36.864 46.403 36.888 46.501 ;
     RECT  12.24 45.877 16.008 46.645 ;
     RECT  7.8 45.541 8.52 46.693 ;
     RECT  27.216 46.309 30.696 46.741 ;
     RECT  4.512 42.421 4.536 46.787 ;
     RECT  12.24 46.645 16.536 46.787 ;
     RECT  32.544 45.973 32.568 46.787 ;
     RECT  40.2 1.763 40.512 46.789 ;
     RECT  9.936 46.501 9.96 47.317 ;
     RECT  16.512 46.787 16.536 47.363 ;
     RECT  27.216 46.741 31.176 47.749 ;
     RECT  12.24 46.787 15.144 47.843 ;
     RECT  24 46.501 24.456 47.845 ;
     RECT  27.216 47.749 31.848 47.893 ;
     RECT  43.2 41.747 43.224 47.987 ;
     RECT  17.568 44.965 19.896 48.373 ;
     RECT  34.416 45.589 35.304 48.469 ;
     RECT  36.864 46.501 37.032 48.469 ;
     RECT  34.416 48.469 37.032 48.853 ;
     RECT  6.048 47.797 6.072 48.901 ;
     RECT  26.352 47.893 31.848 48.901 ;
     RECT  33.12 47.893 33.144 48.901 ;
     RECT  26.352 48.901 33.144 48.949 ;
     RECT  34.416 48.853 37.608 48.949 ;
     RECT  9.936 47.317 10.104 48.997 ;
     RECT  17.424 48.373 19.896 48.997 ;
     RECT  21.312 48.421 21.336 48.997 ;
     RECT  26.352 48.949 37.608 48.997 ;
     RECT  39.984 46.789 40.512 48.997 ;
     RECT  9.936 48.997 10.536 49.045 ;
     RECT  26.064 48.997 38.04 49.045 ;
     RECT  12.384 47.843 15.144 49.093 ;
     RECT  26.064 49.045 38.76 49.093 ;
     RECT  39.984 48.997 40.632 49.093 ;
     RECT  26.064 49.093 40.632 49.333 ;
     RECT  17.424 48.997 22.2 49.381 ;
     RECT  7.632 46.693 8.52 49.429 ;
     RECT  9.648 49.045 11.4 49.429 ;
     RECT  25.632 49.333 41.496 49.429 ;
     RECT  5.328 48.901 6.072 49.525 ;
     RECT  7.632 49.429 11.4 49.525 ;
     RECT  12.384 49.093 15.864 49.525 ;
     RECT  17.28 49.381 22.2 49.525 ;
     RECT  23.616 47.845 24.456 49.525 ;
     RECT  25.632 49.429 41.64 49.525 ;
     RECT  2.4 42.467 2.712 49.689 ;
     RECT  45.6 45.011 45.912 49.689 ;
     RECT  2.4 49.689 2.52 49.703 ;
     RECT  45.6 49.689 45.72 49.703 ;
     RECT  4.176 48.997 4.2 50.101 ;
     RECT  5.328 49.525 22.2 50.101 ;
     RECT  4.176 50.101 22.2 50.149 ;
     RECT  23.328 49.525 41.64 50.149 ;
     RECT  4.032 50.149 22.2 50.677 ;
     RECT  3.888 50.677 22.2 51.756 ;
     RECT  3.912 51.756 4.032 51.792 ;
     RECT  4.056 51.756 4.176 51.792 ;
     RECT  4.2 51.756 4.32 51.792 ;
     RECT  4.344 51.756 4.464 51.792 ;
     RECT  4.488 51.756 4.608 51.792 ;
     RECT  4.632 51.756 4.752 51.792 ;
     RECT  4.776 51.756 4.896 51.792 ;
     RECT  4.92 51.756 5.04 51.792 ;
     RECT  5.064 51.756 5.184 51.792 ;
     RECT  5.208 51.756 5.328 51.792 ;
     RECT  5.352 51.756 5.472 51.792 ;
     RECT  5.496 51.756 5.616 51.792 ;
     RECT  5.64 51.756 5.76 51.792 ;
     RECT  5.784 51.756 5.904 51.792 ;
     RECT  5.928 51.756 6.048 51.792 ;
     RECT  6.072 51.756 6.192 51.792 ;
     RECT  6.216 51.756 6.336 51.792 ;
     RECT  6.36 51.756 6.48 51.792 ;
     RECT  6.504 51.756 6.624 51.792 ;
     RECT  6.648 51.756 6.768 51.792 ;
     RECT  6.792 51.756 6.912 51.792 ;
     RECT  6.936 51.756 7.056 51.792 ;
     RECT  7.08 51.756 7.2 51.792 ;
     RECT  7.224 51.756 7.344 51.792 ;
     RECT  7.368 51.756 7.488 51.792 ;
     RECT  7.512 51.756 7.632 51.792 ;
     RECT  7.656 51.756 7.776 51.792 ;
     RECT  7.8 51.756 7.92 51.792 ;
     RECT  7.944 51.756 8.064 51.792 ;
     RECT  8.088 51.756 8.208 51.792 ;
     RECT  8.232 51.756 8.352 51.792 ;
     RECT  8.376 51.756 8.496 51.792 ;
     RECT  8.52 51.756 8.64 51.792 ;
     RECT  8.664 51.756 8.784 51.792 ;
     RECT  8.808 51.756 8.928 51.792 ;
     RECT  8.952 51.756 9.072 51.792 ;
     RECT  9.096 51.756 9.216 51.792 ;
     RECT  9.24 51.756 9.36 51.792 ;
     RECT  9.384 51.756 9.504 51.792 ;
     RECT  9.528 51.756 9.648 51.792 ;
     RECT  9.672 51.756 9.792 51.792 ;
     RECT  9.816 51.756 9.936 51.792 ;
     RECT  9.96 51.756 10.08 51.792 ;
     RECT  10.104 51.756 10.224 51.792 ;
     RECT  10.248 51.756 10.368 51.792 ;
     RECT  10.392 51.756 10.512 51.792 ;
     RECT  10.536 51.756 10.656 51.792 ;
     RECT  10.68 51.756 10.8 51.792 ;
     RECT  10.824 51.756 10.944 51.792 ;
     RECT  10.968 51.756 11.088 51.792 ;
     RECT  11.112 51.756 11.232 51.792 ;
     RECT  11.256 51.756 11.376 51.792 ;
     RECT  11.4 51.756 11.52 51.792 ;
     RECT  11.544 51.756 11.664 51.792 ;
     RECT  11.688 51.756 11.808 51.792 ;
     RECT  11.832 51.756 11.952 51.792 ;
     RECT  11.976 51.756 12.096 51.792 ;
     RECT  12.12 51.756 12.24 51.792 ;
     RECT  12.264 51.756 12.384 51.792 ;
     RECT  12.408 51.756 12.528 51.792 ;
     RECT  12.552 51.756 12.672 51.792 ;
     RECT  12.696 51.756 12.816 51.792 ;
     RECT  12.84 51.756 12.96 51.792 ;
     RECT  12.984 51.756 13.104 51.792 ;
     RECT  13.128 51.756 13.248 51.792 ;
     RECT  13.272 51.756 13.392 51.792 ;
     RECT  13.416 51.756 13.536 51.792 ;
     RECT  13.56 51.756 13.68 51.792 ;
     RECT  13.704 51.756 13.824 51.792 ;
     RECT  13.848 51.756 13.968 51.792 ;
     RECT  13.992 51.756 14.112 51.792 ;
     RECT  14.136 51.756 14.256 51.792 ;
     RECT  14.28 51.756 14.4 51.792 ;
     RECT  14.424 51.756 14.544 51.792 ;
     RECT  14.568 51.756 14.688 51.792 ;
     RECT  14.712 51.756 14.832 51.792 ;
     RECT  14.856 51.756 14.976 51.792 ;
     RECT  15 51.756 15.12 51.792 ;
     RECT  15.144 51.756 15.264 51.792 ;
     RECT  15.288 51.756 15.408 51.792 ;
     RECT  15.432 51.756 15.552 51.792 ;
     RECT  15.576 51.756 15.696 51.792 ;
     RECT  15.72 51.756 15.84 51.792 ;
     RECT  15.864 51.756 15.984 51.792 ;
     RECT  16.008 51.756 16.128 51.792 ;
     RECT  16.152 51.756 16.272 51.792 ;
     RECT  16.296 51.756 16.416 51.792 ;
     RECT  16.44 51.756 16.56 51.792 ;
     RECT  16.584 51.756 16.704 51.792 ;
     RECT  16.728 51.756 16.848 51.792 ;
     RECT  16.872 51.756 16.992 51.792 ;
     RECT  17.016 51.756 17.136 51.792 ;
     RECT  17.16 51.756 17.28 51.792 ;
     RECT  17.304 51.756 17.424 51.792 ;
     RECT  17.448 51.756 17.568 51.792 ;
     RECT  17.592 51.756 17.712 51.792 ;
     RECT  17.736 51.756 17.856 51.792 ;
     RECT  17.88 51.756 18 51.792 ;
     RECT  18.024 51.756 18.144 51.792 ;
     RECT  18.168 51.756 18.288 51.792 ;
     RECT  18.312 51.756 18.432 51.792 ;
     RECT  18.456 51.756 18.576 51.792 ;
     RECT  18.6 51.756 18.72 51.792 ;
     RECT  18.744 51.756 18.864 51.792 ;
     RECT  18.888 51.756 19.008 51.792 ;
     RECT  19.032 51.756 19.152 51.792 ;
     RECT  19.176 51.756 19.296 51.792 ;
     RECT  19.32 51.756 19.44 51.792 ;
     RECT  19.464 51.756 19.584 51.792 ;
     RECT  19.608 51.756 19.728 51.792 ;
     RECT  19.752 51.756 19.872 51.792 ;
     RECT  19.896 51.756 20.016 51.792 ;
     RECT  20.04 51.756 20.16 51.792 ;
     RECT  20.184 51.756 20.304 51.792 ;
     RECT  20.328 51.756 20.448 51.792 ;
     RECT  20.472 51.756 20.592 51.792 ;
     RECT  20.616 51.756 20.736 51.792 ;
     RECT  20.76 51.756 20.88 51.792 ;
     RECT  20.904 51.756 21.024 51.792 ;
     RECT  21.048 51.756 21.168 51.792 ;
     RECT  21.192 51.756 21.312 51.792 ;
     RECT  21.336 51.756 21.456 51.792 ;
     RECT  21.48 51.756 21.6 51.792 ;
     RECT  21.624 51.756 21.744 51.792 ;
     RECT  21.768 51.756 21.888 51.792 ;
     RECT  21.912 51.756 22.032 51.792 ;
     RECT  22.056 51.756 22.176 51.792 ;
     RECT  23.328 50.149 41.784 51.756 ;
     RECT  23.352 51.756 23.472 51.792 ;
     RECT  23.496 51.756 23.616 51.792 ;
     RECT  23.64 51.756 23.76 51.792 ;
     RECT  23.784 51.756 23.904 51.792 ;
     RECT  23.928 51.756 24.048 51.792 ;
     RECT  24.072 51.756 24.192 51.792 ;
     RECT  24.216 51.756 24.336 51.792 ;
     RECT  24.36 51.756 24.48 51.792 ;
     RECT  24.504 51.756 24.624 51.792 ;
     RECT  24.648 51.756 24.768 51.792 ;
     RECT  24.792 51.756 24.912 51.792 ;
     RECT  24.936 51.756 25.056 51.792 ;
     RECT  25.08 51.756 25.2 51.792 ;
     RECT  25.224 51.756 25.344 51.792 ;
     RECT  25.368 51.756 25.488 51.792 ;
     RECT  25.512 51.756 25.632 51.792 ;
     RECT  25.656 51.756 25.776 51.792 ;
     RECT  25.8 51.756 25.92 51.792 ;
     RECT  25.944 51.756 26.064 51.792 ;
     RECT  26.088 51.756 26.208 51.792 ;
     RECT  26.232 51.756 26.352 51.792 ;
     RECT  26.376 51.756 26.496 51.792 ;
     RECT  26.52 51.756 26.64 51.792 ;
     RECT  26.664 51.756 26.784 51.792 ;
     RECT  26.808 51.756 26.928 51.792 ;
     RECT  26.952 51.756 27.072 51.792 ;
     RECT  27.096 51.756 27.216 51.792 ;
     RECT  27.24 51.756 27.36 51.792 ;
     RECT  27.384 51.756 27.504 51.792 ;
     RECT  27.528 51.756 27.648 51.792 ;
     RECT  27.672 51.756 27.792 51.792 ;
     RECT  27.816 51.756 27.936 51.792 ;
     RECT  27.96 51.756 28.08 51.792 ;
     RECT  28.104 51.756 28.224 51.792 ;
     RECT  28.248 51.756 28.368 51.792 ;
     RECT  28.392 51.756 28.512 51.792 ;
     RECT  28.536 51.756 28.656 51.792 ;
     RECT  28.68 51.756 28.8 51.792 ;
     RECT  28.824 51.756 28.944 51.792 ;
     RECT  28.968 51.756 29.088 51.792 ;
     RECT  29.112 51.756 29.232 51.792 ;
     RECT  29.256 51.756 29.376 51.792 ;
     RECT  29.4 51.756 29.52 51.792 ;
     RECT  29.544 51.756 29.664 51.792 ;
     RECT  29.688 51.756 29.808 51.792 ;
     RECT  29.832 51.756 29.952 51.792 ;
     RECT  29.976 51.756 30.096 51.792 ;
     RECT  30.12 51.756 30.24 51.792 ;
     RECT  30.264 51.756 30.384 51.792 ;
     RECT  30.408 51.756 30.528 51.792 ;
     RECT  30.552 51.756 30.672 51.792 ;
     RECT  30.696 51.756 30.816 51.792 ;
     RECT  30.84 51.756 30.96 51.792 ;
     RECT  30.984 51.756 31.104 51.792 ;
     RECT  31.128 51.756 31.248 51.792 ;
     RECT  31.272 51.756 31.392 51.792 ;
     RECT  31.416 51.756 31.536 51.792 ;
     RECT  31.56 51.756 31.68 51.792 ;
     RECT  31.704 51.756 31.824 51.792 ;
     RECT  31.848 51.756 31.968 51.792 ;
     RECT  31.992 51.756 32.112 51.792 ;
     RECT  32.136 51.756 32.256 51.792 ;
     RECT  32.28 51.756 32.4 51.792 ;
     RECT  32.424 51.756 32.544 51.792 ;
     RECT  32.568 51.756 32.688 51.792 ;
     RECT  32.712 51.756 32.832 51.792 ;
     RECT  32.856 51.756 32.976 51.792 ;
     RECT  33 51.756 33.12 51.792 ;
     RECT  33.144 51.756 33.264 51.792 ;
     RECT  33.288 51.756 33.408 51.792 ;
     RECT  33.432 51.756 33.552 51.792 ;
     RECT  33.576 51.756 33.696 51.792 ;
     RECT  33.72 51.756 33.84 51.792 ;
     RECT  33.864 51.756 33.984 51.792 ;
     RECT  34.008 51.756 34.128 51.792 ;
     RECT  34.152 51.756 34.272 51.792 ;
     RECT  34.296 51.756 34.416 51.792 ;
     RECT  34.44 51.756 34.56 51.792 ;
     RECT  34.584 51.756 34.704 51.792 ;
     RECT  34.728 51.756 34.848 51.792 ;
     RECT  34.872 51.756 34.992 51.792 ;
     RECT  35.016 51.756 35.136 51.792 ;
     RECT  35.16 51.756 35.28 51.792 ;
     RECT  35.304 51.756 35.424 51.792 ;
     RECT  35.448 51.756 35.568 51.792 ;
     RECT  35.592 51.756 35.712 51.792 ;
     RECT  35.736 51.756 35.856 51.792 ;
     RECT  35.88 51.756 36 51.792 ;
     RECT  36.024 51.756 36.144 51.792 ;
     RECT  36.168 51.756 36.288 51.792 ;
     RECT  36.312 51.756 36.432 51.792 ;
     RECT  36.456 51.756 36.576 51.792 ;
     RECT  36.6 51.756 36.72 51.792 ;
     RECT  36.744 51.756 36.864 51.792 ;
     RECT  36.888 51.756 37.008 51.792 ;
     RECT  37.032 51.756 37.152 51.792 ;
     RECT  37.176 51.756 37.296 51.792 ;
     RECT  37.32 51.756 37.44 51.792 ;
     RECT  37.464 51.756 37.584 51.792 ;
     RECT  37.608 51.756 37.728 51.792 ;
     RECT  37.752 51.756 37.872 51.792 ;
     RECT  37.896 51.756 38.016 51.792 ;
     RECT  38.04 51.756 38.16 51.792 ;
     RECT  38.184 51.756 38.304 51.792 ;
     RECT  38.328 51.756 38.448 51.792 ;
     RECT  38.472 51.756 38.592 51.792 ;
     RECT  38.616 51.756 38.736 51.792 ;
     RECT  38.76 51.756 38.88 51.792 ;
     RECT  38.904 51.756 39.024 51.792 ;
     RECT  39.048 51.756 39.168 51.792 ;
     RECT  39.192 51.756 39.312 51.792 ;
     RECT  39.336 51.756 39.456 51.792 ;
     RECT  39.48 51.756 39.6 51.792 ;
     RECT  39.624 51.756 39.744 51.792 ;
     RECT  39.768 51.756 39.888 51.792 ;
     RECT  39.912 51.756 40.032 51.792 ;
     RECT  40.056 51.756 40.176 51.792 ;
     RECT  40.2 51.756 40.32 51.792 ;
     RECT  40.344 51.756 40.464 51.792 ;
     RECT  40.488 51.756 40.608 51.792 ;
     RECT  40.632 51.756 40.752 51.792 ;
     RECT  40.776 51.756 40.896 51.792 ;
     RECT  40.92 51.756 41.04 51.792 ;
     RECT  41.064 51.756 41.184 51.792 ;
     RECT  41.208 51.756 41.328 51.792 ;
     RECT  41.352 51.756 41.472 51.792 ;
     RECT  41.496 51.756 41.616 51.792 ;
     RECT  41.64 51.756 41.76 51.792 ;
     RECT  28.296 0.016 29.472 0.132 ;
     RECT  28.248 0.132 29.52 1.763 ;
     RECT  29.4 1.763 29.52 2.137 ;
     RECT  21.144 7.957 22.224 8.819 ;
     RECT  5.208 8.435 5.736 8.581 ;
     RECT  5.208 8.581 6.24 9.539 ;
     RECT  21.216 8.819 22.224 9.637 ;
     RECT  17.496 9.109 18.6 10.355 ;
     RECT  21.24 9.637 22.224 9.731 ;
     RECT  4.536 10.307 5.208 11.365 ;
     RECT  18.432 10.355 18.6 11.317 ;
     RECT  14.424 10.789 15.648 12.563 ;
     RECT  15.672 11.941 17.04 12.517 ;
     RECT  17.064 11.941 18.432 12.035 ;
     RECT  17.064 12.035 18.6 12.037 ;
     RECT  17.208 12.037 18.6 12.323 ;
     RECT  17.112 12.323 18.6 13.235 ;
     RECT  15.672 12.517 16.944 12.563 ;
     RECT  45.912 14.197 46.944 14.915 ;
     RECT  19.416 14.389 20.928 16.307 ;
     RECT  5.496 14.773 6.912 15.875 ;
     RECT  22.776 15.301 24 16.021 ;
     RECT  17.256 15.397 18.6 17.123 ;
     RECT  14.424 15.925 15.456 17.171 ;
     RECT  19.416 16.307 19.752 16.837 ;
     RECT  22.776 16.547 24 17.603 ;
     RECT  24.312 16.547 25.344 17.701 ;
     RECT  45.912 16.789 47.328 18.275 ;
     RECT  42.648 17.077 43.68 18.275 ;
     RECT  43.704 17.077 44.784 18.275 ;
     RECT  45.912 18.275 46.248 19.093 ;
     RECT  24.312 25.955 25.344 38.677 ;
     RECT  46.104 28.405 47.472 30.323 ;
     RECT  6.792 29.029 7.8 30.275 ;
     RECT  46.104 34.739 46.2 35.029 ;
     RECT  46.104 35.029 47.232 35.939 ;
     RECT  46.008 35.939 47.232 37.043 ;
     RECT  2.712 40.403 2.808 41.557 ;
     RECT  3.288 42.421 4.512 42.467 ;
     RECT  17.592 44.437 18.6 44.965 ;
     RECT  14.136 45.541 15.12 45.877 ;
     RECT  27.816 45.637 29.088 46.309 ;
     RECT  35.304 45.829 36.528 46.403 ;
     RECT  8.52 46.501 9.936 49.045 ;
     RECT  16.536 46.645 17.568 47.363 ;
     RECT  31.176 46.741 32.544 46.787 ;
     RECT  15.144 46.787 16.512 47.363 ;
     RECT  31.176 46.787 32.568 47.749 ;
     RECT  17.424 47.363 17.568 48.373 ;
     RECT  31.848 47.749 32.568 47.893 ;
     RECT  12.24 47.843 12.384 49.045 ;
     RECT  31.848 47.893 33.12 48.901 ;
     RECT  33.144 47.893 34.416 48.949 ;
     RECT  19.896 48.421 21.312 48.997 ;
     RECT  2.712 48.997 4.176 49.689 ;
     RECT  4.2 48.997 5.328 50.101 ;
     RECT  22.2 48.997 23.616 49.525 ;
     RECT  8.52 49.045 9.648 49.429 ;
     RECT  11.4 49.045 12.384 49.525 ;
     RECT  38.76 49.045 39.984 49.093 ;
     RECT  24.456 49.333 25.632 49.525 ;
     RECT  15.864 49.381 17.28 49.525 ;
     RECT  22.2 49.525 23.328 51.708 ;
     RECT  2.52 49.689 4.176 49.703 ;
     RECT  3.888 49.703 4.176 50.149 ;
     RECT  3.888 50.149 4.032 50.677 ;
     RECT  22.248 51.708 23.28 51.792 ;
  END
END ot_hbm_static_cfg_collar
END LIBRARY
